VERSION 5.8 ;
BUSBITCHARS "[]" ;
DIVIDERCHAR "/" ;
UNITS
    DATABASE MICRONS 1000 ;
END UNITS

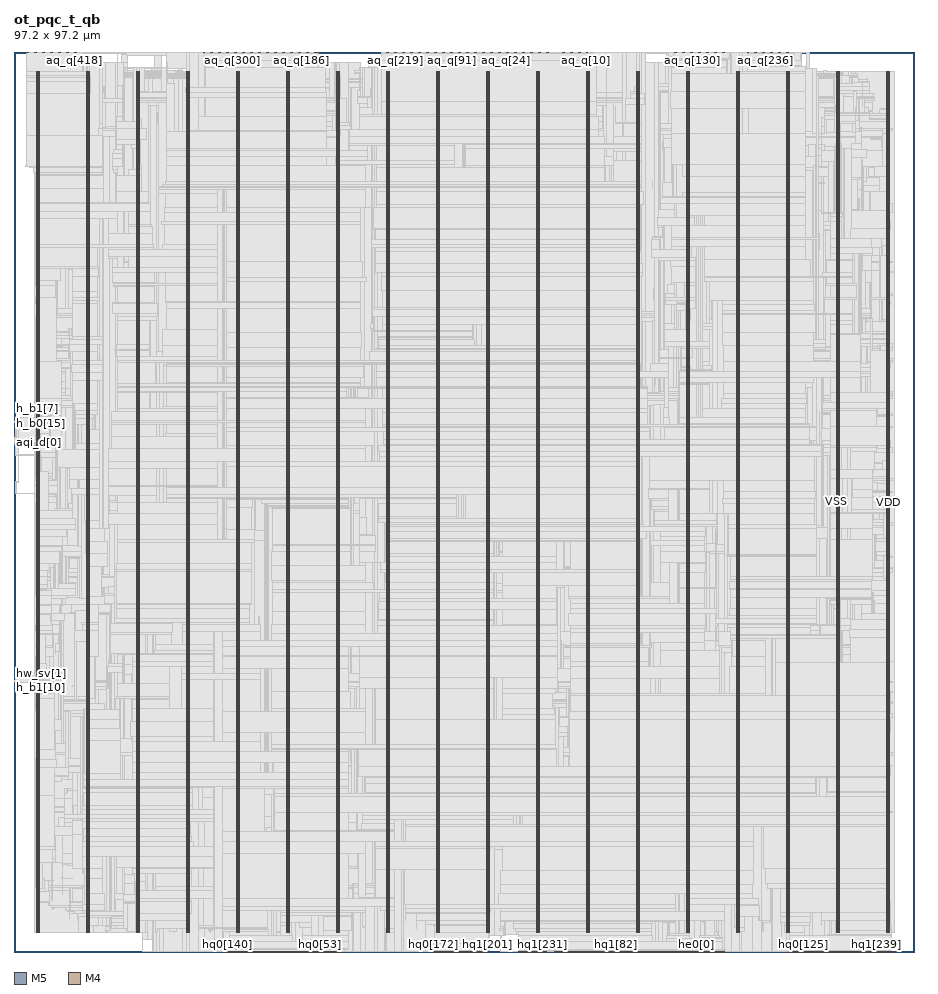
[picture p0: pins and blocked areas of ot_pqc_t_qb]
MACRO ot_pqc_t_qb
  FOREIGN ot_pqc_t_qb 0 0 ;
  CLASS BLOCK ;
  SIZE 97.2 BY 97.2 ;
  PIN aq_e[0]
    DIRECTION INPUT ;
    USE SIGNAL ;
    PORT
      LAYER M5 ;
        RECT  58.896 97.116 58.92 97.2 ;
    END
  END aq_e[0]
  PIN aq_e[10]
    DIRECTION INPUT ;
    USE SIGNAL ;
    PORT
      LAYER M5 ;
        RECT  59.856 97.116 59.88 97.2 ;
    END
  END aq_e[10]
  PIN aq_e[11]
    DIRECTION INPUT ;
    USE SIGNAL ;
    PORT
      LAYER M5 ;
        RECT  59.952 97.116 59.976 97.2 ;
    END
  END aq_e[11]
  PIN aq_e[12]
    DIRECTION INPUT ;
    USE SIGNAL ;
    PORT
      LAYER M5 ;
        RECT  60.048 97.116 60.072 97.2 ;
    END
  END aq_e[12]
  PIN aq_e[13]
    DIRECTION INPUT ;
    USE SIGNAL ;
    PORT
      LAYER M5 ;
        RECT  60.144 97.116 60.168 97.2 ;
    END
  END aq_e[13]
  PIN aq_e[14]
    DIRECTION INPUT ;
    USE SIGNAL ;
    PORT
      LAYER M5 ;
        RECT  60.24 97.116 60.264 97.2 ;
    END
  END aq_e[14]
  PIN aq_e[15]
    DIRECTION INPUT ;
    USE SIGNAL ;
    PORT
      LAYER M5 ;
        RECT  60.336 97.116 60.36 97.2 ;
    END
  END aq_e[15]
  PIN aq_e[16]
    DIRECTION INPUT ;
    USE SIGNAL ;
    PORT
      LAYER M5 ;
        RECT  60.432 97.116 60.456 97.2 ;
    END
  END aq_e[16]
  PIN aq_e[17]
    DIRECTION INPUT ;
    USE SIGNAL ;
    PORT
      LAYER M5 ;
        RECT  60.528 97.116 60.552 97.2 ;
    END
  END aq_e[17]
  PIN aq_e[18]
    DIRECTION INPUT ;
    USE SIGNAL ;
    PORT
      LAYER M5 ;
        RECT  60.624 97.116 60.648 97.2 ;
    END
  END aq_e[18]
  PIN aq_e[19]
    DIRECTION INPUT ;
    USE SIGNAL ;
    PORT
      LAYER M5 ;
        RECT  60.72 97.116 60.744 97.2 ;
    END
  END aq_e[19]
  PIN aq_e[1]
    DIRECTION INPUT ;
    USE SIGNAL ;
    PORT
      LAYER M5 ;
        RECT  58.992 97.116 59.016 97.2 ;
    END
  END aq_e[1]
  PIN aq_e[2]
    DIRECTION INPUT ;
    USE SIGNAL ;
    PORT
      LAYER M5 ;
        RECT  59.088 97.116 59.112 97.2 ;
    END
  END aq_e[2]
  PIN aq_e[3]
    DIRECTION INPUT ;
    USE SIGNAL ;
    PORT
      LAYER M5 ;
        RECT  59.184 97.116 59.208 97.2 ;
    END
  END aq_e[3]
  PIN aq_e[4]
    DIRECTION INPUT ;
    USE SIGNAL ;
    PORT
      LAYER M5 ;
        RECT  59.28 97.116 59.304 97.2 ;
    END
  END aq_e[4]
  PIN aq_e[5]
    DIRECTION INPUT ;
    USE SIGNAL ;
    PORT
      LAYER M5 ;
        RECT  59.376 97.116 59.4 97.2 ;
    END
  END aq_e[5]
  PIN aq_e[6]
    DIRECTION INPUT ;
    USE SIGNAL ;
    PORT
      LAYER M5 ;
        RECT  59.472 97.116 59.496 97.2 ;
    END
  END aq_e[6]
  PIN aq_e[7]
    DIRECTION INPUT ;
    USE SIGNAL ;
    PORT
      LAYER M5 ;
        RECT  59.568 97.116 59.592 97.2 ;
    END
  END aq_e[7]
  PIN aq_e[8]
    DIRECTION INPUT ;
    USE SIGNAL ;
    PORT
      LAYER M5 ;
        RECT  59.664 97.116 59.688 97.2 ;
    END
  END aq_e[8]
  PIN aq_e[9]
    DIRECTION INPUT ;
    USE SIGNAL ;
    PORT
      LAYER M5 ;
        RECT  59.76 97.116 59.784 97.2 ;
    END
  END aq_e[9]
  PIN aq_q[0]
    DIRECTION INPUT ;
    USE SIGNAL ;
    PORT
      LAYER M5 ;
        RECT  60.816 97.116 60.84 97.2 ;
    END
  END aq_q[0]
  PIN aq_q[100]
    DIRECTION INPUT ;
    USE SIGNAL ;
    PORT
      LAYER M5 ;
        RECT  48.144 97.116 48.168 97.2 ;
    END
  END aq_q[100]
  PIN aq_q[101]
    DIRECTION INPUT ;
    USE SIGNAL ;
    PORT
      LAYER M5 ;
        RECT  48.24 97.116 48.264 97.2 ;
    END
  END aq_q[101]
  PIN aq_q[102]
    DIRECTION INPUT ;
    USE SIGNAL ;
    PORT
      LAYER M5 ;
        RECT  48.336 97.116 48.36 97.2 ;
    END
  END aq_q[102]
  PIN aq_q[103]
    DIRECTION INPUT ;
    USE SIGNAL ;
    PORT
      LAYER M5 ;
        RECT  48.432 97.116 48.456 97.2 ;
    END
  END aq_q[103]
  PIN aq_q[104]
    DIRECTION INPUT ;
    USE SIGNAL ;
    PORT
      LAYER M5 ;
        RECT  48.528 97.116 48.552 97.2 ;
    END
  END aq_q[104]
  PIN aq_q[105]
    DIRECTION INPUT ;
    USE SIGNAL ;
    PORT
      LAYER M5 ;
        RECT  48.624 97.116 48.648 97.2 ;
    END
  END aq_q[105]
  PIN aq_q[106]
    DIRECTION INPUT ;
    USE SIGNAL ;
    PORT
      LAYER M5 ;
        RECT  48.72 97.116 48.744 97.2 ;
    END
  END aq_q[106]
  PIN aq_q[107]
    DIRECTION INPUT ;
    USE SIGNAL ;
    PORT
      LAYER M5 ;
        RECT  48.816 97.116 48.84 97.2 ;
    END
  END aq_q[107]
  PIN aq_q[108]
    DIRECTION INPUT ;
    USE SIGNAL ;
    PORT
      LAYER M5 ;
        RECT  71.184 97.116 71.208 97.2 ;
    END
  END aq_q[108]
  PIN aq_q[109]
    DIRECTION INPUT ;
    USE SIGNAL ;
    PORT
      LAYER M5 ;
        RECT  71.28 97.116 71.304 97.2 ;
    END
  END aq_q[109]
  PIN aq_q[10]
    DIRECTION INPUT ;
    USE SIGNAL ;
    PORT
      LAYER M5 ;
        RECT  61.776 97.116 61.8 97.2 ;
    END
  END aq_q[10]
  PIN aq_q[110]
    DIRECTION INPUT ;
    USE SIGNAL ;
    PORT
      LAYER M5 ;
        RECT  71.376 97.116 71.4 97.2 ;
    END
  END aq_q[110]
  PIN aq_q[111]
    DIRECTION INPUT ;
    USE SIGNAL ;
    PORT
      LAYER M5 ;
        RECT  71.472 97.116 71.496 97.2 ;
    END
  END aq_q[111]
  PIN aq_q[112]
    DIRECTION INPUT ;
    USE SIGNAL ;
    PORT
      LAYER M5 ;
        RECT  71.568 97.116 71.592 97.2 ;
    END
  END aq_q[112]
  PIN aq_q[113]
    DIRECTION INPUT ;
    USE SIGNAL ;
    PORT
      LAYER M5 ;
        RECT  71.664 97.116 71.688 97.2 ;
    END
  END aq_q[113]
  PIN aq_q[114]
    DIRECTION INPUT ;
    USE SIGNAL ;
    PORT
      LAYER M5 ;
        RECT  71.76 97.116 71.784 97.2 ;
    END
  END aq_q[114]
  PIN aq_q[115]
    DIRECTION INPUT ;
    USE SIGNAL ;
    PORT
      LAYER M5 ;
        RECT  71.856 97.116 71.88 97.2 ;
    END
  END aq_q[115]
  PIN aq_q[116]
    DIRECTION INPUT ;
    USE SIGNAL ;
    PORT
      LAYER M5 ;
        RECT  71.952 97.116 71.976 97.2 ;
    END
  END aq_q[116]
  PIN aq_q[117]
    DIRECTION INPUT ;
    USE SIGNAL ;
    PORT
      LAYER M5 ;
        RECT  72.048 97.116 72.072 97.2 ;
    END
  END aq_q[117]
  PIN aq_q[118]
    DIRECTION INPUT ;
    USE SIGNAL ;
    PORT
      LAYER M5 ;
        RECT  72.144 97.116 72.168 97.2 ;
    END
  END aq_q[118]
  PIN aq_q[119]
    DIRECTION INPUT ;
    USE SIGNAL ;
    PORT
      LAYER M5 ;
        RECT  72.24 97.116 72.264 97.2 ;
    END
  END aq_q[119]
  PIN aq_q[11]
    DIRECTION INPUT ;
    USE SIGNAL ;
    PORT
      LAYER M5 ;
        RECT  61.872 97.116 61.896 97.2 ;
    END
  END aq_q[11]
  PIN aq_q[120]
    DIRECTION INPUT ;
    USE SIGNAL ;
    PORT
      LAYER M5 ;
        RECT  72.336 97.116 72.36 97.2 ;
    END
  END aq_q[120]
  PIN aq_q[121]
    DIRECTION INPUT ;
    USE SIGNAL ;
    PORT
      LAYER M5 ;
        RECT  72.432 97.116 72.456 97.2 ;
    END
  END aq_q[121]
  PIN aq_q[122]
    DIRECTION INPUT ;
    USE SIGNAL ;
    PORT
      LAYER M5 ;
        RECT  72.528 97.116 72.552 97.2 ;
    END
  END aq_q[122]
  PIN aq_q[123]
    DIRECTION INPUT ;
    USE SIGNAL ;
    PORT
      LAYER M5 ;
        RECT  72.624 97.116 72.648 97.2 ;
    END
  END aq_q[123]
  PIN aq_q[124]
    DIRECTION INPUT ;
    USE SIGNAL ;
    PORT
      LAYER M5 ;
        RECT  72.72 97.116 72.744 97.2 ;
    END
  END aq_q[124]
  PIN aq_q[125]
    DIRECTION INPUT ;
    USE SIGNAL ;
    PORT
      LAYER M5 ;
        RECT  72.816 97.116 72.84 97.2 ;
    END
  END aq_q[125]
  PIN aq_q[126]
    DIRECTION INPUT ;
    USE SIGNAL ;
    PORT
      LAYER M5 ;
        RECT  72.912 97.116 72.936 97.2 ;
    END
  END aq_q[126]
  PIN aq_q[127]
    DIRECTION INPUT ;
    USE SIGNAL ;
    PORT
      LAYER M5 ;
        RECT  73.008 97.116 73.032 97.2 ;
    END
  END aq_q[127]
  PIN aq_q[128]
    DIRECTION INPUT ;
    USE SIGNAL ;
    PORT
      LAYER M5 ;
        RECT  73.104 97.116 73.128 97.2 ;
    END
  END aq_q[128]
  PIN aq_q[129]
    DIRECTION INPUT ;
    USE SIGNAL ;
    PORT
      LAYER M5 ;
        RECT  73.2 97.116 73.224 97.2 ;
    END
  END aq_q[129]
  PIN aq_q[12]
    DIRECTION INPUT ;
    USE SIGNAL ;
    PORT
      LAYER M5 ;
        RECT  51.984 97.116 52.008 97.2 ;
    END
  END aq_q[12]
  PIN aq_q[130]
    DIRECTION INPUT ;
    USE SIGNAL ;
    PORT
      LAYER M5 ;
        RECT  73.296 97.116 73.32 97.2 ;
    END
  END aq_q[130]
  PIN aq_q[131]
    DIRECTION INPUT ;
    USE SIGNAL ;
    PORT
      LAYER M5 ;
        RECT  73.392 97.116 73.416 97.2 ;
    END
  END aq_q[131]
  PIN aq_q[132]
    DIRECTION INPUT ;
    USE SIGNAL ;
    PORT
      LAYER M5 ;
        RECT  73.488 97.116 73.512 97.2 ;
    END
  END aq_q[132]
  PIN aq_q[133]
    DIRECTION INPUT ;
    USE SIGNAL ;
    PORT
      LAYER M5 ;
        RECT  73.584 97.116 73.608 97.2 ;
    END
  END aq_q[133]
  PIN aq_q[134]
    DIRECTION INPUT ;
    USE SIGNAL ;
    PORT
      LAYER M5 ;
        RECT  73.68 97.116 73.704 97.2 ;
    END
  END aq_q[134]
  PIN aq_q[135]
    DIRECTION INPUT ;
    USE SIGNAL ;
    PORT
      LAYER M5 ;
        RECT  73.776 97.116 73.8 97.2 ;
    END
  END aq_q[135]
  PIN aq_q[136]
    DIRECTION INPUT ;
    USE SIGNAL ;
    PORT
      LAYER M5 ;
        RECT  73.872 97.116 73.896 97.2 ;
    END
  END aq_q[136]
  PIN aq_q[137]
    DIRECTION INPUT ;
    USE SIGNAL ;
    PORT
      LAYER M5 ;
        RECT  73.968 97.116 73.992 97.2 ;
    END
  END aq_q[137]
  PIN aq_q[138]
    DIRECTION INPUT ;
    USE SIGNAL ;
    PORT
      LAYER M5 ;
        RECT  74.064 97.116 74.088 97.2 ;
    END
  END aq_q[138]
  PIN aq_q[139]
    DIRECTION INPUT ;
    USE SIGNAL ;
    PORT
      LAYER M5 ;
        RECT  74.16 97.116 74.184 97.2 ;
    END
  END aq_q[139]
  PIN aq_q[13]
    DIRECTION INPUT ;
    USE SIGNAL ;
    PORT
      LAYER M5 ;
        RECT  52.08 97.116 52.104 97.2 ;
    END
  END aq_q[13]
  PIN aq_q[140]
    DIRECTION INPUT ;
    USE SIGNAL ;
    PORT
      LAYER M5 ;
        RECT  1.296 97.116 1.32 97.2 ;
    END
  END aq_q[140]
  PIN aq_q[141]
    DIRECTION INPUT ;
    USE SIGNAL ;
    PORT
      LAYER M5 ;
        RECT  1.392 97.116 1.416 97.2 ;
    END
  END aq_q[141]
  PIN aq_q[142]
    DIRECTION INPUT ;
    USE SIGNAL ;
    PORT
      LAYER M5 ;
        RECT  1.488 97.116 1.512 97.2 ;
    END
  END aq_q[142]
  PIN aq_q[143]
    DIRECTION INPUT ;
    USE SIGNAL ;
    PORT
      LAYER M5 ;
        RECT  1.584 97.116 1.608 97.2 ;
    END
  END aq_q[143]
  PIN aq_q[144]
    DIRECTION INPUT ;
    USE SIGNAL ;
    PORT
      LAYER M5 ;
        RECT  1.68 97.116 1.704 97.2 ;
    END
  END aq_q[144]
  PIN aq_q[145]
    DIRECTION INPUT ;
    USE SIGNAL ;
    PORT
      LAYER M5 ;
        RECT  1.776 97.116 1.8 97.2 ;
    END
  END aq_q[145]
  PIN aq_q[146]
    DIRECTION INPUT ;
    USE SIGNAL ;
    PORT
      LAYER M5 ;
        RECT  1.872 97.116 1.896 97.2 ;
    END
  END aq_q[146]
  PIN aq_q[147]
    DIRECTION INPUT ;
    USE SIGNAL ;
    PORT
      LAYER M5 ;
        RECT  1.968 97.116 1.992 97.2 ;
    END
  END aq_q[147]
  PIN aq_q[148]
    DIRECTION INPUT ;
    USE SIGNAL ;
    PORT
      LAYER M5 ;
        RECT  2.064 97.116 2.088 97.2 ;
    END
  END aq_q[148]
  PIN aq_q[149]
    DIRECTION INPUT ;
    USE SIGNAL ;
    PORT
      LAYER M5 ;
        RECT  2.16 97.116 2.184 97.2 ;
    END
  END aq_q[149]
  PIN aq_q[14]
    DIRECTION INPUT ;
    USE SIGNAL ;
    PORT
      LAYER M5 ;
        RECT  52.176 97.116 52.2 97.2 ;
    END
  END aq_q[14]
  PIN aq_q[150]
    DIRECTION INPUT ;
    USE SIGNAL ;
    PORT
      LAYER M5 ;
        RECT  2.256 97.116 2.28 97.2 ;
    END
  END aq_q[150]
  PIN aq_q[151]
    DIRECTION INPUT ;
    USE SIGNAL ;
    PORT
      LAYER M5 ;
        RECT  2.352 97.116 2.376 97.2 ;
    END
  END aq_q[151]
  PIN aq_q[152]
    DIRECTION INPUT ;
    USE SIGNAL ;
    PORT
      LAYER M5 ;
        RECT  2.448 97.116 2.472 97.2 ;
    END
  END aq_q[152]
  PIN aq_q[153]
    DIRECTION INPUT ;
    USE SIGNAL ;
    PORT
      LAYER M5 ;
        RECT  2.544 97.116 2.568 97.2 ;
    END
  END aq_q[153]
  PIN aq_q[154]
    DIRECTION INPUT ;
    USE SIGNAL ;
    PORT
      LAYER M5 ;
        RECT  2.64 97.116 2.664 97.2 ;
    END
  END aq_q[154]
  PIN aq_q[155]
    DIRECTION INPUT ;
    USE SIGNAL ;
    PORT
      LAYER M5 ;
        RECT  2.736 97.116 2.76 97.2 ;
    END
  END aq_q[155]
  PIN aq_q[156]
    DIRECTION INPUT ;
    USE SIGNAL ;
    PORT
      LAYER M5 ;
        RECT  2.832 97.116 2.856 97.2 ;
    END
  END aq_q[156]
  PIN aq_q[157]
    DIRECTION INPUT ;
    USE SIGNAL ;
    PORT
      LAYER M5 ;
        RECT  2.928 97.116 2.952 97.2 ;
    END
  END aq_q[157]
  PIN aq_q[158]
    DIRECTION INPUT ;
    USE SIGNAL ;
    PORT
      LAYER M5 ;
        RECT  3.024 97.116 3.048 97.2 ;
    END
  END aq_q[158]
  PIN aq_q[159]
    DIRECTION INPUT ;
    USE SIGNAL ;
    PORT
      LAYER M5 ;
        RECT  3.12 97.116 3.144 97.2 ;
    END
  END aq_q[159]
  PIN aq_q[15]
    DIRECTION INPUT ;
    USE SIGNAL ;
    PORT
      LAYER M5 ;
        RECT  52.272 97.116 52.296 97.2 ;
    END
  END aq_q[15]
  PIN aq_q[160]
    DIRECTION INPUT ;
    USE SIGNAL ;
    PORT
      LAYER M5 ;
        RECT  3.216 97.116 3.24 97.2 ;
    END
  END aq_q[160]
  PIN aq_q[161]
    DIRECTION INPUT ;
    USE SIGNAL ;
    PORT
      LAYER M5 ;
        RECT  3.312 97.116 3.336 97.2 ;
    END
  END aq_q[161]
  PIN aq_q[162]
    DIRECTION INPUT ;
    USE SIGNAL ;
    PORT
      LAYER M5 ;
        RECT  3.408 97.116 3.432 97.2 ;
    END
  END aq_q[162]
  PIN aq_q[163]
    DIRECTION INPUT ;
    USE SIGNAL ;
    PORT
      LAYER M5 ;
        RECT  3.504 97.116 3.528 97.2 ;
    END
  END aq_q[163]
  PIN aq_q[164]
    DIRECTION INPUT ;
    USE SIGNAL ;
    PORT
      LAYER M5 ;
        RECT  3.6 97.116 3.624 97.2 ;
    END
  END aq_q[164]
  PIN aq_q[165]
    DIRECTION INPUT ;
    USE SIGNAL ;
    PORT
      LAYER M5 ;
        RECT  3.696 97.116 3.72 97.2 ;
    END
  END aq_q[165]
  PIN aq_q[166]
    DIRECTION INPUT ;
    USE SIGNAL ;
    PORT
      LAYER M5 ;
        RECT  3.792 97.116 3.816 97.2 ;
    END
  END aq_q[166]
  PIN aq_q[167]
    DIRECTION INPUT ;
    USE SIGNAL ;
    PORT
      LAYER M5 ;
        RECT  3.888 97.116 3.912 97.2 ;
    END
  END aq_q[167]
  PIN aq_q[168]
    DIRECTION INPUT ;
    USE SIGNAL ;
    PORT
      LAYER M5 ;
        RECT  3.984 97.116 4.008 97.2 ;
    END
  END aq_q[168]
  PIN aq_q[169]
    DIRECTION INPUT ;
    USE SIGNAL ;
    PORT
      LAYER M5 ;
        RECT  4.08 97.116 4.104 97.2 ;
    END
  END aq_q[169]
  PIN aq_q[16]
    DIRECTION INPUT ;
    USE SIGNAL ;
    PORT
      LAYER M5 ;
        RECT  52.368 97.116 52.392 97.2 ;
    END
  END aq_q[16]
  PIN aq_q[170]
    DIRECTION INPUT ;
    USE SIGNAL ;
    PORT
      LAYER M5 ;
        RECT  4.176 97.116 4.2 97.2 ;
    END
  END aq_q[170]
  PIN aq_q[171]
    DIRECTION INPUT ;
    USE SIGNAL ;
    PORT
      LAYER M5 ;
        RECT  4.272 97.116 4.296 97.2 ;
    END
  END aq_q[171]
  PIN aq_q[172]
    DIRECTION INPUT ;
    USE SIGNAL ;
    PORT
      LAYER M5 ;
        RECT  29.712 97.116 29.736 97.2 ;
    END
  END aq_q[172]
  PIN aq_q[173]
    DIRECTION INPUT ;
    USE SIGNAL ;
    PORT
      LAYER M5 ;
        RECT  29.808 97.116 29.832 97.2 ;
    END
  END aq_q[173]
  PIN aq_q[174]
    DIRECTION INPUT ;
    USE SIGNAL ;
    PORT
      LAYER M5 ;
        RECT  29.904 97.116 29.928 97.2 ;
    END
  END aq_q[174]
  PIN aq_q[175]
    DIRECTION INPUT ;
    USE SIGNAL ;
    PORT
      LAYER M5 ;
        RECT  30 97.116 30.024 97.2 ;
    END
  END aq_q[175]
  PIN aq_q[176]
    DIRECTION INPUT ;
    USE SIGNAL ;
    PORT
      LAYER M5 ;
        RECT  30.096 97.116 30.12 97.2 ;
    END
  END aq_q[176]
  PIN aq_q[177]
    DIRECTION INPUT ;
    USE SIGNAL ;
    PORT
      LAYER M5 ;
        RECT  30.192 97.116 30.216 97.2 ;
    END
  END aq_q[177]
  PIN aq_q[178]
    DIRECTION INPUT ;
    USE SIGNAL ;
    PORT
      LAYER M5 ;
        RECT  30.288 97.116 30.312 97.2 ;
    END
  END aq_q[178]
  PIN aq_q[179]
    DIRECTION INPUT ;
    USE SIGNAL ;
    PORT
      LAYER M5 ;
        RECT  30.384 97.116 30.408 97.2 ;
    END
  END aq_q[179]
  PIN aq_q[17]
    DIRECTION INPUT ;
    USE SIGNAL ;
    PORT
      LAYER M5 ;
        RECT  52.464 97.116 52.488 97.2 ;
    END
  END aq_q[17]
  PIN aq_q[180]
    DIRECTION INPUT ;
    USE SIGNAL ;
    PORT
      LAYER M5 ;
        RECT  30.48 97.116 30.504 97.2 ;
    END
  END aq_q[180]
  PIN aq_q[181]
    DIRECTION INPUT ;
    USE SIGNAL ;
    PORT
      LAYER M5 ;
        RECT  30.576 97.116 30.6 97.2 ;
    END
  END aq_q[181]
  PIN aq_q[182]
    DIRECTION INPUT ;
    USE SIGNAL ;
    PORT
      LAYER M5 ;
        RECT  30.672 97.116 30.696 97.2 ;
    END
  END aq_q[182]
  PIN aq_q[183]
    DIRECTION INPUT ;
    USE SIGNAL ;
    PORT
      LAYER M5 ;
        RECT  30.768 97.116 30.792 97.2 ;
    END
  END aq_q[183]
  PIN aq_q[184]
    DIRECTION INPUT ;
    USE SIGNAL ;
    PORT
      LAYER M5 ;
        RECT  30.864 97.116 30.888 97.2 ;
    END
  END aq_q[184]
  PIN aq_q[185]
    DIRECTION INPUT ;
    USE SIGNAL ;
    PORT
      LAYER M5 ;
        RECT  30.96 97.116 30.984 97.2 ;
    END
  END aq_q[185]
  PIN aq_q[186]
    DIRECTION INPUT ;
    USE SIGNAL ;
    PORT
      LAYER M5 ;
        RECT  31.056 97.116 31.08 97.2 ;
    END
  END aq_q[186]
  PIN aq_q[187]
    DIRECTION INPUT ;
    USE SIGNAL ;
    PORT
      LAYER M5 ;
        RECT  31.152 97.116 31.176 97.2 ;
    END
  END aq_q[187]
  PIN aq_q[188]
    DIRECTION INPUT ;
    USE SIGNAL ;
    PORT
      LAYER M5 ;
        RECT  31.248 97.116 31.272 97.2 ;
    END
  END aq_q[188]
  PIN aq_q[189]
    DIRECTION INPUT ;
    USE SIGNAL ;
    PORT
      LAYER M5 ;
        RECT  31.344 97.116 31.368 97.2 ;
    END
  END aq_q[189]
  PIN aq_q[18]
    DIRECTION INPUT ;
    USE SIGNAL ;
    PORT
      LAYER M5 ;
        RECT  52.56 97.116 52.584 97.2 ;
    END
  END aq_q[18]
  PIN aq_q[190]
    DIRECTION INPUT ;
    USE SIGNAL ;
    PORT
      LAYER M5 ;
        RECT  31.44 97.116 31.464 97.2 ;
    END
  END aq_q[190]
  PIN aq_q[191]
    DIRECTION INPUT ;
    USE SIGNAL ;
    PORT
      LAYER M5 ;
        RECT  31.536 97.116 31.56 97.2 ;
    END
  END aq_q[191]
  PIN aq_q[192]
    DIRECTION INPUT ;
    USE SIGNAL ;
    PORT
      LAYER M5 ;
        RECT  31.632 97.116 31.656 97.2 ;
    END
  END aq_q[192]
  PIN aq_q[193]
    DIRECTION INPUT ;
    USE SIGNAL ;
    PORT
      LAYER M5 ;
        RECT  31.728 97.116 31.752 97.2 ;
    END
  END aq_q[193]
  PIN aq_q[194]
    DIRECTION INPUT ;
    USE SIGNAL ;
    PORT
      LAYER M5 ;
        RECT  31.824 97.116 31.848 97.2 ;
    END
  END aq_q[194]
  PIN aq_q[195]
    DIRECTION INPUT ;
    USE SIGNAL ;
    PORT
      LAYER M5 ;
        RECT  31.92 97.116 31.944 97.2 ;
    END
  END aq_q[195]
  PIN aq_q[196]
    DIRECTION INPUT ;
    USE SIGNAL ;
    PORT
      LAYER M5 ;
        RECT  32.016 97.116 32.04 97.2 ;
    END
  END aq_q[196]
  PIN aq_q[197]
    DIRECTION INPUT ;
    USE SIGNAL ;
    PORT
      LAYER M5 ;
        RECT  32.112 97.116 32.136 97.2 ;
    END
  END aq_q[197]
  PIN aq_q[198]
    DIRECTION INPUT ;
    USE SIGNAL ;
    PORT
      LAYER M5 ;
        RECT  32.208 97.116 32.232 97.2 ;
    END
  END aq_q[198]
  PIN aq_q[199]
    DIRECTION INPUT ;
    USE SIGNAL ;
    PORT
      LAYER M5 ;
        RECT  32.304 97.116 32.328 97.2 ;
    END
  END aq_q[199]
  PIN aq_q[19]
    DIRECTION INPUT ;
    USE SIGNAL ;
    PORT
      LAYER M5 ;
        RECT  52.656 97.116 52.68 97.2 ;
    END
  END aq_q[19]
  PIN aq_q[1]
    DIRECTION INPUT ;
    USE SIGNAL ;
    PORT
      LAYER M5 ;
        RECT  60.912 97.116 60.936 97.2 ;
    END
  END aq_q[1]
  PIN aq_q[200]
    DIRECTION INPUT ;
    USE SIGNAL ;
    PORT
      LAYER M5 ;
        RECT  32.4 97.116 32.424 97.2 ;
    END
  END aq_q[200]
  PIN aq_q[201]
    DIRECTION INPUT ;
    USE SIGNAL ;
    PORT
      LAYER M5 ;
        RECT  32.496 97.116 32.52 97.2 ;
    END
  END aq_q[201]
  PIN aq_q[202]
    DIRECTION INPUT ;
    USE SIGNAL ;
    PORT
      LAYER M5 ;
        RECT  32.592 97.116 32.616 97.2 ;
    END
  END aq_q[202]
  PIN aq_q[203]
    DIRECTION INPUT ;
    USE SIGNAL ;
    PORT
      LAYER M5 ;
        RECT  32.688 97.116 32.712 97.2 ;
    END
  END aq_q[203]
  PIN aq_q[204]
    DIRECTION INPUT ;
    USE SIGNAL ;
    PORT
      LAYER M5 ;
        RECT  39.696 97.116 39.72 97.2 ;
    END
  END aq_q[204]
  PIN aq_q[205]
    DIRECTION INPUT ;
    USE SIGNAL ;
    PORT
      LAYER M5 ;
        RECT  39.792 97.116 39.816 97.2 ;
    END
  END aq_q[205]
  PIN aq_q[206]
    DIRECTION INPUT ;
    USE SIGNAL ;
    PORT
      LAYER M5 ;
        RECT  39.888 97.116 39.912 97.2 ;
    END
  END aq_q[206]
  PIN aq_q[207]
    DIRECTION INPUT ;
    USE SIGNAL ;
    PORT
      LAYER M5 ;
        RECT  39.984 97.116 40.008 97.2 ;
    END
  END aq_q[207]
  PIN aq_q[208]
    DIRECTION INPUT ;
    USE SIGNAL ;
    PORT
      LAYER M5 ;
        RECT  40.08 97.116 40.104 97.2 ;
    END
  END aq_q[208]
  PIN aq_q[209]
    DIRECTION INPUT ;
    USE SIGNAL ;
    PORT
      LAYER M5 ;
        RECT  40.176 97.116 40.2 97.2 ;
    END
  END aq_q[209]
  PIN aq_q[20]
    DIRECTION INPUT ;
    USE SIGNAL ;
    PORT
      LAYER M5 ;
        RECT  52.752 97.116 52.776 97.2 ;
    END
  END aq_q[20]
  PIN aq_q[210]
    DIRECTION INPUT ;
    USE SIGNAL ;
    PORT
      LAYER M5 ;
        RECT  40.272 97.116 40.296 97.2 ;
    END
  END aq_q[210]
  PIN aq_q[211]
    DIRECTION INPUT ;
    USE SIGNAL ;
    PORT
      LAYER M5 ;
        RECT  40.368 97.116 40.392 97.2 ;
    END
  END aq_q[211]
  PIN aq_q[212]
    DIRECTION INPUT ;
    USE SIGNAL ;
    PORT
      LAYER M5 ;
        RECT  40.464 97.116 40.488 97.2 ;
    END
  END aq_q[212]
  PIN aq_q[213]
    DIRECTION INPUT ;
    USE SIGNAL ;
    PORT
      LAYER M5 ;
        RECT  40.56 97.116 40.584 97.2 ;
    END
  END aq_q[213]
  PIN aq_q[214]
    DIRECTION INPUT ;
    USE SIGNAL ;
    PORT
      LAYER M5 ;
        RECT  40.656 97.116 40.68 97.2 ;
    END
  END aq_q[214]
  PIN aq_q[215]
    DIRECTION INPUT ;
    USE SIGNAL ;
    PORT
      LAYER M5 ;
        RECT  40.752 97.116 40.776 97.2 ;
    END
  END aq_q[215]
  PIN aq_q[216]
    DIRECTION INPUT ;
    USE SIGNAL ;
    PORT
      LAYER M5 ;
        RECT  40.848 97.116 40.872 97.2 ;
    END
  END aq_q[216]
  PIN aq_q[217]
    DIRECTION INPUT ;
    USE SIGNAL ;
    PORT
      LAYER M5 ;
        RECT  40.944 97.116 40.968 97.2 ;
    END
  END aq_q[217]
  PIN aq_q[218]
    DIRECTION INPUT ;
    USE SIGNAL ;
    PORT
      LAYER M5 ;
        RECT  41.04 97.116 41.064 97.2 ;
    END
  END aq_q[218]
  PIN aq_q[219]
    DIRECTION INPUT ;
    USE SIGNAL ;
    PORT
      LAYER M5 ;
        RECT  41.136 97.116 41.16 97.2 ;
    END
  END aq_q[219]
  PIN aq_q[21]
    DIRECTION INPUT ;
    USE SIGNAL ;
    PORT
      LAYER M5 ;
        RECT  52.848 97.116 52.872 97.2 ;
    END
  END aq_q[21]
  PIN aq_q[220]
    DIRECTION INPUT ;
    USE SIGNAL ;
    PORT
      LAYER M5 ;
        RECT  41.232 97.116 41.256 97.2 ;
    END
  END aq_q[220]
  PIN aq_q[221]
    DIRECTION INPUT ;
    USE SIGNAL ;
    PORT
      LAYER M5 ;
        RECT  41.328 97.116 41.352 97.2 ;
    END
  END aq_q[221]
  PIN aq_q[222]
    DIRECTION INPUT ;
    USE SIGNAL ;
    PORT
      LAYER M5 ;
        RECT  41.424 97.116 41.448 97.2 ;
    END
  END aq_q[222]
  PIN aq_q[223]
    DIRECTION INPUT ;
    USE SIGNAL ;
    PORT
      LAYER M5 ;
        RECT  41.52 97.116 41.544 97.2 ;
    END
  END aq_q[223]
  PIN aq_q[224]
    DIRECTION INPUT ;
    USE SIGNAL ;
    PORT
      LAYER M5 ;
        RECT  41.616 97.116 41.64 97.2 ;
    END
  END aq_q[224]
  PIN aq_q[225]
    DIRECTION INPUT ;
    USE SIGNAL ;
    PORT
      LAYER M5 ;
        RECT  41.712 97.116 41.736 97.2 ;
    END
  END aq_q[225]
  PIN aq_q[226]
    DIRECTION INPUT ;
    USE SIGNAL ;
    PORT
      LAYER M5 ;
        RECT  41.808 97.116 41.832 97.2 ;
    END
  END aq_q[226]
  PIN aq_q[227]
    DIRECTION INPUT ;
    USE SIGNAL ;
    PORT
      LAYER M5 ;
        RECT  41.904 97.116 41.928 97.2 ;
    END
  END aq_q[227]
  PIN aq_q[228]
    DIRECTION INPUT ;
    USE SIGNAL ;
    PORT
      LAYER M5 ;
        RECT  42 97.116 42.024 97.2 ;
    END
  END aq_q[228]
  PIN aq_q[229]
    DIRECTION INPUT ;
    USE SIGNAL ;
    PORT
      LAYER M5 ;
        RECT  42.096 97.116 42.12 97.2 ;
    END
  END aq_q[229]
  PIN aq_q[22]
    DIRECTION INPUT ;
    USE SIGNAL ;
    PORT
      LAYER M5 ;
        RECT  52.944 97.116 52.968 97.2 ;
    END
  END aq_q[22]
  PIN aq_q[230]
    DIRECTION INPUT ;
    USE SIGNAL ;
    PORT
      LAYER M5 ;
        RECT  42.192 97.116 42.216 97.2 ;
    END
  END aq_q[230]
  PIN aq_q[231]
    DIRECTION INPUT ;
    USE SIGNAL ;
    PORT
      LAYER M5 ;
        RECT  42.288 97.116 42.312 97.2 ;
    END
  END aq_q[231]
  PIN aq_q[232]
    DIRECTION INPUT ;
    USE SIGNAL ;
    PORT
      LAYER M5 ;
        RECT  42.384 97.116 42.408 97.2 ;
    END
  END aq_q[232]
  PIN aq_q[233]
    DIRECTION INPUT ;
    USE SIGNAL ;
    PORT
      LAYER M5 ;
        RECT  42.48 97.116 42.504 97.2 ;
    END
  END aq_q[233]
  PIN aq_q[234]
    DIRECTION INPUT ;
    USE SIGNAL ;
    PORT
      LAYER M5 ;
        RECT  42.576 97.116 42.6 97.2 ;
    END
  END aq_q[234]
  PIN aq_q[235]
    DIRECTION INPUT ;
    USE SIGNAL ;
    PORT
      LAYER M5 ;
        RECT  42.672 97.116 42.696 97.2 ;
    END
  END aq_q[235]
  PIN aq_q[236]
    DIRECTION INPUT ;
    USE SIGNAL ;
    PORT
      LAYER M5 ;
        RECT  81.168 97.116 81.192 97.2 ;
    END
  END aq_q[236]
  PIN aq_q[237]
    DIRECTION INPUT ;
    USE SIGNAL ;
    PORT
      LAYER M5 ;
        RECT  81.264 97.116 81.288 97.2 ;
    END
  END aq_q[237]
  PIN aq_q[238]
    DIRECTION INPUT ;
    USE SIGNAL ;
    PORT
      LAYER M5 ;
        RECT  81.36 97.116 81.384 97.2 ;
    END
  END aq_q[238]
  PIN aq_q[239]
    DIRECTION INPUT ;
    USE SIGNAL ;
    PORT
      LAYER M5 ;
        RECT  81.456 97.116 81.48 97.2 ;
    END
  END aq_q[239]
  PIN aq_q[23]
    DIRECTION INPUT ;
    USE SIGNAL ;
    PORT
      LAYER M5 ;
        RECT  53.04 97.116 53.064 97.2 ;
    END
  END aq_q[23]
  PIN aq_q[240]
    DIRECTION INPUT ;
    USE SIGNAL ;
    PORT
      LAYER M5 ;
        RECT  81.552 97.116 81.576 97.2 ;
    END
  END aq_q[240]
  PIN aq_q[241]
    DIRECTION INPUT ;
    USE SIGNAL ;
    PORT
      LAYER M5 ;
        RECT  81.648 97.116 81.672 97.2 ;
    END
  END aq_q[241]
  PIN aq_q[242]
    DIRECTION INPUT ;
    USE SIGNAL ;
    PORT
      LAYER M5 ;
        RECT  81.744 97.116 81.768 97.2 ;
    END
  END aq_q[242]
  PIN aq_q[243]
    DIRECTION INPUT ;
    USE SIGNAL ;
    PORT
      LAYER M5 ;
        RECT  81.84 97.116 81.864 97.2 ;
    END
  END aq_q[243]
  PIN aq_q[244]
    DIRECTION INPUT ;
    USE SIGNAL ;
    PORT
      LAYER M5 ;
        RECT  81.936 97.116 81.96 97.2 ;
    END
  END aq_q[244]
  PIN aq_q[245]
    DIRECTION INPUT ;
    USE SIGNAL ;
    PORT
      LAYER M5 ;
        RECT  82.032 97.116 82.056 97.2 ;
    END
  END aq_q[245]
  PIN aq_q[246]
    DIRECTION INPUT ;
    USE SIGNAL ;
    PORT
      LAYER M5 ;
        RECT  82.128 97.116 82.152 97.2 ;
    END
  END aq_q[246]
  PIN aq_q[247]
    DIRECTION INPUT ;
    USE SIGNAL ;
    PORT
      LAYER M5 ;
        RECT  82.224 97.116 82.248 97.2 ;
    END
  END aq_q[247]
  PIN aq_q[248]
    DIRECTION INPUT ;
    USE SIGNAL ;
    PORT
      LAYER M5 ;
        RECT  82.32 97.116 82.344 97.2 ;
    END
  END aq_q[248]
  PIN aq_q[249]
    DIRECTION INPUT ;
    USE SIGNAL ;
    PORT
      LAYER M5 ;
        RECT  82.416 97.116 82.44 97.2 ;
    END
  END aq_q[249]
  PIN aq_q[24]
    DIRECTION INPUT ;
    USE SIGNAL ;
    PORT
      LAYER M5 ;
        RECT  53.136 97.116 53.16 97.2 ;
    END
  END aq_q[24]
  PIN aq_q[250]
    DIRECTION INPUT ;
    USE SIGNAL ;
    PORT
      LAYER M5 ;
        RECT  82.512 97.116 82.536 97.2 ;
    END
  END aq_q[250]
  PIN aq_q[251]
    DIRECTION INPUT ;
    USE SIGNAL ;
    PORT
      LAYER M5 ;
        RECT  82.608 97.116 82.632 97.2 ;
    END
  END aq_q[251]
  PIN aq_q[252]
    DIRECTION INPUT ;
    USE SIGNAL ;
    PORT
      LAYER M5 ;
        RECT  82.704 97.116 82.728 97.2 ;
    END
  END aq_q[252]
  PIN aq_q[253]
    DIRECTION INPUT ;
    USE SIGNAL ;
    PORT
      LAYER M5 ;
        RECT  82.8 97.116 82.824 97.2 ;
    END
  END aq_q[253]
  PIN aq_q[254]
    DIRECTION INPUT ;
    USE SIGNAL ;
    PORT
      LAYER M5 ;
        RECT  82.896 97.116 82.92 97.2 ;
    END
  END aq_q[254]
  PIN aq_q[255]
    DIRECTION INPUT ;
    USE SIGNAL ;
    PORT
      LAYER M5 ;
        RECT  82.992 97.116 83.016 97.2 ;
    END
  END aq_q[255]
  PIN aq_q[256]
    DIRECTION INPUT ;
    USE SIGNAL ;
    PORT
      LAYER M5 ;
        RECT  83.088 97.116 83.112 97.2 ;
    END
  END aq_q[256]
  PIN aq_q[257]
    DIRECTION INPUT ;
    USE SIGNAL ;
    PORT
      LAYER M5 ;
        RECT  83.184 97.116 83.208 97.2 ;
    END
  END aq_q[257]
  PIN aq_q[258]
    DIRECTION INPUT ;
    USE SIGNAL ;
    PORT
      LAYER M5 ;
        RECT  83.28 97.116 83.304 97.2 ;
    END
  END aq_q[258]
  PIN aq_q[259]
    DIRECTION INPUT ;
    USE SIGNAL ;
    PORT
      LAYER M5 ;
        RECT  83.376 97.116 83.4 97.2 ;
    END
  END aq_q[259]
  PIN aq_q[25]
    DIRECTION INPUT ;
    USE SIGNAL ;
    PORT
      LAYER M5 ;
        RECT  53.232 97.116 53.256 97.2 ;
    END
  END aq_q[25]
  PIN aq_q[260]
    DIRECTION INPUT ;
    USE SIGNAL ;
    PORT
      LAYER M5 ;
        RECT  83.472 97.116 83.496 97.2 ;
    END
  END aq_q[260]
  PIN aq_q[261]
    DIRECTION INPUT ;
    USE SIGNAL ;
    PORT
      LAYER M5 ;
        RECT  83.568 97.116 83.592 97.2 ;
    END
  END aq_q[261]
  PIN aq_q[262]
    DIRECTION INPUT ;
    USE SIGNAL ;
    PORT
      LAYER M5 ;
        RECT  83.664 97.116 83.688 97.2 ;
    END
  END aq_q[262]
  PIN aq_q[263]
    DIRECTION INPUT ;
    USE SIGNAL ;
    PORT
      LAYER M5 ;
        RECT  83.76 97.116 83.784 97.2 ;
    END
  END aq_q[263]
  PIN aq_q[264]
    DIRECTION INPUT ;
    USE SIGNAL ;
    PORT
      LAYER M5 ;
        RECT  83.856 97.116 83.88 97.2 ;
    END
  END aq_q[264]
  PIN aq_q[265]
    DIRECTION INPUT ;
    USE SIGNAL ;
    PORT
      LAYER M5 ;
        RECT  83.952 97.116 83.976 97.2 ;
    END
  END aq_q[265]
  PIN aq_q[266]
    DIRECTION INPUT ;
    USE SIGNAL ;
    PORT
      LAYER M5 ;
        RECT  84.048 97.116 84.072 97.2 ;
    END
  END aq_q[266]
  PIN aq_q[267]
    DIRECTION INPUT ;
    USE SIGNAL ;
    PORT
      LAYER M5 ;
        RECT  84.144 97.116 84.168 97.2 ;
    END
  END aq_q[267]
  PIN aq_q[268]
    DIRECTION INPUT ;
    USE SIGNAL ;
    PORT
      LAYER M5 ;
        RECT  55.056 97.116 55.08 97.2 ;
    END
  END aq_q[268]
  PIN aq_q[269]
    DIRECTION INPUT ;
    USE SIGNAL ;
    PORT
      LAYER M5 ;
        RECT  55.152 97.116 55.176 97.2 ;
    END
  END aq_q[269]
  PIN aq_q[26]
    DIRECTION INPUT ;
    USE SIGNAL ;
    PORT
      LAYER M5 ;
        RECT  53.328 97.116 53.352 97.2 ;
    END
  END aq_q[26]
  PIN aq_q[270]
    DIRECTION INPUT ;
    USE SIGNAL ;
    PORT
      LAYER M5 ;
        RECT  55.248 97.116 55.272 97.2 ;
    END
  END aq_q[270]
  PIN aq_q[271]
    DIRECTION INPUT ;
    USE SIGNAL ;
    PORT
      LAYER M5 ;
        RECT  55.344 97.116 55.368 97.2 ;
    END
  END aq_q[271]
  PIN aq_q[272]
    DIRECTION INPUT ;
    USE SIGNAL ;
    PORT
      LAYER M5 ;
        RECT  55.44 97.116 55.464 97.2 ;
    END
  END aq_q[272]
  PIN aq_q[273]
    DIRECTION INPUT ;
    USE SIGNAL ;
    PORT
      LAYER M5 ;
        RECT  55.536 97.116 55.56 97.2 ;
    END
  END aq_q[273]
  PIN aq_q[274]
    DIRECTION INPUT ;
    USE SIGNAL ;
    PORT
      LAYER M5 ;
        RECT  55.632 97.116 55.656 97.2 ;
    END
  END aq_q[274]
  PIN aq_q[275]
    DIRECTION INPUT ;
    USE SIGNAL ;
    PORT
      LAYER M5 ;
        RECT  55.728 97.116 55.752 97.2 ;
    END
  END aq_q[275]
  PIN aq_q[276]
    DIRECTION INPUT ;
    USE SIGNAL ;
    PORT
      LAYER M5 ;
        RECT  55.824 97.116 55.848 97.2 ;
    END
  END aq_q[276]
  PIN aq_q[277]
    DIRECTION INPUT ;
    USE SIGNAL ;
    PORT
      LAYER M5 ;
        RECT  55.92 97.116 55.944 97.2 ;
    END
  END aq_q[277]
  PIN aq_q[278]
    DIRECTION INPUT ;
    USE SIGNAL ;
    PORT
      LAYER M5 ;
        RECT  56.016 97.116 56.04 97.2 ;
    END
  END aq_q[278]
  PIN aq_q[279]
    DIRECTION INPUT ;
    USE SIGNAL ;
    PORT
      LAYER M5 ;
        RECT  56.112 97.116 56.136 97.2 ;
    END
  END aq_q[279]
  PIN aq_q[27]
    DIRECTION INPUT ;
    USE SIGNAL ;
    PORT
      LAYER M5 ;
        RECT  53.424 97.116 53.448 97.2 ;
    END
  END aq_q[27]
  PIN aq_q[280]
    DIRECTION INPUT ;
    USE SIGNAL ;
    PORT
      LAYER M5 ;
        RECT  56.208 97.116 56.232 97.2 ;
    END
  END aq_q[280]
  PIN aq_q[281]
    DIRECTION INPUT ;
    USE SIGNAL ;
    PORT
      LAYER M5 ;
        RECT  56.304 97.116 56.328 97.2 ;
    END
  END aq_q[281]
  PIN aq_q[282]
    DIRECTION INPUT ;
    USE SIGNAL ;
    PORT
      LAYER M5 ;
        RECT  56.4 97.116 56.424 97.2 ;
    END
  END aq_q[282]
  PIN aq_q[283]
    DIRECTION INPUT ;
    USE SIGNAL ;
    PORT
      LAYER M5 ;
        RECT  56.496 97.116 56.52 97.2 ;
    END
  END aq_q[283]
  PIN aq_q[284]
    DIRECTION INPUT ;
    USE SIGNAL ;
    PORT
      LAYER M5 ;
        RECT  56.592 97.116 56.616 97.2 ;
    END
  END aq_q[284]
  PIN aq_q[285]
    DIRECTION INPUT ;
    USE SIGNAL ;
    PORT
      LAYER M5 ;
        RECT  56.688 97.116 56.712 97.2 ;
    END
  END aq_q[285]
  PIN aq_q[286]
    DIRECTION INPUT ;
    USE SIGNAL ;
    PORT
      LAYER M5 ;
        RECT  56.784 97.116 56.808 97.2 ;
    END
  END aq_q[286]
  PIN aq_q[287]
    DIRECTION INPUT ;
    USE SIGNAL ;
    PORT
      LAYER M5 ;
        RECT  56.88 97.116 56.904 97.2 ;
    END
  END aq_q[287]
  PIN aq_q[288]
    DIRECTION INPUT ;
    USE SIGNAL ;
    PORT
      LAYER M5 ;
        RECT  56.976 97.116 57 97.2 ;
    END
  END aq_q[288]
  PIN aq_q[289]
    DIRECTION INPUT ;
    USE SIGNAL ;
    PORT
      LAYER M5 ;
        RECT  57.072 97.116 57.096 97.2 ;
    END
  END aq_q[289]
  PIN aq_q[28]
    DIRECTION INPUT ;
    USE SIGNAL ;
    PORT
      LAYER M5 ;
        RECT  53.52 97.116 53.544 97.2 ;
    END
  END aq_q[28]
  PIN aq_q[290]
    DIRECTION INPUT ;
    USE SIGNAL ;
    PORT
      LAYER M5 ;
        RECT  57.168 97.116 57.192 97.2 ;
    END
  END aq_q[290]
  PIN aq_q[291]
    DIRECTION INPUT ;
    USE SIGNAL ;
    PORT
      LAYER M5 ;
        RECT  57.264 97.116 57.288 97.2 ;
    END
  END aq_q[291]
  PIN aq_q[292]
    DIRECTION INPUT ;
    USE SIGNAL ;
    PORT
      LAYER M5 ;
        RECT  57.36 97.116 57.384 97.2 ;
    END
  END aq_q[292]
  PIN aq_q[293]
    DIRECTION INPUT ;
    USE SIGNAL ;
    PORT
      LAYER M5 ;
        RECT  57.456 97.116 57.48 97.2 ;
    END
  END aq_q[293]
  PIN aq_q[294]
    DIRECTION INPUT ;
    USE SIGNAL ;
    PORT
      LAYER M5 ;
        RECT  57.552 97.116 57.576 97.2 ;
    END
  END aq_q[294]
  PIN aq_q[295]
    DIRECTION INPUT ;
    USE SIGNAL ;
    PORT
      LAYER M5 ;
        RECT  57.648 97.116 57.672 97.2 ;
    END
  END aq_q[295]
  PIN aq_q[296]
    DIRECTION INPUT ;
    USE SIGNAL ;
    PORT
      LAYER M5 ;
        RECT  57.744 97.116 57.768 97.2 ;
    END
  END aq_q[296]
  PIN aq_q[297]
    DIRECTION INPUT ;
    USE SIGNAL ;
    PORT
      LAYER M5 ;
        RECT  57.84 97.116 57.864 97.2 ;
    END
  END aq_q[297]
  PIN aq_q[298]
    DIRECTION INPUT ;
    USE SIGNAL ;
    PORT
      LAYER M5 ;
        RECT  57.936 97.116 57.96 97.2 ;
    END
  END aq_q[298]
  PIN aq_q[299]
    DIRECTION INPUT ;
    USE SIGNAL ;
    PORT
      LAYER M5 ;
        RECT  58.032 97.116 58.056 97.2 ;
    END
  END aq_q[299]
  PIN aq_q[29]
    DIRECTION INPUT ;
    USE SIGNAL ;
    PORT
      LAYER M5 ;
        RECT  53.616 97.116 53.64 97.2 ;
    END
  END aq_q[29]
  PIN aq_q[2]
    DIRECTION INPUT ;
    USE SIGNAL ;
    PORT
      LAYER M5 ;
        RECT  61.008 97.116 61.032 97.2 ;
    END
  END aq_q[2]
  PIN aq_q[300]
    DIRECTION INPUT ;
    USE SIGNAL ;
    PORT
      LAYER M5 ;
        RECT  23.568 97.116 23.592 97.2 ;
    END
  END aq_q[300]
  PIN aq_q[301]
    DIRECTION INPUT ;
    USE SIGNAL ;
    PORT
      LAYER M5 ;
        RECT  23.664 97.116 23.688 97.2 ;
    END
  END aq_q[301]
  PIN aq_q[302]
    DIRECTION INPUT ;
    USE SIGNAL ;
    PORT
      LAYER M5 ;
        RECT  23.76 97.116 23.784 97.2 ;
    END
  END aq_q[302]
  PIN aq_q[303]
    DIRECTION INPUT ;
    USE SIGNAL ;
    PORT
      LAYER M5 ;
        RECT  23.856 97.116 23.88 97.2 ;
    END
  END aq_q[303]
  PIN aq_q[304]
    DIRECTION INPUT ;
    USE SIGNAL ;
    PORT
      LAYER M5 ;
        RECT  23.952 97.116 23.976 97.2 ;
    END
  END aq_q[304]
  PIN aq_q[305]
    DIRECTION INPUT ;
    USE SIGNAL ;
    PORT
      LAYER M5 ;
        RECT  24.048 97.116 24.072 97.2 ;
    END
  END aq_q[305]
  PIN aq_q[306]
    DIRECTION INPUT ;
    USE SIGNAL ;
    PORT
      LAYER M5 ;
        RECT  24.144 97.116 24.168 97.2 ;
    END
  END aq_q[306]
  PIN aq_q[307]
    DIRECTION INPUT ;
    USE SIGNAL ;
    PORT
      LAYER M5 ;
        RECT  24.24 97.116 24.264 97.2 ;
    END
  END aq_q[307]
  PIN aq_q[308]
    DIRECTION INPUT ;
    USE SIGNAL ;
    PORT
      LAYER M5 ;
        RECT  24.336 97.116 24.36 97.2 ;
    END
  END aq_q[308]
  PIN aq_q[309]
    DIRECTION INPUT ;
    USE SIGNAL ;
    PORT
      LAYER M5 ;
        RECT  24.432 97.116 24.456 97.2 ;
    END
  END aq_q[309]
  PIN aq_q[30]
    DIRECTION INPUT ;
    USE SIGNAL ;
    PORT
      LAYER M5 ;
        RECT  53.712 97.116 53.736 97.2 ;
    END
  END aq_q[30]
  PIN aq_q[310]
    DIRECTION INPUT ;
    USE SIGNAL ;
    PORT
      LAYER M5 ;
        RECT  24.528 97.116 24.552 97.2 ;
    END
  END aq_q[310]
  PIN aq_q[311]
    DIRECTION INPUT ;
    USE SIGNAL ;
    PORT
      LAYER M5 ;
        RECT  24.624 97.116 24.648 97.2 ;
    END
  END aq_q[311]
  PIN aq_q[312]
    DIRECTION INPUT ;
    USE SIGNAL ;
    PORT
      LAYER M5 ;
        RECT  24.72 97.116 24.744 97.2 ;
    END
  END aq_q[312]
  PIN aq_q[313]
    DIRECTION INPUT ;
    USE SIGNAL ;
    PORT
      LAYER M5 ;
        RECT  24.816 97.116 24.84 97.2 ;
    END
  END aq_q[313]
  PIN aq_q[314]
    DIRECTION INPUT ;
    USE SIGNAL ;
    PORT
      LAYER M5 ;
        RECT  24.912 97.116 24.936 97.2 ;
    END
  END aq_q[314]
  PIN aq_q[315]
    DIRECTION INPUT ;
    USE SIGNAL ;
    PORT
      LAYER M5 ;
        RECT  25.008 97.116 25.032 97.2 ;
    END
  END aq_q[315]
  PIN aq_q[316]
    DIRECTION INPUT ;
    USE SIGNAL ;
    PORT
      LAYER M5 ;
        RECT  25.104 97.116 25.128 97.2 ;
    END
  END aq_q[316]
  PIN aq_q[317]
    DIRECTION INPUT ;
    USE SIGNAL ;
    PORT
      LAYER M5 ;
        RECT  25.2 97.116 25.224 97.2 ;
    END
  END aq_q[317]
  PIN aq_q[318]
    DIRECTION INPUT ;
    USE SIGNAL ;
    PORT
      LAYER M5 ;
        RECT  25.296 97.116 25.32 97.2 ;
    END
  END aq_q[318]
  PIN aq_q[319]
    DIRECTION INPUT ;
    USE SIGNAL ;
    PORT
      LAYER M5 ;
        RECT  25.392 97.116 25.416 97.2 ;
    END
  END aq_q[319]
  PIN aq_q[31]
    DIRECTION INPUT ;
    USE SIGNAL ;
    PORT
      LAYER M5 ;
        RECT  53.808 97.116 53.832 97.2 ;
    END
  END aq_q[31]
  PIN aq_q[320]
    DIRECTION INPUT ;
    USE SIGNAL ;
    PORT
      LAYER M5 ;
        RECT  25.488 97.116 25.512 97.2 ;
    END
  END aq_q[320]
  PIN aq_q[321]
    DIRECTION INPUT ;
    USE SIGNAL ;
    PORT
      LAYER M5 ;
        RECT  25.584 97.116 25.608 97.2 ;
    END
  END aq_q[321]
  PIN aq_q[322]
    DIRECTION INPUT ;
    USE SIGNAL ;
    PORT
      LAYER M5 ;
        RECT  25.68 97.116 25.704 97.2 ;
    END
  END aq_q[322]
  PIN aq_q[323]
    DIRECTION INPUT ;
    USE SIGNAL ;
    PORT
      LAYER M5 ;
        RECT  25.776 97.116 25.8 97.2 ;
    END
  END aq_q[323]
  PIN aq_q[324]
    DIRECTION INPUT ;
    USE SIGNAL ;
    PORT
      LAYER M5 ;
        RECT  25.872 97.116 25.896 97.2 ;
    END
  END aq_q[324]
  PIN aq_q[325]
    DIRECTION INPUT ;
    USE SIGNAL ;
    PORT
      LAYER M5 ;
        RECT  25.968 97.116 25.992 97.2 ;
    END
  END aq_q[325]
  PIN aq_q[326]
    DIRECTION INPUT ;
    USE SIGNAL ;
    PORT
      LAYER M5 ;
        RECT  26.064 97.116 26.088 97.2 ;
    END
  END aq_q[326]
  PIN aq_q[327]
    DIRECTION INPUT ;
    USE SIGNAL ;
    PORT
      LAYER M5 ;
        RECT  26.16 97.116 26.184 97.2 ;
    END
  END aq_q[327]
  PIN aq_q[328]
    DIRECTION INPUT ;
    USE SIGNAL ;
    PORT
      LAYER M5 ;
        RECT  26.256 97.116 26.28 97.2 ;
    END
  END aq_q[328]
  PIN aq_q[329]
    DIRECTION INPUT ;
    USE SIGNAL ;
    PORT
      LAYER M5 ;
        RECT  26.352 97.116 26.376 97.2 ;
    END
  END aq_q[329]
  PIN aq_q[32]
    DIRECTION INPUT ;
    USE SIGNAL ;
    PORT
      LAYER M5 ;
        RECT  53.904 97.116 53.928 97.2 ;
    END
  END aq_q[32]
  PIN aq_q[330]
    DIRECTION INPUT ;
    USE SIGNAL ;
    PORT
      LAYER M5 ;
        RECT  26.448 97.116 26.472 97.2 ;
    END
  END aq_q[330]
  PIN aq_q[331]
    DIRECTION INPUT ;
    USE SIGNAL ;
    PORT
      LAYER M5 ;
        RECT  26.544 97.116 26.568 97.2 ;
    END
  END aq_q[331]
  PIN aq_q[332]
    DIRECTION INPUT ;
    USE SIGNAL ;
    PORT
      LAYER M5 ;
        RECT  48.912 97.116 48.936 97.2 ;
    END
  END aq_q[332]
  PIN aq_q[333]
    DIRECTION INPUT ;
    USE SIGNAL ;
    PORT
      LAYER M5 ;
        RECT  49.008 97.116 49.032 97.2 ;
    END
  END aq_q[333]
  PIN aq_q[334]
    DIRECTION INPUT ;
    USE SIGNAL ;
    PORT
      LAYER M5 ;
        RECT  49.104 97.116 49.128 97.2 ;
    END
  END aq_q[334]
  PIN aq_q[335]
    DIRECTION INPUT ;
    USE SIGNAL ;
    PORT
      LAYER M5 ;
        RECT  49.2 97.116 49.224 97.2 ;
    END
  END aq_q[335]
  PIN aq_q[336]
    DIRECTION INPUT ;
    USE SIGNAL ;
    PORT
      LAYER M5 ;
        RECT  49.296 97.116 49.32 97.2 ;
    END
  END aq_q[336]
  PIN aq_q[337]
    DIRECTION INPUT ;
    USE SIGNAL ;
    PORT
      LAYER M5 ;
        RECT  49.392 97.116 49.416 97.2 ;
    END
  END aq_q[337]
  PIN aq_q[338]
    DIRECTION INPUT ;
    USE SIGNAL ;
    PORT
      LAYER M5 ;
        RECT  49.488 97.116 49.512 97.2 ;
    END
  END aq_q[338]
  PIN aq_q[339]
    DIRECTION INPUT ;
    USE SIGNAL ;
    PORT
      LAYER M5 ;
        RECT  49.584 97.116 49.608 97.2 ;
    END
  END aq_q[339]
  PIN aq_q[33]
    DIRECTION INPUT ;
    USE SIGNAL ;
    PORT
      LAYER M5 ;
        RECT  54 97.116 54.024 97.2 ;
    END
  END aq_q[33]
  PIN aq_q[340]
    DIRECTION INPUT ;
    USE SIGNAL ;
    PORT
      LAYER M5 ;
        RECT  49.68 97.116 49.704 97.2 ;
    END
  END aq_q[340]
  PIN aq_q[341]
    DIRECTION INPUT ;
    USE SIGNAL ;
    PORT
      LAYER M5 ;
        RECT  49.776 97.116 49.8 97.2 ;
    END
  END aq_q[341]
  PIN aq_q[342]
    DIRECTION INPUT ;
    USE SIGNAL ;
    PORT
      LAYER M5 ;
        RECT  49.872 97.116 49.896 97.2 ;
    END
  END aq_q[342]
  PIN aq_q[343]
    DIRECTION INPUT ;
    USE SIGNAL ;
    PORT
      LAYER M5 ;
        RECT  49.968 97.116 49.992 97.2 ;
    END
  END aq_q[343]
  PIN aq_q[344]
    DIRECTION INPUT ;
    USE SIGNAL ;
    PORT
      LAYER M5 ;
        RECT  50.064 97.116 50.088 97.2 ;
    END
  END aq_q[344]
  PIN aq_q[345]
    DIRECTION INPUT ;
    USE SIGNAL ;
    PORT
      LAYER M5 ;
        RECT  50.16 97.116 50.184 97.2 ;
    END
  END aq_q[345]
  PIN aq_q[346]
    DIRECTION INPUT ;
    USE SIGNAL ;
    PORT
      LAYER M5 ;
        RECT  50.256 97.116 50.28 97.2 ;
    END
  END aq_q[346]
  PIN aq_q[347]
    DIRECTION INPUT ;
    USE SIGNAL ;
    PORT
      LAYER M5 ;
        RECT  50.352 97.116 50.376 97.2 ;
    END
  END aq_q[347]
  PIN aq_q[348]
    DIRECTION INPUT ;
    USE SIGNAL ;
    PORT
      LAYER M5 ;
        RECT  50.448 97.116 50.472 97.2 ;
    END
  END aq_q[348]
  PIN aq_q[349]
    DIRECTION INPUT ;
    USE SIGNAL ;
    PORT
      LAYER M5 ;
        RECT  50.544 97.116 50.568 97.2 ;
    END
  END aq_q[349]
  PIN aq_q[34]
    DIRECTION INPUT ;
    USE SIGNAL ;
    PORT
      LAYER M5 ;
        RECT  54.096 97.116 54.12 97.2 ;
    END
  END aq_q[34]
  PIN aq_q[350]
    DIRECTION INPUT ;
    USE SIGNAL ;
    PORT
      LAYER M5 ;
        RECT  50.64 97.116 50.664 97.2 ;
    END
  END aq_q[350]
  PIN aq_q[351]
    DIRECTION INPUT ;
    USE SIGNAL ;
    PORT
      LAYER M5 ;
        RECT  50.736 97.116 50.76 97.2 ;
    END
  END aq_q[351]
  PIN aq_q[352]
    DIRECTION INPUT ;
    USE SIGNAL ;
    PORT
      LAYER M5 ;
        RECT  50.832 97.116 50.856 97.2 ;
    END
  END aq_q[352]
  PIN aq_q[353]
    DIRECTION INPUT ;
    USE SIGNAL ;
    PORT
      LAYER M5 ;
        RECT  50.928 97.116 50.952 97.2 ;
    END
  END aq_q[353]
  PIN aq_q[354]
    DIRECTION INPUT ;
    USE SIGNAL ;
    PORT
      LAYER M5 ;
        RECT  51.024 97.116 51.048 97.2 ;
    END
  END aq_q[354]
  PIN aq_q[355]
    DIRECTION INPUT ;
    USE SIGNAL ;
    PORT
      LAYER M5 ;
        RECT  51.12 97.116 51.144 97.2 ;
    END
  END aq_q[355]
  PIN aq_q[356]
    DIRECTION INPUT ;
    USE SIGNAL ;
    PORT
      LAYER M5 ;
        RECT  51.216 97.116 51.24 97.2 ;
    END
  END aq_q[356]
  PIN aq_q[357]
    DIRECTION INPUT ;
    USE SIGNAL ;
    PORT
      LAYER M5 ;
        RECT  51.312 97.116 51.336 97.2 ;
    END
  END aq_q[357]
  PIN aq_q[358]
    DIRECTION INPUT ;
    USE SIGNAL ;
    PORT
      LAYER M5 ;
        RECT  51.408 97.116 51.432 97.2 ;
    END
  END aq_q[358]
  PIN aq_q[359]
    DIRECTION INPUT ;
    USE SIGNAL ;
    PORT
      LAYER M5 ;
        RECT  51.504 97.116 51.528 97.2 ;
    END
  END aq_q[359]
  PIN aq_q[35]
    DIRECTION INPUT ;
    USE SIGNAL ;
    PORT
      LAYER M5 ;
        RECT  54.192 97.116 54.216 97.2 ;
    END
  END aq_q[35]
  PIN aq_q[360]
    DIRECTION INPUT ;
    USE SIGNAL ;
    PORT
      LAYER M5 ;
        RECT  51.6 97.116 51.624 97.2 ;
    END
  END aq_q[360]
  PIN aq_q[361]
    DIRECTION INPUT ;
    USE SIGNAL ;
    PORT
      LAYER M5 ;
        RECT  51.696 97.116 51.72 97.2 ;
    END
  END aq_q[361]
  PIN aq_q[362]
    DIRECTION INPUT ;
    USE SIGNAL ;
    PORT
      LAYER M5 ;
        RECT  51.792 97.116 51.816 97.2 ;
    END
  END aq_q[362]
  PIN aq_q[363]
    DIRECTION INPUT ;
    USE SIGNAL ;
    PORT
      LAYER M5 ;
        RECT  51.888 97.116 51.912 97.2 ;
    END
  END aq_q[363]
  PIN aq_q[364]
    DIRECTION INPUT ;
    USE SIGNAL ;
    PORT
      LAYER M5 ;
        RECT  74.256 97.116 74.28 97.2 ;
    END
  END aq_q[364]
  PIN aq_q[365]
    DIRECTION INPUT ;
    USE SIGNAL ;
    PORT
      LAYER M5 ;
        RECT  74.352 97.116 74.376 97.2 ;
    END
  END aq_q[365]
  PIN aq_q[366]
    DIRECTION INPUT ;
    USE SIGNAL ;
    PORT
      LAYER M5 ;
        RECT  74.448 97.116 74.472 97.2 ;
    END
  END aq_q[366]
  PIN aq_q[367]
    DIRECTION INPUT ;
    USE SIGNAL ;
    PORT
      LAYER M5 ;
        RECT  74.544 97.116 74.568 97.2 ;
    END
  END aq_q[367]
  PIN aq_q[368]
    DIRECTION INPUT ;
    USE SIGNAL ;
    PORT
      LAYER M5 ;
        RECT  74.64 97.116 74.664 97.2 ;
    END
  END aq_q[368]
  PIN aq_q[369]
    DIRECTION INPUT ;
    USE SIGNAL ;
    PORT
      LAYER M5 ;
        RECT  74.736 97.116 74.76 97.2 ;
    END
  END aq_q[369]
  PIN aq_q[36]
    DIRECTION INPUT ;
    USE SIGNAL ;
    PORT
      LAYER M5 ;
        RECT  54.288 97.116 54.312 97.2 ;
    END
  END aq_q[36]
  PIN aq_q[370]
    DIRECTION INPUT ;
    USE SIGNAL ;
    PORT
      LAYER M5 ;
        RECT  74.832 97.116 74.856 97.2 ;
    END
  END aq_q[370]
  PIN aq_q[371]
    DIRECTION INPUT ;
    USE SIGNAL ;
    PORT
      LAYER M5 ;
        RECT  74.928 97.116 74.952 97.2 ;
    END
  END aq_q[371]
  PIN aq_q[372]
    DIRECTION INPUT ;
    USE SIGNAL ;
    PORT
      LAYER M5 ;
        RECT  75.024 97.116 75.048 97.2 ;
    END
  END aq_q[372]
  PIN aq_q[373]
    DIRECTION INPUT ;
    USE SIGNAL ;
    PORT
      LAYER M5 ;
        RECT  75.12 97.116 75.144 97.2 ;
    END
  END aq_q[373]
  PIN aq_q[374]
    DIRECTION INPUT ;
    USE SIGNAL ;
    PORT
      LAYER M5 ;
        RECT  75.216 97.116 75.24 97.2 ;
    END
  END aq_q[374]
  PIN aq_q[375]
    DIRECTION INPUT ;
    USE SIGNAL ;
    PORT
      LAYER M5 ;
        RECT  75.312 97.116 75.336 97.2 ;
    END
  END aq_q[375]
  PIN aq_q[376]
    DIRECTION INPUT ;
    USE SIGNAL ;
    PORT
      LAYER M5 ;
        RECT  75.408 97.116 75.432 97.2 ;
    END
  END aq_q[376]
  PIN aq_q[377]
    DIRECTION INPUT ;
    USE SIGNAL ;
    PORT
      LAYER M5 ;
        RECT  75.504 97.116 75.528 97.2 ;
    END
  END aq_q[377]
  PIN aq_q[378]
    DIRECTION INPUT ;
    USE SIGNAL ;
    PORT
      LAYER M5 ;
        RECT  75.6 97.116 75.624 97.2 ;
    END
  END aq_q[378]
  PIN aq_q[379]
    DIRECTION INPUT ;
    USE SIGNAL ;
    PORT
      LAYER M5 ;
        RECT  75.696 97.116 75.72 97.2 ;
    END
  END aq_q[379]
  PIN aq_q[37]
    DIRECTION INPUT ;
    USE SIGNAL ;
    PORT
      LAYER M5 ;
        RECT  54.384 97.116 54.408 97.2 ;
    END
  END aq_q[37]
  PIN aq_q[380]
    DIRECTION INPUT ;
    USE SIGNAL ;
    PORT
      LAYER M5 ;
        RECT  75.792 97.116 75.816 97.2 ;
    END
  END aq_q[380]
  PIN aq_q[381]
    DIRECTION INPUT ;
    USE SIGNAL ;
    PORT
      LAYER M5 ;
        RECT  75.888 97.116 75.912 97.2 ;
    END
  END aq_q[381]
  PIN aq_q[382]
    DIRECTION INPUT ;
    USE SIGNAL ;
    PORT
      LAYER M5 ;
        RECT  75.984 97.116 76.008 97.2 ;
    END
  END aq_q[382]
  PIN aq_q[383]
    DIRECTION INPUT ;
    USE SIGNAL ;
    PORT
      LAYER M5 ;
        RECT  76.08 97.116 76.104 97.2 ;
    END
  END aq_q[383]
  PIN aq_q[384]
    DIRECTION INPUT ;
    USE SIGNAL ;
    PORT
      LAYER M5 ;
        RECT  76.176 97.116 76.2 97.2 ;
    END
  END aq_q[384]
  PIN aq_q[385]
    DIRECTION INPUT ;
    USE SIGNAL ;
    PORT
      LAYER M5 ;
        RECT  76.272 97.116 76.296 97.2 ;
    END
  END aq_q[385]
  PIN aq_q[386]
    DIRECTION INPUT ;
    USE SIGNAL ;
    PORT
      LAYER M5 ;
        RECT  76.368 97.116 76.392 97.2 ;
    END
  END aq_q[386]
  PIN aq_q[387]
    DIRECTION INPUT ;
    USE SIGNAL ;
    PORT
      LAYER M5 ;
        RECT  76.464 97.116 76.488 97.2 ;
    END
  END aq_q[387]
  PIN aq_q[388]
    DIRECTION INPUT ;
    USE SIGNAL ;
    PORT
      LAYER M5 ;
        RECT  76.56 97.116 76.584 97.2 ;
    END
  END aq_q[388]
  PIN aq_q[389]
    DIRECTION INPUT ;
    USE SIGNAL ;
    PORT
      LAYER M5 ;
        RECT  76.656 97.116 76.68 97.2 ;
    END
  END aq_q[389]
  PIN aq_q[38]
    DIRECTION INPUT ;
    USE SIGNAL ;
    PORT
      LAYER M5 ;
        RECT  54.48 97.116 54.504 97.2 ;
    END
  END aq_q[38]
  PIN aq_q[390]
    DIRECTION INPUT ;
    USE SIGNAL ;
    PORT
      LAYER M5 ;
        RECT  76.752 97.116 76.776 97.2 ;
    END
  END aq_q[390]
  PIN aq_q[391]
    DIRECTION INPUT ;
    USE SIGNAL ;
    PORT
      LAYER M5 ;
        RECT  76.848 97.116 76.872 97.2 ;
    END
  END aq_q[391]
  PIN aq_q[392]
    DIRECTION INPUT ;
    USE SIGNAL ;
    PORT
      LAYER M5 ;
        RECT  76.944 97.116 76.968 97.2 ;
    END
  END aq_q[392]
  PIN aq_q[393]
    DIRECTION INPUT ;
    USE SIGNAL ;
    PORT
      LAYER M5 ;
        RECT  77.04 97.116 77.064 97.2 ;
    END
  END aq_q[393]
  PIN aq_q[394]
    DIRECTION INPUT ;
    USE SIGNAL ;
    PORT
      LAYER M5 ;
        RECT  77.136 97.116 77.16 97.2 ;
    END
  END aq_q[394]
  PIN aq_q[395]
    DIRECTION INPUT ;
    USE SIGNAL ;
    PORT
      LAYER M5 ;
        RECT  77.232 97.116 77.256 97.2 ;
    END
  END aq_q[395]
  PIN aq_q[396]
    DIRECTION INPUT ;
    USE SIGNAL ;
    PORT
      LAYER M5 ;
        RECT  4.368 97.116 4.392 97.2 ;
    END
  END aq_q[396]
  PIN aq_q[397]
    DIRECTION INPUT ;
    USE SIGNAL ;
    PORT
      LAYER M5 ;
        RECT  4.464 97.116 4.488 97.2 ;
    END
  END aq_q[397]
  PIN aq_q[398]
    DIRECTION INPUT ;
    USE SIGNAL ;
    PORT
      LAYER M5 ;
        RECT  4.56 97.116 4.584 97.2 ;
    END
  END aq_q[398]
  PIN aq_q[399]
    DIRECTION INPUT ;
    USE SIGNAL ;
    PORT
      LAYER M5 ;
        RECT  4.656 97.116 4.68 97.2 ;
    END
  END aq_q[399]
  PIN aq_q[39]
    DIRECTION INPUT ;
    USE SIGNAL ;
    PORT
      LAYER M5 ;
        RECT  54.576 97.116 54.6 97.2 ;
    END
  END aq_q[39]
  PIN aq_q[3]
    DIRECTION INPUT ;
    USE SIGNAL ;
    PORT
      LAYER M5 ;
        RECT  61.104 97.116 61.128 97.2 ;
    END
  END aq_q[3]
  PIN aq_q[400]
    DIRECTION INPUT ;
    USE SIGNAL ;
    PORT
      LAYER M5 ;
        RECT  4.752 97.116 4.776 97.2 ;
    END
  END aq_q[400]
  PIN aq_q[401]
    DIRECTION INPUT ;
    USE SIGNAL ;
    PORT
      LAYER M5 ;
        RECT  4.848 97.116 4.872 97.2 ;
    END
  END aq_q[401]
  PIN aq_q[402]
    DIRECTION INPUT ;
    USE SIGNAL ;
    PORT
      LAYER M5 ;
        RECT  4.944 97.116 4.968 97.2 ;
    END
  END aq_q[402]
  PIN aq_q[403]
    DIRECTION INPUT ;
    USE SIGNAL ;
    PORT
      LAYER M5 ;
        RECT  5.04 97.116 5.064 97.2 ;
    END
  END aq_q[403]
  PIN aq_q[404]
    DIRECTION INPUT ;
    USE SIGNAL ;
    PORT
      LAYER M5 ;
        RECT  5.136 97.116 5.16 97.2 ;
    END
  END aq_q[404]
  PIN aq_q[405]
    DIRECTION INPUT ;
    USE SIGNAL ;
    PORT
      LAYER M5 ;
        RECT  5.232 97.116 5.256 97.2 ;
    END
  END aq_q[405]
  PIN aq_q[406]
    DIRECTION INPUT ;
    USE SIGNAL ;
    PORT
      LAYER M5 ;
        RECT  5.328 97.116 5.352 97.2 ;
    END
  END aq_q[406]
  PIN aq_q[407]
    DIRECTION INPUT ;
    USE SIGNAL ;
    PORT
      LAYER M5 ;
        RECT  5.424 97.116 5.448 97.2 ;
    END
  END aq_q[407]
  PIN aq_q[408]
    DIRECTION INPUT ;
    USE SIGNAL ;
    PORT
      LAYER M5 ;
        RECT  5.52 97.116 5.544 97.2 ;
    END
  END aq_q[408]
  PIN aq_q[409]
    DIRECTION INPUT ;
    USE SIGNAL ;
    PORT
      LAYER M5 ;
        RECT  5.616 97.116 5.64 97.2 ;
    END
  END aq_q[409]
  PIN aq_q[40]
    DIRECTION INPUT ;
    USE SIGNAL ;
    PORT
      LAYER M5 ;
        RECT  54.672 97.116 54.696 97.2 ;
    END
  END aq_q[40]
  PIN aq_q[410]
    DIRECTION INPUT ;
    USE SIGNAL ;
    PORT
      LAYER M5 ;
        RECT  5.712 97.116 5.736 97.2 ;
    END
  END aq_q[410]
  PIN aq_q[411]
    DIRECTION INPUT ;
    USE SIGNAL ;
    PORT
      LAYER M5 ;
        RECT  5.808 97.116 5.832 97.2 ;
    END
  END aq_q[411]
  PIN aq_q[412]
    DIRECTION INPUT ;
    USE SIGNAL ;
    PORT
      LAYER M5 ;
        RECT  5.904 97.116 5.928 97.2 ;
    END
  END aq_q[412]
  PIN aq_q[413]
    DIRECTION INPUT ;
    USE SIGNAL ;
    PORT
      LAYER M5 ;
        RECT  6 97.116 6.024 97.2 ;
    END
  END aq_q[413]
  PIN aq_q[414]
    DIRECTION INPUT ;
    USE SIGNAL ;
    PORT
      LAYER M5 ;
        RECT  6.096 97.116 6.12 97.2 ;
    END
  END aq_q[414]
  PIN aq_q[415]
    DIRECTION INPUT ;
    USE SIGNAL ;
    PORT
      LAYER M5 ;
        RECT  6.192 97.116 6.216 97.2 ;
    END
  END aq_q[415]
  PIN aq_q[416]
    DIRECTION INPUT ;
    USE SIGNAL ;
    PORT
      LAYER M5 ;
        RECT  6.288 97.116 6.312 97.2 ;
    END
  END aq_q[416]
  PIN aq_q[417]
    DIRECTION INPUT ;
    USE SIGNAL ;
    PORT
      LAYER M5 ;
        RECT  6.384 97.116 6.408 97.2 ;
    END
  END aq_q[417]
  PIN aq_q[418]
    DIRECTION INPUT ;
    USE SIGNAL ;
    PORT
      LAYER M5 ;
        RECT  6.48 97.116 6.504 97.2 ;
    END
  END aq_q[418]
  PIN aq_q[419]
    DIRECTION INPUT ;
    USE SIGNAL ;
    PORT
      LAYER M5 ;
        RECT  6.576 97.116 6.6 97.2 ;
    END
  END aq_q[419]
  PIN aq_q[41]
    DIRECTION INPUT ;
    USE SIGNAL ;
    PORT
      LAYER M5 ;
        RECT  54.768 97.116 54.792 97.2 ;
    END
  END aq_q[41]
  PIN aq_q[420]
    DIRECTION INPUT ;
    USE SIGNAL ;
    PORT
      LAYER M5 ;
        RECT  6.672 97.116 6.696 97.2 ;
    END
  END aq_q[420]
  PIN aq_q[421]
    DIRECTION INPUT ;
    USE SIGNAL ;
    PORT
      LAYER M5 ;
        RECT  6.768 97.116 6.792 97.2 ;
    END
  END aq_q[421]
  PIN aq_q[422]
    DIRECTION INPUT ;
    USE SIGNAL ;
    PORT
      LAYER M5 ;
        RECT  6.864 97.116 6.888 97.2 ;
    END
  END aq_q[422]
  PIN aq_q[423]
    DIRECTION INPUT ;
    USE SIGNAL ;
    PORT
      LAYER M5 ;
        RECT  6.96 97.116 6.984 97.2 ;
    END
  END aq_q[423]
  PIN aq_q[424]
    DIRECTION INPUT ;
    USE SIGNAL ;
    PORT
      LAYER M5 ;
        RECT  7.056 97.116 7.08 97.2 ;
    END
  END aq_q[424]
  PIN aq_q[425]
    DIRECTION INPUT ;
    USE SIGNAL ;
    PORT
      LAYER M5 ;
        RECT  7.152 97.116 7.176 97.2 ;
    END
  END aq_q[425]
  PIN aq_q[426]
    DIRECTION INPUT ;
    USE SIGNAL ;
    PORT
      LAYER M5 ;
        RECT  7.248 97.116 7.272 97.2 ;
    END
  END aq_q[426]
  PIN aq_q[427]
    DIRECTION INPUT ;
    USE SIGNAL ;
    PORT
      LAYER M5 ;
        RECT  7.344 97.116 7.368 97.2 ;
    END
  END aq_q[427]
  PIN aq_q[428]
    DIRECTION INPUT ;
    USE SIGNAL ;
    PORT
      LAYER M5 ;
        RECT  26.64 97.116 26.664 97.2 ;
    END
  END aq_q[428]
  PIN aq_q[429]
    DIRECTION INPUT ;
    USE SIGNAL ;
    PORT
      LAYER M5 ;
        RECT  26.736 97.116 26.76 97.2 ;
    END
  END aq_q[429]
  PIN aq_q[42]
    DIRECTION INPUT ;
    USE SIGNAL ;
    PORT
      LAYER M5 ;
        RECT  54.864 97.116 54.888 97.2 ;
    END
  END aq_q[42]
  PIN aq_q[430]
    DIRECTION INPUT ;
    USE SIGNAL ;
    PORT
      LAYER M5 ;
        RECT  26.832 97.116 26.856 97.2 ;
    END
  END aq_q[430]
  PIN aq_q[431]
    DIRECTION INPUT ;
    USE SIGNAL ;
    PORT
      LAYER M5 ;
        RECT  26.928 97.116 26.952 97.2 ;
    END
  END aq_q[431]
  PIN aq_q[432]
    DIRECTION INPUT ;
    USE SIGNAL ;
    PORT
      LAYER M5 ;
        RECT  27.024 97.116 27.048 97.2 ;
    END
  END aq_q[432]
  PIN aq_q[433]
    DIRECTION INPUT ;
    USE SIGNAL ;
    PORT
      LAYER M5 ;
        RECT  27.12 97.116 27.144 97.2 ;
    END
  END aq_q[433]
  PIN aq_q[434]
    DIRECTION INPUT ;
    USE SIGNAL ;
    PORT
      LAYER M5 ;
        RECT  27.216 97.116 27.24 97.2 ;
    END
  END aq_q[434]
  PIN aq_q[435]
    DIRECTION INPUT ;
    USE SIGNAL ;
    PORT
      LAYER M5 ;
        RECT  27.312 97.116 27.336 97.2 ;
    END
  END aq_q[435]
  PIN aq_q[436]
    DIRECTION INPUT ;
    USE SIGNAL ;
    PORT
      LAYER M5 ;
        RECT  27.408 97.116 27.432 97.2 ;
    END
  END aq_q[436]
  PIN aq_q[437]
    DIRECTION INPUT ;
    USE SIGNAL ;
    PORT
      LAYER M5 ;
        RECT  27.504 97.116 27.528 97.2 ;
    END
  END aq_q[437]
  PIN aq_q[438]
    DIRECTION INPUT ;
    USE SIGNAL ;
    PORT
      LAYER M5 ;
        RECT  27.6 97.116 27.624 97.2 ;
    END
  END aq_q[438]
  PIN aq_q[439]
    DIRECTION INPUT ;
    USE SIGNAL ;
    PORT
      LAYER M5 ;
        RECT  27.696 97.116 27.72 97.2 ;
    END
  END aq_q[439]
  PIN aq_q[43]
    DIRECTION INPUT ;
    USE SIGNAL ;
    PORT
      LAYER M5 ;
        RECT  54.96 97.116 54.984 97.2 ;
    END
  END aq_q[43]
  PIN aq_q[440]
    DIRECTION INPUT ;
    USE SIGNAL ;
    PORT
      LAYER M5 ;
        RECT  27.792 97.116 27.816 97.2 ;
    END
  END aq_q[440]
  PIN aq_q[441]
    DIRECTION INPUT ;
    USE SIGNAL ;
    PORT
      LAYER M5 ;
        RECT  27.888 97.116 27.912 97.2 ;
    END
  END aq_q[441]
  PIN aq_q[442]
    DIRECTION INPUT ;
    USE SIGNAL ;
    PORT
      LAYER M5 ;
        RECT  27.984 97.116 28.008 97.2 ;
    END
  END aq_q[442]
  PIN aq_q[443]
    DIRECTION INPUT ;
    USE SIGNAL ;
    PORT
      LAYER M5 ;
        RECT  28.08 97.116 28.104 97.2 ;
    END
  END aq_q[443]
  PIN aq_q[444]
    DIRECTION INPUT ;
    USE SIGNAL ;
    PORT
      LAYER M5 ;
        RECT  28.176 97.116 28.2 97.2 ;
    END
  END aq_q[444]
  PIN aq_q[445]
    DIRECTION INPUT ;
    USE SIGNAL ;
    PORT
      LAYER M5 ;
        RECT  28.272 97.116 28.296 97.2 ;
    END
  END aq_q[445]
  PIN aq_q[446]
    DIRECTION INPUT ;
    USE SIGNAL ;
    PORT
      LAYER M5 ;
        RECT  28.368 97.116 28.392 97.2 ;
    END
  END aq_q[446]
  PIN aq_q[447]
    DIRECTION INPUT ;
    USE SIGNAL ;
    PORT
      LAYER M5 ;
        RECT  28.464 97.116 28.488 97.2 ;
    END
  END aq_q[447]
  PIN aq_q[448]
    DIRECTION INPUT ;
    USE SIGNAL ;
    PORT
      LAYER M5 ;
        RECT  28.56 97.116 28.584 97.2 ;
    END
  END aq_q[448]
  PIN aq_q[449]
    DIRECTION INPUT ;
    USE SIGNAL ;
    PORT
      LAYER M5 ;
        RECT  28.656 97.116 28.68 97.2 ;
    END
  END aq_q[449]
  PIN aq_q[44]
    DIRECTION INPUT ;
    USE SIGNAL ;
    PORT
      LAYER M5 ;
        RECT  20.496 97.116 20.52 97.2 ;
    END
  END aq_q[44]
  PIN aq_q[450]
    DIRECTION INPUT ;
    USE SIGNAL ;
    PORT
      LAYER M5 ;
        RECT  28.752 97.116 28.776 97.2 ;
    END
  END aq_q[450]
  PIN aq_q[451]
    DIRECTION INPUT ;
    USE SIGNAL ;
    PORT
      LAYER M5 ;
        RECT  28.848 97.116 28.872 97.2 ;
    END
  END aq_q[451]
  PIN aq_q[452]
    DIRECTION INPUT ;
    USE SIGNAL ;
    PORT
      LAYER M5 ;
        RECT  28.944 97.116 28.968 97.2 ;
    END
  END aq_q[452]
  PIN aq_q[453]
    DIRECTION INPUT ;
    USE SIGNAL ;
    PORT
      LAYER M5 ;
        RECT  29.04 97.116 29.064 97.2 ;
    END
  END aq_q[453]
  PIN aq_q[454]
    DIRECTION INPUT ;
    USE SIGNAL ;
    PORT
      LAYER M5 ;
        RECT  29.136 97.116 29.16 97.2 ;
    END
  END aq_q[454]
  PIN aq_q[455]
    DIRECTION INPUT ;
    USE SIGNAL ;
    PORT
      LAYER M5 ;
        RECT  29.232 97.116 29.256 97.2 ;
    END
  END aq_q[455]
  PIN aq_q[456]
    DIRECTION INPUT ;
    USE SIGNAL ;
    PORT
      LAYER M5 ;
        RECT  29.328 97.116 29.352 97.2 ;
    END
  END aq_q[456]
  PIN aq_q[457]
    DIRECTION INPUT ;
    USE SIGNAL ;
    PORT
      LAYER M5 ;
        RECT  29.424 97.116 29.448 97.2 ;
    END
  END aq_q[457]
  PIN aq_q[458]
    DIRECTION INPUT ;
    USE SIGNAL ;
    PORT
      LAYER M5 ;
        RECT  29.52 97.116 29.544 97.2 ;
    END
  END aq_q[458]
  PIN aq_q[459]
    DIRECTION INPUT ;
    USE SIGNAL ;
    PORT
      LAYER M5 ;
        RECT  29.616 97.116 29.64 97.2 ;
    END
  END aq_q[459]
  PIN aq_q[45]
    DIRECTION INPUT ;
    USE SIGNAL ;
    PORT
      LAYER M5 ;
        RECT  20.592 97.116 20.616 97.2 ;
    END
  END aq_q[45]
  PIN aq_q[460]
    DIRECTION INPUT ;
    USE SIGNAL ;
    PORT
      LAYER M5 ;
        RECT  42.768 97.116 42.792 97.2 ;
    END
  END aq_q[460]
  PIN aq_q[461]
    DIRECTION INPUT ;
    USE SIGNAL ;
    PORT
      LAYER M5 ;
        RECT  42.864 97.116 42.888 97.2 ;
    END
  END aq_q[461]
  PIN aq_q[462]
    DIRECTION INPUT ;
    USE SIGNAL ;
    PORT
      LAYER M5 ;
        RECT  42.96 97.116 42.984 97.2 ;
    END
  END aq_q[462]
  PIN aq_q[463]
    DIRECTION INPUT ;
    USE SIGNAL ;
    PORT
      LAYER M5 ;
        RECT  43.056 97.116 43.08 97.2 ;
    END
  END aq_q[463]
  PIN aq_q[464]
    DIRECTION INPUT ;
    USE SIGNAL ;
    PORT
      LAYER M5 ;
        RECT  43.152 97.116 43.176 97.2 ;
    END
  END aq_q[464]
  PIN aq_q[465]
    DIRECTION INPUT ;
    USE SIGNAL ;
    PORT
      LAYER M5 ;
        RECT  43.248 97.116 43.272 97.2 ;
    END
  END aq_q[465]
  PIN aq_q[466]
    DIRECTION INPUT ;
    USE SIGNAL ;
    PORT
      LAYER M5 ;
        RECT  43.344 97.116 43.368 97.2 ;
    END
  END aq_q[466]
  PIN aq_q[467]
    DIRECTION INPUT ;
    USE SIGNAL ;
    PORT
      LAYER M5 ;
        RECT  43.44 97.116 43.464 97.2 ;
    END
  END aq_q[467]
  PIN aq_q[468]
    DIRECTION INPUT ;
    USE SIGNAL ;
    PORT
      LAYER M5 ;
        RECT  43.536 97.116 43.56 97.2 ;
    END
  END aq_q[468]
  PIN aq_q[469]
    DIRECTION INPUT ;
    USE SIGNAL ;
    PORT
      LAYER M5 ;
        RECT  43.632 97.116 43.656 97.2 ;
    END
  END aq_q[469]
  PIN aq_q[46]
    DIRECTION INPUT ;
    USE SIGNAL ;
    PORT
      LAYER M5 ;
        RECT  20.688 97.116 20.712 97.2 ;
    END
  END aq_q[46]
  PIN aq_q[470]
    DIRECTION INPUT ;
    USE SIGNAL ;
    PORT
      LAYER M5 ;
        RECT  43.728 97.116 43.752 97.2 ;
    END
  END aq_q[470]
  PIN aq_q[471]
    DIRECTION INPUT ;
    USE SIGNAL ;
    PORT
      LAYER M5 ;
        RECT  43.824 97.116 43.848 97.2 ;
    END
  END aq_q[471]
  PIN aq_q[472]
    DIRECTION INPUT ;
    USE SIGNAL ;
    PORT
      LAYER M5 ;
        RECT  43.92 97.116 43.944 97.2 ;
    END
  END aq_q[472]
  PIN aq_q[473]
    DIRECTION INPUT ;
    USE SIGNAL ;
    PORT
      LAYER M5 ;
        RECT  44.016 97.116 44.04 97.2 ;
    END
  END aq_q[473]
  PIN aq_q[474]
    DIRECTION INPUT ;
    USE SIGNAL ;
    PORT
      LAYER M5 ;
        RECT  44.112 97.116 44.136 97.2 ;
    END
  END aq_q[474]
  PIN aq_q[475]
    DIRECTION INPUT ;
    USE SIGNAL ;
    PORT
      LAYER M5 ;
        RECT  44.208 97.116 44.232 97.2 ;
    END
  END aq_q[475]
  PIN aq_q[476]
    DIRECTION INPUT ;
    USE SIGNAL ;
    PORT
      LAYER M5 ;
        RECT  44.304 97.116 44.328 97.2 ;
    END
  END aq_q[476]
  PIN aq_q[477]
    DIRECTION INPUT ;
    USE SIGNAL ;
    PORT
      LAYER M5 ;
        RECT  44.4 97.116 44.424 97.2 ;
    END
  END aq_q[477]
  PIN aq_q[478]
    DIRECTION INPUT ;
    USE SIGNAL ;
    PORT
      LAYER M5 ;
        RECT  44.496 97.116 44.52 97.2 ;
    END
  END aq_q[478]
  PIN aq_q[479]
    DIRECTION INPUT ;
    USE SIGNAL ;
    PORT
      LAYER M5 ;
        RECT  44.592 97.116 44.616 97.2 ;
    END
  END aq_q[479]
  PIN aq_q[47]
    DIRECTION INPUT ;
    USE SIGNAL ;
    PORT
      LAYER M5 ;
        RECT  20.784 97.116 20.808 97.2 ;
    END
  END aq_q[47]
  PIN aq_q[480]
    DIRECTION INPUT ;
    USE SIGNAL ;
    PORT
      LAYER M5 ;
        RECT  44.688 97.116 44.712 97.2 ;
    END
  END aq_q[480]
  PIN aq_q[481]
    DIRECTION INPUT ;
    USE SIGNAL ;
    PORT
      LAYER M5 ;
        RECT  44.784 97.116 44.808 97.2 ;
    END
  END aq_q[481]
  PIN aq_q[482]
    DIRECTION INPUT ;
    USE SIGNAL ;
    PORT
      LAYER M5 ;
        RECT  44.88 97.116 44.904 97.2 ;
    END
  END aq_q[482]
  PIN aq_q[483]
    DIRECTION INPUT ;
    USE SIGNAL ;
    PORT
      LAYER M5 ;
        RECT  44.976 97.116 45 97.2 ;
    END
  END aq_q[483]
  PIN aq_q[484]
    DIRECTION INPUT ;
    USE SIGNAL ;
    PORT
      LAYER M5 ;
        RECT  45.072 97.116 45.096 97.2 ;
    END
  END aq_q[484]
  PIN aq_q[485]
    DIRECTION INPUT ;
    USE SIGNAL ;
    PORT
      LAYER M5 ;
        RECT  45.168 97.116 45.192 97.2 ;
    END
  END aq_q[485]
  PIN aq_q[486]
    DIRECTION INPUT ;
    USE SIGNAL ;
    PORT
      LAYER M5 ;
        RECT  45.264 97.116 45.288 97.2 ;
    END
  END aq_q[486]
  PIN aq_q[487]
    DIRECTION INPUT ;
    USE SIGNAL ;
    PORT
      LAYER M5 ;
        RECT  45.36 97.116 45.384 97.2 ;
    END
  END aq_q[487]
  PIN aq_q[488]
    DIRECTION INPUT ;
    USE SIGNAL ;
    PORT
      LAYER M5 ;
        RECT  45.456 97.116 45.48 97.2 ;
    END
  END aq_q[488]
  PIN aq_q[489]
    DIRECTION INPUT ;
    USE SIGNAL ;
    PORT
      LAYER M5 ;
        RECT  45.552 97.116 45.576 97.2 ;
    END
  END aq_q[489]
  PIN aq_q[48]
    DIRECTION INPUT ;
    USE SIGNAL ;
    PORT
      LAYER M5 ;
        RECT  20.88 97.116 20.904 97.2 ;
    END
  END aq_q[48]
  PIN aq_q[490]
    DIRECTION INPUT ;
    USE SIGNAL ;
    PORT
      LAYER M5 ;
        RECT  45.648 97.116 45.672 97.2 ;
    END
  END aq_q[490]
  PIN aq_q[491]
    DIRECTION INPUT ;
    USE SIGNAL ;
    PORT
      LAYER M5 ;
        RECT  45.744 97.116 45.768 97.2 ;
    END
  END aq_q[491]
  PIN aq_q[492]
    DIRECTION INPUT ;
    USE SIGNAL ;
    PORT
      LAYER M5 ;
        RECT  79.248 97.116 79.272 97.2 ;
    END
  END aq_q[492]
  PIN aq_q[493]
    DIRECTION INPUT ;
    USE SIGNAL ;
    PORT
      LAYER M5 ;
        RECT  79.344 97.116 79.368 97.2 ;
    END
  END aq_q[493]
  PIN aq_q[494]
    DIRECTION INPUT ;
    USE SIGNAL ;
    PORT
      LAYER M5 ;
        RECT  79.44 97.116 79.464 97.2 ;
    END
  END aq_q[494]
  PIN aq_q[495]
    DIRECTION INPUT ;
    USE SIGNAL ;
    PORT
      LAYER M5 ;
        RECT  79.536 97.116 79.56 97.2 ;
    END
  END aq_q[495]
  PIN aq_q[496]
    DIRECTION INPUT ;
    USE SIGNAL ;
    PORT
      LAYER M5 ;
        RECT  79.632 97.116 79.656 97.2 ;
    END
  END aq_q[496]
  PIN aq_q[497]
    DIRECTION INPUT ;
    USE SIGNAL ;
    PORT
      LAYER M5 ;
        RECT  79.728 97.116 79.752 97.2 ;
    END
  END aq_q[497]
  PIN aq_q[498]
    DIRECTION INPUT ;
    USE SIGNAL ;
    PORT
      LAYER M5 ;
        RECT  79.824 97.116 79.848 97.2 ;
    END
  END aq_q[498]
  PIN aq_q[499]
    DIRECTION INPUT ;
    USE SIGNAL ;
    PORT
      LAYER M5 ;
        RECT  79.92 97.116 79.944 97.2 ;
    END
  END aq_q[499]
  PIN aq_q[49]
    DIRECTION INPUT ;
    USE SIGNAL ;
    PORT
      LAYER M5 ;
        RECT  20.976 97.116 21 97.2 ;
    END
  END aq_q[49]
  PIN aq_q[4]
    DIRECTION INPUT ;
    USE SIGNAL ;
    PORT
      LAYER M5 ;
        RECT  61.2 97.116 61.224 97.2 ;
    END
  END aq_q[4]
  PIN aq_q[500]
    DIRECTION INPUT ;
    USE SIGNAL ;
    PORT
      LAYER M5 ;
        RECT  80.016 97.116 80.04 97.2 ;
    END
  END aq_q[500]
  PIN aq_q[501]
    DIRECTION INPUT ;
    USE SIGNAL ;
    PORT
      LAYER M5 ;
        RECT  80.112 97.116 80.136 97.2 ;
    END
  END aq_q[501]
  PIN aq_q[502]
    DIRECTION INPUT ;
    USE SIGNAL ;
    PORT
      LAYER M5 ;
        RECT  80.208 97.116 80.232 97.2 ;
    END
  END aq_q[502]
  PIN aq_q[503]
    DIRECTION INPUT ;
    USE SIGNAL ;
    PORT
      LAYER M5 ;
        RECT  80.304 97.116 80.328 97.2 ;
    END
  END aq_q[503]
  PIN aq_q[504]
    DIRECTION INPUT ;
    USE SIGNAL ;
    PORT
      LAYER M5 ;
        RECT  80.4 97.116 80.424 97.2 ;
    END
  END aq_q[504]
  PIN aq_q[505]
    DIRECTION INPUT ;
    USE SIGNAL ;
    PORT
      LAYER M5 ;
        RECT  80.496 97.116 80.52 97.2 ;
    END
  END aq_q[505]
  PIN aq_q[506]
    DIRECTION INPUT ;
    USE SIGNAL ;
    PORT
      LAYER M5 ;
        RECT  80.592 97.116 80.616 97.2 ;
    END
  END aq_q[506]
  PIN aq_q[507]
    DIRECTION INPUT ;
    USE SIGNAL ;
    PORT
      LAYER M5 ;
        RECT  80.688 97.116 80.712 97.2 ;
    END
  END aq_q[507]
  PIN aq_q[508]
    DIRECTION INPUT ;
    USE SIGNAL ;
    PORT
      LAYER M5 ;
        RECT  80.784 97.116 80.808 97.2 ;
    END
  END aq_q[508]
  PIN aq_q[509]
    DIRECTION INPUT ;
    USE SIGNAL ;
    PORT
      LAYER M5 ;
        RECT  80.88 97.116 80.904 97.2 ;
    END
  END aq_q[509]
  PIN aq_q[50]
    DIRECTION INPUT ;
    USE SIGNAL ;
    PORT
      LAYER M5 ;
        RECT  21.072 97.116 21.096 97.2 ;
    END
  END aq_q[50]
  PIN aq_q[510]
    DIRECTION INPUT ;
    USE SIGNAL ;
    PORT
      LAYER M5 ;
        RECT  80.976 97.116 81 97.2 ;
    END
  END aq_q[510]
  PIN aq_q[511]
    DIRECTION INPUT ;
    USE SIGNAL ;
    PORT
      LAYER M5 ;
        RECT  81.072 97.116 81.096 97.2 ;
    END
  END aq_q[511]
  PIN aq_q[51]
    DIRECTION INPUT ;
    USE SIGNAL ;
    PORT
      LAYER M5 ;
        RECT  21.168 97.116 21.192 97.2 ;
    END
  END aq_q[51]
  PIN aq_q[52]
    DIRECTION INPUT ;
    USE SIGNAL ;
    PORT
      LAYER M5 ;
        RECT  21.264 97.116 21.288 97.2 ;
    END
  END aq_q[52]
  PIN aq_q[53]
    DIRECTION INPUT ;
    USE SIGNAL ;
    PORT
      LAYER M5 ;
        RECT  21.36 97.116 21.384 97.2 ;
    END
  END aq_q[53]
  PIN aq_q[54]
    DIRECTION INPUT ;
    USE SIGNAL ;
    PORT
      LAYER M5 ;
        RECT  21.456 97.116 21.48 97.2 ;
    END
  END aq_q[54]
  PIN aq_q[55]
    DIRECTION INPUT ;
    USE SIGNAL ;
    PORT
      LAYER M5 ;
        RECT  21.552 97.116 21.576 97.2 ;
    END
  END aq_q[55]
  PIN aq_q[56]
    DIRECTION INPUT ;
    USE SIGNAL ;
    PORT
      LAYER M5 ;
        RECT  21.648 97.116 21.672 97.2 ;
    END
  END aq_q[56]
  PIN aq_q[57]
    DIRECTION INPUT ;
    USE SIGNAL ;
    PORT
      LAYER M5 ;
        RECT  21.744 97.116 21.768 97.2 ;
    END
  END aq_q[57]
  PIN aq_q[58]
    DIRECTION INPUT ;
    USE SIGNAL ;
    PORT
      LAYER M5 ;
        RECT  21.84 97.116 21.864 97.2 ;
    END
  END aq_q[58]
  PIN aq_q[59]
    DIRECTION INPUT ;
    USE SIGNAL ;
    PORT
      LAYER M5 ;
        RECT  21.936 97.116 21.96 97.2 ;
    END
  END aq_q[59]
  PIN aq_q[5]
    DIRECTION INPUT ;
    USE SIGNAL ;
    PORT
      LAYER M5 ;
        RECT  61.296 97.116 61.32 97.2 ;
    END
  END aq_q[5]
  PIN aq_q[60]
    DIRECTION INPUT ;
    USE SIGNAL ;
    PORT
      LAYER M5 ;
        RECT  22.032 97.116 22.056 97.2 ;
    END
  END aq_q[60]
  PIN aq_q[61]
    DIRECTION INPUT ;
    USE SIGNAL ;
    PORT
      LAYER M5 ;
        RECT  22.128 97.116 22.152 97.2 ;
    END
  END aq_q[61]
  PIN aq_q[62]
    DIRECTION INPUT ;
    USE SIGNAL ;
    PORT
      LAYER M5 ;
        RECT  22.224 97.116 22.248 97.2 ;
    END
  END aq_q[62]
  PIN aq_q[63]
    DIRECTION INPUT ;
    USE SIGNAL ;
    PORT
      LAYER M5 ;
        RECT  22.32 97.116 22.344 97.2 ;
    END
  END aq_q[63]
  PIN aq_q[64]
    DIRECTION INPUT ;
    USE SIGNAL ;
    PORT
      LAYER M5 ;
        RECT  22.416 97.116 22.44 97.2 ;
    END
  END aq_q[64]
  PIN aq_q[65]
    DIRECTION INPUT ;
    USE SIGNAL ;
    PORT
      LAYER M5 ;
        RECT  22.512 97.116 22.536 97.2 ;
    END
  END aq_q[65]
  PIN aq_q[66]
    DIRECTION INPUT ;
    USE SIGNAL ;
    PORT
      LAYER M5 ;
        RECT  22.608 97.116 22.632 97.2 ;
    END
  END aq_q[66]
  PIN aq_q[67]
    DIRECTION INPUT ;
    USE SIGNAL ;
    PORT
      LAYER M5 ;
        RECT  22.704 97.116 22.728 97.2 ;
    END
  END aq_q[67]
  PIN aq_q[68]
    DIRECTION INPUT ;
    USE SIGNAL ;
    PORT
      LAYER M5 ;
        RECT  22.8 97.116 22.824 97.2 ;
    END
  END aq_q[68]
  PIN aq_q[69]
    DIRECTION INPUT ;
    USE SIGNAL ;
    PORT
      LAYER M5 ;
        RECT  22.896 97.116 22.92 97.2 ;
    END
  END aq_q[69]
  PIN aq_q[6]
    DIRECTION INPUT ;
    USE SIGNAL ;
    PORT
      LAYER M5 ;
        RECT  61.392 97.116 61.416 97.2 ;
    END
  END aq_q[6]
  PIN aq_q[70]
    DIRECTION INPUT ;
    USE SIGNAL ;
    PORT
      LAYER M5 ;
        RECT  22.992 97.116 23.016 97.2 ;
    END
  END aq_q[70]
  PIN aq_q[71]
    DIRECTION INPUT ;
    USE SIGNAL ;
    PORT
      LAYER M5 ;
        RECT  23.088 97.116 23.112 97.2 ;
    END
  END aq_q[71]
  PIN aq_q[72]
    DIRECTION INPUT ;
    USE SIGNAL ;
    PORT
      LAYER M5 ;
        RECT  23.184 97.116 23.208 97.2 ;
    END
  END aq_q[72]
  PIN aq_q[73]
    DIRECTION INPUT ;
    USE SIGNAL ;
    PORT
      LAYER M5 ;
        RECT  23.28 97.116 23.304 97.2 ;
    END
  END aq_q[73]
  PIN aq_q[74]
    DIRECTION INPUT ;
    USE SIGNAL ;
    PORT
      LAYER M5 ;
        RECT  23.376 97.116 23.4 97.2 ;
    END
  END aq_q[74]
  PIN aq_q[75]
    DIRECTION INPUT ;
    USE SIGNAL ;
    PORT
      LAYER M5 ;
        RECT  23.472 97.116 23.496 97.2 ;
    END
  END aq_q[75]
  PIN aq_q[76]
    DIRECTION INPUT ;
    USE SIGNAL ;
    PORT
      LAYER M5 ;
        RECT  45.84 97.116 45.864 97.2 ;
    END
  END aq_q[76]
  PIN aq_q[77]
    DIRECTION INPUT ;
    USE SIGNAL ;
    PORT
      LAYER M5 ;
        RECT  45.936 97.116 45.96 97.2 ;
    END
  END aq_q[77]
  PIN aq_q[78]
    DIRECTION INPUT ;
    USE SIGNAL ;
    PORT
      LAYER M5 ;
        RECT  46.032 97.116 46.056 97.2 ;
    END
  END aq_q[78]
  PIN aq_q[79]
    DIRECTION INPUT ;
    USE SIGNAL ;
    PORT
      LAYER M5 ;
        RECT  46.128 97.116 46.152 97.2 ;
    END
  END aq_q[79]
  PIN aq_q[7]
    DIRECTION INPUT ;
    USE SIGNAL ;
    PORT
      LAYER M5 ;
        RECT  61.488 97.116 61.512 97.2 ;
    END
  END aq_q[7]
  PIN aq_q[80]
    DIRECTION INPUT ;
    USE SIGNAL ;
    PORT
      LAYER M5 ;
        RECT  46.224 97.116 46.248 97.2 ;
    END
  END aq_q[80]
  PIN aq_q[81]
    DIRECTION INPUT ;
    USE SIGNAL ;
    PORT
      LAYER M5 ;
        RECT  46.32 97.116 46.344 97.2 ;
    END
  END aq_q[81]
  PIN aq_q[82]
    DIRECTION INPUT ;
    USE SIGNAL ;
    PORT
      LAYER M5 ;
        RECT  46.416 97.116 46.44 97.2 ;
    END
  END aq_q[82]
  PIN aq_q[83]
    DIRECTION INPUT ;
    USE SIGNAL ;
    PORT
      LAYER M5 ;
        RECT  46.512 97.116 46.536 97.2 ;
    END
  END aq_q[83]
  PIN aq_q[84]
    DIRECTION INPUT ;
    USE SIGNAL ;
    PORT
      LAYER M5 ;
        RECT  46.608 97.116 46.632 97.2 ;
    END
  END aq_q[84]
  PIN aq_q[85]
    DIRECTION INPUT ;
    USE SIGNAL ;
    PORT
      LAYER M5 ;
        RECT  46.704 97.116 46.728 97.2 ;
    END
  END aq_q[85]
  PIN aq_q[86]
    DIRECTION INPUT ;
    USE SIGNAL ;
    PORT
      LAYER M5 ;
        RECT  46.8 97.116 46.824 97.2 ;
    END
  END aq_q[86]
  PIN aq_q[87]
    DIRECTION INPUT ;
    USE SIGNAL ;
    PORT
      LAYER M5 ;
        RECT  46.896 97.116 46.92 97.2 ;
    END
  END aq_q[87]
  PIN aq_q[88]
    DIRECTION INPUT ;
    USE SIGNAL ;
    PORT
      LAYER M5 ;
        RECT  46.992 97.116 47.016 97.2 ;
    END
  END aq_q[88]
  PIN aq_q[89]
    DIRECTION INPUT ;
    USE SIGNAL ;
    PORT
      LAYER M5 ;
        RECT  47.088 97.116 47.112 97.2 ;
    END
  END aq_q[89]
  PIN aq_q[8]
    DIRECTION INPUT ;
    USE SIGNAL ;
    PORT
      LAYER M5 ;
        RECT  61.584 97.116 61.608 97.2 ;
    END
  END aq_q[8]
  PIN aq_q[90]
    DIRECTION INPUT ;
    USE SIGNAL ;
    PORT
      LAYER M5 ;
        RECT  47.184 97.116 47.208 97.2 ;
    END
  END aq_q[90]
  PIN aq_q[91]
    DIRECTION INPUT ;
    USE SIGNAL ;
    PORT
      LAYER M5 ;
        RECT  47.28 97.116 47.304 97.2 ;
    END
  END aq_q[91]
  PIN aq_q[92]
    DIRECTION INPUT ;
    USE SIGNAL ;
    PORT
      LAYER M5 ;
        RECT  47.376 97.116 47.4 97.2 ;
    END
  END aq_q[92]
  PIN aq_q[93]
    DIRECTION INPUT ;
    USE SIGNAL ;
    PORT
      LAYER M5 ;
        RECT  47.472 97.116 47.496 97.2 ;
    END
  END aq_q[93]
  PIN aq_q[94]
    DIRECTION INPUT ;
    USE SIGNAL ;
    PORT
      LAYER M5 ;
        RECT  47.568 97.116 47.592 97.2 ;
    END
  END aq_q[94]
  PIN aq_q[95]
    DIRECTION INPUT ;
    USE SIGNAL ;
    PORT
      LAYER M5 ;
        RECT  47.664 97.116 47.688 97.2 ;
    END
  END aq_q[95]
  PIN aq_q[96]
    DIRECTION INPUT ;
    USE SIGNAL ;
    PORT
      LAYER M5 ;
        RECT  47.76 97.116 47.784 97.2 ;
    END
  END aq_q[96]
  PIN aq_q[97]
    DIRECTION INPUT ;
    USE SIGNAL ;
    PORT
      LAYER M5 ;
        RECT  47.856 97.116 47.88 97.2 ;
    END
  END aq_q[97]
  PIN aq_q[98]
    DIRECTION INPUT ;
    USE SIGNAL ;
    PORT
      LAYER M5 ;
        RECT  47.952 97.116 47.976 97.2 ;
    END
  END aq_q[98]
  PIN aq_q[99]
    DIRECTION INPUT ;
    USE SIGNAL ;
    PORT
      LAYER M5 ;
        RECT  48.048 97.116 48.072 97.2 ;
    END
  END aq_q[99]
  PIN aq_q[9]
    DIRECTION INPUT ;
    USE SIGNAL ;
    PORT
      LAYER M5 ;
        RECT  61.68 97.116 61.704 97.2 ;
    END
  END aq_q[9]
  PIN aqi_d[0]
    DIRECTION INPUT ;
    USE SIGNAL ;
    PORT
      LAYER M4 ;
        RECT  0 55.056 0.084 55.08 ;
    END
  END aqi_d[0]
  PIN aqi_d[1]
    DIRECTION INPUT ;
    USE SIGNAL ;
    PORT
      LAYER M4 ;
        RECT  0 55.152 0.084 55.176 ;
    END
  END aqi_d[1]
  PIN aqi_d[2]
    DIRECTION INPUT ;
    USE SIGNAL ;
    PORT
      LAYER M4 ;
        RECT  0 55.248 0.084 55.272 ;
    END
  END aqi_d[2]
  PIN aqi_d[3]
    DIRECTION INPUT ;
    USE SIGNAL ;
    PORT
      LAYER M4 ;
        RECT  0 55.344 0.084 55.368 ;
    END
  END aqi_d[3]
  PIN aqi_d[4]
    DIRECTION INPUT ;
    USE SIGNAL ;
    PORT
      LAYER M4 ;
        RECT  0 55.44 0.084 55.464 ;
    END
  END aqi_d[4]
  PIN clk
    DIRECTION INPUT ;
    USE SIGNAL ;
    PORT
      LAYER M4 ;
        RECT  0 55.536 0.084 55.56 ;
    END
  END clk
  PIN h_b0[0]
    DIRECTION INPUT ;
    USE SIGNAL ;
    PORT
      LAYER M4 ;
        RECT  0 55.632 0.084 55.656 ;
    END
  END h_b0[0]
  PIN h_b0[10]
    DIRECTION INPUT ;
    USE SIGNAL ;
    PORT
      LAYER M4 ;
        RECT  0 56.592 0.084 56.616 ;
    END
  END h_b0[10]
  PIN h_b0[11]
    DIRECTION INPUT ;
    USE SIGNAL ;
    PORT
      LAYER M4 ;
        RECT  0 56.688 0.084 56.712 ;
    END
  END h_b0[11]
  PIN h_b0[12]
    DIRECTION INPUT ;
    USE SIGNAL ;
    PORT
      LAYER M4 ;
        RECT  0 56.784 0.084 56.808 ;
    END
  END h_b0[12]
  PIN h_b0[13]
    DIRECTION INPUT ;
    USE SIGNAL ;
    PORT
      LAYER M4 ;
        RECT  0 56.88 0.084 56.904 ;
    END
  END h_b0[13]
  PIN h_b0[14]
    DIRECTION INPUT ;
    USE SIGNAL ;
    PORT
      LAYER M4 ;
        RECT  0 56.976 0.084 57 ;
    END
  END h_b0[14]
  PIN h_b0[15]
    DIRECTION INPUT ;
    USE SIGNAL ;
    PORT
      LAYER M4 ;
        RECT  0 57.072 0.084 57.096 ;
    END
  END h_b0[15]
  PIN h_b0[1]
    DIRECTION INPUT ;
    USE SIGNAL ;
    PORT
      LAYER M4 ;
        RECT  0 55.728 0.084 55.752 ;
    END
  END h_b0[1]
  PIN h_b0[2]
    DIRECTION INPUT ;
    USE SIGNAL ;
    PORT
      LAYER M4 ;
        RECT  0 55.824 0.084 55.848 ;
    END
  END h_b0[2]
  PIN h_b0[3]
    DIRECTION INPUT ;
    USE SIGNAL ;
    PORT
      LAYER M4 ;
        RECT  0 55.92 0.084 55.944 ;
    END
  END h_b0[3]
  PIN h_b0[4]
    DIRECTION INPUT ;
    USE SIGNAL ;
    PORT
      LAYER M4 ;
        RECT  0 56.016 0.084 56.04 ;
    END
  END h_b0[4]
  PIN h_b0[5]
    DIRECTION INPUT ;
    USE SIGNAL ;
    PORT
      LAYER M4 ;
        RECT  0 56.112 0.084 56.136 ;
    END
  END h_b0[5]
  PIN h_b0[6]
    DIRECTION INPUT ;
    USE SIGNAL ;
    PORT
      LAYER M4 ;
        RECT  0 56.208 0.084 56.232 ;
    END
  END h_b0[6]
  PIN h_b0[7]
    DIRECTION INPUT ;
    USE SIGNAL ;
    PORT
      LAYER M4 ;
        RECT  0 56.304 0.084 56.328 ;
    END
  END h_b0[7]
  PIN h_b0[8]
    DIRECTION INPUT ;
    USE SIGNAL ;
    PORT
      LAYER M4 ;
        RECT  0 56.4 0.084 56.424 ;
    END
  END h_b0[8]
  PIN h_b0[9]
    DIRECTION INPUT ;
    USE SIGNAL ;
    PORT
      LAYER M4 ;
        RECT  0 56.496 0.084 56.52 ;
    END
  END h_b0[9]
  PIN h_b1[0]
    DIRECTION INPUT ;
    USE SIGNAL ;
    PORT
      LAYER M4 ;
        RECT  0 57.168 0.084 57.192 ;
    END
  END h_b1[0]
  PIN h_b1[10]
    DIRECTION INPUT ;
    USE SIGNAL ;
    PORT
      LAYER M4 ;
        RECT  0 28.56 0.084 28.584 ;
    END
  END h_b1[10]
  PIN h_b1[11]
    DIRECTION INPUT ;
    USE SIGNAL ;
    PORT
      LAYER M4 ;
        RECT  0 28.656 0.084 28.68 ;
    END
  END h_b1[11]
  PIN h_b1[12]
    DIRECTION INPUT ;
    USE SIGNAL ;
    PORT
      LAYER M4 ;
        RECT  0 28.752 0.084 28.776 ;
    END
  END h_b1[12]
  PIN h_b1[13]
    DIRECTION INPUT ;
    USE SIGNAL ;
    PORT
      LAYER M4 ;
        RECT  0 28.848 0.084 28.872 ;
    END
  END h_b1[13]
  PIN h_b1[14]
    DIRECTION INPUT ;
    USE SIGNAL ;
    PORT
      LAYER M4 ;
        RECT  0 28.944 0.084 28.968 ;
    END
  END h_b1[14]
  PIN h_b1[15]
    DIRECTION INPUT ;
    USE SIGNAL ;
    PORT
      LAYER M4 ;
        RECT  0 29.04 0.084 29.064 ;
    END
  END h_b1[15]
  PIN h_b1[1]
    DIRECTION INPUT ;
    USE SIGNAL ;
    PORT
      LAYER M4 ;
        RECT  0 57.264 0.084 57.288 ;
    END
  END h_b1[1]
  PIN h_b1[2]
    DIRECTION INPUT ;
    USE SIGNAL ;
    PORT
      LAYER M4 ;
        RECT  0 57.36 0.084 57.384 ;
    END
  END h_b1[2]
  PIN h_b1[3]
    DIRECTION INPUT ;
    USE SIGNAL ;
    PORT
      LAYER M4 ;
        RECT  0 57.456 0.084 57.48 ;
    END
  END h_b1[3]
  PIN h_b1[4]
    DIRECTION INPUT ;
    USE SIGNAL ;
    PORT
      LAYER M4 ;
        RECT  0 57.552 0.084 57.576 ;
    END
  END h_b1[4]
  PIN h_b1[5]
    DIRECTION INPUT ;
    USE SIGNAL ;
    PORT
      LAYER M4 ;
        RECT  0 57.648 0.084 57.672 ;
    END
  END h_b1[5]
  PIN h_b1[6]
    DIRECTION INPUT ;
    USE SIGNAL ;
    PORT
      LAYER M4 ;
        RECT  0 57.744 0.084 57.768 ;
    END
  END h_b1[6]
  PIN h_b1[7]
    DIRECTION INPUT ;
    USE SIGNAL ;
    PORT
      LAYER M4 ;
        RECT  0 57.84 0.084 57.864 ;
    END
  END h_b1[7]
  PIN h_b1[8]
    DIRECTION INPUT ;
    USE SIGNAL ;
    PORT
      LAYER M4 ;
        RECT  0 57.936 0.084 57.96 ;
    END
  END h_b1[8]
  PIN h_b1[9]
    DIRECTION INPUT ;
    USE SIGNAL ;
    PORT
      LAYER M4 ;
        RECT  0 58.032 0.084 58.056 ;
    END
  END h_b1[9]
  PIN he0[0]
    DIRECTION OUTPUT ;
    USE SIGNAL ;
    PORT
      LAYER M5 ;
        RECT  73.68 0 73.704 0.084 ;
    END
  END he0[0]
  PIN he0[1]
    DIRECTION OUTPUT ;
    USE SIGNAL ;
    PORT
      LAYER M5 ;
        RECT  73.776 0 73.8 0.084 ;
    END
  END he0[1]
  PIN he0[2]
    DIRECTION OUTPUT ;
    USE SIGNAL ;
    PORT
      LAYER M5 ;
        RECT  73.872 0 73.896 0.084 ;
    END
  END he0[2]
  PIN he0[3]
    DIRECTION OUTPUT ;
    USE SIGNAL ;
    PORT
      LAYER M5 ;
        RECT  73.968 0 73.992 0.084 ;
    END
  END he0[3]
  PIN he0[4]
    DIRECTION OUTPUT ;
    USE SIGNAL ;
    PORT
      LAYER M5 ;
        RECT  74.064 0 74.088 0.084 ;
    END
  END he0[4]
  PIN he0[5]
    DIRECTION OUTPUT ;
    USE SIGNAL ;
    PORT
      LAYER M5 ;
        RECT  74.16 0 74.184 0.084 ;
    END
  END he0[5]
  PIN he0[6]
    DIRECTION OUTPUT ;
    USE SIGNAL ;
    PORT
      LAYER M5 ;
        RECT  74.256 0 74.28 0.084 ;
    END
  END he0[6]
  PIN he0[7]
    DIRECTION OUTPUT ;
    USE SIGNAL ;
    PORT
      LAYER M5 ;
        RECT  74.352 0 74.376 0.084 ;
    END
  END he0[7]
  PIN he0[8]
    DIRECTION OUTPUT ;
    USE SIGNAL ;
    PORT
      LAYER M5 ;
        RECT  74.448 0 74.472 0.084 ;
    END
  END he0[8]
  PIN he0[9]
    DIRECTION OUTPUT ;
    USE SIGNAL ;
    PORT
      LAYER M5 ;
        RECT  74.544 0 74.568 0.084 ;
    END
  END he0[9]
  PIN he1[0]
    DIRECTION OUTPUT ;
    USE SIGNAL ;
    PORT
      LAYER M5 ;
        RECT  74.64 0 74.664 0.084 ;
    END
  END he1[0]
  PIN he1[1]
    DIRECTION OUTPUT ;
    USE SIGNAL ;
    PORT
      LAYER M5 ;
        RECT  74.736 0 74.76 0.084 ;
    END
  END he1[1]
  PIN he1[2]
    DIRECTION OUTPUT ;
    USE SIGNAL ;
    PORT
      LAYER M5 ;
        RECT  74.832 0 74.856 0.084 ;
    END
  END he1[2]
  PIN he1[3]
    DIRECTION OUTPUT ;
    USE SIGNAL ;
    PORT
      LAYER M5 ;
        RECT  74.928 0 74.952 0.084 ;
    END
  END he1[3]
  PIN he1[4]
    DIRECTION OUTPUT ;
    USE SIGNAL ;
    PORT
      LAYER M5 ;
        RECT  75.024 0 75.048 0.084 ;
    END
  END he1[4]
  PIN he1[5]
    DIRECTION OUTPUT ;
    USE SIGNAL ;
    PORT
      LAYER M5 ;
        RECT  75.12 0 75.144 0.084 ;
    END
  END he1[5]
  PIN he1[6]
    DIRECTION OUTPUT ;
    USE SIGNAL ;
    PORT
      LAYER M5 ;
        RECT  75.216 0 75.24 0.084 ;
    END
  END he1[6]
  PIN he1[7]
    DIRECTION OUTPUT ;
    USE SIGNAL ;
    PORT
      LAYER M5 ;
        RECT  75.312 0 75.336 0.084 ;
    END
  END he1[7]
  PIN he1[8]
    DIRECTION OUTPUT ;
    USE SIGNAL ;
    PORT
      LAYER M5 ;
        RECT  75.408 0 75.432 0.084 ;
    END
  END he1[8]
  PIN he1[9]
    DIRECTION OUTPUT ;
    USE SIGNAL ;
    PORT
      LAYER M5 ;
        RECT  75.504 0 75.528 0.084 ;
    END
  END he1[9]
  PIN hq0[0]
    DIRECTION OUTPUT ;
    USE SIGNAL ;
    PORT
      LAYER M5 ;
        RECT  75.6 0 75.624 0.084 ;
    END
  END hq0[0]
  PIN hq0[100]
    DIRECTION OUTPUT ;
    USE SIGNAL ;
    PORT
      LAYER M5 ;
        RECT  63.696 0 63.72 0.084 ;
    END
  END hq0[100]
  PIN hq0[101]
    DIRECTION OUTPUT ;
    USE SIGNAL ;
    PORT
      LAYER M5 ;
        RECT  63.792 0 63.816 0.084 ;
    END
  END hq0[101]
  PIN hq0[102]
    DIRECTION OUTPUT ;
    USE SIGNAL ;
    PORT
      LAYER M5 ;
        RECT  63.888 0 63.912 0.084 ;
    END
  END hq0[102]
  PIN hq0[103]
    DIRECTION OUTPUT ;
    USE SIGNAL ;
    PORT
      LAYER M5 ;
        RECT  63.984 0 64.008 0.084 ;
    END
  END hq0[103]
  PIN hq0[104]
    DIRECTION OUTPUT ;
    USE SIGNAL ;
    PORT
      LAYER M5 ;
        RECT  64.08 0 64.104 0.084 ;
    END
  END hq0[104]
  PIN hq0[105]
    DIRECTION OUTPUT ;
    USE SIGNAL ;
    PORT
      LAYER M5 ;
        RECT  64.176 0 64.2 0.084 ;
    END
  END hq0[105]
  PIN hq0[106]
    DIRECTION OUTPUT ;
    USE SIGNAL ;
    PORT
      LAYER M5 ;
        RECT  64.272 0 64.296 0.084 ;
    END
  END hq0[106]
  PIN hq0[107]
    DIRECTION OUTPUT ;
    USE SIGNAL ;
    PORT
      LAYER M5 ;
        RECT  64.368 0 64.392 0.084 ;
    END
  END hq0[107]
  PIN hq0[108]
    DIRECTION OUTPUT ;
    USE SIGNAL ;
    PORT
      LAYER M5 ;
        RECT  83.664 0 83.688 0.084 ;
    END
  END hq0[108]
  PIN hq0[109]
    DIRECTION OUTPUT ;
    USE SIGNAL ;
    PORT
      LAYER M5 ;
        RECT  83.76 0 83.784 0.084 ;
    END
  END hq0[109]
  PIN hq0[10]
    DIRECTION OUTPUT ;
    USE SIGNAL ;
    PORT
      LAYER M5 ;
        RECT  76.56 0 76.584 0.084 ;
    END
  END hq0[10]
  PIN hq0[110]
    DIRECTION OUTPUT ;
    USE SIGNAL ;
    PORT
      LAYER M5 ;
        RECT  83.856 0 83.88 0.084 ;
    END
  END hq0[110]
  PIN hq0[111]
    DIRECTION OUTPUT ;
    USE SIGNAL ;
    PORT
      LAYER M5 ;
        RECT  83.952 0 83.976 0.084 ;
    END
  END hq0[111]
  PIN hq0[112]
    DIRECTION OUTPUT ;
    USE SIGNAL ;
    PORT
      LAYER M5 ;
        RECT  84.048 0 84.072 0.084 ;
    END
  END hq0[112]
  PIN hq0[113]
    DIRECTION OUTPUT ;
    USE SIGNAL ;
    PORT
      LAYER M5 ;
        RECT  84.144 0 84.168 0.084 ;
    END
  END hq0[113]
  PIN hq0[114]
    DIRECTION OUTPUT ;
    USE SIGNAL ;
    PORT
      LAYER M5 ;
        RECT  84.24 0 84.264 0.084 ;
    END
  END hq0[114]
  PIN hq0[115]
    DIRECTION OUTPUT ;
    USE SIGNAL ;
    PORT
      LAYER M5 ;
        RECT  84.336 0 84.36 0.084 ;
    END
  END hq0[115]
  PIN hq0[116]
    DIRECTION OUTPUT ;
    USE SIGNAL ;
    PORT
      LAYER M5 ;
        RECT  84.432 0 84.456 0.084 ;
    END
  END hq0[116]
  PIN hq0[117]
    DIRECTION OUTPUT ;
    USE SIGNAL ;
    PORT
      LAYER M5 ;
        RECT  84.528 0 84.552 0.084 ;
    END
  END hq0[117]
  PIN hq0[118]
    DIRECTION OUTPUT ;
    USE SIGNAL ;
    PORT
      LAYER M5 ;
        RECT  84.624 0 84.648 0.084 ;
    END
  END hq0[118]
  PIN hq0[119]
    DIRECTION OUTPUT ;
    USE SIGNAL ;
    PORT
      LAYER M5 ;
        RECT  84.72 0 84.744 0.084 ;
    END
  END hq0[119]
  PIN hq0[11]
    DIRECTION OUTPUT ;
    USE SIGNAL ;
    PORT
      LAYER M5 ;
        RECT  76.656 0 76.68 0.084 ;
    END
  END hq0[11]
  PIN hq0[120]
    DIRECTION OUTPUT ;
    USE SIGNAL ;
    PORT
      LAYER M5 ;
        RECT  84.816 0 84.84 0.084 ;
    END
  END hq0[120]
  PIN hq0[121]
    DIRECTION OUTPUT ;
    USE SIGNAL ;
    PORT
      LAYER M5 ;
        RECT  84.912 0 84.936 0.084 ;
    END
  END hq0[121]
  PIN hq0[122]
    DIRECTION OUTPUT ;
    USE SIGNAL ;
    PORT
      LAYER M5 ;
        RECT  85.008 0 85.032 0.084 ;
    END
  END hq0[122]
  PIN hq0[123]
    DIRECTION OUTPUT ;
    USE SIGNAL ;
    PORT
      LAYER M5 ;
        RECT  85.104 0 85.128 0.084 ;
    END
  END hq0[123]
  PIN hq0[124]
    DIRECTION OUTPUT ;
    USE SIGNAL ;
    PORT
      LAYER M5 ;
        RECT  85.2 0 85.224 0.084 ;
    END
  END hq0[124]
  PIN hq0[125]
    DIRECTION OUTPUT ;
    USE SIGNAL ;
    PORT
      LAYER M5 ;
        RECT  85.296 0 85.32 0.084 ;
    END
  END hq0[125]
  PIN hq0[126]
    DIRECTION OUTPUT ;
    USE SIGNAL ;
    PORT
      LAYER M5 ;
        RECT  85.392 0 85.416 0.084 ;
    END
  END hq0[126]
  PIN hq0[127]
    DIRECTION OUTPUT ;
    USE SIGNAL ;
    PORT
      LAYER M5 ;
        RECT  85.488 0 85.512 0.084 ;
    END
  END hq0[127]
  PIN hq0[128]
    DIRECTION OUTPUT ;
    USE SIGNAL ;
    PORT
      LAYER M5 ;
        RECT  85.584 0 85.608 0.084 ;
    END
  END hq0[128]
  PIN hq0[129]
    DIRECTION OUTPUT ;
    USE SIGNAL ;
    PORT
      LAYER M5 ;
        RECT  85.68 0 85.704 0.084 ;
    END
  END hq0[129]
  PIN hq0[12]
    DIRECTION OUTPUT ;
    USE SIGNAL ;
    PORT
      LAYER M5 ;
        RECT  70.608 0 70.632 0.084 ;
    END
  END hq0[12]
  PIN hq0[130]
    DIRECTION OUTPUT ;
    USE SIGNAL ;
    PORT
      LAYER M5 ;
        RECT  85.776 0 85.8 0.084 ;
    END
  END hq0[130]
  PIN hq0[131]
    DIRECTION OUTPUT ;
    USE SIGNAL ;
    PORT
      LAYER M5 ;
        RECT  85.872 0 85.896 0.084 ;
    END
  END hq0[131]
  PIN hq0[132]
    DIRECTION OUTPUT ;
    USE SIGNAL ;
    PORT
      LAYER M5 ;
        RECT  85.968 0 85.992 0.084 ;
    END
  END hq0[132]
  PIN hq0[133]
    DIRECTION OUTPUT ;
    USE SIGNAL ;
    PORT
      LAYER M5 ;
        RECT  86.064 0 86.088 0.084 ;
    END
  END hq0[133]
  PIN hq0[134]
    DIRECTION OUTPUT ;
    USE SIGNAL ;
    PORT
      LAYER M5 ;
        RECT  86.16 0 86.184 0.084 ;
    END
  END hq0[134]
  PIN hq0[135]
    DIRECTION OUTPUT ;
    USE SIGNAL ;
    PORT
      LAYER M5 ;
        RECT  86.256 0 86.28 0.084 ;
    END
  END hq0[135]
  PIN hq0[136]
    DIRECTION OUTPUT ;
    USE SIGNAL ;
    PORT
      LAYER M5 ;
        RECT  86.352 0 86.376 0.084 ;
    END
  END hq0[136]
  PIN hq0[137]
    DIRECTION OUTPUT ;
    USE SIGNAL ;
    PORT
      LAYER M5 ;
        RECT  86.448 0 86.472 0.084 ;
    END
  END hq0[137]
  PIN hq0[138]
    DIRECTION OUTPUT ;
    USE SIGNAL ;
    PORT
      LAYER M5 ;
        RECT  86.544 0 86.568 0.084 ;
    END
  END hq0[138]
  PIN hq0[139]
    DIRECTION OUTPUT ;
    USE SIGNAL ;
    PORT
      LAYER M5 ;
        RECT  86.64 0 86.664 0.084 ;
    END
  END hq0[139]
  PIN hq0[13]
    DIRECTION OUTPUT ;
    USE SIGNAL ;
    PORT
      LAYER M5 ;
        RECT  70.704 0 70.728 0.084 ;
    END
  END hq0[13]
  PIN hq0[140]
    DIRECTION OUTPUT ;
    USE SIGNAL ;
    PORT
      LAYER M5 ;
        RECT  22.992 0 23.016 0.084 ;
    END
  END hq0[140]
  PIN hq0[141]
    DIRECTION OUTPUT ;
    USE SIGNAL ;
    PORT
      LAYER M5 ;
        RECT  23.088 0 23.112 0.084 ;
    END
  END hq0[141]
  PIN hq0[142]
    DIRECTION OUTPUT ;
    USE SIGNAL ;
    PORT
      LAYER M5 ;
        RECT  23.184 0 23.208 0.084 ;
    END
  END hq0[142]
  PIN hq0[143]
    DIRECTION OUTPUT ;
    USE SIGNAL ;
    PORT
      LAYER M5 ;
        RECT  23.28 0 23.304 0.084 ;
    END
  END hq0[143]
  PIN hq0[144]
    DIRECTION OUTPUT ;
    USE SIGNAL ;
    PORT
      LAYER M5 ;
        RECT  23.376 0 23.4 0.084 ;
    END
  END hq0[144]
  PIN hq0[145]
    DIRECTION OUTPUT ;
    USE SIGNAL ;
    PORT
      LAYER M5 ;
        RECT  23.472 0 23.496 0.084 ;
    END
  END hq0[145]
  PIN hq0[146]
    DIRECTION OUTPUT ;
    USE SIGNAL ;
    PORT
      LAYER M5 ;
        RECT  23.568 0 23.592 0.084 ;
    END
  END hq0[146]
  PIN hq0[147]
    DIRECTION OUTPUT ;
    USE SIGNAL ;
    PORT
      LAYER M5 ;
        RECT  23.664 0 23.688 0.084 ;
    END
  END hq0[147]
  PIN hq0[148]
    DIRECTION OUTPUT ;
    USE SIGNAL ;
    PORT
      LAYER M5 ;
        RECT  23.76 0 23.784 0.084 ;
    END
  END hq0[148]
  PIN hq0[149]
    DIRECTION OUTPUT ;
    USE SIGNAL ;
    PORT
      LAYER M5 ;
        RECT  23.856 0 23.88 0.084 ;
    END
  END hq0[149]
  PIN hq0[14]
    DIRECTION OUTPUT ;
    USE SIGNAL ;
    PORT
      LAYER M5 ;
        RECT  70.8 0 70.824 0.084 ;
    END
  END hq0[14]
  PIN hq0[150]
    DIRECTION OUTPUT ;
    USE SIGNAL ;
    PORT
      LAYER M5 ;
        RECT  23.952 0 23.976 0.084 ;
    END
  END hq0[150]
  PIN hq0[151]
    DIRECTION OUTPUT ;
    USE SIGNAL ;
    PORT
      LAYER M5 ;
        RECT  24.048 0 24.072 0.084 ;
    END
  END hq0[151]
  PIN hq0[152]
    DIRECTION OUTPUT ;
    USE SIGNAL ;
    PORT
      LAYER M5 ;
        RECT  24.144 0 24.168 0.084 ;
    END
  END hq0[152]
  PIN hq0[153]
    DIRECTION OUTPUT ;
    USE SIGNAL ;
    PORT
      LAYER M5 ;
        RECT  24.24 0 24.264 0.084 ;
    END
  END hq0[153]
  PIN hq0[154]
    DIRECTION OUTPUT ;
    USE SIGNAL ;
    PORT
      LAYER M5 ;
        RECT  24.336 0 24.36 0.084 ;
    END
  END hq0[154]
  PIN hq0[155]
    DIRECTION OUTPUT ;
    USE SIGNAL ;
    PORT
      LAYER M5 ;
        RECT  24.432 0 24.456 0.084 ;
    END
  END hq0[155]
  PIN hq0[156]
    DIRECTION OUTPUT ;
    USE SIGNAL ;
    PORT
      LAYER M5 ;
        RECT  24.528 0 24.552 0.084 ;
    END
  END hq0[156]
  PIN hq0[157]
    DIRECTION OUTPUT ;
    USE SIGNAL ;
    PORT
      LAYER M5 ;
        RECT  24.624 0 24.648 0.084 ;
    END
  END hq0[157]
  PIN hq0[158]
    DIRECTION OUTPUT ;
    USE SIGNAL ;
    PORT
      LAYER M5 ;
        RECT  24.72 0 24.744 0.084 ;
    END
  END hq0[158]
  PIN hq0[159]
    DIRECTION OUTPUT ;
    USE SIGNAL ;
    PORT
      LAYER M5 ;
        RECT  24.816 0 24.84 0.084 ;
    END
  END hq0[159]
  PIN hq0[15]
    DIRECTION OUTPUT ;
    USE SIGNAL ;
    PORT
      LAYER M5 ;
        RECT  70.896 0 70.92 0.084 ;
    END
  END hq0[15]
  PIN hq0[160]
    DIRECTION OUTPUT ;
    USE SIGNAL ;
    PORT
      LAYER M5 ;
        RECT  24.912 0 24.936 0.084 ;
    END
  END hq0[160]
  PIN hq0[161]
    DIRECTION OUTPUT ;
    USE SIGNAL ;
    PORT
      LAYER M5 ;
        RECT  25.008 0 25.032 0.084 ;
    END
  END hq0[161]
  PIN hq0[162]
    DIRECTION OUTPUT ;
    USE SIGNAL ;
    PORT
      LAYER M5 ;
        RECT  25.104 0 25.128 0.084 ;
    END
  END hq0[162]
  PIN hq0[163]
    DIRECTION OUTPUT ;
    USE SIGNAL ;
    PORT
      LAYER M5 ;
        RECT  25.2 0 25.224 0.084 ;
    END
  END hq0[163]
  PIN hq0[164]
    DIRECTION OUTPUT ;
    USE SIGNAL ;
    PORT
      LAYER M5 ;
        RECT  25.296 0 25.32 0.084 ;
    END
  END hq0[164]
  PIN hq0[165]
    DIRECTION OUTPUT ;
    USE SIGNAL ;
    PORT
      LAYER M5 ;
        RECT  25.392 0 25.416 0.084 ;
    END
  END hq0[165]
  PIN hq0[166]
    DIRECTION OUTPUT ;
    USE SIGNAL ;
    PORT
      LAYER M5 ;
        RECT  25.488 0 25.512 0.084 ;
    END
  END hq0[166]
  PIN hq0[167]
    DIRECTION OUTPUT ;
    USE SIGNAL ;
    PORT
      LAYER M5 ;
        RECT  25.584 0 25.608 0.084 ;
    END
  END hq0[167]
  PIN hq0[168]
    DIRECTION OUTPUT ;
    USE SIGNAL ;
    PORT
      LAYER M5 ;
        RECT  25.68 0 25.704 0.084 ;
    END
  END hq0[168]
  PIN hq0[169]
    DIRECTION OUTPUT ;
    USE SIGNAL ;
    PORT
      LAYER M5 ;
        RECT  25.776 0 25.8 0.084 ;
    END
  END hq0[169]
  PIN hq0[16]
    DIRECTION OUTPUT ;
    USE SIGNAL ;
    PORT
      LAYER M5 ;
        RECT  70.992 0 71.016 0.084 ;
    END
  END hq0[16]
  PIN hq0[170]
    DIRECTION OUTPUT ;
    USE SIGNAL ;
    PORT
      LAYER M5 ;
        RECT  25.872 0 25.896 0.084 ;
    END
  END hq0[170]
  PIN hq0[171]
    DIRECTION OUTPUT ;
    USE SIGNAL ;
    PORT
      LAYER M5 ;
        RECT  25.968 0 25.992 0.084 ;
    END
  END hq0[171]
  PIN hq0[172]
    DIRECTION OUTPUT ;
    USE SIGNAL ;
    PORT
      LAYER M5 ;
        RECT  45.264 0 45.288 0.084 ;
    END
  END hq0[172]
  PIN hq0[173]
    DIRECTION OUTPUT ;
    USE SIGNAL ;
    PORT
      LAYER M5 ;
        RECT  45.36 0 45.384 0.084 ;
    END
  END hq0[173]
  PIN hq0[174]
    DIRECTION OUTPUT ;
    USE SIGNAL ;
    PORT
      LAYER M5 ;
        RECT  45.456 0 45.48 0.084 ;
    END
  END hq0[174]
  PIN hq0[175]
    DIRECTION OUTPUT ;
    USE SIGNAL ;
    PORT
      LAYER M5 ;
        RECT  45.552 0 45.576 0.084 ;
    END
  END hq0[175]
  PIN hq0[176]
    DIRECTION OUTPUT ;
    USE SIGNAL ;
    PORT
      LAYER M5 ;
        RECT  45.648 0 45.672 0.084 ;
    END
  END hq0[176]
  PIN hq0[177]
    DIRECTION OUTPUT ;
    USE SIGNAL ;
    PORT
      LAYER M5 ;
        RECT  45.744 0 45.768 0.084 ;
    END
  END hq0[177]
  PIN hq0[178]
    DIRECTION OUTPUT ;
    USE SIGNAL ;
    PORT
      LAYER M5 ;
        RECT  45.84 0 45.864 0.084 ;
    END
  END hq0[178]
  PIN hq0[179]
    DIRECTION OUTPUT ;
    USE SIGNAL ;
    PORT
      LAYER M5 ;
        RECT  45.936 0 45.96 0.084 ;
    END
  END hq0[179]
  PIN hq0[17]
    DIRECTION OUTPUT ;
    USE SIGNAL ;
    PORT
      LAYER M5 ;
        RECT  71.088 0 71.112 0.084 ;
    END
  END hq0[17]
  PIN hq0[180]
    DIRECTION OUTPUT ;
    USE SIGNAL ;
    PORT
      LAYER M5 ;
        RECT  46.032 0 46.056 0.084 ;
    END
  END hq0[180]
  PIN hq0[181]
    DIRECTION OUTPUT ;
    USE SIGNAL ;
    PORT
      LAYER M5 ;
        RECT  46.128 0 46.152 0.084 ;
    END
  END hq0[181]
  PIN hq0[182]
    DIRECTION OUTPUT ;
    USE SIGNAL ;
    PORT
      LAYER M5 ;
        RECT  46.224 0 46.248 0.084 ;
    END
  END hq0[182]
  PIN hq0[183]
    DIRECTION OUTPUT ;
    USE SIGNAL ;
    PORT
      LAYER M5 ;
        RECT  46.32 0 46.344 0.084 ;
    END
  END hq0[183]
  PIN hq0[184]
    DIRECTION OUTPUT ;
    USE SIGNAL ;
    PORT
      LAYER M5 ;
        RECT  46.416 0 46.44 0.084 ;
    END
  END hq0[184]
  PIN hq0[185]
    DIRECTION OUTPUT ;
    USE SIGNAL ;
    PORT
      LAYER M5 ;
        RECT  46.512 0 46.536 0.084 ;
    END
  END hq0[185]
  PIN hq0[186]
    DIRECTION OUTPUT ;
    USE SIGNAL ;
    PORT
      LAYER M5 ;
        RECT  46.608 0 46.632 0.084 ;
    END
  END hq0[186]
  PIN hq0[187]
    DIRECTION OUTPUT ;
    USE SIGNAL ;
    PORT
      LAYER M5 ;
        RECT  46.704 0 46.728 0.084 ;
    END
  END hq0[187]
  PIN hq0[188]
    DIRECTION OUTPUT ;
    USE SIGNAL ;
    PORT
      LAYER M5 ;
        RECT  46.8 0 46.824 0.084 ;
    END
  END hq0[188]
  PIN hq0[189]
    DIRECTION OUTPUT ;
    USE SIGNAL ;
    PORT
      LAYER M5 ;
        RECT  46.896 0 46.92 0.084 ;
    END
  END hq0[189]
  PIN hq0[18]
    DIRECTION OUTPUT ;
    USE SIGNAL ;
    PORT
      LAYER M5 ;
        RECT  71.184 0 71.208 0.084 ;
    END
  END hq0[18]
  PIN hq0[190]
    DIRECTION OUTPUT ;
    USE SIGNAL ;
    PORT
      LAYER M5 ;
        RECT  46.992 0 47.016 0.084 ;
    END
  END hq0[190]
  PIN hq0[191]
    DIRECTION OUTPUT ;
    USE SIGNAL ;
    PORT
      LAYER M5 ;
        RECT  47.088 0 47.112 0.084 ;
    END
  END hq0[191]
  PIN hq0[192]
    DIRECTION OUTPUT ;
    USE SIGNAL ;
    PORT
      LAYER M5 ;
        RECT  47.184 0 47.208 0.084 ;
    END
  END hq0[192]
  PIN hq0[193]
    DIRECTION OUTPUT ;
    USE SIGNAL ;
    PORT
      LAYER M5 ;
        RECT  47.28 0 47.304 0.084 ;
    END
  END hq0[193]
  PIN hq0[194]
    DIRECTION OUTPUT ;
    USE SIGNAL ;
    PORT
      LAYER M5 ;
        RECT  47.376 0 47.4 0.084 ;
    END
  END hq0[194]
  PIN hq0[195]
    DIRECTION OUTPUT ;
    USE SIGNAL ;
    PORT
      LAYER M5 ;
        RECT  47.472 0 47.496 0.084 ;
    END
  END hq0[195]
  PIN hq0[196]
    DIRECTION OUTPUT ;
    USE SIGNAL ;
    PORT
      LAYER M5 ;
        RECT  47.568 0 47.592 0.084 ;
    END
  END hq0[196]
  PIN hq0[197]
    DIRECTION OUTPUT ;
    USE SIGNAL ;
    PORT
      LAYER M5 ;
        RECT  47.664 0 47.688 0.084 ;
    END
  END hq0[197]
  PIN hq0[198]
    DIRECTION OUTPUT ;
    USE SIGNAL ;
    PORT
      LAYER M5 ;
        RECT  47.76 0 47.784 0.084 ;
    END
  END hq0[198]
  PIN hq0[199]
    DIRECTION OUTPUT ;
    USE SIGNAL ;
    PORT
      LAYER M5 ;
        RECT  47.856 0 47.88 0.084 ;
    END
  END hq0[199]
  PIN hq0[19]
    DIRECTION OUTPUT ;
    USE SIGNAL ;
    PORT
      LAYER M5 ;
        RECT  71.28 0 71.304 0.084 ;
    END
  END hq0[19]
  PIN hq0[1]
    DIRECTION OUTPUT ;
    USE SIGNAL ;
    PORT
      LAYER M5 ;
        RECT  75.696 0 75.72 0.084 ;
    END
  END hq0[1]
  PIN hq0[200]
    DIRECTION OUTPUT ;
    USE SIGNAL ;
    PORT
      LAYER M5 ;
        RECT  47.952 0 47.976 0.084 ;
    END
  END hq0[200]
  PIN hq0[201]
    DIRECTION OUTPUT ;
    USE SIGNAL ;
    PORT
      LAYER M5 ;
        RECT  48.048 0 48.072 0.084 ;
    END
  END hq0[201]
  PIN hq0[202]
    DIRECTION OUTPUT ;
    USE SIGNAL ;
    PORT
      LAYER M5 ;
        RECT  48.144 0 48.168 0.084 ;
    END
  END hq0[202]
  PIN hq0[203]
    DIRECTION OUTPUT ;
    USE SIGNAL ;
    PORT
      LAYER M5 ;
        RECT  48.24 0 48.264 0.084 ;
    END
  END hq0[203]
  PIN hq0[204]
    DIRECTION OUTPUT ;
    USE SIGNAL ;
    PORT
      LAYER M5 ;
        RECT  58.32 0 58.344 0.084 ;
    END
  END hq0[204]
  PIN hq0[205]
    DIRECTION OUTPUT ;
    USE SIGNAL ;
    PORT
      LAYER M5 ;
        RECT  58.416 0 58.44 0.084 ;
    END
  END hq0[205]
  PIN hq0[206]
    DIRECTION OUTPUT ;
    USE SIGNAL ;
    PORT
      LAYER M5 ;
        RECT  58.512 0 58.536 0.084 ;
    END
  END hq0[206]
  PIN hq0[207]
    DIRECTION OUTPUT ;
    USE SIGNAL ;
    PORT
      LAYER M5 ;
        RECT  58.608 0 58.632 0.084 ;
    END
  END hq0[207]
  PIN hq0[208]
    DIRECTION OUTPUT ;
    USE SIGNAL ;
    PORT
      LAYER M5 ;
        RECT  58.704 0 58.728 0.084 ;
    END
  END hq0[208]
  PIN hq0[209]
    DIRECTION OUTPUT ;
    USE SIGNAL ;
    PORT
      LAYER M5 ;
        RECT  58.8 0 58.824 0.084 ;
    END
  END hq0[209]
  PIN hq0[20]
    DIRECTION OUTPUT ;
    USE SIGNAL ;
    PORT
      LAYER M5 ;
        RECT  71.376 0 71.4 0.084 ;
    END
  END hq0[20]
  PIN hq0[210]
    DIRECTION OUTPUT ;
    USE SIGNAL ;
    PORT
      LAYER M5 ;
        RECT  58.896 0 58.92 0.084 ;
    END
  END hq0[210]
  PIN hq0[211]
    DIRECTION OUTPUT ;
    USE SIGNAL ;
    PORT
      LAYER M5 ;
        RECT  58.992 0 59.016 0.084 ;
    END
  END hq0[211]
  PIN hq0[212]
    DIRECTION OUTPUT ;
    USE SIGNAL ;
    PORT
      LAYER M5 ;
        RECT  59.088 0 59.112 0.084 ;
    END
  END hq0[212]
  PIN hq0[213]
    DIRECTION OUTPUT ;
    USE SIGNAL ;
    PORT
      LAYER M5 ;
        RECT  59.184 0 59.208 0.084 ;
    END
  END hq0[213]
  PIN hq0[214]
    DIRECTION OUTPUT ;
    USE SIGNAL ;
    PORT
      LAYER M5 ;
        RECT  59.28 0 59.304 0.084 ;
    END
  END hq0[214]
  PIN hq0[215]
    DIRECTION OUTPUT ;
    USE SIGNAL ;
    PORT
      LAYER M5 ;
        RECT  59.376 0 59.4 0.084 ;
    END
  END hq0[215]
  PIN hq0[216]
    DIRECTION OUTPUT ;
    USE SIGNAL ;
    PORT
      LAYER M5 ;
        RECT  59.472 0 59.496 0.084 ;
    END
  END hq0[216]
  PIN hq0[217]
    DIRECTION OUTPUT ;
    USE SIGNAL ;
    PORT
      LAYER M5 ;
        RECT  59.568 0 59.592 0.084 ;
    END
  END hq0[217]
  PIN hq0[218]
    DIRECTION OUTPUT ;
    USE SIGNAL ;
    PORT
      LAYER M5 ;
        RECT  59.664 0 59.688 0.084 ;
    END
  END hq0[218]
  PIN hq0[219]
    DIRECTION OUTPUT ;
    USE SIGNAL ;
    PORT
      LAYER M5 ;
        RECT  59.76 0 59.784 0.084 ;
    END
  END hq0[219]
  PIN hq0[21]
    DIRECTION OUTPUT ;
    USE SIGNAL ;
    PORT
      LAYER M5 ;
        RECT  71.472 0 71.496 0.084 ;
    END
  END hq0[21]
  PIN hq0[220]
    DIRECTION OUTPUT ;
    USE SIGNAL ;
    PORT
      LAYER M5 ;
        RECT  59.856 0 59.88 0.084 ;
    END
  END hq0[220]
  PIN hq0[221]
    DIRECTION OUTPUT ;
    USE SIGNAL ;
    PORT
      LAYER M5 ;
        RECT  59.952 0 59.976 0.084 ;
    END
  END hq0[221]
  PIN hq0[222]
    DIRECTION OUTPUT ;
    USE SIGNAL ;
    PORT
      LAYER M5 ;
        RECT  60.048 0 60.072 0.084 ;
    END
  END hq0[222]
  PIN hq0[223]
    DIRECTION OUTPUT ;
    USE SIGNAL ;
    PORT
      LAYER M5 ;
        RECT  60.144 0 60.168 0.084 ;
    END
  END hq0[223]
  PIN hq0[224]
    DIRECTION OUTPUT ;
    USE SIGNAL ;
    PORT
      LAYER M5 ;
        RECT  60.24 0 60.264 0.084 ;
    END
  END hq0[224]
  PIN hq0[225]
    DIRECTION OUTPUT ;
    USE SIGNAL ;
    PORT
      LAYER M5 ;
        RECT  60.336 0 60.36 0.084 ;
    END
  END hq0[225]
  PIN hq0[226]
    DIRECTION OUTPUT ;
    USE SIGNAL ;
    PORT
      LAYER M5 ;
        RECT  60.432 0 60.456 0.084 ;
    END
  END hq0[226]
  PIN hq0[227]
    DIRECTION OUTPUT ;
    USE SIGNAL ;
    PORT
      LAYER M5 ;
        RECT  60.528 0 60.552 0.084 ;
    END
  END hq0[227]
  PIN hq0[228]
    DIRECTION OUTPUT ;
    USE SIGNAL ;
    PORT
      LAYER M5 ;
        RECT  60.624 0 60.648 0.084 ;
    END
  END hq0[228]
  PIN hq0[229]
    DIRECTION OUTPUT ;
    USE SIGNAL ;
    PORT
      LAYER M5 ;
        RECT  60.72 0 60.744 0.084 ;
    END
  END hq0[229]
  PIN hq0[22]
    DIRECTION OUTPUT ;
    USE SIGNAL ;
    PORT
      LAYER M5 ;
        RECT  71.568 0 71.592 0.084 ;
    END
  END hq0[22]
  PIN hq0[230]
    DIRECTION OUTPUT ;
    USE SIGNAL ;
    PORT
      LAYER M5 ;
        RECT  60.816 0 60.84 0.084 ;
    END
  END hq0[230]
  PIN hq0[231]
    DIRECTION OUTPUT ;
    USE SIGNAL ;
    PORT
      LAYER M5 ;
        RECT  60.912 0 60.936 0.084 ;
    END
  END hq0[231]
  PIN hq0[232]
    DIRECTION OUTPUT ;
    USE SIGNAL ;
    PORT
      LAYER M5 ;
        RECT  61.008 0 61.032 0.084 ;
    END
  END hq0[232]
  PIN hq0[233]
    DIRECTION OUTPUT ;
    USE SIGNAL ;
    PORT
      LAYER M5 ;
        RECT  61.104 0 61.128 0.084 ;
    END
  END hq0[233]
  PIN hq0[234]
    DIRECTION OUTPUT ;
    USE SIGNAL ;
    PORT
      LAYER M5 ;
        RECT  61.2 0 61.224 0.084 ;
    END
  END hq0[234]
  PIN hq0[235]
    DIRECTION OUTPUT ;
    USE SIGNAL ;
    PORT
      LAYER M5 ;
        RECT  61.296 0 61.32 0.084 ;
    END
  END hq0[235]
  PIN hq0[236]
    DIRECTION OUTPUT ;
    USE SIGNAL ;
    PORT
      LAYER M5 ;
        RECT  89.808 0 89.832 0.084 ;
    END
  END hq0[236]
  PIN hq0[237]
    DIRECTION OUTPUT ;
    USE SIGNAL ;
    PORT
      LAYER M5 ;
        RECT  89.904 0 89.928 0.084 ;
    END
  END hq0[237]
  PIN hq0[238]
    DIRECTION OUTPUT ;
    USE SIGNAL ;
    PORT
      LAYER M5 ;
        RECT  90 0 90.024 0.084 ;
    END
  END hq0[238]
  PIN hq0[239]
    DIRECTION OUTPUT ;
    USE SIGNAL ;
    PORT
      LAYER M5 ;
        RECT  90.096 0 90.12 0.084 ;
    END
  END hq0[239]
  PIN hq0[23]
    DIRECTION OUTPUT ;
    USE SIGNAL ;
    PORT
      LAYER M5 ;
        RECT  71.664 0 71.688 0.084 ;
    END
  END hq0[23]
  PIN hq0[240]
    DIRECTION OUTPUT ;
    USE SIGNAL ;
    PORT
      LAYER M5 ;
        RECT  90.192 0 90.216 0.084 ;
    END
  END hq0[240]
  PIN hq0[241]
    DIRECTION OUTPUT ;
    USE SIGNAL ;
    PORT
      LAYER M5 ;
        RECT  90.288 0 90.312 0.084 ;
    END
  END hq0[241]
  PIN hq0[242]
    DIRECTION OUTPUT ;
    USE SIGNAL ;
    PORT
      LAYER M5 ;
        RECT  90.384 0 90.408 0.084 ;
    END
  END hq0[242]
  PIN hq0[243]
    DIRECTION OUTPUT ;
    USE SIGNAL ;
    PORT
      LAYER M5 ;
        RECT  90.48 0 90.504 0.084 ;
    END
  END hq0[243]
  PIN hq0[244]
    DIRECTION OUTPUT ;
    USE SIGNAL ;
    PORT
      LAYER M5 ;
        RECT  90.576 0 90.6 0.084 ;
    END
  END hq0[244]
  PIN hq0[245]
    DIRECTION OUTPUT ;
    USE SIGNAL ;
    PORT
      LAYER M5 ;
        RECT  90.672 0 90.696 0.084 ;
    END
  END hq0[245]
  PIN hq0[246]
    DIRECTION OUTPUT ;
    USE SIGNAL ;
    PORT
      LAYER M5 ;
        RECT  90.768 0 90.792 0.084 ;
    END
  END hq0[246]
  PIN hq0[247]
    DIRECTION OUTPUT ;
    USE SIGNAL ;
    PORT
      LAYER M5 ;
        RECT  90.864 0 90.888 0.084 ;
    END
  END hq0[247]
  PIN hq0[248]
    DIRECTION OUTPUT ;
    USE SIGNAL ;
    PORT
      LAYER M5 ;
        RECT  90.96 0 90.984 0.084 ;
    END
  END hq0[248]
  PIN hq0[249]
    DIRECTION OUTPUT ;
    USE SIGNAL ;
    PORT
      LAYER M5 ;
        RECT  91.056 0 91.08 0.084 ;
    END
  END hq0[249]
  PIN hq0[24]
    DIRECTION OUTPUT ;
    USE SIGNAL ;
    PORT
      LAYER M5 ;
        RECT  71.76 0 71.784 0.084 ;
    END
  END hq0[24]
  PIN hq0[250]
    DIRECTION OUTPUT ;
    USE SIGNAL ;
    PORT
      LAYER M5 ;
        RECT  91.152 0 91.176 0.084 ;
    END
  END hq0[250]
  PIN hq0[251]
    DIRECTION OUTPUT ;
    USE SIGNAL ;
    PORT
      LAYER M5 ;
        RECT  91.248 0 91.272 0.084 ;
    END
  END hq0[251]
  PIN hq0[252]
    DIRECTION OUTPUT ;
    USE SIGNAL ;
    PORT
      LAYER M5 ;
        RECT  91.344 0 91.368 0.084 ;
    END
  END hq0[252]
  PIN hq0[253]
    DIRECTION OUTPUT ;
    USE SIGNAL ;
    PORT
      LAYER M5 ;
        RECT  91.44 0 91.464 0.084 ;
    END
  END hq0[253]
  PIN hq0[254]
    DIRECTION OUTPUT ;
    USE SIGNAL ;
    PORT
      LAYER M5 ;
        RECT  91.536 0 91.56 0.084 ;
    END
  END hq0[254]
  PIN hq0[255]
    DIRECTION OUTPUT ;
    USE SIGNAL ;
    PORT
      LAYER M5 ;
        RECT  91.632 0 91.656 0.084 ;
    END
  END hq0[255]
  PIN hq0[25]
    DIRECTION OUTPUT ;
    USE SIGNAL ;
    PORT
      LAYER M5 ;
        RECT  71.856 0 71.88 0.084 ;
    END
  END hq0[25]
  PIN hq0[26]
    DIRECTION OUTPUT ;
    USE SIGNAL ;
    PORT
      LAYER M5 ;
        RECT  71.952 0 71.976 0.084 ;
    END
  END hq0[26]
  PIN hq0[27]
    DIRECTION OUTPUT ;
    USE SIGNAL ;
    PORT
      LAYER M5 ;
        RECT  72.048 0 72.072 0.084 ;
    END
  END hq0[27]
  PIN hq0[28]
    DIRECTION OUTPUT ;
    USE SIGNAL ;
    PORT
      LAYER M5 ;
        RECT  72.144 0 72.168 0.084 ;
    END
  END hq0[28]
  PIN hq0[29]
    DIRECTION OUTPUT ;
    USE SIGNAL ;
    PORT
      LAYER M5 ;
        RECT  72.24 0 72.264 0.084 ;
    END
  END hq0[29]
  PIN hq0[2]
    DIRECTION OUTPUT ;
    USE SIGNAL ;
    PORT
      LAYER M5 ;
        RECT  75.792 0 75.816 0.084 ;
    END
  END hq0[2]
  PIN hq0[30]
    DIRECTION OUTPUT ;
    USE SIGNAL ;
    PORT
      LAYER M5 ;
        RECT  72.336 0 72.36 0.084 ;
    END
  END hq0[30]
  PIN hq0[31]
    DIRECTION OUTPUT ;
    USE SIGNAL ;
    PORT
      LAYER M5 ;
        RECT  72.432 0 72.456 0.084 ;
    END
  END hq0[31]
  PIN hq0[32]
    DIRECTION OUTPUT ;
    USE SIGNAL ;
    PORT
      LAYER M5 ;
        RECT  72.528 0 72.552 0.084 ;
    END
  END hq0[32]
  PIN hq0[33]
    DIRECTION OUTPUT ;
    USE SIGNAL ;
    PORT
      LAYER M5 ;
        RECT  72.624 0 72.648 0.084 ;
    END
  END hq0[33]
  PIN hq0[34]
    DIRECTION OUTPUT ;
    USE SIGNAL ;
    PORT
      LAYER M5 ;
        RECT  72.72 0 72.744 0.084 ;
    END
  END hq0[34]
  PIN hq0[35]
    DIRECTION OUTPUT ;
    USE SIGNAL ;
    PORT
      LAYER M5 ;
        RECT  72.816 0 72.84 0.084 ;
    END
  END hq0[35]
  PIN hq0[36]
    DIRECTION OUTPUT ;
    USE SIGNAL ;
    PORT
      LAYER M5 ;
        RECT  72.912 0 72.936 0.084 ;
    END
  END hq0[36]
  PIN hq0[37]
    DIRECTION OUTPUT ;
    USE SIGNAL ;
    PORT
      LAYER M5 ;
        RECT  73.008 0 73.032 0.084 ;
    END
  END hq0[37]
  PIN hq0[38]
    DIRECTION OUTPUT ;
    USE SIGNAL ;
    PORT
      LAYER M5 ;
        RECT  73.104 0 73.128 0.084 ;
    END
  END hq0[38]
  PIN hq0[39]
    DIRECTION OUTPUT ;
    USE SIGNAL ;
    PORT
      LAYER M5 ;
        RECT  73.2 0 73.224 0.084 ;
    END
  END hq0[39]
  PIN hq0[3]
    DIRECTION OUTPUT ;
    USE SIGNAL ;
    PORT
      LAYER M5 ;
        RECT  75.888 0 75.912 0.084 ;
    END
  END hq0[3]
  PIN hq0[40]
    DIRECTION OUTPUT ;
    USE SIGNAL ;
    PORT
      LAYER M5 ;
        RECT  73.296 0 73.32 0.084 ;
    END
  END hq0[40]
  PIN hq0[41]
    DIRECTION OUTPUT ;
    USE SIGNAL ;
    PORT
      LAYER M5 ;
        RECT  73.392 0 73.416 0.084 ;
    END
  END hq0[41]
  PIN hq0[42]
    DIRECTION OUTPUT ;
    USE SIGNAL ;
    PORT
      LAYER M5 ;
        RECT  73.488 0 73.512 0.084 ;
    END
  END hq0[42]
  PIN hq0[43]
    DIRECTION OUTPUT ;
    USE SIGNAL ;
    PORT
      LAYER M5 ;
        RECT  73.584 0 73.608 0.084 ;
    END
  END hq0[43]
  PIN hq0[44]
    DIRECTION OUTPUT ;
    USE SIGNAL ;
    PORT
      LAYER M5 ;
        RECT  32.208 0 32.232 0.084 ;
    END
  END hq0[44]
  PIN hq0[45]
    DIRECTION OUTPUT ;
    USE SIGNAL ;
    PORT
      LAYER M5 ;
        RECT  32.304 0 32.328 0.084 ;
    END
  END hq0[45]
  PIN hq0[46]
    DIRECTION OUTPUT ;
    USE SIGNAL ;
    PORT
      LAYER M5 ;
        RECT  32.4 0 32.424 0.084 ;
    END
  END hq0[46]
  PIN hq0[47]
    DIRECTION OUTPUT ;
    USE SIGNAL ;
    PORT
      LAYER M5 ;
        RECT  32.496 0 32.52 0.084 ;
    END
  END hq0[47]
  PIN hq0[48]
    DIRECTION OUTPUT ;
    USE SIGNAL ;
    PORT
      LAYER M5 ;
        RECT  32.592 0 32.616 0.084 ;
    END
  END hq0[48]
  PIN hq0[49]
    DIRECTION OUTPUT ;
    USE SIGNAL ;
    PORT
      LAYER M5 ;
        RECT  32.688 0 32.712 0.084 ;
    END
  END hq0[49]
  PIN hq0[4]
    DIRECTION OUTPUT ;
    USE SIGNAL ;
    PORT
      LAYER M5 ;
        RECT  75.984 0 76.008 0.084 ;
    END
  END hq0[4]
  PIN hq0[50]
    DIRECTION OUTPUT ;
    USE SIGNAL ;
    PORT
      LAYER M5 ;
        RECT  32.784 0 32.808 0.084 ;
    END
  END hq0[50]
  PIN hq0[51]
    DIRECTION OUTPUT ;
    USE SIGNAL ;
    PORT
      LAYER M5 ;
        RECT  32.88 0 32.904 0.084 ;
    END
  END hq0[51]
  PIN hq0[52]
    DIRECTION OUTPUT ;
    USE SIGNAL ;
    PORT
      LAYER M5 ;
        RECT  32.976 0 33 0.084 ;
    END
  END hq0[52]
  PIN hq0[53]
    DIRECTION OUTPUT ;
    USE SIGNAL ;
    PORT
      LAYER M5 ;
        RECT  33.072 0 33.096 0.084 ;
    END
  END hq0[53]
  PIN hq0[54]
    DIRECTION OUTPUT ;
    USE SIGNAL ;
    PORT
      LAYER M5 ;
        RECT  33.168 0 33.192 0.084 ;
    END
  END hq0[54]
  PIN hq0[55]
    DIRECTION OUTPUT ;
    USE SIGNAL ;
    PORT
      LAYER M5 ;
        RECT  33.264 0 33.288 0.084 ;
    END
  END hq0[55]
  PIN hq0[56]
    DIRECTION OUTPUT ;
    USE SIGNAL ;
    PORT
      LAYER M5 ;
        RECT  33.36 0 33.384 0.084 ;
    END
  END hq0[56]
  PIN hq0[57]
    DIRECTION OUTPUT ;
    USE SIGNAL ;
    PORT
      LAYER M5 ;
        RECT  33.456 0 33.48 0.084 ;
    END
  END hq0[57]
  PIN hq0[58]
    DIRECTION OUTPUT ;
    USE SIGNAL ;
    PORT
      LAYER M5 ;
        RECT  33.552 0 33.576 0.084 ;
    END
  END hq0[58]
  PIN hq0[59]
    DIRECTION OUTPUT ;
    USE SIGNAL ;
    PORT
      LAYER M5 ;
        RECT  33.648 0 33.672 0.084 ;
    END
  END hq0[59]
  PIN hq0[5]
    DIRECTION OUTPUT ;
    USE SIGNAL ;
    PORT
      LAYER M5 ;
        RECT  76.08 0 76.104 0.084 ;
    END
  END hq0[5]
  PIN hq0[60]
    DIRECTION OUTPUT ;
    USE SIGNAL ;
    PORT
      LAYER M5 ;
        RECT  33.744 0 33.768 0.084 ;
    END
  END hq0[60]
  PIN hq0[61]
    DIRECTION OUTPUT ;
    USE SIGNAL ;
    PORT
      LAYER M5 ;
        RECT  33.84 0 33.864 0.084 ;
    END
  END hq0[61]
  PIN hq0[62]
    DIRECTION OUTPUT ;
    USE SIGNAL ;
    PORT
      LAYER M5 ;
        RECT  33.936 0 33.96 0.084 ;
    END
  END hq0[62]
  PIN hq0[63]
    DIRECTION OUTPUT ;
    USE SIGNAL ;
    PORT
      LAYER M5 ;
        RECT  34.032 0 34.056 0.084 ;
    END
  END hq0[63]
  PIN hq0[64]
    DIRECTION OUTPUT ;
    USE SIGNAL ;
    PORT
      LAYER M5 ;
        RECT  34.128 0 34.152 0.084 ;
    END
  END hq0[64]
  PIN hq0[65]
    DIRECTION OUTPUT ;
    USE SIGNAL ;
    PORT
      LAYER M5 ;
        RECT  34.224 0 34.248 0.084 ;
    END
  END hq0[65]
  PIN hq0[66]
    DIRECTION OUTPUT ;
    USE SIGNAL ;
    PORT
      LAYER M5 ;
        RECT  34.32 0 34.344 0.084 ;
    END
  END hq0[66]
  PIN hq0[67]
    DIRECTION OUTPUT ;
    USE SIGNAL ;
    PORT
      LAYER M5 ;
        RECT  34.416 0 34.44 0.084 ;
    END
  END hq0[67]
  PIN hq0[68]
    DIRECTION OUTPUT ;
    USE SIGNAL ;
    PORT
      LAYER M5 ;
        RECT  34.512 0 34.536 0.084 ;
    END
  END hq0[68]
  PIN hq0[69]
    DIRECTION OUTPUT ;
    USE SIGNAL ;
    PORT
      LAYER M5 ;
        RECT  34.608 0 34.632 0.084 ;
    END
  END hq0[69]
  PIN hq0[6]
    DIRECTION OUTPUT ;
    USE SIGNAL ;
    PORT
      LAYER M5 ;
        RECT  76.176 0 76.2 0.084 ;
    END
  END hq0[6]
  PIN hq0[70]
    DIRECTION OUTPUT ;
    USE SIGNAL ;
    PORT
      LAYER M5 ;
        RECT  34.704 0 34.728 0.084 ;
    END
  END hq0[70]
  PIN hq0[71]
    DIRECTION OUTPUT ;
    USE SIGNAL ;
    PORT
      LAYER M5 ;
        RECT  34.8 0 34.824 0.084 ;
    END
  END hq0[71]
  PIN hq0[72]
    DIRECTION OUTPUT ;
    USE SIGNAL ;
    PORT
      LAYER M5 ;
        RECT  34.896 0 34.92 0.084 ;
    END
  END hq0[72]
  PIN hq0[73]
    DIRECTION OUTPUT ;
    USE SIGNAL ;
    PORT
      LAYER M5 ;
        RECT  34.992 0 35.016 0.084 ;
    END
  END hq0[73]
  PIN hq0[74]
    DIRECTION OUTPUT ;
    USE SIGNAL ;
    PORT
      LAYER M5 ;
        RECT  35.088 0 35.112 0.084 ;
    END
  END hq0[74]
  PIN hq0[75]
    DIRECTION OUTPUT ;
    USE SIGNAL ;
    PORT
      LAYER M5 ;
        RECT  35.184 0 35.208 0.084 ;
    END
  END hq0[75]
  PIN hq0[76]
    DIRECTION OUTPUT ;
    USE SIGNAL ;
    PORT
      LAYER M5 ;
        RECT  61.392 0 61.416 0.084 ;
    END
  END hq0[76]
  PIN hq0[77]
    DIRECTION OUTPUT ;
    USE SIGNAL ;
    PORT
      LAYER M5 ;
        RECT  61.488 0 61.512 0.084 ;
    END
  END hq0[77]
  PIN hq0[78]
    DIRECTION OUTPUT ;
    USE SIGNAL ;
    PORT
      LAYER M5 ;
        RECT  61.584 0 61.608 0.084 ;
    END
  END hq0[78]
  PIN hq0[79]
    DIRECTION OUTPUT ;
    USE SIGNAL ;
    PORT
      LAYER M5 ;
        RECT  61.68 0 61.704 0.084 ;
    END
  END hq0[79]
  PIN hq0[7]
    DIRECTION OUTPUT ;
    USE SIGNAL ;
    PORT
      LAYER M5 ;
        RECT  76.272 0 76.296 0.084 ;
    END
  END hq0[7]
  PIN hq0[80]
    DIRECTION OUTPUT ;
    USE SIGNAL ;
    PORT
      LAYER M5 ;
        RECT  61.776 0 61.8 0.084 ;
    END
  END hq0[80]
  PIN hq0[81]
    DIRECTION OUTPUT ;
    USE SIGNAL ;
    PORT
      LAYER M5 ;
        RECT  61.872 0 61.896 0.084 ;
    END
  END hq0[81]
  PIN hq0[82]
    DIRECTION OUTPUT ;
    USE SIGNAL ;
    PORT
      LAYER M5 ;
        RECT  61.968 0 61.992 0.084 ;
    END
  END hq0[82]
  PIN hq0[83]
    DIRECTION OUTPUT ;
    USE SIGNAL ;
    PORT
      LAYER M5 ;
        RECT  62.064 0 62.088 0.084 ;
    END
  END hq0[83]
  PIN hq0[84]
    DIRECTION OUTPUT ;
    USE SIGNAL ;
    PORT
      LAYER M5 ;
        RECT  62.16 0 62.184 0.084 ;
    END
  END hq0[84]
  PIN hq0[85]
    DIRECTION OUTPUT ;
    USE SIGNAL ;
    PORT
      LAYER M5 ;
        RECT  62.256 0 62.28 0.084 ;
    END
  END hq0[85]
  PIN hq0[86]
    DIRECTION OUTPUT ;
    USE SIGNAL ;
    PORT
      LAYER M5 ;
        RECT  62.352 0 62.376 0.084 ;
    END
  END hq0[86]
  PIN hq0[87]
    DIRECTION OUTPUT ;
    USE SIGNAL ;
    PORT
      LAYER M5 ;
        RECT  62.448 0 62.472 0.084 ;
    END
  END hq0[87]
  PIN hq0[88]
    DIRECTION OUTPUT ;
    USE SIGNAL ;
    PORT
      LAYER M5 ;
        RECT  62.544 0 62.568 0.084 ;
    END
  END hq0[88]
  PIN hq0[89]
    DIRECTION OUTPUT ;
    USE SIGNAL ;
    PORT
      LAYER M5 ;
        RECT  62.64 0 62.664 0.084 ;
    END
  END hq0[89]
  PIN hq0[8]
    DIRECTION OUTPUT ;
    USE SIGNAL ;
    PORT
      LAYER M5 ;
        RECT  76.368 0 76.392 0.084 ;
    END
  END hq0[8]
  PIN hq0[90]
    DIRECTION OUTPUT ;
    USE SIGNAL ;
    PORT
      LAYER M5 ;
        RECT  62.736 0 62.76 0.084 ;
    END
  END hq0[90]
  PIN hq0[91]
    DIRECTION OUTPUT ;
    USE SIGNAL ;
    PORT
      LAYER M5 ;
        RECT  62.832 0 62.856 0.084 ;
    END
  END hq0[91]
  PIN hq0[92]
    DIRECTION OUTPUT ;
    USE SIGNAL ;
    PORT
      LAYER M5 ;
        RECT  62.928 0 62.952 0.084 ;
    END
  END hq0[92]
  PIN hq0[93]
    DIRECTION OUTPUT ;
    USE SIGNAL ;
    PORT
      LAYER M5 ;
        RECT  63.024 0 63.048 0.084 ;
    END
  END hq0[93]
  PIN hq0[94]
    DIRECTION OUTPUT ;
    USE SIGNAL ;
    PORT
      LAYER M5 ;
        RECT  63.12 0 63.144 0.084 ;
    END
  END hq0[94]
  PIN hq0[95]
    DIRECTION OUTPUT ;
    USE SIGNAL ;
    PORT
      LAYER M5 ;
        RECT  63.216 0 63.24 0.084 ;
    END
  END hq0[95]
  PIN hq0[96]
    DIRECTION OUTPUT ;
    USE SIGNAL ;
    PORT
      LAYER M5 ;
        RECT  63.312 0 63.336 0.084 ;
    END
  END hq0[96]
  PIN hq0[97]
    DIRECTION OUTPUT ;
    USE SIGNAL ;
    PORT
      LAYER M5 ;
        RECT  63.408 0 63.432 0.084 ;
    END
  END hq0[97]
  PIN hq0[98]
    DIRECTION OUTPUT ;
    USE SIGNAL ;
    PORT
      LAYER M5 ;
        RECT  63.504 0 63.528 0.084 ;
    END
  END hq0[98]
  PIN hq0[99]
    DIRECTION OUTPUT ;
    USE SIGNAL ;
    PORT
      LAYER M5 ;
        RECT  63.6 0 63.624 0.084 ;
    END
  END hq0[99]
  PIN hq0[9]
    DIRECTION OUTPUT ;
    USE SIGNAL ;
    PORT
      LAYER M5 ;
        RECT  76.464 0 76.488 0.084 ;
    END
  END hq0[9]
  PIN hq1[0]
    DIRECTION OUTPUT ;
    USE SIGNAL ;
    PORT
      LAYER M5 ;
        RECT  91.728 0 91.752 0.084 ;
    END
  END hq1[0]
  PIN hq1[100]
    DIRECTION OUTPUT ;
    USE SIGNAL ;
    PORT
      LAYER M5 ;
        RECT  66.768 0 66.792 0.084 ;
    END
  END hq1[100]
  PIN hq1[101]
    DIRECTION OUTPUT ;
    USE SIGNAL ;
    PORT
      LAYER M5 ;
        RECT  66.864 0 66.888 0.084 ;
    END
  END hq1[101]
  PIN hq1[102]
    DIRECTION OUTPUT ;
    USE SIGNAL ;
    PORT
      LAYER M5 ;
        RECT  66.96 0 66.984 0.084 ;
    END
  END hq1[102]
  PIN hq1[103]
    DIRECTION OUTPUT ;
    USE SIGNAL ;
    PORT
      LAYER M5 ;
        RECT  67.056 0 67.08 0.084 ;
    END
  END hq1[103]
  PIN hq1[104]
    DIRECTION OUTPUT ;
    USE SIGNAL ;
    PORT
      LAYER M5 ;
        RECT  67.152 0 67.176 0.084 ;
    END
  END hq1[104]
  PIN hq1[105]
    DIRECTION OUTPUT ;
    USE SIGNAL ;
    PORT
      LAYER M5 ;
        RECT  67.248 0 67.272 0.084 ;
    END
  END hq1[105]
  PIN hq1[106]
    DIRECTION OUTPUT ;
    USE SIGNAL ;
    PORT
      LAYER M5 ;
        RECT  67.344 0 67.368 0.084 ;
    END
  END hq1[106]
  PIN hq1[107]
    DIRECTION OUTPUT ;
    USE SIGNAL ;
    PORT
      LAYER M5 ;
        RECT  67.44 0 67.464 0.084 ;
    END
  END hq1[107]
  PIN hq1[108]
    DIRECTION OUTPUT ;
    USE SIGNAL ;
    PORT
      LAYER M5 ;
        RECT  86.736 0 86.76 0.084 ;
    END
  END hq1[108]
  PIN hq1[109]
    DIRECTION OUTPUT ;
    USE SIGNAL ;
    PORT
      LAYER M5 ;
        RECT  86.832 0 86.856 0.084 ;
    END
  END hq1[109]
  PIN hq1[10]
    DIRECTION OUTPUT ;
    USE SIGNAL ;
    PORT
      LAYER M5 ;
        RECT  92.688 0 92.712 0.084 ;
    END
  END hq1[10]
  PIN hq1[110]
    DIRECTION OUTPUT ;
    USE SIGNAL ;
    PORT
      LAYER M5 ;
        RECT  86.928 0 86.952 0.084 ;
    END
  END hq1[110]
  PIN hq1[111]
    DIRECTION OUTPUT ;
    USE SIGNAL ;
    PORT
      LAYER M5 ;
        RECT  87.024 0 87.048 0.084 ;
    END
  END hq1[111]
  PIN hq1[112]
    DIRECTION OUTPUT ;
    USE SIGNAL ;
    PORT
      LAYER M5 ;
        RECT  87.12 0 87.144 0.084 ;
    END
  END hq1[112]
  PIN hq1[113]
    DIRECTION OUTPUT ;
    USE SIGNAL ;
    PORT
      LAYER M5 ;
        RECT  87.216 0 87.24 0.084 ;
    END
  END hq1[113]
  PIN hq1[114]
    DIRECTION OUTPUT ;
    USE SIGNAL ;
    PORT
      LAYER M5 ;
        RECT  87.312 0 87.336 0.084 ;
    END
  END hq1[114]
  PIN hq1[115]
    DIRECTION OUTPUT ;
    USE SIGNAL ;
    PORT
      LAYER M5 ;
        RECT  87.408 0 87.432 0.084 ;
    END
  END hq1[115]
  PIN hq1[116]
    DIRECTION OUTPUT ;
    USE SIGNAL ;
    PORT
      LAYER M5 ;
        RECT  87.504 0 87.528 0.084 ;
    END
  END hq1[116]
  PIN hq1[117]
    DIRECTION OUTPUT ;
    USE SIGNAL ;
    PORT
      LAYER M5 ;
        RECT  87.6 0 87.624 0.084 ;
    END
  END hq1[117]
  PIN hq1[118]
    DIRECTION OUTPUT ;
    USE SIGNAL ;
    PORT
      LAYER M5 ;
        RECT  87.696 0 87.72 0.084 ;
    END
  END hq1[118]
  PIN hq1[119]
    DIRECTION OUTPUT ;
    USE SIGNAL ;
    PORT
      LAYER M5 ;
        RECT  87.792 0 87.816 0.084 ;
    END
  END hq1[119]
  PIN hq1[11]
    DIRECTION OUTPUT ;
    USE SIGNAL ;
    PORT
      LAYER M5 ;
        RECT  92.784 0 92.808 0.084 ;
    END
  END hq1[11]
  PIN hq1[120]
    DIRECTION OUTPUT ;
    USE SIGNAL ;
    PORT
      LAYER M5 ;
        RECT  87.888 0 87.912 0.084 ;
    END
  END hq1[120]
  PIN hq1[121]
    DIRECTION OUTPUT ;
    USE SIGNAL ;
    PORT
      LAYER M5 ;
        RECT  87.984 0 88.008 0.084 ;
    END
  END hq1[121]
  PIN hq1[122]
    DIRECTION OUTPUT ;
    USE SIGNAL ;
    PORT
      LAYER M5 ;
        RECT  88.08 0 88.104 0.084 ;
    END
  END hq1[122]
  PIN hq1[123]
    DIRECTION OUTPUT ;
    USE SIGNAL ;
    PORT
      LAYER M5 ;
        RECT  88.176 0 88.2 0.084 ;
    END
  END hq1[123]
  PIN hq1[124]
    DIRECTION OUTPUT ;
    USE SIGNAL ;
    PORT
      LAYER M5 ;
        RECT  88.272 0 88.296 0.084 ;
    END
  END hq1[124]
  PIN hq1[125]
    DIRECTION OUTPUT ;
    USE SIGNAL ;
    PORT
      LAYER M5 ;
        RECT  88.368 0 88.392 0.084 ;
    END
  END hq1[125]
  PIN hq1[126]
    DIRECTION OUTPUT ;
    USE SIGNAL ;
    PORT
      LAYER M5 ;
        RECT  88.464 0 88.488 0.084 ;
    END
  END hq1[126]
  PIN hq1[127]
    DIRECTION OUTPUT ;
    USE SIGNAL ;
    PORT
      LAYER M5 ;
        RECT  88.56 0 88.584 0.084 ;
    END
  END hq1[127]
  PIN hq1[128]
    DIRECTION OUTPUT ;
    USE SIGNAL ;
    PORT
      LAYER M5 ;
        RECT  88.656 0 88.68 0.084 ;
    END
  END hq1[128]
  PIN hq1[129]
    DIRECTION OUTPUT ;
    USE SIGNAL ;
    PORT
      LAYER M5 ;
        RECT  88.752 0 88.776 0.084 ;
    END
  END hq1[129]
  PIN hq1[12]
    DIRECTION OUTPUT ;
    USE SIGNAL ;
    PORT
      LAYER M5 ;
        RECT  67.536 0 67.56 0.084 ;
    END
  END hq1[12]
  PIN hq1[130]
    DIRECTION OUTPUT ;
    USE SIGNAL ;
    PORT
      LAYER M5 ;
        RECT  88.848 0 88.872 0.084 ;
    END
  END hq1[130]
  PIN hq1[131]
    DIRECTION OUTPUT ;
    USE SIGNAL ;
    PORT
      LAYER M5 ;
        RECT  88.944 0 88.968 0.084 ;
    END
  END hq1[131]
  PIN hq1[132]
    DIRECTION OUTPUT ;
    USE SIGNAL ;
    PORT
      LAYER M5 ;
        RECT  89.04 0 89.064 0.084 ;
    END
  END hq1[132]
  PIN hq1[133]
    DIRECTION OUTPUT ;
    USE SIGNAL ;
    PORT
      LAYER M5 ;
        RECT  89.136 0 89.16 0.084 ;
    END
  END hq1[133]
  PIN hq1[134]
    DIRECTION OUTPUT ;
    USE SIGNAL ;
    PORT
      LAYER M5 ;
        RECT  89.232 0 89.256 0.084 ;
    END
  END hq1[134]
  PIN hq1[135]
    DIRECTION OUTPUT ;
    USE SIGNAL ;
    PORT
      LAYER M5 ;
        RECT  89.328 0 89.352 0.084 ;
    END
  END hq1[135]
  PIN hq1[136]
    DIRECTION OUTPUT ;
    USE SIGNAL ;
    PORT
      LAYER M5 ;
        RECT  89.424 0 89.448 0.084 ;
    END
  END hq1[136]
  PIN hq1[137]
    DIRECTION OUTPUT ;
    USE SIGNAL ;
    PORT
      LAYER M5 ;
        RECT  89.52 0 89.544 0.084 ;
    END
  END hq1[137]
  PIN hq1[138]
    DIRECTION OUTPUT ;
    USE SIGNAL ;
    PORT
      LAYER M5 ;
        RECT  89.616 0 89.64 0.084 ;
    END
  END hq1[138]
  PIN hq1[139]
    DIRECTION OUTPUT ;
    USE SIGNAL ;
    PORT
      LAYER M5 ;
        RECT  89.712 0 89.736 0.084 ;
    END
  END hq1[139]
  PIN hq1[13]
    DIRECTION OUTPUT ;
    USE SIGNAL ;
    PORT
      LAYER M5 ;
        RECT  67.632 0 67.656 0.084 ;
    END
  END hq1[13]
  PIN hq1[140]
    DIRECTION OUTPUT ;
    USE SIGNAL ;
    PORT
      LAYER M5 ;
        RECT  26.064 0 26.088 0.084 ;
    END
  END hq1[140]
  PIN hq1[141]
    DIRECTION OUTPUT ;
    USE SIGNAL ;
    PORT
      LAYER M5 ;
        RECT  26.16 0 26.184 0.084 ;
    END
  END hq1[141]
  PIN hq1[142]
    DIRECTION OUTPUT ;
    USE SIGNAL ;
    PORT
      LAYER M5 ;
        RECT  26.256 0 26.28 0.084 ;
    END
  END hq1[142]
  PIN hq1[143]
    DIRECTION OUTPUT ;
    USE SIGNAL ;
    PORT
      LAYER M5 ;
        RECT  26.352 0 26.376 0.084 ;
    END
  END hq1[143]
  PIN hq1[144]
    DIRECTION OUTPUT ;
    USE SIGNAL ;
    PORT
      LAYER M5 ;
        RECT  26.448 0 26.472 0.084 ;
    END
  END hq1[144]
  PIN hq1[145]
    DIRECTION OUTPUT ;
    USE SIGNAL ;
    PORT
      LAYER M5 ;
        RECT  26.544 0 26.568 0.084 ;
    END
  END hq1[145]
  PIN hq1[146]
    DIRECTION OUTPUT ;
    USE SIGNAL ;
    PORT
      LAYER M5 ;
        RECT  26.64 0 26.664 0.084 ;
    END
  END hq1[146]
  PIN hq1[147]
    DIRECTION OUTPUT ;
    USE SIGNAL ;
    PORT
      LAYER M5 ;
        RECT  26.736 0 26.76 0.084 ;
    END
  END hq1[147]
  PIN hq1[148]
    DIRECTION OUTPUT ;
    USE SIGNAL ;
    PORT
      LAYER M5 ;
        RECT  26.832 0 26.856 0.084 ;
    END
  END hq1[148]
  PIN hq1[149]
    DIRECTION OUTPUT ;
    USE SIGNAL ;
    PORT
      LAYER M5 ;
        RECT  26.928 0 26.952 0.084 ;
    END
  END hq1[149]
  PIN hq1[14]
    DIRECTION OUTPUT ;
    USE SIGNAL ;
    PORT
      LAYER M5 ;
        RECT  67.728 0 67.752 0.084 ;
    END
  END hq1[14]
  PIN hq1[150]
    DIRECTION OUTPUT ;
    USE SIGNAL ;
    PORT
      LAYER M5 ;
        RECT  27.024 0 27.048 0.084 ;
    END
  END hq1[150]
  PIN hq1[151]
    DIRECTION OUTPUT ;
    USE SIGNAL ;
    PORT
      LAYER M5 ;
        RECT  27.12 0 27.144 0.084 ;
    END
  END hq1[151]
  PIN hq1[152]
    DIRECTION OUTPUT ;
    USE SIGNAL ;
    PORT
      LAYER M5 ;
        RECT  27.216 0 27.24 0.084 ;
    END
  END hq1[152]
  PIN hq1[153]
    DIRECTION OUTPUT ;
    USE SIGNAL ;
    PORT
      LAYER M5 ;
        RECT  27.312 0 27.336 0.084 ;
    END
  END hq1[153]
  PIN hq1[154]
    DIRECTION OUTPUT ;
    USE SIGNAL ;
    PORT
      LAYER M5 ;
        RECT  27.408 0 27.432 0.084 ;
    END
  END hq1[154]
  PIN hq1[155]
    DIRECTION OUTPUT ;
    USE SIGNAL ;
    PORT
      LAYER M5 ;
        RECT  27.504 0 27.528 0.084 ;
    END
  END hq1[155]
  PIN hq1[156]
    DIRECTION OUTPUT ;
    USE SIGNAL ;
    PORT
      LAYER M5 ;
        RECT  27.6 0 27.624 0.084 ;
    END
  END hq1[156]
  PIN hq1[157]
    DIRECTION OUTPUT ;
    USE SIGNAL ;
    PORT
      LAYER M5 ;
        RECT  27.696 0 27.72 0.084 ;
    END
  END hq1[157]
  PIN hq1[158]
    DIRECTION OUTPUT ;
    USE SIGNAL ;
    PORT
      LAYER M5 ;
        RECT  27.792 0 27.816 0.084 ;
    END
  END hq1[158]
  PIN hq1[159]
    DIRECTION OUTPUT ;
    USE SIGNAL ;
    PORT
      LAYER M5 ;
        RECT  27.888 0 27.912 0.084 ;
    END
  END hq1[159]
  PIN hq1[15]
    DIRECTION OUTPUT ;
    USE SIGNAL ;
    PORT
      LAYER M5 ;
        RECT  67.824 0 67.848 0.084 ;
    END
  END hq1[15]
  PIN hq1[160]
    DIRECTION OUTPUT ;
    USE SIGNAL ;
    PORT
      LAYER M5 ;
        RECT  27.984 0 28.008 0.084 ;
    END
  END hq1[160]
  PIN hq1[161]
    DIRECTION OUTPUT ;
    USE SIGNAL ;
    PORT
      LAYER M5 ;
        RECT  28.08 0 28.104 0.084 ;
    END
  END hq1[161]
  PIN hq1[162]
    DIRECTION OUTPUT ;
    USE SIGNAL ;
    PORT
      LAYER M5 ;
        RECT  28.176 0 28.2 0.084 ;
    END
  END hq1[162]
  PIN hq1[163]
    DIRECTION OUTPUT ;
    USE SIGNAL ;
    PORT
      LAYER M5 ;
        RECT  28.272 0 28.296 0.084 ;
    END
  END hq1[163]
  PIN hq1[164]
    DIRECTION OUTPUT ;
    USE SIGNAL ;
    PORT
      LAYER M5 ;
        RECT  28.368 0 28.392 0.084 ;
    END
  END hq1[164]
  PIN hq1[165]
    DIRECTION OUTPUT ;
    USE SIGNAL ;
    PORT
      LAYER M5 ;
        RECT  28.464 0 28.488 0.084 ;
    END
  END hq1[165]
  PIN hq1[166]
    DIRECTION OUTPUT ;
    USE SIGNAL ;
    PORT
      LAYER M5 ;
        RECT  28.56 0 28.584 0.084 ;
    END
  END hq1[166]
  PIN hq1[167]
    DIRECTION OUTPUT ;
    USE SIGNAL ;
    PORT
      LAYER M5 ;
        RECT  28.656 0 28.68 0.084 ;
    END
  END hq1[167]
  PIN hq1[168]
    DIRECTION OUTPUT ;
    USE SIGNAL ;
    PORT
      LAYER M5 ;
        RECT  28.752 0 28.776 0.084 ;
    END
  END hq1[168]
  PIN hq1[169]
    DIRECTION OUTPUT ;
    USE SIGNAL ;
    PORT
      LAYER M5 ;
        RECT  28.848 0 28.872 0.084 ;
    END
  END hq1[169]
  PIN hq1[16]
    DIRECTION OUTPUT ;
    USE SIGNAL ;
    PORT
      LAYER M5 ;
        RECT  67.92 0 67.944 0.084 ;
    END
  END hq1[16]
  PIN hq1[170]
    DIRECTION OUTPUT ;
    USE SIGNAL ;
    PORT
      LAYER M5 ;
        RECT  28.944 0 28.968 0.084 ;
    END
  END hq1[170]
  PIN hq1[171]
    DIRECTION OUTPUT ;
    USE SIGNAL ;
    PORT
      LAYER M5 ;
        RECT  29.04 0 29.064 0.084 ;
    END
  END hq1[171]
  PIN hq1[172]
    DIRECTION OUTPUT ;
    USE SIGNAL ;
    PORT
      LAYER M5 ;
        RECT  48.336 0 48.36 0.084 ;
    END
  END hq1[172]
  PIN hq1[173]
    DIRECTION OUTPUT ;
    USE SIGNAL ;
    PORT
      LAYER M5 ;
        RECT  48.432 0 48.456 0.084 ;
    END
  END hq1[173]
  PIN hq1[174]
    DIRECTION OUTPUT ;
    USE SIGNAL ;
    PORT
      LAYER M5 ;
        RECT  48.528 0 48.552 0.084 ;
    END
  END hq1[174]
  PIN hq1[175]
    DIRECTION OUTPUT ;
    USE SIGNAL ;
    PORT
      LAYER M5 ;
        RECT  48.624 0 48.648 0.084 ;
    END
  END hq1[175]
  PIN hq1[176]
    DIRECTION OUTPUT ;
    USE SIGNAL ;
    PORT
      LAYER M5 ;
        RECT  48.72 0 48.744 0.084 ;
    END
  END hq1[176]
  PIN hq1[177]
    DIRECTION OUTPUT ;
    USE SIGNAL ;
    PORT
      LAYER M5 ;
        RECT  48.816 0 48.84 0.084 ;
    END
  END hq1[177]
  PIN hq1[178]
    DIRECTION OUTPUT ;
    USE SIGNAL ;
    PORT
      LAYER M5 ;
        RECT  48.912 0 48.936 0.084 ;
    END
  END hq1[178]
  PIN hq1[179]
    DIRECTION OUTPUT ;
    USE SIGNAL ;
    PORT
      LAYER M5 ;
        RECT  49.008 0 49.032 0.084 ;
    END
  END hq1[179]
  PIN hq1[17]
    DIRECTION OUTPUT ;
    USE SIGNAL ;
    PORT
      LAYER M5 ;
        RECT  68.016 0 68.04 0.084 ;
    END
  END hq1[17]
  PIN hq1[180]
    DIRECTION OUTPUT ;
    USE SIGNAL ;
    PORT
      LAYER M5 ;
        RECT  49.104 0 49.128 0.084 ;
    END
  END hq1[180]
  PIN hq1[181]
    DIRECTION OUTPUT ;
    USE SIGNAL ;
    PORT
      LAYER M5 ;
        RECT  49.2 0 49.224 0.084 ;
    END
  END hq1[181]
  PIN hq1[182]
    DIRECTION OUTPUT ;
    USE SIGNAL ;
    PORT
      LAYER M5 ;
        RECT  49.296 0 49.32 0.084 ;
    END
  END hq1[182]
  PIN hq1[183]
    DIRECTION OUTPUT ;
    USE SIGNAL ;
    PORT
      LAYER M5 ;
        RECT  49.392 0 49.416 0.084 ;
    END
  END hq1[183]
  PIN hq1[184]
    DIRECTION OUTPUT ;
    USE SIGNAL ;
    PORT
      LAYER M5 ;
        RECT  49.488 0 49.512 0.084 ;
    END
  END hq1[184]
  PIN hq1[185]
    DIRECTION OUTPUT ;
    USE SIGNAL ;
    PORT
      LAYER M5 ;
        RECT  49.584 0 49.608 0.084 ;
    END
  END hq1[185]
  PIN hq1[186]
    DIRECTION OUTPUT ;
    USE SIGNAL ;
    PORT
      LAYER M5 ;
        RECT  49.68 0 49.704 0.084 ;
    END
  END hq1[186]
  PIN hq1[187]
    DIRECTION OUTPUT ;
    USE SIGNAL ;
    PORT
      LAYER M5 ;
        RECT  49.776 0 49.8 0.084 ;
    END
  END hq1[187]
  PIN hq1[188]
    DIRECTION OUTPUT ;
    USE SIGNAL ;
    PORT
      LAYER M5 ;
        RECT  49.872 0 49.896 0.084 ;
    END
  END hq1[188]
  PIN hq1[189]
    DIRECTION OUTPUT ;
    USE SIGNAL ;
    PORT
      LAYER M5 ;
        RECT  49.968 0 49.992 0.084 ;
    END
  END hq1[189]
  PIN hq1[18]
    DIRECTION OUTPUT ;
    USE SIGNAL ;
    PORT
      LAYER M5 ;
        RECT  68.112 0 68.136 0.084 ;
    END
  END hq1[18]
  PIN hq1[190]
    DIRECTION OUTPUT ;
    USE SIGNAL ;
    PORT
      LAYER M5 ;
        RECT  50.064 0 50.088 0.084 ;
    END
  END hq1[190]
  PIN hq1[191]
    DIRECTION OUTPUT ;
    USE SIGNAL ;
    PORT
      LAYER M5 ;
        RECT  50.16 0 50.184 0.084 ;
    END
  END hq1[191]
  PIN hq1[192]
    DIRECTION OUTPUT ;
    USE SIGNAL ;
    PORT
      LAYER M5 ;
        RECT  50.256 0 50.28 0.084 ;
    END
  END hq1[192]
  PIN hq1[193]
    DIRECTION OUTPUT ;
    USE SIGNAL ;
    PORT
      LAYER M5 ;
        RECT  50.352 0 50.376 0.084 ;
    END
  END hq1[193]
  PIN hq1[194]
    DIRECTION OUTPUT ;
    USE SIGNAL ;
    PORT
      LAYER M5 ;
        RECT  50.448 0 50.472 0.084 ;
    END
  END hq1[194]
  PIN hq1[195]
    DIRECTION OUTPUT ;
    USE SIGNAL ;
    PORT
      LAYER M5 ;
        RECT  50.544 0 50.568 0.084 ;
    END
  END hq1[195]
  PIN hq1[196]
    DIRECTION OUTPUT ;
    USE SIGNAL ;
    PORT
      LAYER M5 ;
        RECT  50.64 0 50.664 0.084 ;
    END
  END hq1[196]
  PIN hq1[197]
    DIRECTION OUTPUT ;
    USE SIGNAL ;
    PORT
      LAYER M5 ;
        RECT  50.736 0 50.76 0.084 ;
    END
  END hq1[197]
  PIN hq1[198]
    DIRECTION OUTPUT ;
    USE SIGNAL ;
    PORT
      LAYER M5 ;
        RECT  50.832 0 50.856 0.084 ;
    END
  END hq1[198]
  PIN hq1[199]
    DIRECTION OUTPUT ;
    USE SIGNAL ;
    PORT
      LAYER M5 ;
        RECT  50.928 0 50.952 0.084 ;
    END
  END hq1[199]
  PIN hq1[19]
    DIRECTION OUTPUT ;
    USE SIGNAL ;
    PORT
      LAYER M5 ;
        RECT  68.208 0 68.232 0.084 ;
    END
  END hq1[19]
  PIN hq1[1]
    DIRECTION OUTPUT ;
    USE SIGNAL ;
    PORT
      LAYER M5 ;
        RECT  91.824 0 91.848 0.084 ;
    END
  END hq1[1]
  PIN hq1[200]
    DIRECTION OUTPUT ;
    USE SIGNAL ;
    PORT
      LAYER M5 ;
        RECT  51.024 0 51.048 0.084 ;
    END
  END hq1[200]
  PIN hq1[201]
    DIRECTION OUTPUT ;
    USE SIGNAL ;
    PORT
      LAYER M5 ;
        RECT  51.12 0 51.144 0.084 ;
    END
  END hq1[201]
  PIN hq1[202]
    DIRECTION OUTPUT ;
    USE SIGNAL ;
    PORT
      LAYER M5 ;
        RECT  51.216 0 51.24 0.084 ;
    END
  END hq1[202]
  PIN hq1[203]
    DIRECTION OUTPUT ;
    USE SIGNAL ;
    PORT
      LAYER M5 ;
        RECT  51.312 0 51.336 0.084 ;
    END
  END hq1[203]
  PIN hq1[204]
    DIRECTION OUTPUT ;
    USE SIGNAL ;
    PORT
      LAYER M5 ;
        RECT  54.48 0 54.504 0.084 ;
    END
  END hq1[204]
  PIN hq1[205]
    DIRECTION OUTPUT ;
    USE SIGNAL ;
    PORT
      LAYER M5 ;
        RECT  54.576 0 54.6 0.084 ;
    END
  END hq1[205]
  PIN hq1[206]
    DIRECTION OUTPUT ;
    USE SIGNAL ;
    PORT
      LAYER M5 ;
        RECT  54.672 0 54.696 0.084 ;
    END
  END hq1[206]
  PIN hq1[207]
    DIRECTION OUTPUT ;
    USE SIGNAL ;
    PORT
      LAYER M5 ;
        RECT  54.768 0 54.792 0.084 ;
    END
  END hq1[207]
  PIN hq1[208]
    DIRECTION OUTPUT ;
    USE SIGNAL ;
    PORT
      LAYER M5 ;
        RECT  54.864 0 54.888 0.084 ;
    END
  END hq1[208]
  PIN hq1[209]
    DIRECTION OUTPUT ;
    USE SIGNAL ;
    PORT
      LAYER M5 ;
        RECT  54.96 0 54.984 0.084 ;
    END
  END hq1[209]
  PIN hq1[20]
    DIRECTION OUTPUT ;
    USE SIGNAL ;
    PORT
      LAYER M5 ;
        RECT  68.304 0 68.328 0.084 ;
    END
  END hq1[20]
  PIN hq1[210]
    DIRECTION OUTPUT ;
    USE SIGNAL ;
    PORT
      LAYER M5 ;
        RECT  55.056 0 55.08 0.084 ;
    END
  END hq1[210]
  PIN hq1[211]
    DIRECTION OUTPUT ;
    USE SIGNAL ;
    PORT
      LAYER M5 ;
        RECT  55.152 0 55.176 0.084 ;
    END
  END hq1[211]
  PIN hq1[212]
    DIRECTION OUTPUT ;
    USE SIGNAL ;
    PORT
      LAYER M5 ;
        RECT  55.248 0 55.272 0.084 ;
    END
  END hq1[212]
  PIN hq1[213]
    DIRECTION OUTPUT ;
    USE SIGNAL ;
    PORT
      LAYER M5 ;
        RECT  55.344 0 55.368 0.084 ;
    END
  END hq1[213]
  PIN hq1[214]
    DIRECTION OUTPUT ;
    USE SIGNAL ;
    PORT
      LAYER M5 ;
        RECT  55.44 0 55.464 0.084 ;
    END
  END hq1[214]
  PIN hq1[215]
    DIRECTION OUTPUT ;
    USE SIGNAL ;
    PORT
      LAYER M5 ;
        RECT  55.536 0 55.56 0.084 ;
    END
  END hq1[215]
  PIN hq1[216]
    DIRECTION OUTPUT ;
    USE SIGNAL ;
    PORT
      LAYER M5 ;
        RECT  55.632 0 55.656 0.084 ;
    END
  END hq1[216]
  PIN hq1[217]
    DIRECTION OUTPUT ;
    USE SIGNAL ;
    PORT
      LAYER M5 ;
        RECT  55.728 0 55.752 0.084 ;
    END
  END hq1[217]
  PIN hq1[218]
    DIRECTION OUTPUT ;
    USE SIGNAL ;
    PORT
      LAYER M5 ;
        RECT  55.824 0 55.848 0.084 ;
    END
  END hq1[218]
  PIN hq1[219]
    DIRECTION OUTPUT ;
    USE SIGNAL ;
    PORT
      LAYER M5 ;
        RECT  55.92 0 55.944 0.084 ;
    END
  END hq1[219]
  PIN hq1[21]
    DIRECTION OUTPUT ;
    USE SIGNAL ;
    PORT
      LAYER M5 ;
        RECT  68.4 0 68.424 0.084 ;
    END
  END hq1[21]
  PIN hq1[220]
    DIRECTION OUTPUT ;
    USE SIGNAL ;
    PORT
      LAYER M5 ;
        RECT  56.016 0 56.04 0.084 ;
    END
  END hq1[220]
  PIN hq1[221]
    DIRECTION OUTPUT ;
    USE SIGNAL ;
    PORT
      LAYER M5 ;
        RECT  56.112 0 56.136 0.084 ;
    END
  END hq1[221]
  PIN hq1[222]
    DIRECTION OUTPUT ;
    USE SIGNAL ;
    PORT
      LAYER M5 ;
        RECT  56.208 0 56.232 0.084 ;
    END
  END hq1[222]
  PIN hq1[223]
    DIRECTION OUTPUT ;
    USE SIGNAL ;
    PORT
      LAYER M5 ;
        RECT  56.304 0 56.328 0.084 ;
    END
  END hq1[223]
  PIN hq1[224]
    DIRECTION OUTPUT ;
    USE SIGNAL ;
    PORT
      LAYER M5 ;
        RECT  56.4 0 56.424 0.084 ;
    END
  END hq1[224]
  PIN hq1[225]
    DIRECTION OUTPUT ;
    USE SIGNAL ;
    PORT
      LAYER M5 ;
        RECT  56.496 0 56.52 0.084 ;
    END
  END hq1[225]
  PIN hq1[226]
    DIRECTION OUTPUT ;
    USE SIGNAL ;
    PORT
      LAYER M5 ;
        RECT  56.592 0 56.616 0.084 ;
    END
  END hq1[226]
  PIN hq1[227]
    DIRECTION OUTPUT ;
    USE SIGNAL ;
    PORT
      LAYER M5 ;
        RECT  56.688 0 56.712 0.084 ;
    END
  END hq1[227]
  PIN hq1[228]
    DIRECTION OUTPUT ;
    USE SIGNAL ;
    PORT
      LAYER M5 ;
        RECT  56.784 0 56.808 0.084 ;
    END
  END hq1[228]
  PIN hq1[229]
    DIRECTION OUTPUT ;
    USE SIGNAL ;
    PORT
      LAYER M5 ;
        RECT  56.88 0 56.904 0.084 ;
    END
  END hq1[229]
  PIN hq1[22]
    DIRECTION OUTPUT ;
    USE SIGNAL ;
    PORT
      LAYER M5 ;
        RECT  68.496 0 68.52 0.084 ;
    END
  END hq1[22]
  PIN hq1[230]
    DIRECTION OUTPUT ;
    USE SIGNAL ;
    PORT
      LAYER M5 ;
        RECT  56.976 0 57 0.084 ;
    END
  END hq1[230]
  PIN hq1[231]
    DIRECTION OUTPUT ;
    USE SIGNAL ;
    PORT
      LAYER M5 ;
        RECT  57.072 0 57.096 0.084 ;
    END
  END hq1[231]
  PIN hq1[232]
    DIRECTION OUTPUT ;
    USE SIGNAL ;
    PORT
      LAYER M5 ;
        RECT  57.168 0 57.192 0.084 ;
    END
  END hq1[232]
  PIN hq1[233]
    DIRECTION OUTPUT ;
    USE SIGNAL ;
    PORT
      LAYER M5 ;
        RECT  57.264 0 57.288 0.084 ;
    END
  END hq1[233]
  PIN hq1[234]
    DIRECTION OUTPUT ;
    USE SIGNAL ;
    PORT
      LAYER M5 ;
        RECT  57.36 0 57.384 0.084 ;
    END
  END hq1[234]
  PIN hq1[235]
    DIRECTION OUTPUT ;
    USE SIGNAL ;
    PORT
      LAYER M5 ;
        RECT  57.456 0 57.48 0.084 ;
    END
  END hq1[235]
  PIN hq1[236]
    DIRECTION OUTPUT ;
    USE SIGNAL ;
    PORT
      LAYER M5 ;
        RECT  92.88 0 92.904 0.084 ;
    END
  END hq1[236]
  PIN hq1[237]
    DIRECTION OUTPUT ;
    USE SIGNAL ;
    PORT
      LAYER M5 ;
        RECT  92.976 0 93 0.084 ;
    END
  END hq1[237]
  PIN hq1[238]
    DIRECTION OUTPUT ;
    USE SIGNAL ;
    PORT
      LAYER M5 ;
        RECT  93.072 0 93.096 0.084 ;
    END
  END hq1[238]
  PIN hq1[239]
    DIRECTION OUTPUT ;
    USE SIGNAL ;
    PORT
      LAYER M5 ;
        RECT  93.168 0 93.192 0.084 ;
    END
  END hq1[239]
  PIN hq1[23]
    DIRECTION OUTPUT ;
    USE SIGNAL ;
    PORT
      LAYER M5 ;
        RECT  68.592 0 68.616 0.084 ;
    END
  END hq1[23]
  PIN hq1[240]
    DIRECTION OUTPUT ;
    USE SIGNAL ;
    PORT
      LAYER M5 ;
        RECT  93.264 0 93.288 0.084 ;
    END
  END hq1[240]
  PIN hq1[241]
    DIRECTION OUTPUT ;
    USE SIGNAL ;
    PORT
      LAYER M5 ;
        RECT  93.36 0 93.384 0.084 ;
    END
  END hq1[241]
  PIN hq1[242]
    DIRECTION OUTPUT ;
    USE SIGNAL ;
    PORT
      LAYER M5 ;
        RECT  93.456 0 93.48 0.084 ;
    END
  END hq1[242]
  PIN hq1[243]
    DIRECTION OUTPUT ;
    USE SIGNAL ;
    PORT
      LAYER M5 ;
        RECT  93.552 0 93.576 0.084 ;
    END
  END hq1[243]
  PIN hq1[244]
    DIRECTION OUTPUT ;
    USE SIGNAL ;
    PORT
      LAYER M5 ;
        RECT  93.648 0 93.672 0.084 ;
    END
  END hq1[244]
  PIN hq1[245]
    DIRECTION OUTPUT ;
    USE SIGNAL ;
    PORT
      LAYER M5 ;
        RECT  93.744 0 93.768 0.084 ;
    END
  END hq1[245]
  PIN hq1[246]
    DIRECTION OUTPUT ;
    USE SIGNAL ;
    PORT
      LAYER M5 ;
        RECT  93.84 0 93.864 0.084 ;
    END
  END hq1[246]
  PIN hq1[247]
    DIRECTION OUTPUT ;
    USE SIGNAL ;
    PORT
      LAYER M5 ;
        RECT  93.936 0 93.96 0.084 ;
    END
  END hq1[247]
  PIN hq1[248]
    DIRECTION OUTPUT ;
    USE SIGNAL ;
    PORT
      LAYER M5 ;
        RECT  94.032 0 94.056 0.084 ;
    END
  END hq1[248]
  PIN hq1[249]
    DIRECTION OUTPUT ;
    USE SIGNAL ;
    PORT
      LAYER M5 ;
        RECT  94.128 0 94.152 0.084 ;
    END
  END hq1[249]
  PIN hq1[24]
    DIRECTION OUTPUT ;
    USE SIGNAL ;
    PORT
      LAYER M5 ;
        RECT  68.688 0 68.712 0.084 ;
    END
  END hq1[24]
  PIN hq1[250]
    DIRECTION OUTPUT ;
    USE SIGNAL ;
    PORT
      LAYER M5 ;
        RECT  94.224 0 94.248 0.084 ;
    END
  END hq1[250]
  PIN hq1[251]
    DIRECTION OUTPUT ;
    USE SIGNAL ;
    PORT
      LAYER M5 ;
        RECT  94.32 0 94.344 0.084 ;
    END
  END hq1[251]
  PIN hq1[252]
    DIRECTION OUTPUT ;
    USE SIGNAL ;
    PORT
      LAYER M5 ;
        RECT  94.416 0 94.44 0.084 ;
    END
  END hq1[252]
  PIN hq1[253]
    DIRECTION OUTPUT ;
    USE SIGNAL ;
    PORT
      LAYER M5 ;
        RECT  94.512 0 94.536 0.084 ;
    END
  END hq1[253]
  PIN hq1[254]
    DIRECTION OUTPUT ;
    USE SIGNAL ;
    PORT
      LAYER M5 ;
        RECT  94.608 0 94.632 0.084 ;
    END
  END hq1[254]
  PIN hq1[255]
    DIRECTION OUTPUT ;
    USE SIGNAL ;
    PORT
      LAYER M5 ;
        RECT  94.704 0 94.728 0.084 ;
    END
  END hq1[255]
  PIN hq1[25]
    DIRECTION OUTPUT ;
    USE SIGNAL ;
    PORT
      LAYER M5 ;
        RECT  68.784 0 68.808 0.084 ;
    END
  END hq1[25]
  PIN hq1[26]
    DIRECTION OUTPUT ;
    USE SIGNAL ;
    PORT
      LAYER M5 ;
        RECT  68.88 0 68.904 0.084 ;
    END
  END hq1[26]
  PIN hq1[27]
    DIRECTION OUTPUT ;
    USE SIGNAL ;
    PORT
      LAYER M5 ;
        RECT  68.976 0 69 0.084 ;
    END
  END hq1[27]
  PIN hq1[28]
    DIRECTION OUTPUT ;
    USE SIGNAL ;
    PORT
      LAYER M5 ;
        RECT  69.072 0 69.096 0.084 ;
    END
  END hq1[28]
  PIN hq1[29]
    DIRECTION OUTPUT ;
    USE SIGNAL ;
    PORT
      LAYER M5 ;
        RECT  69.168 0 69.192 0.084 ;
    END
  END hq1[29]
  PIN hq1[2]
    DIRECTION OUTPUT ;
    USE SIGNAL ;
    PORT
      LAYER M5 ;
        RECT  91.92 0 91.944 0.084 ;
    END
  END hq1[2]
  PIN hq1[30]
    DIRECTION OUTPUT ;
    USE SIGNAL ;
    PORT
      LAYER M5 ;
        RECT  69.264 0 69.288 0.084 ;
    END
  END hq1[30]
  PIN hq1[31]
    DIRECTION OUTPUT ;
    USE SIGNAL ;
    PORT
      LAYER M5 ;
        RECT  69.36 0 69.384 0.084 ;
    END
  END hq1[31]
  PIN hq1[32]
    DIRECTION OUTPUT ;
    USE SIGNAL ;
    PORT
      LAYER M5 ;
        RECT  69.456 0 69.48 0.084 ;
    END
  END hq1[32]
  PIN hq1[33]
    DIRECTION OUTPUT ;
    USE SIGNAL ;
    PORT
      LAYER M5 ;
        RECT  69.552 0 69.576 0.084 ;
    END
  END hq1[33]
  PIN hq1[34]
    DIRECTION OUTPUT ;
    USE SIGNAL ;
    PORT
      LAYER M5 ;
        RECT  69.648 0 69.672 0.084 ;
    END
  END hq1[34]
  PIN hq1[35]
    DIRECTION OUTPUT ;
    USE SIGNAL ;
    PORT
      LAYER M5 ;
        RECT  69.744 0 69.768 0.084 ;
    END
  END hq1[35]
  PIN hq1[36]
    DIRECTION OUTPUT ;
    USE SIGNAL ;
    PORT
      LAYER M5 ;
        RECT  69.84 0 69.864 0.084 ;
    END
  END hq1[36]
  PIN hq1[37]
    DIRECTION OUTPUT ;
    USE SIGNAL ;
    PORT
      LAYER M5 ;
        RECT  69.936 0 69.96 0.084 ;
    END
  END hq1[37]
  PIN hq1[38]
    DIRECTION OUTPUT ;
    USE SIGNAL ;
    PORT
      LAYER M5 ;
        RECT  70.032 0 70.056 0.084 ;
    END
  END hq1[38]
  PIN hq1[39]
    DIRECTION OUTPUT ;
    USE SIGNAL ;
    PORT
      LAYER M5 ;
        RECT  70.128 0 70.152 0.084 ;
    END
  END hq1[39]
  PIN hq1[3]
    DIRECTION OUTPUT ;
    USE SIGNAL ;
    PORT
      LAYER M5 ;
        RECT  92.016 0 92.04 0.084 ;
    END
  END hq1[3]
  PIN hq1[40]
    DIRECTION OUTPUT ;
    USE SIGNAL ;
    PORT
      LAYER M5 ;
        RECT  70.224 0 70.248 0.084 ;
    END
  END hq1[40]
  PIN hq1[41]
    DIRECTION OUTPUT ;
    USE SIGNAL ;
    PORT
      LAYER M5 ;
        RECT  70.32 0 70.344 0.084 ;
    END
  END hq1[41]
  PIN hq1[42]
    DIRECTION OUTPUT ;
    USE SIGNAL ;
    PORT
      LAYER M5 ;
        RECT  70.416 0 70.44 0.084 ;
    END
  END hq1[42]
  PIN hq1[43]
    DIRECTION OUTPUT ;
    USE SIGNAL ;
    PORT
      LAYER M5 ;
        RECT  70.512 0 70.536 0.084 ;
    END
  END hq1[43]
  PIN hq1[44]
    DIRECTION OUTPUT ;
    USE SIGNAL ;
    PORT
      LAYER M5 ;
        RECT  29.136 0 29.16 0.084 ;
    END
  END hq1[44]
  PIN hq1[45]
    DIRECTION OUTPUT ;
    USE SIGNAL ;
    PORT
      LAYER M5 ;
        RECT  29.232 0 29.256 0.084 ;
    END
  END hq1[45]
  PIN hq1[46]
    DIRECTION OUTPUT ;
    USE SIGNAL ;
    PORT
      LAYER M5 ;
        RECT  29.328 0 29.352 0.084 ;
    END
  END hq1[46]
  PIN hq1[47]
    DIRECTION OUTPUT ;
    USE SIGNAL ;
    PORT
      LAYER M5 ;
        RECT  29.424 0 29.448 0.084 ;
    END
  END hq1[47]
  PIN hq1[48]
    DIRECTION OUTPUT ;
    USE SIGNAL ;
    PORT
      LAYER M5 ;
        RECT  29.52 0 29.544 0.084 ;
    END
  END hq1[48]
  PIN hq1[49]
    DIRECTION OUTPUT ;
    USE SIGNAL ;
    PORT
      LAYER M5 ;
        RECT  29.616 0 29.64 0.084 ;
    END
  END hq1[49]
  PIN hq1[4]
    DIRECTION OUTPUT ;
    USE SIGNAL ;
    PORT
      LAYER M5 ;
        RECT  92.112 0 92.136 0.084 ;
    END
  END hq1[4]
  PIN hq1[50]
    DIRECTION OUTPUT ;
    USE SIGNAL ;
    PORT
      LAYER M5 ;
        RECT  29.712 0 29.736 0.084 ;
    END
  END hq1[50]
  PIN hq1[51]
    DIRECTION OUTPUT ;
    USE SIGNAL ;
    PORT
      LAYER M5 ;
        RECT  29.808 0 29.832 0.084 ;
    END
  END hq1[51]
  PIN hq1[52]
    DIRECTION OUTPUT ;
    USE SIGNAL ;
    PORT
      LAYER M5 ;
        RECT  29.904 0 29.928 0.084 ;
    END
  END hq1[52]
  PIN hq1[53]
    DIRECTION OUTPUT ;
    USE SIGNAL ;
    PORT
      LAYER M5 ;
        RECT  30 0 30.024 0.084 ;
    END
  END hq1[53]
  PIN hq1[54]
    DIRECTION OUTPUT ;
    USE SIGNAL ;
    PORT
      LAYER M5 ;
        RECT  30.096 0 30.12 0.084 ;
    END
  END hq1[54]
  PIN hq1[55]
    DIRECTION OUTPUT ;
    USE SIGNAL ;
    PORT
      LAYER M5 ;
        RECT  30.192 0 30.216 0.084 ;
    END
  END hq1[55]
  PIN hq1[56]
    DIRECTION OUTPUT ;
    USE SIGNAL ;
    PORT
      LAYER M5 ;
        RECT  30.288 0 30.312 0.084 ;
    END
  END hq1[56]
  PIN hq1[57]
    DIRECTION OUTPUT ;
    USE SIGNAL ;
    PORT
      LAYER M5 ;
        RECT  30.384 0 30.408 0.084 ;
    END
  END hq1[57]
  PIN hq1[58]
    DIRECTION OUTPUT ;
    USE SIGNAL ;
    PORT
      LAYER M5 ;
        RECT  30.48 0 30.504 0.084 ;
    END
  END hq1[58]
  PIN hq1[59]
    DIRECTION OUTPUT ;
    USE SIGNAL ;
    PORT
      LAYER M5 ;
        RECT  30.576 0 30.6 0.084 ;
    END
  END hq1[59]
  PIN hq1[5]
    DIRECTION OUTPUT ;
    USE SIGNAL ;
    PORT
      LAYER M5 ;
        RECT  92.208 0 92.232 0.084 ;
    END
  END hq1[5]
  PIN hq1[60]
    DIRECTION OUTPUT ;
    USE SIGNAL ;
    PORT
      LAYER M5 ;
        RECT  30.672 0 30.696 0.084 ;
    END
  END hq1[60]
  PIN hq1[61]
    DIRECTION OUTPUT ;
    USE SIGNAL ;
    PORT
      LAYER M5 ;
        RECT  30.768 0 30.792 0.084 ;
    END
  END hq1[61]
  PIN hq1[62]
    DIRECTION OUTPUT ;
    USE SIGNAL ;
    PORT
      LAYER M5 ;
        RECT  30.864 0 30.888 0.084 ;
    END
  END hq1[62]
  PIN hq1[63]
    DIRECTION OUTPUT ;
    USE SIGNAL ;
    PORT
      LAYER M5 ;
        RECT  30.96 0 30.984 0.084 ;
    END
  END hq1[63]
  PIN hq1[64]
    DIRECTION OUTPUT ;
    USE SIGNAL ;
    PORT
      LAYER M5 ;
        RECT  31.056 0 31.08 0.084 ;
    END
  END hq1[64]
  PIN hq1[65]
    DIRECTION OUTPUT ;
    USE SIGNAL ;
    PORT
      LAYER M5 ;
        RECT  31.152 0 31.176 0.084 ;
    END
  END hq1[65]
  PIN hq1[66]
    DIRECTION OUTPUT ;
    USE SIGNAL ;
    PORT
      LAYER M5 ;
        RECT  31.248 0 31.272 0.084 ;
    END
  END hq1[66]
  PIN hq1[67]
    DIRECTION OUTPUT ;
    USE SIGNAL ;
    PORT
      LAYER M5 ;
        RECT  31.344 0 31.368 0.084 ;
    END
  END hq1[67]
  PIN hq1[68]
    DIRECTION OUTPUT ;
    USE SIGNAL ;
    PORT
      LAYER M5 ;
        RECT  31.44 0 31.464 0.084 ;
    END
  END hq1[68]
  PIN hq1[69]
    DIRECTION OUTPUT ;
    USE SIGNAL ;
    PORT
      LAYER M5 ;
        RECT  31.536 0 31.56 0.084 ;
    END
  END hq1[69]
  PIN hq1[6]
    DIRECTION OUTPUT ;
    USE SIGNAL ;
    PORT
      LAYER M5 ;
        RECT  92.304 0 92.328 0.084 ;
    END
  END hq1[6]
  PIN hq1[70]
    DIRECTION OUTPUT ;
    USE SIGNAL ;
    PORT
      LAYER M5 ;
        RECT  31.632 0 31.656 0.084 ;
    END
  END hq1[70]
  PIN hq1[71]
    DIRECTION OUTPUT ;
    USE SIGNAL ;
    PORT
      LAYER M5 ;
        RECT  31.728 0 31.752 0.084 ;
    END
  END hq1[71]
  PIN hq1[72]
    DIRECTION OUTPUT ;
    USE SIGNAL ;
    PORT
      LAYER M5 ;
        RECT  31.824 0 31.848 0.084 ;
    END
  END hq1[72]
  PIN hq1[73]
    DIRECTION OUTPUT ;
    USE SIGNAL ;
    PORT
      LAYER M5 ;
        RECT  31.92 0 31.944 0.084 ;
    END
  END hq1[73]
  PIN hq1[74]
    DIRECTION OUTPUT ;
    USE SIGNAL ;
    PORT
      LAYER M5 ;
        RECT  32.016 0 32.04 0.084 ;
    END
  END hq1[74]
  PIN hq1[75]
    DIRECTION OUTPUT ;
    USE SIGNAL ;
    PORT
      LAYER M5 ;
        RECT  32.112 0 32.136 0.084 ;
    END
  END hq1[75]
  PIN hq1[76]
    DIRECTION OUTPUT ;
    USE SIGNAL ;
    PORT
      LAYER M5 ;
        RECT  64.464 0 64.488 0.084 ;
    END
  END hq1[76]
  PIN hq1[77]
    DIRECTION OUTPUT ;
    USE SIGNAL ;
    PORT
      LAYER M5 ;
        RECT  64.56 0 64.584 0.084 ;
    END
  END hq1[77]
  PIN hq1[78]
    DIRECTION OUTPUT ;
    USE SIGNAL ;
    PORT
      LAYER M5 ;
        RECT  64.656 0 64.68 0.084 ;
    END
  END hq1[78]
  PIN hq1[79]
    DIRECTION OUTPUT ;
    USE SIGNAL ;
    PORT
      LAYER M5 ;
        RECT  64.752 0 64.776 0.084 ;
    END
  END hq1[79]
  PIN hq1[7]
    DIRECTION OUTPUT ;
    USE SIGNAL ;
    PORT
      LAYER M5 ;
        RECT  92.4 0 92.424 0.084 ;
    END
  END hq1[7]
  PIN hq1[80]
    DIRECTION OUTPUT ;
    USE SIGNAL ;
    PORT
      LAYER M5 ;
        RECT  64.848 0 64.872 0.084 ;
    END
  END hq1[80]
  PIN hq1[81]
    DIRECTION OUTPUT ;
    USE SIGNAL ;
    PORT
      LAYER M5 ;
        RECT  64.944 0 64.968 0.084 ;
    END
  END hq1[81]
  PIN hq1[82]
    DIRECTION OUTPUT ;
    USE SIGNAL ;
    PORT
      LAYER M5 ;
        RECT  65.04 0 65.064 0.084 ;
    END
  END hq1[82]
  PIN hq1[83]
    DIRECTION OUTPUT ;
    USE SIGNAL ;
    PORT
      LAYER M5 ;
        RECT  65.136 0 65.16 0.084 ;
    END
  END hq1[83]
  PIN hq1[84]
    DIRECTION OUTPUT ;
    USE SIGNAL ;
    PORT
      LAYER M5 ;
        RECT  65.232 0 65.256 0.084 ;
    END
  END hq1[84]
  PIN hq1[85]
    DIRECTION OUTPUT ;
    USE SIGNAL ;
    PORT
      LAYER M5 ;
        RECT  65.328 0 65.352 0.084 ;
    END
  END hq1[85]
  PIN hq1[86]
    DIRECTION OUTPUT ;
    USE SIGNAL ;
    PORT
      LAYER M5 ;
        RECT  65.424 0 65.448 0.084 ;
    END
  END hq1[86]
  PIN hq1[87]
    DIRECTION OUTPUT ;
    USE SIGNAL ;
    PORT
      LAYER M5 ;
        RECT  65.52 0 65.544 0.084 ;
    END
  END hq1[87]
  PIN hq1[88]
    DIRECTION OUTPUT ;
    USE SIGNAL ;
    PORT
      LAYER M5 ;
        RECT  65.616 0 65.64 0.084 ;
    END
  END hq1[88]
  PIN hq1[89]
    DIRECTION OUTPUT ;
    USE SIGNAL ;
    PORT
      LAYER M5 ;
        RECT  65.712 0 65.736 0.084 ;
    END
  END hq1[89]
  PIN hq1[8]
    DIRECTION OUTPUT ;
    USE SIGNAL ;
    PORT
      LAYER M5 ;
        RECT  92.496 0 92.52 0.084 ;
    END
  END hq1[8]
  PIN hq1[90]
    DIRECTION OUTPUT ;
    USE SIGNAL ;
    PORT
      LAYER M5 ;
        RECT  65.808 0 65.832 0.084 ;
    END
  END hq1[90]
  PIN hq1[91]
    DIRECTION OUTPUT ;
    USE SIGNAL ;
    PORT
      LAYER M5 ;
        RECT  65.904 0 65.928 0.084 ;
    END
  END hq1[91]
  PIN hq1[92]
    DIRECTION OUTPUT ;
    USE SIGNAL ;
    PORT
      LAYER M5 ;
        RECT  66 0 66.024 0.084 ;
    END
  END hq1[92]
  PIN hq1[93]
    DIRECTION OUTPUT ;
    USE SIGNAL ;
    PORT
      LAYER M5 ;
        RECT  66.096 0 66.12 0.084 ;
    END
  END hq1[93]
  PIN hq1[94]
    DIRECTION OUTPUT ;
    USE SIGNAL ;
    PORT
      LAYER M5 ;
        RECT  66.192 0 66.216 0.084 ;
    END
  END hq1[94]
  PIN hq1[95]
    DIRECTION OUTPUT ;
    USE SIGNAL ;
    PORT
      LAYER M5 ;
        RECT  66.288 0 66.312 0.084 ;
    END
  END hq1[95]
  PIN hq1[96]
    DIRECTION OUTPUT ;
    USE SIGNAL ;
    PORT
      LAYER M5 ;
        RECT  66.384 0 66.408 0.084 ;
    END
  END hq1[96]
  PIN hq1[97]
    DIRECTION OUTPUT ;
    USE SIGNAL ;
    PORT
      LAYER M5 ;
        RECT  66.48 0 66.504 0.084 ;
    END
  END hq1[97]
  PIN hq1[98]
    DIRECTION OUTPUT ;
    USE SIGNAL ;
    PORT
      LAYER M5 ;
        RECT  66.576 0 66.6 0.084 ;
    END
  END hq1[98]
  PIN hq1[99]
    DIRECTION OUTPUT ;
    USE SIGNAL ;
    PORT
      LAYER M5 ;
        RECT  66.672 0 66.696 0.084 ;
    END
  END hq1[99]
  PIN hq1[9]
    DIRECTION OUTPUT ;
    USE SIGNAL ;
    PORT
      LAYER M5 ;
        RECT  92.592 0 92.616 0.084 ;
    END
  END hq1[9]
  PIN hw_sv[0]
    DIRECTION INPUT ;
    USE SIGNAL ;
    PORT
      LAYER M4 ;
        RECT  0 29.136 0.084 29.16 ;
    END
  END hw_sv[0]
  PIN hw_sv[1]
    DIRECTION INPUT ;
    USE SIGNAL ;
    PORT
      LAYER M4 ;
        RECT  0 29.232 0.084 29.256 ;
    END
  END hw_sv[1]
  PIN rst_n
    DIRECTION INPUT ;
    USE SIGNAL ;
    PORT
      LAYER M4 ;
        RECT  0 29.328 0.084 29.352 ;
    END
  END rst_n
  PIN VSS
    DIRECTION INOUT ;
    USE GROUND ;
    PORT
      LAYER M5 ;
        RECT  94.2 2.137 94.32 95.063 ;
        RECT  88.8 2.137 88.92 95.063 ;
        RECT  83.4 2.137 83.52 95.063 ;
        RECT  78 2.137 78.12 95.063 ;
        RECT  72.6 2.137 72.72 95.063 ;
        RECT  67.2 2.137 67.32 95.063 ;
        RECT  61.8 2.137 61.92 95.063 ;
        RECT  56.4 2.137 56.52 95.063 ;
        RECT  51 2.137 51.12 95.063 ;
        RECT  45.6 2.137 45.72 95.063 ;
        RECT  40.2 2.137 40.32 95.063 ;
        RECT  34.8 2.137 34.92 95.063 ;
        RECT  29.4 2.137 29.52 95.063 ;
        RECT  24 2.137 24.12 95.063 ;
        RECT  18.6 2.137 18.72 95.063 ;
        RECT  13.2 2.137 13.32 95.063 ;
        RECT  7.8 2.137 7.92 95.063 ;
        RECT  2.4 2.137 2.52 95.063 ;
    END
  END VSS
  PIN VDD
    DIRECTION INOUT ;
    USE POWER ;
    PORT
      LAYER M5 ;
        RECT  94.392 2.151 94.512 95.049 ;
        RECT  88.992 2.151 89.112 95.049 ;
        RECT  83.592 2.151 83.712 95.049 ;
        RECT  78.192 2.151 78.312 95.049 ;
        RECT  72.792 2.151 72.912 95.049 ;
        RECT  67.392 2.151 67.512 95.049 ;
        RECT  61.992 2.151 62.112 95.049 ;
        RECT  56.592 2.151 56.712 95.049 ;
        RECT  51.192 2.151 51.312 95.049 ;
        RECT  45.792 2.151 45.912 95.049 ;
        RECT  40.392 2.151 40.512 95.049 ;
        RECT  34.992 2.151 35.112 95.049 ;
        RECT  29.592 2.151 29.712 95.049 ;
        RECT  24.192 2.151 24.312 95.049 ;
        RECT  18.792 2.151 18.912 95.049 ;
        RECT  13.392 2.151 13.512 95.049 ;
        RECT  7.992 2.151 8.112 95.049 ;
        RECT  2.592 2.151 2.712 95.049 ;
    END
  END VDD
  OBS
    LAYER RVTN ;
     RECT  2.16 2.16 95.04 2.295 ;
     RECT  2.16 2.565 95.04 2.835 ;
     RECT  2.16 3.105 95.04 3.375 ;
     RECT  2.16 3.645 95.04 3.915 ;
     RECT  2.16 4.185 95.04 4.455 ;
     RECT  2.16 4.725 95.04 4.995 ;
     RECT  2.16 5.265 95.04 5.535 ;
     RECT  2.16 5.805 95.04 6.075 ;
     RECT  2.16 6.345 95.04 6.615 ;
     RECT  2.16 6.885 95.04 7.155 ;
     RECT  2.16 7.425 95.04 7.695 ;
     RECT  2.16 7.965 95.04 8.235 ;
     RECT  2.16 8.505 95.04 8.775 ;
     RECT  2.16 9.045 95.04 9.315 ;
     RECT  2.16 9.585 95.04 9.855 ;
     RECT  2.16 10.125 95.04 10.395 ;
     RECT  2.16 10.665 95.04 10.935 ;
     RECT  2.16 11.205 95.04 11.475 ;
     RECT  2.16 11.745 95.04 12.015 ;
     RECT  2.16 12.285 95.04 12.555 ;
     RECT  2.16 12.825 95.04 13.095 ;
     RECT  2.16 13.365 95.04 13.635 ;
     RECT  2.16 13.905 95.04 14.175 ;
     RECT  2.16 14.445 95.04 14.715 ;
     RECT  2.16 14.985 95.04 15.255 ;
     RECT  2.16 15.525 95.04 15.795 ;
     RECT  2.16 16.065 95.04 16.335 ;
     RECT  2.16 16.605 95.04 16.875 ;
     RECT  2.16 17.145 95.04 17.415 ;
     RECT  2.16 17.685 95.04 17.955 ;
     RECT  2.16 18.225 95.04 18.495 ;
     RECT  2.16 18.765 95.04 19.035 ;
     RECT  2.16 19.305 95.04 19.575 ;
     RECT  2.16 19.845 95.04 20.115 ;
     RECT  2.16 20.385 95.04 20.655 ;
     RECT  2.16 20.925 95.04 21.195 ;
     RECT  2.16 21.465 95.04 21.735 ;
     RECT  2.16 22.005 95.04 22.275 ;
     RECT  2.16 22.545 95.04 22.815 ;
     RECT  2.16 23.085 95.04 23.355 ;
     RECT  2.16 23.625 95.04 23.895 ;
     RECT  2.16 24.165 95.04 24.435 ;
     RECT  2.16 24.705 95.04 24.975 ;
     RECT  2.16 25.245 95.04 25.515 ;
     RECT  2.16 25.785 95.04 26.055 ;
     RECT  2.16 26.325 95.04 26.595 ;
     RECT  2.16 26.865 95.04 27.135 ;
     RECT  2.16 27.405 95.04 27.675 ;
     RECT  2.16 27.945 95.04 28.215 ;
     RECT  2.16 28.485 95.04 28.755 ;
     RECT  2.16 29.025 95.04 29.295 ;
     RECT  2.16 29.565 95.04 29.835 ;
     RECT  2.16 30.105 95.04 30.375 ;
     RECT  2.16 30.645 95.04 30.915 ;
     RECT  2.16 31.185 95.04 31.455 ;
     RECT  2.16 31.725 95.04 31.995 ;
     RECT  2.16 32.265 95.04 32.535 ;
     RECT  2.16 32.805 95.04 33.075 ;
     RECT  2.16 33.345 95.04 33.615 ;
     RECT  2.16 33.885 95.04 34.155 ;
     RECT  2.16 34.425 95.04 34.695 ;
     RECT  2.16 34.965 95.04 35.235 ;
     RECT  2.16 35.505 95.04 35.775 ;
     RECT  2.16 36.045 95.04 36.315 ;
     RECT  2.16 36.585 95.04 36.855 ;
     RECT  2.16 37.125 95.04 37.395 ;
     RECT  2.16 37.665 95.04 37.935 ;
     RECT  2.16 38.205 95.04 38.475 ;
     RECT  2.16 38.745 95.04 39.015 ;
     RECT  2.16 39.285 95.04 39.555 ;
     RECT  2.16 39.825 95.04 40.095 ;
     RECT  2.16 40.365 95.04 40.635 ;
     RECT  2.16 40.905 95.04 41.175 ;
     RECT  2.16 41.445 95.04 41.715 ;
     RECT  2.16 41.985 95.04 42.255 ;
     RECT  2.16 42.525 95.04 42.795 ;
     RECT  2.16 43.065 95.04 43.335 ;
     RECT  2.16 43.605 95.04 43.875 ;
     RECT  2.16 44.145 95.04 44.415 ;
     RECT  2.16 44.685 95.04 44.955 ;
     RECT  2.16 45.225 95.04 45.495 ;
     RECT  2.16 45.765 95.04 46.035 ;
     RECT  2.16 46.305 95.04 46.575 ;
     RECT  2.16 46.845 95.04 47.115 ;
     RECT  2.16 47.385 95.04 47.655 ;
     RECT  2.16 47.925 95.04 48.195 ;
     RECT  2.16 48.465 95.04 48.735 ;
     RECT  2.16 49.005 95.04 49.275 ;
     RECT  2.16 49.545 95.04 49.815 ;
     RECT  2.16 50.085 95.04 50.355 ;
     RECT  2.16 50.625 95.04 50.895 ;
     RECT  2.16 51.165 95.04 51.435 ;
     RECT  2.16 51.705 95.04 51.975 ;
     RECT  2.16 52.245 95.04 52.515 ;
     RECT  2.16 52.785 95.04 53.055 ;
     RECT  2.16 53.325 95.04 53.595 ;
     RECT  2.16 53.865 95.04 54.135 ;
     RECT  2.16 54.405 95.04 54.675 ;
     RECT  2.16 54.945 95.04 55.215 ;
     RECT  2.16 55.485 95.04 55.755 ;
     RECT  2.16 56.025 95.04 56.295 ;
     RECT  2.16 56.565 95.04 56.835 ;
     RECT  2.16 57.105 95.04 57.375 ;
     RECT  2.16 57.645 95.04 57.915 ;
     RECT  2.16 58.185 95.04 58.455 ;
     RECT  2.16 58.725 95.04 58.995 ;
     RECT  2.16 59.265 95.04 59.535 ;
     RECT  2.16 59.805 95.04 60.075 ;
     RECT  2.16 60.345 95.04 60.615 ;
     RECT  2.16 60.885 95.04 61.155 ;
     RECT  2.16 61.425 95.04 61.695 ;
     RECT  2.16 61.965 95.04 62.235 ;
     RECT  2.16 62.505 95.04 62.775 ;
     RECT  2.16 63.045 95.04 63.315 ;
     RECT  2.16 63.585 95.04 63.855 ;
     RECT  2.16 64.125 95.04 64.395 ;
     RECT  2.16 64.665 95.04 64.935 ;
     RECT  2.16 65.205 95.04 65.475 ;
     RECT  2.16 65.745 95.04 66.015 ;
     RECT  2.16 66.285 95.04 66.555 ;
     RECT  2.16 66.825 95.04 67.095 ;
     RECT  2.16 67.365 95.04 67.635 ;
     RECT  2.16 67.905 95.04 68.175 ;
     RECT  2.16 68.445 95.04 68.715 ;
     RECT  2.16 68.985 95.04 69.255 ;
     RECT  2.16 69.525 95.04 69.795 ;
     RECT  2.16 70.065 95.04 70.335 ;
     RECT  2.16 70.605 95.04 70.875 ;
     RECT  2.16 71.145 95.04 71.415 ;
     RECT  2.16 71.685 95.04 71.955 ;
     RECT  2.16 72.225 95.04 72.495 ;
     RECT  2.16 72.765 95.04 73.035 ;
     RECT  2.16 73.305 95.04 73.575 ;
     RECT  2.16 73.845 95.04 74.115 ;
     RECT  2.16 74.385 95.04 74.655 ;
     RECT  2.16 74.925 95.04 75.195 ;
     RECT  2.16 75.465 95.04 75.735 ;
     RECT  2.16 76.005 95.04 76.275 ;
     RECT  2.16 76.545 95.04 76.815 ;
     RECT  2.16 77.085 95.04 77.355 ;
     RECT  2.16 77.625 95.04 77.895 ;
     RECT  2.16 78.165 95.04 78.435 ;
     RECT  2.16 78.705 95.04 78.975 ;
     RECT  2.16 79.245 95.04 79.515 ;
     RECT  2.16 79.785 95.04 80.055 ;
     RECT  2.16 80.325 95.04 80.595 ;
     RECT  2.16 80.865 95.04 81.135 ;
     RECT  2.16 81.405 95.04 81.675 ;
     RECT  2.16 81.945 95.04 82.215 ;
     RECT  2.16 82.485 95.04 82.755 ;
     RECT  2.16 83.025 95.04 83.295 ;
     RECT  2.16 83.565 95.04 83.835 ;
     RECT  2.16 84.105 95.04 84.375 ;
     RECT  2.16 84.645 95.04 84.915 ;
     RECT  2.16 85.185 95.04 85.455 ;
     RECT  2.16 85.725 95.04 85.995 ;
     RECT  2.16 86.265 95.04 86.535 ;
     RECT  2.16 86.805 95.04 87.075 ;
     RECT  2.16 87.345 95.04 87.615 ;
     RECT  2.16 87.885 95.04 88.155 ;
     RECT  2.16 88.425 95.04 88.695 ;
     RECT  2.16 88.965 95.04 89.235 ;
     RECT  2.16 89.505 95.04 89.775 ;
     RECT  2.16 90.045 95.04 90.315 ;
     RECT  2.16 90.585 95.04 90.855 ;
     RECT  2.16 91.125 95.04 91.395 ;
     RECT  2.16 91.665 95.04 91.935 ;
     RECT  2.16 92.205 95.04 92.475 ;
     RECT  2.16 92.745 95.04 93.015 ;
     RECT  2.16 93.285 95.04 93.555 ;
     RECT  2.16 93.825 95.04 94.095 ;
     RECT  2.16 94.365 95.04 94.635 ;
     RECT  2.16 94.905 95.04 95.04 ;
    LAYER RVTP ;
     RECT  2.16 2.295 95.04 2.565 ;
     RECT  2.16 2.835 95.04 3.105 ;
     RECT  2.16 3.375 95.04 3.645 ;
     RECT  2.16 3.915 95.04 4.185 ;
     RECT  2.16 4.455 95.04 4.725 ;
     RECT  2.16 4.995 95.04 5.265 ;
     RECT  2.16 5.535 95.04 5.805 ;
     RECT  2.16 6.075 95.04 6.345 ;
     RECT  2.16 6.615 95.04 6.885 ;
     RECT  2.16 7.155 95.04 7.425 ;
     RECT  2.16 7.695 95.04 7.965 ;
     RECT  2.16 8.235 95.04 8.505 ;
     RECT  2.16 8.775 95.04 9.045 ;
     RECT  2.16 9.315 95.04 9.585 ;
     RECT  2.16 9.855 95.04 10.125 ;
     RECT  2.16 10.395 95.04 10.665 ;
     RECT  2.16 10.935 95.04 11.205 ;
     RECT  2.16 11.475 95.04 11.745 ;
     RECT  2.16 12.015 95.04 12.285 ;
     RECT  2.16 12.555 95.04 12.825 ;
     RECT  2.16 13.095 95.04 13.365 ;
     RECT  2.16 13.635 95.04 13.905 ;
     RECT  2.16 14.175 95.04 14.445 ;
     RECT  2.16 14.715 95.04 14.985 ;
     RECT  2.16 15.255 95.04 15.525 ;
     RECT  2.16 15.795 95.04 16.065 ;
     RECT  2.16 16.335 95.04 16.605 ;
     RECT  2.16 16.875 95.04 17.145 ;
     RECT  2.16 17.415 95.04 17.685 ;
     RECT  2.16 17.955 95.04 18.225 ;
     RECT  2.16 18.495 95.04 18.765 ;
     RECT  2.16 19.035 95.04 19.305 ;
     RECT  2.16 19.575 95.04 19.845 ;
     RECT  2.16 20.115 95.04 20.385 ;
     RECT  2.16 20.655 95.04 20.925 ;
     RECT  2.16 21.195 95.04 21.465 ;
     RECT  2.16 21.735 95.04 22.005 ;
     RECT  2.16 22.275 95.04 22.545 ;
     RECT  2.16 22.815 95.04 23.085 ;
     RECT  2.16 23.355 95.04 23.625 ;
     RECT  2.16 23.895 95.04 24.165 ;
     RECT  2.16 24.435 95.04 24.705 ;
     RECT  2.16 24.975 95.04 25.245 ;
     RECT  2.16 25.515 95.04 25.785 ;
     RECT  2.16 26.055 95.04 26.325 ;
     RECT  2.16 26.595 95.04 26.865 ;
     RECT  2.16 27.135 95.04 27.405 ;
     RECT  2.16 27.675 95.04 27.945 ;
     RECT  2.16 28.215 95.04 28.485 ;
     RECT  2.16 28.755 95.04 29.025 ;
     RECT  2.16 29.295 95.04 29.565 ;
     RECT  2.16 29.835 95.04 30.105 ;
     RECT  2.16 30.375 95.04 30.645 ;
     RECT  2.16 30.915 95.04 31.185 ;
     RECT  2.16 31.455 95.04 31.725 ;
     RECT  2.16 31.995 95.04 32.265 ;
     RECT  2.16 32.535 95.04 32.805 ;
     RECT  2.16 33.075 95.04 33.345 ;
     RECT  2.16 33.615 95.04 33.885 ;
     RECT  2.16 34.155 95.04 34.425 ;
     RECT  2.16 34.695 95.04 34.965 ;
     RECT  2.16 35.235 95.04 35.505 ;
     RECT  2.16 35.775 95.04 36.045 ;
     RECT  2.16 36.315 95.04 36.585 ;
     RECT  2.16 36.855 95.04 37.125 ;
     RECT  2.16 37.395 95.04 37.665 ;
     RECT  2.16 37.935 95.04 38.205 ;
     RECT  2.16 38.475 95.04 38.745 ;
     RECT  2.16 39.015 95.04 39.285 ;
     RECT  2.16 39.555 95.04 39.825 ;
     RECT  2.16 40.095 95.04 40.365 ;
     RECT  2.16 40.635 95.04 40.905 ;
     RECT  2.16 41.175 95.04 41.445 ;
     RECT  2.16 41.715 95.04 41.985 ;
     RECT  2.16 42.255 95.04 42.525 ;
     RECT  2.16 42.795 95.04 43.065 ;
     RECT  2.16 43.335 95.04 43.605 ;
     RECT  2.16 43.875 95.04 44.145 ;
     RECT  2.16 44.415 95.04 44.685 ;
     RECT  2.16 44.955 95.04 45.225 ;
     RECT  2.16 45.495 95.04 45.765 ;
     RECT  2.16 46.035 95.04 46.305 ;
     RECT  2.16 46.575 95.04 46.845 ;
     RECT  2.16 47.115 95.04 47.385 ;
     RECT  2.16 47.655 95.04 47.925 ;
     RECT  2.16 48.195 95.04 48.465 ;
     RECT  2.16 48.735 95.04 49.005 ;
     RECT  2.16 49.275 95.04 49.545 ;
     RECT  2.16 49.815 95.04 50.085 ;
     RECT  2.16 50.355 95.04 50.625 ;
     RECT  2.16 50.895 95.04 51.165 ;
     RECT  2.16 51.435 95.04 51.705 ;
     RECT  2.16 51.975 95.04 52.245 ;
     RECT  2.16 52.515 95.04 52.785 ;
     RECT  2.16 53.055 95.04 53.325 ;
     RECT  2.16 53.595 95.04 53.865 ;
     RECT  2.16 54.135 95.04 54.405 ;
     RECT  2.16 54.675 95.04 54.945 ;
     RECT  2.16 55.215 95.04 55.485 ;
     RECT  2.16 55.755 95.04 56.025 ;
     RECT  2.16 56.295 95.04 56.565 ;
     RECT  2.16 56.835 95.04 57.105 ;
     RECT  2.16 57.375 95.04 57.645 ;
     RECT  2.16 57.915 95.04 58.185 ;
     RECT  2.16 58.455 95.04 58.725 ;
     RECT  2.16 58.995 95.04 59.265 ;
     RECT  2.16 59.535 95.04 59.805 ;
     RECT  2.16 60.075 95.04 60.345 ;
     RECT  2.16 60.615 95.04 60.885 ;
     RECT  2.16 61.155 95.04 61.425 ;
     RECT  2.16 61.695 95.04 61.965 ;
     RECT  2.16 62.235 95.04 62.505 ;
     RECT  2.16 62.775 95.04 63.045 ;
     RECT  2.16 63.315 95.04 63.585 ;
     RECT  2.16 63.855 95.04 64.125 ;
     RECT  2.16 64.395 95.04 64.665 ;
     RECT  2.16 64.935 95.04 65.205 ;
     RECT  2.16 65.475 95.04 65.745 ;
     RECT  2.16 66.015 95.04 66.285 ;
     RECT  2.16 66.555 95.04 66.825 ;
     RECT  2.16 67.095 95.04 67.365 ;
     RECT  2.16 67.635 95.04 67.905 ;
     RECT  2.16 68.175 95.04 68.445 ;
     RECT  2.16 68.715 95.04 68.985 ;
     RECT  2.16 69.255 95.04 69.525 ;
     RECT  2.16 69.795 95.04 70.065 ;
     RECT  2.16 70.335 95.04 70.605 ;
     RECT  2.16 70.875 95.04 71.145 ;
     RECT  2.16 71.415 95.04 71.685 ;
     RECT  2.16 71.955 95.04 72.225 ;
     RECT  2.16 72.495 95.04 72.765 ;
     RECT  2.16 73.035 95.04 73.305 ;
     RECT  2.16 73.575 95.04 73.845 ;
     RECT  2.16 74.115 95.04 74.385 ;
     RECT  2.16 74.655 95.04 74.925 ;
     RECT  2.16 75.195 95.04 75.465 ;
     RECT  2.16 75.735 95.04 76.005 ;
     RECT  2.16 76.275 95.04 76.545 ;
     RECT  2.16 76.815 95.04 77.085 ;
     RECT  2.16 77.355 95.04 77.625 ;
     RECT  2.16 77.895 95.04 78.165 ;
     RECT  2.16 78.435 95.04 78.705 ;
     RECT  2.16 78.975 95.04 79.245 ;
     RECT  2.16 79.515 95.04 79.785 ;
     RECT  2.16 80.055 95.04 80.325 ;
     RECT  2.16 80.595 95.04 80.865 ;
     RECT  2.16 81.135 95.04 81.405 ;
     RECT  2.16 81.675 95.04 81.945 ;
     RECT  2.16 82.215 95.04 82.485 ;
     RECT  2.16 82.755 95.04 83.025 ;
     RECT  2.16 83.295 95.04 83.565 ;
     RECT  2.16 83.835 95.04 84.105 ;
     RECT  2.16 84.375 95.04 84.645 ;
     RECT  2.16 84.915 95.04 85.185 ;
     RECT  2.16 85.455 95.04 85.725 ;
     RECT  2.16 85.995 95.04 86.265 ;
     RECT  2.16 86.535 95.04 86.805 ;
     RECT  2.16 87.075 95.04 87.345 ;
     RECT  2.16 87.615 95.04 87.885 ;
     RECT  2.16 88.155 95.04 88.425 ;
     RECT  2.16 88.695 95.04 88.965 ;
     RECT  2.16 89.235 95.04 89.505 ;
     RECT  2.16 89.775 95.04 90.045 ;
     RECT  2.16 90.315 95.04 90.585 ;
     RECT  2.16 90.855 95.04 91.125 ;
     RECT  2.16 91.395 95.04 91.665 ;
     RECT  2.16 91.935 95.04 92.205 ;
     RECT  2.16 92.475 95.04 92.745 ;
     RECT  2.16 93.015 95.04 93.285 ;
     RECT  2.16 93.555 95.04 93.825 ;
     RECT  2.16 94.095 95.04 94.365 ;
     RECT  2.16 94.635 95.04 94.905 ;
    LAYER M1 ;
     RECT  2.16 2.151 95.04 95.049 ;
    LAYER M2 ;
     RECT  2.16 2.151 6.979 95.049 ;
     RECT  6.979 2.151 8.635 95.094 ;
     RECT  8.635 2.151 13.675 95.166 ;
     RECT  13.675 2.106 14.063 95.166 ;
     RECT  14.063 2.151 15.187 95.166 ;
     RECT  15.187 2.07 17.483 95.166 ;
     RECT  17.483 2.07 19.003 95.049 ;
     RECT  19.003 1.881 21.919 95.049 ;
     RECT  21.919 1.836 22.855 95.049 ;
     RECT  22.855 1.728 23.719 95.049 ;
     RECT  23.719 1.728 23.791 95.13 ;
     RECT  23.791 1.728 26.303 95.166 ;
     RECT  23.899 0.846 27.923 0.864 ;
     RECT  26.303 1.836 28.435 95.166 ;
     RECT  28.435 1.836 30.803 95.238 ;
     RECT  30.803 1.836 32.711 95.166 ;
     RECT  32.711 2.151 32.863 95.166 ;
     RECT  32.863 2.151 34.123 95.472 ;
     RECT  33.727 0.846 36.211 0.864 ;
     RECT  36.211 0.846 36.311 1.17 ;
     RECT  34.123 2.106 38.335 95.472 ;
     RECT  36.311 0.846 38.795 0.864 ;
     RECT  38.335 2.106 39.271 96.048 ;
     RECT  39.271 2.034 41.035 96.048 ;
     RECT  41.035 1.962 49.027 96.048 ;
     RECT  49.027 1.881 52.079 96.048 ;
     RECT  52.519 1.152 52.619 1.17 ;
     RECT  52.079 1.926 53.023 96.048 ;
     RECT  53.023 1.881 55.867 96.048 ;
     RECT  55.867 1.152 56.579 96.048 ;
     RECT  56.579 1.926 57.047 96.048 ;
     RECT  57.047 1.926 58.135 95.472 ;
     RECT  56.579 1.152 58.487 1.17 ;
     RECT  52.519 0.036 60.475 0.054 ;
     RECT  59.179 0.846 61.231 0.864 ;
     RECT  58.135 1.926 61.231 96.048 ;
     RECT  60.475 0.036 63.023 0.09 ;
     RECT  63.023 0.072 64.327 0.09 ;
     RECT  61.231 0.846 64.327 96.048 ;
     RECT  64.327 0.072 64.571 96.048 ;
     RECT  64.571 0.531 65.039 96.048 ;
     RECT  65.039 0.846 70.115 96.048 ;
     RECT  70.115 1.422 72.275 96.048 ;
     RECT  72.275 1.926 72.563 96.048 ;
     RECT  72.563 1.962 73.571 96.048 ;
     RECT  73.571 1.962 75.587 95.166 ;
     RECT  75.587 2.07 76.279 95.166 ;
     RECT  76.279 2.07 76.595 95.238 ;
     RECT  76.595 2.07 76.963 95.166 ;
     RECT  73.571 96.03 76.991 96.048 ;
     RECT  76.963 1.962 77.063 95.166 ;
     RECT  77.063 1.962 78.655 95.13 ;
     RECT  78.655 1.962 79.879 95.166 ;
     RECT  79.879 1.926 80.591 95.166 ;
     RECT  80.591 1.926 80.959 95.13 ;
     RECT  80.959 1.881 81.599 95.13 ;
     RECT  81.599 1.926 82.363 95.13 ;
     RECT  82.363 1.881 85.387 95.13 ;
     RECT  85.387 1.836 86.279 95.13 ;
     RECT  86.279 1.836 87.151 95.094 ;
     RECT  87.151 1.692 87.439 95.094 ;
     RECT  87.439 1.692 87.719 95.166 ;
     RECT  87.719 1.692 89.275 95.049 ;
     RECT  89.275 1.692 90.095 95.094 ;
     RECT  90.095 1.836 90.131 95.094 ;
     RECT  90.131 2.034 90.455 95.094 ;
     RECT  90.455 2.034 90.923 95.049 ;
     RECT  90.923 2.151 95.04 95.049 ;
    LAYER M3 ;
     RECT  63 0.031 63.018 0.043 ;
     RECT  27.216 0.043 27.234 0.091 ;
     RECT  49.464 0.043 49.482 0.091 ;
     RECT  60.48 0.067 60.498 0.091 ;
     RECT  62.676 0.043 63.018 0.091 ;
     RECT  64.548 0.067 64.566 0.091 ;
     RECT  70.092 0.043 70.11 0.091 ;
     RECT  73.476 0.043 73.494 0.091 ;
     RECT  88.308 0.043 88.326 0.091 ;
     RECT  26.352 0.091 27.99 0.139 ;
     RECT  32.076 0.091 33.858 0.139 ;
     RECT  42.84 0.091 42.858 0.139 ;
     RECT  56.808 0.043 56.826 0.139 ;
     RECT  58.716 0.091 58.734 0.139 ;
     RECT  60.228 0.091 60.606 0.139 ;
     RECT  68.904 0.091 71.226 0.139 ;
     RECT  72.324 0.091 73.89 0.139 ;
     RECT  84.384 0.091 84.582 0.139 ;
     RECT  55.872 0.091 55.89 0.187 ;
     RECT  64.548 0.091 65.142 0.187 ;
     RECT  65.88 0.091 66.978 0.187 ;
     RECT  82.728 0.139 83.394 0.187 ;
     RECT  84.384 0.139 85.086 0.187 ;
     RECT  18.828 0.091 18.846 0.221 ;
     RECT  56.808 0.139 56.934 0.221 ;
     RECT  58.032 0.139 58.734 0.221 ;
     RECT  65.88 0.187 67.05 0.221 ;
     RECT  23.364 0.091 23.562 0.235 ;
     RECT  62.676 0.091 63.342 0.235 ;
     RECT  64.404 0.187 65.142 0.235 ;
     RECT  77.436 0.139 77.454 0.235 ;
     RECT  42.768 0.139 42.858 0.269 ;
     RECT  42.84 0.269 42.858 0.317 ;
     RECT  60.228 0.139 61.614 0.331 ;
     RECT  62.676 0.235 63.594 0.331 ;
     RECT  35.64 0.043 35.658 0.379 ;
     RECT  36.612 0.091 36.63 0.379 ;
     RECT  60.228 0.331 63.594 0.427 ;
     RECT  64.404 0.235 65.466 0.427 ;
     RECT  24.516 0.091 25.146 0.475 ;
     RECT  26.352 0.139 28.062 0.475 ;
     RECT  66.42 0.221 67.05 0.475 ;
     RECT  68.076 0.091 68.094 0.475 ;
     RECT  68.904 0.139 73.89 0.475 ;
     RECT  49.464 0.091 50.31 0.523 ;
     RECT  82.656 0.187 85.086 0.523 ;
     RECT  85.824 0.139 86.058 0.523 ;
     RECT  87.192 0.091 88.506 0.523 ;
     RECT  89.28 0.091 91.746 0.523 ;
     RECT  29.052 0.091 29.214 0.571 ;
     RECT  30.276 0.091 30.798 0.571 ;
     RECT  32.004 0.139 33.858 0.571 ;
     RECT  46.728 0.091 46.746 0.571 ;
     RECT  47.772 0.091 47.79 0.571 ;
     RECT  49.464 0.523 50.49 0.571 ;
     RECT  51.336 0.091 51.354 0.571 ;
     RECT  54.756 0.523 54.774 0.571 ;
     RECT  55.62 0.187 55.89 0.571 ;
     RECT  66.42 0.475 73.89 0.571 ;
     RECT  82.656 0.523 86.058 0.571 ;
     RECT  87.192 0.523 91.746 0.571 ;
     RECT  54.756 0.571 55.89 0.619 ;
     RECT  59.184 0.475 59.418 0.619 ;
     RECT  60.228 0.427 65.466 0.619 ;
     RECT  35.64 0.379 36.63 0.811 ;
     RECT  22.428 0.235 23.562 0.841 ;
     RECT  24.516 0.475 28.062 0.841 ;
     RECT  38.412 0.139 38.43 0.841 ;
     RECT  16.056 0.091 16.074 0.859 ;
     RECT  80.244 0.139 80.262 0.859 ;
     RECT  82.656 0.571 91.746 0.859 ;
     RECT  92.484 0.091 94.662 0.859 ;
     RECT  38.412 0.841 38.79 0.907 ;
     RECT  80.244 0.859 80.802 0.907 ;
     RECT  17.028 0.139 17.046 0.955 ;
     RECT  17.928 0.907 17.946 0.955 ;
     RECT  15.768 0.859 16.074 1.003 ;
     RECT  17.028 0.955 17.946 1.003 ;
     RECT  41.004 0.955 41.022 1.003 ;
     RECT  41.796 0.187 41.814 1.003 ;
     RECT  19.944 0.763 19.962 1.051 ;
     RECT  46.656 0.571 46.746 1.051 ;
     RECT  47.772 0.571 51.354 1.051 ;
     RECT  22.428 0.841 28.062 1.099 ;
     RECT  29.052 0.571 30.942 1.099 ;
     RECT  31.932 0.571 33.858 1.099 ;
     RECT  59.184 0.619 65.466 1.099 ;
     RECT  66.42 0.571 74.358 1.099 ;
     RECT  75.384 0.187 75.402 1.099 ;
     RECT  52.524 0.031 52.542 1.147 ;
     RECT  58.032 0.221 58.158 1.147 ;
     RECT  59.04 1.099 65.466 1.147 ;
     RECT  13.896 0.043 13.914 1.387 ;
     RECT  15.012 0.811 15.03 1.387 ;
     RECT  22.32 1.099 30.942 1.387 ;
     RECT  35.064 0.811 36.63 1.435 ;
     RECT  58.032 1.147 65.466 1.435 ;
     RECT  15.768 1.003 17.946 1.579 ;
     RECT  41.004 1.003 41.814 1.579 ;
     RECT  19.512 1.051 19.962 1.627 ;
     RECT  22.32 1.387 31.086 1.723 ;
     RECT  31.896 1.099 33.858 1.723 ;
     RECT  45.54 0.139 45.558 1.723 ;
     RECT  46.656 1.051 51.354 1.723 ;
     RECT  56.916 0.221 56.934 1.723 ;
     RECT  58.032 1.435 65.538 1.723 ;
     RECT  66.42 1.099 75.402 1.723 ;
     RECT  76.248 0.187 76.266 1.723 ;
     RECT  77.436 0.235 77.67 1.723 ;
     RECT  52.524 1.147 52.614 1.771 ;
     RECT  54.756 0.619 55.926 1.771 ;
     RECT  56.916 1.723 75.402 1.771 ;
     RECT  76.248 1.723 77.67 1.771 ;
     RECT  54.612 1.771 55.926 1.819 ;
     RECT  56.916 1.771 77.67 1.819 ;
     RECT  21.456 0.283 21.474 1.831 ;
     RECT  22.32 1.723 33.894 1.831 ;
     RECT  15.768 1.579 18.45 1.876 ;
     RECT  19.188 1.627 19.962 1.876 ;
     RECT  45.54 1.723 51.354 1.876 ;
     RECT  52.524 1.771 53.082 1.876 ;
     RECT  80.244 0.907 81.234 1.876 ;
     RECT  82.656 0.859 94.662 1.876 ;
     RECT  80.244 1.876 81.594 1.921 ;
     RECT  54.612 1.819 77.67 1.957 ;
     RECT  45.54 1.876 53.082 1.993 ;
     RECT  15.768 1.876 19.962 2.029 ;
     RECT  38.412 0.907 39.222 2.029 ;
     RECT  44.136 0.091 44.154 2.029 ;
     RECT  45.036 1.993 53.082 2.029 ;
     RECT  44.136 2.029 53.082 2.059 ;
     RECT  13.896 1.387 15.03 2.065 ;
     RECT  15.768 2.029 20.106 2.065 ;
     RECT  79.884 1.921 81.594 2.065 ;
     RECT  82.368 1.876 94.662 2.065 ;
     RECT  13.896 2.065 20.106 2.101 ;
     RECT  21.456 1.831 33.894 2.101 ;
     RECT  34.74 1.435 36.63 2.101 ;
     RECT  37.656 0.859 37.674 2.101 ;
     RECT  44.136 2.059 53.154 2.101 ;
     RECT  13.68 2.101 20.322 2.143 ;
     RECT  40.356 1.579 41.814 2.143 ;
     RECT  54.252 1.957 77.67 2.143 ;
     RECT  40.215 2.143 41.814 2.191 ;
     RECT  42.84 2.101 53.154 2.191 ;
     RECT  13.215 2.143 20.322 2.227 ;
     RECT  54.252 2.143 78.105 2.227 ;
     RECT  12.672 2.227 20.538 2.251 ;
     RECT  40.215 2.191 53.154 2.251 ;
     RECT  54.144 2.227 78.105 2.251 ;
     RECT  79.884 2.065 94.662 2.251 ;
     RECT  9.864 2.227 9.882 2.263 ;
     RECT  21.456 2.101 37.674 2.299 ;
     RECT  38.412 2.029 39.294 2.299 ;
     RECT  79.776 2.251 94.662 2.299 ;
     RECT  12.24 2.251 20.538 2.335 ;
     RECT  21.384 2.299 39.294 2.335 ;
     RECT  40.215 2.251 78.786 2.335 ;
     RECT  9.864 2.263 10.134 2.371 ;
     RECT  12.096 2.335 20.538 2.371 ;
     RECT  21.276 2.335 78.786 2.371 ;
     RECT  2.415 2.143 2.505 2.413 ;
     RECT  7.815 2.143 7.905 2.413 ;
     RECT  12.096 2.371 78.786 2.497 ;
     RECT  79.776 2.299 94.734 2.569 ;
     RECT  11.808 2.497 78.786 2.641 ;
     RECT  79.56 2.569 94.734 2.759 ;
     RECT  11.592 2.641 78.786 2.767 ;
     RECT  79.56 2.759 94.626 2.767 ;
     RECT  9.864 2.371 10.386 2.803 ;
     RECT  9.864 2.803 10.602 2.875 ;
     RECT  11.412 2.767 94.626 2.875 ;
     RECT  8.928 2.803 8.946 2.911 ;
     RECT  7.815 2.413 8.097 3.145 ;
     RECT  8.928 2.911 9.126 3.145 ;
     RECT  7.815 3.145 9.126 3.181 ;
     RECT  9.864 2.875 94.626 3.181 ;
     RECT  7.815 3.181 94.626 3.605 ;
     RECT  6.84 3.379 6.858 3.883 ;
     RECT  7.815 3.605 37.026 3.883 ;
     RECT  5.976 3.577 5.994 4.117 ;
     RECT  6.84 3.883 37.026 4.117 ;
     RECT  5.976 4.117 37.026 4.387 ;
     RECT  37.8 3.605 94.626 4.387 ;
     RECT  5.724 4.387 94.626 4.459 ;
     RECT  4.14 4.621 4.158 4.693 ;
     RECT  4.14 4.693 4.41 4.765 ;
     RECT  4.14 4.765 4.734 4.801 ;
     RECT  5.544 4.459 94.626 4.801 ;
     RECT  4.032 4.801 94.626 5.035 ;
     RECT  2.415 2.413 2.697 5.305 ;
     RECT  3.708 5.035 94.626 5.305 ;
     RECT  2.415 5.305 94.626 5.459 ;
     RECT  2.415 5.459 94.59 6.961 ;
     RECT  2.34 6.961 94.59 7.195 ;
     RECT  2.304 7.195 94.59 15.061 ;
     RECT  2.304 15.061 94.914 15.179 ;
     RECT  2.304 15.179 94.59 15.557 ;
     RECT  2.34 15.557 94.59 19.111 ;
     RECT  2.34 19.111 94.626 20.047 ;
     RECT  2.34 20.047 94.806 20.141 ;
     RECT  2.34 20.141 94.554 20.921 ;
     RECT  2.415 20.921 94.554 21.271 ;
     RECT  2.415 21.271 94.914 21.569 ;
     RECT  2.415 21.569 94.554 23.701 ;
     RECT  2.415 23.701 94.626 25.321 ;
     RECT  2.415 25.321 94.914 25.709 ;
     RECT  2.415 25.709 94.626 26.107 ;
     RECT  2.34 26.107 94.626 26.875 ;
     RECT  2.34 26.875 94.914 27.059 ;
     RECT  2.34 27.059 94.626 27.149 ;
     RECT  2.376 27.149 94.626 27.239 ;
     RECT  2.415 27.239 94.626 27.979 ;
     RECT  2.415 27.979 94.914 28.139 ;
     RECT  2.415 28.139 94.497 28.723 ;
     RECT  2.34 28.723 94.497 29.101 ;
     RECT  2.34 29.101 94.842 29.131 ;
     RECT  2.304 29.131 94.842 29.219 ;
     RECT  2.304 29.219 94.497 31.351 ;
     RECT  2.304 31.351 94.842 31.421 ;
     RECT  2.304 31.421 94.497 31.955 ;
     RECT  2.415 31.955 94.497 32.881 ;
     RECT  2.376 32.881 94.497 33.053 ;
     RECT  2.415 33.053 94.497 34.735 ;
     RECT  2.34 34.735 94.497 35.231 ;
     RECT  2.415 35.231 94.497 36.481 ;
     RECT  2.376 36.481 94.497 36.557 ;
     RECT  5.94 36.557 94.497 36.617 ;
     RECT  2.415 36.557 5.166 37.471 ;
     RECT  6.192 36.617 94.497 37.561 ;
     RECT  2.415 37.471 5.346 37.579 ;
     RECT  6.192 37.561 94.554 37.579 ;
     RECT  2.415 37.579 94.554 38.479 ;
     RECT  2.376 38.479 94.554 38.515 ;
     RECT  2.34 38.515 94.554 38.543 ;
     RECT  2.34 38.543 94.497 39.091 ;
     RECT  2.304 39.091 94.497 40.405 ;
     RECT  2.268 40.405 94.497 40.531 ;
     RECT  2.268 40.531 94.518 40.981 ;
     RECT  2.268 40.981 94.914 41.369 ;
     RECT  2.304 41.369 94.914 41.549 ;
     RECT  2.304 41.549 94.497 42.601 ;
     RECT  2.304 42.601 94.914 42.719 ;
     RECT  2.304 42.719 94.59 43.259 ;
     RECT  2.304 43.259 94.497 44.383 ;
     RECT  2.232 44.383 94.497 45.797 ;
     RECT  2.304 45.797 94.497 46.111 ;
     RECT  2.304 46.111 94.914 46.409 ;
     RECT  2.304 46.409 94.497 47.281 ;
     RECT  2.304 47.281 94.554 47.723 ;
     RECT  2.304 47.723 94.497 48.541 ;
     RECT  2.232 48.541 94.497 49.199 ;
     RECT  48.528 49.199 94.497 49.235 ;
     RECT  2.232 49.199 47.79 49.421 ;
     RECT  50.076 49.235 94.497 49.621 ;
     RECT  50.076 49.621 94.914 49.739 ;
     RECT  2.232 49.421 47.718 50.395 ;
     RECT  48.528 49.235 49.338 50.395 ;
     RECT  2.232 50.395 49.338 50.431 ;
     RECT  50.076 49.739 94.497 50.431 ;
     RECT  2.232 50.431 94.497 50.899 ;
     RECT  2.232 50.899 94.554 50.935 ;
     RECT  2.232 50.935 94.914 51.089 ;
     RECT  2.232 51.089 94.554 51.359 ;
     RECT  2.304 51.359 94.554 52.889 ;
     RECT  2.304 52.889 94.497 53.941 ;
     RECT  2.304 53.941 94.842 54.509 ;
     RECT  2.304 54.509 94.662 55.283 ;
     RECT  2.304 55.283 94.497 56.641 ;
     RECT  2.304 56.641 94.914 56.759 ;
     RECT  2.304 56.759 94.497 57.847 ;
     RECT  2.304 57.847 94.554 57.875 ;
     RECT  2.415 57.875 94.554 57.955 ;
     RECT  2.415 57.955 94.914 58.109 ;
     RECT  2.415 58.109 94.554 58.217 ;
     RECT  3.744 58.217 94.554 58.487 ;
     RECT  3.744 58.487 94.497 58.829 ;
     RECT  2.415 58.217 2.826 58.999 ;
     RECT  3.744 58.829 8.946 58.999 ;
     RECT  2.415 58.999 8.946 59.071 ;
     RECT  2.376 59.071 8.946 59.531 ;
     RECT  2.415 59.531 8.946 59.575 ;
     RECT  9.684 58.829 94.497 59.575 ;
     RECT  2.415 59.575 94.497 59.809 ;
     RECT  2.415 59.809 94.914 60.077 ;
     RECT  6.588 60.077 94.914 60.269 ;
     RECT  2.415 60.077 5.562 60.379 ;
     RECT  6.588 60.269 94.842 60.539 ;
     RECT  2.34 60.379 5.562 60.961 ;
     RECT  6.588 60.539 94.497 60.961 ;
     RECT  2.34 60.961 94.497 62.509 ;
     RECT  2.34 62.509 94.59 62.699 ;
     RECT  4.968 62.699 94.59 62.735 ;
     RECT  5.04 62.735 94.59 63.085 ;
     RECT  2.34 62.699 4.194 63.661 ;
     RECT  5.04 63.085 94.662 63.661 ;
     RECT  2.34 63.661 94.914 63.887 ;
     RECT  56.34 63.887 94.914 64.049 ;
     RECT  2.34 63.887 55.566 64.057 ;
     RECT  2.304 64.057 55.566 64.831 ;
     RECT  56.34 64.049 94.497 64.831 ;
     RECT  2.304 64.831 94.497 64.939 ;
     RECT  2.304 64.939 94.842 65.309 ;
     RECT  2.304 65.309 5.238 65.435 ;
     RECT  6.084 65.309 94.842 65.669 ;
     RECT  6.084 65.669 94.497 66.139 ;
     RECT  2.304 65.435 5.13 66.217 ;
     RECT  6.012 66.139 94.497 66.217 ;
     RECT  2.304 66.217 94.497 66.757 ;
     RECT  2.268 66.757 94.497 67.055 ;
     RECT  2.304 67.055 94.497 68.477 ;
     RECT  2.34 68.477 94.497 68.765 ;
     RECT  2.412 68.765 94.497 68.945 ;
     RECT  2.415 68.945 94.497 69.961 ;
     RECT  2.415 69.961 94.626 70.069 ;
     RECT  2.34 70.069 94.626 70.097 ;
     RECT  2.34 70.097 94.497 70.685 ;
     RECT  2.415 70.685 94.497 70.915 ;
     RECT  2.415 70.915 94.914 71.069 ;
     RECT  2.415 71.069 94.497 73.381 ;
     RECT  2.415 73.381 94.914 73.499 ;
     RECT  2.415 73.499 94.497 74.461 ;
     RECT  2.415 74.461 94.914 74.579 ;
     RECT  2.415 74.579 94.497 77.701 ;
     RECT  2.415 77.701 94.554 78.061 ;
     RECT  2.415 78.061 94.626 78.475 ;
     RECT  2.34 78.475 94.626 78.935 ;
     RECT  2.34 78.935 94.497 79.861 ;
     RECT  2.34 79.861 94.914 80.789 ;
     RECT  2.34 80.789 94.497 82.795 ;
     RECT  2.304 82.795 94.497 84.685 ;
     RECT  2.268 84.685 94.497 84.749 ;
     RECT  2.304 84.749 94.497 86.525 ;
     RECT  2.34 86.525 94.497 87.925 ;
     RECT  2.304 87.925 94.497 87.965 ;
     RECT  2.376 87.965 94.497 88.115 ;
     RECT  2.415 88.115 94.497 88.771 ;
     RECT  2.415 88.771 94.842 88.889 ;
     RECT  2.415 88.889 94.497 89.735 ;
     RECT  3.456 89.735 94.497 90.355 ;
     RECT  3.456 90.355 94.59 90.509 ;
     RECT  2.415 89.735 2.697 90.517 ;
     RECT  3.456 90.509 92.682 90.517 ;
     RECT  2.415 90.517 92.682 90.815 ;
     RECT  3.996 90.815 92.682 90.851 ;
     RECT  4.14 90.851 92.682 90.923 ;
     RECT  93.42 90.509 94.497 90.959 ;
     RECT  93.564 90.959 94.497 91.085 ;
     RECT  93.672 91.085 94.497 91.121 ;
     RECT  2.415 90.815 2.754 91.579 ;
     RECT  4.284 90.923 92.682 91.705 ;
     RECT  4.248 91.705 92.682 91.939 ;
     RECT  4.248 91.939 92.934 92.011 ;
     RECT  4.248 92.011 92.97 92.129 ;
     RECT  4.248 92.129 92.934 92.285 ;
     RECT  4.248 92.285 75.366 92.333 ;
     RECT  76.104 92.285 92.934 92.399 ;
     RECT  76.104 92.399 92.862 92.669 ;
     RECT  76.104 92.669 92.682 92.741 ;
     RECT  4.284 92.333 75.366 92.813 ;
     RECT  2.232 91.579 2.754 92.911 ;
     RECT  42.768 92.813 75.366 92.975 ;
     RECT  60.012 92.975 75.366 93.011 ;
     RECT  60.084 93.011 75.366 93.019 ;
     RECT  76.104 92.741 92.43 93.019 ;
     RECT  60.084 93.019 92.43 93.047 ;
     RECT  4.284 92.813 41.994 93.389 ;
     RECT  60.192 93.047 92.43 93.479 ;
     RECT  32.184 93.389 41.994 93.901 ;
     RECT  42.768 92.975 59.13 93.901 ;
     RECT  60.192 93.479 92.358 93.901 ;
     RECT  32.184 93.901 92.358 94.019 ;
     RECT  32.184 94.019 92.214 94.199 ;
     RECT  4.284 93.389 31.446 94.289 ;
     RECT  6.012 94.289 31.446 94.369 ;
     RECT  32.184 94.199 91.242 94.369 ;
     RECT  6.012 94.369 91.242 94.445 ;
     RECT  92.196 94.199 92.214 94.469 ;
     RECT  2.232 92.911 2.826 94.531 ;
     RECT  6.012 94.445 91.062 94.559 ;
     RECT  59.688 94.559 91.062 94.589 ;
     RECT  6.012 94.559 41.814 94.595 ;
     RECT  42.84 94.559 58.914 94.595 ;
     RECT  6.012 94.595 33.174 94.631 ;
     RECT  2.232 94.531 3.258 94.675 ;
     RECT  65.916 94.589 91.062 94.685 ;
     RECT  33.948 94.595 41.814 94.703 ;
     RECT  4.284 94.289 5.274 94.739 ;
     RECT  65.916 94.685 89.622 94.739 ;
     RECT  6.12 94.631 18.897 94.787 ;
     RECT  33.948 94.703 35.097 94.787 ;
     RECT  94.215 91.121 94.497 94.787 ;
     RECT  2.232 94.675 3.33 94.829 ;
     RECT  6.12 94.787 18.774 94.829 ;
     RECT  19.62 94.631 22.446 94.829 ;
     RECT  35.82 94.703 41.814 94.829 ;
     RECT  44.532 94.595 58.914 94.829 ;
     RECT  65.916 94.739 89.586 94.829 ;
     RECT  90.432 94.685 91.062 94.829 ;
     RECT  6.12 94.829 16.506 94.865 ;
     RECT  35.82 94.829 39.33 94.865 ;
     RECT  67.104 94.829 84.33 94.865 ;
     RECT  9.504 94.865 16.506 94.877 ;
     RECT  55.584 94.829 58.914 94.877 ;
     RECT  65.916 94.829 66.366 94.877 ;
     RECT  67.104 94.865 77.202 94.877 ;
     RECT  4.608 94.739 5.274 94.901 ;
     RECT  19.656 94.829 22.446 94.901 ;
     RECT  35.892 94.865 39.33 94.901 ;
     RECT  40.14 94.829 41.814 94.901 ;
     RECT  59.688 94.589 65.142 94.901 ;
     RECT  67.104 94.877 68.922 94.901 ;
     RECT  70.128 94.877 77.202 94.901 ;
     RECT  85.068 94.829 89.514 94.901 ;
     RECT  9.504 94.877 9.954 94.937 ;
     RECT  17.46 94.829 18.774 94.937 ;
     RECT  36.36 94.901 39.33 94.937 ;
     RECT  42.84 94.595 43.65 94.937 ;
     RECT  55.584 94.877 58.878 94.937 ;
     RECT  66.132 94.877 66.366 94.937 ;
     RECT  70.128 94.901 71.406 94.937 ;
     RECT  72.216 94.901 77.202 94.937 ;
     RECT  6.12 94.865 8.658 94.973 ;
     RECT  9.756 94.937 9.954 94.973 ;
     RECT  19.908 94.901 22.446 94.973 ;
     RECT  56.415 94.937 58.878 94.973 ;
     RECT  63.072 94.901 65.142 94.973 ;
     RECT  66.132 94.937 66.294 94.973 ;
     RECT  70.308 94.937 71.406 94.973 ;
     RECT  72.216 94.937 75.51 94.973 ;
     RECT  76.284 94.937 77.202 94.973 ;
     RECT  78.015 94.865 84.33 94.973 ;
     RECT  88.815 94.901 89.514 94.973 ;
     RECT  10.872 94.877 16.506 95.009 ;
     RECT  23.184 94.631 33.174 95.009 ;
     RECT  42.984 94.937 43.65 95.009 ;
     RECT  59.688 94.901 62.082 95.009 ;
     RECT  63.072 94.973 63.666 95.009 ;
     RECT  67.104 94.901 68.454 95.009 ;
     RECT  72.252 94.973 75.51 95.009 ;
     RECT  78.015 94.973 78.75 95.009 ;
     RECT  79.524 94.973 84.33 95.009 ;
     RECT  2.232 94.829 3.114 95.021 ;
     RECT  4.608 94.901 4.914 95.021 ;
     RECT  6.12 94.973 7.002 95.021 ;
     RECT  40.215 94.901 41.814 95.021 ;
     RECT  45.036 94.829 54.738 95.021 ;
     RECT  61.704 95.009 62.01 95.021 ;
     RECT  67.104 95.009 67.41 95.021 ;
     RECT  7.815 94.973 7.905 95.057 ;
     RECT  13.176 95.009 16.506 95.057 ;
     RECT  17.46 94.937 18.705 95.057 ;
     RECT  33.948 94.787 34.905 95.057 ;
     RECT  40.215 95.021 40.95 95.057 ;
     RECT  56.415 94.973 58.158 95.057 ;
     RECT  61.815 95.021 61.905 95.057 ;
     RECT  67.215 95.021 67.305 95.057 ;
     RECT  78.015 95.009 78.678 95.057 ;
     RECT  79.812 95.009 83.505 95.057 ;
     RECT  88.815 94.973 89.298 95.057 ;
     RECT  94.215 94.787 94.305 95.057 ;
     RECT  23.724 95.009 33.174 95.069 ;
     RECT  45.072 95.021 54.738 95.069 ;
     RECT  6.696 95.021 7.002 95.099 ;
     RECT  9.864 94.973 9.954 95.099 ;
     RECT  13.176 95.057 13.194 95.099 ;
     RECT  40.824 95.057 40.95 95.099 ;
     RECT  89.28 95.057 89.298 95.099 ;
     RECT  90.432 94.829 90.45 95.099 ;
     RECT  13.932 95.057 16.506 95.135 ;
     RECT  23.724 95.069 32.886 95.135 ;
     RECT  79.812 95.057 83.214 95.135 ;
     RECT  85.572 94.901 86.67 95.135 ;
     RECT  4.896 95.021 4.914 95.165 ;
     RECT  13.932 95.135 14.094 95.165 ;
     RECT  23.796 95.135 32.886 95.165 ;
     RECT  33.948 95.057 34.686 95.165 ;
     RECT  45.072 95.069 53.082 95.165 ;
     RECT  54.108 95.069 54.738 95.165 ;
     RECT  70.308 94.973 71.226 95.165 ;
     RECT  8.64 94.973 8.658 95.171 ;
     RECT  10.872 95.009 12.222 95.171 ;
     RECT  13.932 95.165 14.022 95.171 ;
     RECT  14.832 95.135 16.506 95.171 ;
     RECT  17.46 95.057 18.198 95.171 ;
     RECT  23.796 95.165 23.814 95.171 ;
     RECT  24.732 95.165 32.886 95.171 ;
     RECT  40.86 95.099 40.95 95.171 ;
     RECT  45.072 95.165 45.27 95.171 ;
     RECT  46.152 95.165 49.662 95.171 ;
     RECT  56.844 95.057 58.158 95.171 ;
     RECT  78.372 95.057 78.678 95.171 ;
     RECT  80.568 95.135 83.214 95.171 ;
     RECT  87.444 94.901 87.714 95.171 ;
     RECT  33.948 95.165 33.966 95.207 ;
     RECT  36.36 94.937 37.422 95.207 ;
     RECT  2.232 95.021 2.826 95.213 ;
     RECT  24.732 95.171 31.302 95.213 ;
     RECT  45.072 95.171 45.09 95.213 ;
     RECT  47.268 95.171 49.662 95.213 ;
     RECT  50.724 95.165 53.082 95.213 ;
     RECT  24.732 95.213 29.178 95.243 ;
     RECT  30.06 95.213 31.302 95.243 ;
     RECT  54.324 95.165 54.738 95.243 ;
     RECT  72.252 95.009 74.934 95.243 ;
     RECT  50.724 95.213 52.758 95.261 ;
     RECT  50.832 95.261 52.758 95.279 ;
     RECT  2.808 95.213 2.826 95.309 ;
     RECT  72.432 95.243 74.934 95.324 ;
     RECT  17.748 95.171 18.198 95.453 ;
     RECT  38.34 94.937 39.33 95.453 ;
     RECT  51.876 95.279 52.758 95.453 ;
     RECT  86.652 95.135 86.67 95.453 ;
     RECT  32.184 95.171 32.886 95.477 ;
     RECT  14.832 95.171 15.966 95.501 ;
     RECT  81.18 95.171 83.214 95.501 ;
     RECT  11.088 95.171 12.222 95.549 ;
     RECT  37.296 95.207 37.422 95.549 ;
     RECT  68.148 95.009 68.454 95.549 ;
     RECT  71.172 95.165 71.19 95.597 ;
     RECT  64.512 94.973 65.142 95.645 ;
     RECT  52.344 95.453 52.758 95.741 ;
     RECT  29.16 95.243 29.178 95.789 ;
     RECT  76.284 94.973 77.094 95.851 ;
     RECT  37.404 95.549 37.422 96.029 ;
     RECT  70.308 95.165 70.434 96.029 ;
     RECT  38.34 95.453 38.358 96.053 ;
     RECT  57.78 95.171 58.158 96.053 ;
     RECT  11.232 95.549 12.222 96.077 ;
     RECT  68.148 95.549 68.166 96.077 ;
     RECT  63.072 95.009 63.09 96.125 ;
     RECT  65.124 95.645 65.142 96.173 ;
     RECT  57.024 96.025 57.042 96.235 ;
     RECT  57.78 96.053 57.87 96.235 ;
     RECT  41.796 95.021 41.814 96.317 ;
     RECT  20.304 94.973 22.446 96.365 ;
     RECT  39.312 95.453 39.33 96.365 ;
     RECT  54.576 95.243 54.738 96.365 ;
     RECT  57.024 96.235 57.87 96.365 ;
     RECT  79.812 95.135 79.83 96.365 ;
     RECT  75.888 95.851 77.094 96.413 ;
     RECT  73.008 95.324 74.934 96.509 ;
     RECT  77.004 96.413 77.094 96.509 ;
     RECT  52.344 95.741 52.362 96.523 ;
     RECT  32.184 95.477 32.67 96.653 ;
     RECT  74.088 96.509 74.934 96.653 ;
     RECT  52.344 96.523 53.046 96.667 ;
     RECT  32.292 96.653 32.67 96.701 ;
     RECT  31.212 95.243 31.302 96.715 ;
     RECT  70.416 96.029 70.434 96.715 ;
     RECT  81.18 95.501 82.53 96.715 ;
     RECT  47.268 95.213 49.518 96.749 ;
     RECT  52.344 96.667 53.442 96.749 ;
     RECT  59.688 95.009 60.39 96.749 ;
     RECT  72.972 96.619 72.99 96.749 ;
     RECT  32.292 96.701 32.634 96.797 ;
     RECT  57.276 96.365 57.87 96.797 ;
     RECT  6.696 95.099 6.894 96.811 ;
     RECT  59.868 96.749 60.39 96.811 ;
     RECT  57.276 96.797 57.798 96.845 ;
     RECT  81.18 96.715 83.034 96.845 ;
     RECT  31.176 96.715 31.302 96.859 ;
     RECT  40.968 95.755 40.986 96.859 ;
     RECT  52.344 96.749 52.506 96.859 ;
     RECT  53.424 96.749 53.442 96.859 ;
     RECT  54.576 96.365 54.702 96.859 ;
     RECT  11.628 96.077 12.222 96.893 ;
     RECT  24.732 95.243 27.846 96.893 ;
     RECT  6.48 96.811 6.894 96.907 ;
     RECT  18.18 95.453 18.198 96.907 ;
     RECT  59.868 96.811 60.642 96.907 ;
     RECT  78.372 95.171 78.39 96.907 ;
     RECT  81 96.859 81.018 96.907 ;
     RECT  31.176 96.859 31.374 96.941 ;
     RECT  42.984 95.009 43.002 96.941 ;
     RECT  47.268 96.749 49.23 96.941 ;
     RECT  57.276 96.845 57.294 96.941 ;
     RECT  59.868 96.907 61.326 96.941 ;
     RECT  81.864 96.845 83.034 96.941 ;
     RECT  3.888 96.619 3.906 96.955 ;
     RECT  21.384 96.365 22.446 96.955 ;
     RECT  23.292 96.811 23.31 96.955 ;
     RECT  27 96.893 27.846 96.955 ;
     RECT  44.244 96.907 44.262 96.955 ;
     RECT  55.584 94.937 55.602 96.955 ;
     RECT  80.568 96.907 81.018 96.955 ;
     RECT  5.616 95.755 5.634 96.989 ;
     RECT  15.12 95.501 15.966 96.989 ;
     RECT  51.984 96.859 52.506 96.989 ;
     RECT  53.424 96.859 54.702 96.989 ;
     RECT  75.888 96.413 76.122 96.989 ;
     RECT  70.416 96.715 70.722 97.003 ;
     RECT  75.888 96.989 75.906 97.003 ;
     RECT  6.372 96.907 6.894 97.037 ;
     RECT  18.18 96.907 18.846 97.037 ;
     RECT  27 96.955 29.106 97.037 ;
     RECT  40.788 96.859 40.986 97.037 ;
     RECT  75.348 97.003 75.906 97.037 ;
     RECT  82.332 96.941 82.998 97.037 ;
     RECT  84.06 95.755 84.078 97.037 ;
     RECT  27.108 97.037 29.106 97.051 ;
     RECT  30.06 95.243 30.078 97.051 ;
     RECT  40.788 97.037 40.806 97.051 ;
     RECT  51.516 97.003 51.534 97.051 ;
     RECT  78.372 96.907 78.498 97.051 ;
     RECT  79.344 96.955 79.362 97.051 ;
     RECT  3.888 96.955 4.59 97.085 ;
     RECT  11.628 96.893 11.646 97.085 ;
     RECT  21.384 96.955 23.31 97.085 ;
     RECT  24.732 96.893 26.118 97.085 ;
     RECT  27.108 97.051 30.078 97.085 ;
     RECT  31.212 96.941 31.374 97.085 ;
     RECT  32.292 96.797 32.31 97.085 ;
     RECT  40.212 97.051 40.806 97.085 ;
     RECT  43.092 96.955 45.306 97.085 ;
     RECT  46.152 95.171 46.17 97.085 ;
     RECT  47.268 96.941 47.286 97.085 ;
     RECT  49.212 96.941 49.23 97.085 ;
     RECT  52.488 96.989 52.506 97.085 ;
     RECT  54.684 96.989 54.702 97.085 ;
     RECT  55.584 96.955 56.142 97.085 ;
     RECT  59.868 96.941 60.318 97.085 ;
     RECT  61.308 96.941 61.326 97.085 ;
     RECT  62.064 96.955 62.082 97.085 ;
     RECT  70.416 97.003 70.83 97.085 ;
     RECT  74.088 96.653 74.61 97.085 ;
     RECT  78.372 97.051 79.362 97.085 ;
     RECT  80.46 96.955 81.018 97.085 ;
     RECT  82.476 97.037 82.998 97.085 ;
     RECT  6.372 97.037 6.39 97.133 ;
     RECT  15.12 96.989 15.138 97.133 ;
     RECT  15.948 96.989 15.966 97.133 ;
     RECT  22.104 97.085 22.122 97.133 ;
     RECT  23.292 97.085 23.31 97.133 ;
     RECT  27.252 97.085 27.27 97.133 ;
     RECT  50.94 97.051 51.534 97.133 ;
     RECT  59.868 97.085 60.282 97.133 ;
     RECT  70.812 97.085 70.83 97.133 ;
     RECT  75.348 97.037 75.366 97.133 ;
     RECT  85.572 95.135 85.914 97.133 ;
     RECT  25.2 97.085 25.218 97.181 ;
     RECT  26.1 97.085 26.118 97.181 ;
     RECT  29.7 97.085 29.718 97.181 ;
     RECT  40.212 97.085 40.23 97.181 ;
     RECT  48.384 96.941 48.402 97.181 ;
     RECT  50.94 97.133 50.958 97.181 ;
     RECT  60.264 97.133 60.282 97.181 ;
     RECT  77.004 96.509 77.022 97.181 ;
     RECT  78.66 97.085 78.678 97.181 ;
     RECT  85.572 97.133 85.59 97.181 ;
    LAYER M4 ;
     RECT  0.06 29.136 0.133 29.352 ;
     RECT  0.06 55.056 0.133 55.944 ;
     RECT  0.06 57.168 0.133 57.48 ;
     RECT  0.133 29.136 0.181 29.688 ;
     RECT  0.133 55.056 0.181 55.992 ;
     RECT  0.133 56.976 0.181 57.624 ;
     RECT  0.181 50.736 0.515 50.76 ;
     RECT  0.181 55.056 0.517 57.624 ;
     RECT  1.381 94.032 1.573 94.056 ;
     RECT  1.285 84.864 1.669 84.888 ;
     RECT  1.573 94.032 1.861 94.632 ;
     RECT  1.669 84.72 2.053 84.888 ;
     RECT  1.477 87.936 2.149 87.96 ;
     RECT  1.861 94.032 2.221 95.16 ;
     RECT  0.181 29.136 2.293 29.88 ;
     RECT  2.053 84.144 2.293 84.888 ;
     RECT  2.149 87.024 2.293 87.96 ;
     RECT  2.221 91.584 2.293 91.608 ;
     RECT  2.221 94.032 2.293 95.208 ;
     RECT  2.293 27.36 2.329 27.384 ;
     RECT  2.293 43.824 2.329 43.848 ;
     RECT  2.293 59.76 2.329 59.784 ;
     RECT  2.293 96.912 2.341 96.936 ;
     RECT  2.293 11.424 2.365 11.448 ;
     RECT  2.329 59.76 2.365 60.408 ;
     RECT  0.181 49.536 2.401 49.56 ;
     RECT  2.365 9.888 2.408 9.912 ;
     RECT  2.365 10.896 2.408 11.448 ;
     RECT  2.293 14.688 2.408 14.712 ;
     RECT  2.293 16.848 2.408 16.872 ;
     RECT  2.329 26.112 2.408 26.136 ;
     RECT  2.329 27.12 2.408 27.384 ;
     RECT  2.293 28.896 2.408 29.88 ;
     RECT  2.401 31.776 2.408 31.8 ;
     RECT  2.365 33.024 2.408 33.048 ;
     RECT  2.365 36.528 2.408 36.552 ;
     RECT  2.293 39.648 2.408 40.584 ;
     RECT  2.329 43.584 2.408 43.848 ;
     RECT  2.293 46.128 2.408 46.152 ;
     RECT  2.401 48.768 2.408 49.56 ;
     RECT  0.133 53.664 2.408 53.688 ;
     RECT  0.517 55.056 2.408 57.72 ;
     RECT  2.365 59.184 2.408 60.408 ;
     RECT  2.329 62.976 2.408 63 ;
     RECT  2.365 64.368 2.408 64.392 ;
     RECT  2.329 68.736 2.408 68.76 ;
     RECT  2.329 70.656 2.408 70.68 ;
     RECT  2.293 72 2.408 72.024 ;
     RECT  2.293 83.808 2.408 84.888 ;
     RECT  2.293 85.92 2.408 87.96 ;
     RECT  1.765 89.184 2.408 89.208 ;
     RECT  2.293 91.584 2.408 91.704 ;
     RECT  2.293 93.504 2.408 95.208 ;
     RECT  2.408 2.148 2.512 95.208 ;
     RECT  2.341 96.816 2.533 96.936 ;
     RECT  2.512 2.418 2.677 95.208 ;
     RECT  2.677 2.418 2.704 95.304 ;
     RECT  2.704 8.976 2.819 10.056 ;
     RECT  2.704 11.184 2.819 12.168 ;
     RECT  2.704 13.632 2.819 21.72 ;
     RECT  2.704 39.168 2.819 43.416 ;
     RECT  2.704 44.448 2.819 49.56 ;
     RECT  2.704 51.696 2.819 56.04 ;
     RECT  2.704 93.408 2.837 95.304 ;
     RECT  2.837 93.408 2.867 95.016 ;
     RECT  2.704 22.752 2.873 34.344 ;
     RECT  2.819 41.184 2.909 43.416 ;
     RECT  2.704 59.184 2.915 64.392 ;
     RECT  2.909 42.576 2.945 43.416 ;
     RECT  2.819 45.12 2.945 49.56 ;
     RECT  2.819 13.632 2.963 18.84 ;
     RECT  2.704 65.376 2.963 66.264 ;
     RECT  2.819 11.376 2.981 12.168 ;
     RECT  2.945 42.576 2.981 43.08 ;
     RECT  2.819 51.696 2.981 53.592 ;
     RECT  2.704 82.848 2.981 87.576 ;
     RECT  2.533 96.72 3.013 96.936 ;
     RECT  2.873 32.976 3.017 34.344 ;
     RECT  2.945 45.12 3.017 48.504 ;
     RECT  2.963 14.736 3.059 18.84 ;
     RECT  2.963 13.632 3.125 13.656 ;
     RECT  3.017 47.616 3.155 48.504 ;
     RECT  2.867 93.792 3.155 95.016 ;
     RECT  3.017 45.12 3.161 46.152 ;
     RECT  3.059 17.088 3.203 18.84 ;
     RECT  2.704 6.576 3.341 7.944 ;
     RECT  2.981 82.848 3.395 85.608 ;
     RECT  3.059 14.736 3.413 15.768 ;
     RECT  2.704 73.488 3.413 74.808 ;
     RECT  2.873 22.752 3.449 31.944 ;
     RECT  2.915 59.184 3.449 64.152 ;
     RECT  2.704 75.888 3.449 80.04 ;
     RECT  2.819 39.168 3.557 40.104 ;
     RECT  3.449 59.184 3.685 62.808 ;
     RECT  3.449 75.888 3.697 75.912 ;
     RECT  3.341 6.576 3.701 7.704 ;
     RECT  3.449 63.888 3.701 64.152 ;
     RECT  3.697 13.536 3.733 13.56 ;
     RECT  2.704 67.872 3.733 68.76 ;
     RECT  3.161 45.12 3.737 45.624 ;
     RECT  3.697 75.792 3.737 75.912 ;
     RECT  3.395 82.848 3.773 85.464 ;
     RECT  3.733 13.296 3.779 13.56 ;
     RECT  2.819 20.304 3.781 21.72 ;
     RECT  3.449 22.752 3.781 23.928 ;
     RECT  3.697 5.04 3.805 5.064 ;
     RECT  3.701 6.576 3.805 6.6 ;
     RECT  2.819 54.72 3.805 56.04 ;
     RECT  2.704 57.12 3.805 57.144 ;
     RECT  3.013 96.72 3.829 97.032 ;
     RECT  3.805 54.72 3.841 57.144 ;
     RECT  3.685 58.512 3.841 62.808 ;
     RECT  2.963 65.568 3.841 66.264 ;
     RECT  3.733 67.872 3.841 68.952 ;
     RECT  3.449 25.056 3.845 31.944 ;
     RECT  3.155 47.616 3.875 47.64 ;
     RECT  2.981 11.424 3.877 12.168 ;
     RECT  3.829 96.624 3.877 97.032 ;
     RECT  3.413 15.408 3.881 15.768 ;
     RECT  2.704 36.528 3.913 36.6 ;
     RECT  3.557 39.216 3.913 40.104 ;
     RECT  2.909 41.184 3.913 41.544 ;
     RECT  2.981 43.056 3.913 43.08 ;
     RECT  3.877 96.624 3.917 97.08 ;
     RECT  2.704 81.648 3.949 81.672 ;
     RECT  3.773 82.848 3.949 85.416 ;
     RECT  3.881 15.696 3.953 15.768 ;
     RECT  3.841 65.568 3.973 68.952 ;
     RECT  2.704 70.08 3.973 71.496 ;
     RECT  3.737 45.12 3.985 45.144 ;
     RECT  2.981 86.736 3.985 87.576 ;
     RECT  3.913 35.712 4.021 36.6 ;
     RECT  3.985 45.024 4.025 45.144 ;
     RECT  3.841 54.72 4.025 62.808 ;
     RECT  3.973 65.568 4.025 71.496 ;
     RECT  3.953 15.744 4.057 15.768 ;
     RECT  3.913 43.056 4.057 43.32 ;
     RECT  3.701 63.888 4.061 63.912 ;
     RECT  3.985 86.64 4.067 87.576 ;
     RECT  2.945 49.536 4.093 49.56 ;
     RECT  4.067 86.736 4.093 87.576 ;
     RECT  4.057 15.744 4.129 15.816 ;
     RECT  3.203 17.088 4.129 18.408 ;
     RECT  3.017 33.12 4.129 34.344 ;
     RECT  4.025 45.024 4.129 45.096 ;
     RECT  2.981 51.696 4.201 53.4 ;
     RECT  3.949 81.648 4.201 85.416 ;
     RECT  4.093 86.736 4.201 87.864 ;
     RECT  2.704 88.896 4.201 89.208 ;
     RECT  3.845 25.152 4.237 31.944 ;
     RECT  4.129 32.976 4.237 34.344 ;
     RECT  3.701 7.68 4.277 7.704 ;
     RECT  4.129 15.744 4.277 18.408 ;
     RECT  3.913 39.216 4.309 41.544 ;
     RECT  4.025 62.304 4.313 62.808 ;
     RECT  4.025 66.624 4.313 71.496 ;
     RECT  3.877 11.424 4.345 12.552 ;
     RECT  4.313 68.736 4.345 71.496 ;
     RECT  4.277 15.744 4.355 16.968 ;
     RECT  4.025 65.568 4.357 65.592 ;
     RECT  4.309 39.216 4.381 41.976 ;
     RECT  4.057 43.056 4.381 43.56 ;
     RECT  3.413 73.92 4.405 74.808 ;
     RECT  4.277 18.384 4.417 18.408 ;
     RECT  4.357 64.896 4.421 65.592 ;
     RECT  3.449 76.896 4.451 80.04 ;
     RECT  4.093 49.44 4.453 49.56 ;
     RECT  4.313 62.736 4.453 62.808 ;
     RECT  4.345 68.736 4.453 72.36 ;
     RECT  4.405 73.632 4.453 74.808 ;
     RECT  2.704 90.576 4.489 90.6 ;
     RECT  3.781 20.304 4.499 23.928 ;
     RECT  4.499 20.304 4.501 21.336 ;
     RECT  4.381 39.216 4.501 43.56 ;
     RECT  4.129 44.928 4.501 45.096 ;
     RECT  2.819 9.696 4.525 10.056 ;
     RECT  4.345 11.04 4.525 12.552 ;
     RECT  4.201 51.072 4.525 53.4 ;
     RECT  4.025 54.72 4.525 61.224 ;
     RECT  4.453 68.736 4.561 74.808 ;
     RECT  3.737 75.792 4.561 75.816 ;
     RECT  4.489 90.24 4.561 90.6 ;
     RECT  4.525 51.072 4.595 61.224 ;
     RECT  3.155 93.792 4.597 94.968 ;
     RECT  4.417 47.856 4.633 47.88 ;
     RECT  4.453 49.056 4.633 49.56 ;
     RECT  4.201 81.504 4.637 85.416 ;
     RECT  4.633 47.856 4.669 49.56 ;
     RECT  4.561 68.736 4.709 75.816 ;
     RECT  4.595 51.072 4.739 59.304 ;
     RECT  4.237 25.152 4.813 34.344 ;
     RECT  4.021 35.328 4.813 36.6 ;
     RECT  4.669 47.856 4.813 49.8 ;
     RECT  4.739 51.072 4.813 58.824 ;
     RECT  4.597 93.792 4.837 95.016 ;
     RECT  3.779 13.536 4.849 13.56 ;
     RECT  4.201 86.736 4.853 89.208 ;
     RECT  4.451 76.992 4.925 80.04 ;
     RECT  4.925 79.44 4.957 80.04 ;
     RECT  4.813 25.152 4.993 36.6 ;
     RECT  4.561 37.584 4.993 37.608 ;
     RECT  4.501 39.216 4.993 45.096 ;
     RECT  4.837 93.792 5.029 95.16 ;
     RECT  4.489 46.224 5.065 46.248 ;
     RECT  4.813 47.856 5.065 58.824 ;
     RECT  4.561 90.24 5.065 91.128 ;
     RECT  4.237 92.304 5.065 92.328 ;
     RECT  4.993 25.152 5.077 37.608 ;
     RECT  4.993 39.216 5.077 45.192 ;
     RECT  4.595 60.912 5.077 61.224 ;
     RECT  4.853 88.848 5.101 89.208 ;
     RECT  5.065 90.24 5.101 92.328 ;
     RECT  5.077 25.152 5.123 45.192 ;
     RECT  4.453 62.736 5.123 63.72 ;
     RECT  4.499 22.56 5.137 23.928 ;
     RECT  5.123 25.152 5.137 36.6 ;
     RECT  4.637 81.648 5.137 85.416 ;
     RECT  4.417 18.384 5.177 18.984 ;
     RECT  5.123 37.584 5.213 45.192 ;
     RECT  4.525 9.696 5.219 12.552 ;
     RECT  5.029 93.792 5.221 95.448 ;
     RECT  3.917 96.816 5.221 97.08 ;
     RECT  5.173 7.968 5.249 8.184 ;
     RECT  5.101 88.848 5.281 92.328 ;
     RECT  5.221 93.792 5.281 97.08 ;
     RECT  5.281 88.848 5.321 97.08 ;
     RECT  5.137 22.56 5.357 36.6 ;
     RECT  4.849 13.536 5.413 14.52 ;
     RECT  4.355 15.744 5.413 16.584 ;
     RECT  5.321 88.848 5.429 91.704 ;
     RECT  5.413 13.536 5.461 16.584 ;
     RECT  5.461 13.536 5.465 17.688 ;
     RECT  4.501 19.968 5.533 21.336 ;
     RECT  5.357 22.56 5.533 25.992 ;
     RECT  5.077 60.912 5.533 61.656 ;
     RECT  5.123 62.736 5.533 63 ;
     RECT  5.065 46.224 5.537 58.824 ;
     RECT  4.709 69.456 5.573 75.816 ;
     RECT  5.213 37.584 5.609 42.696 ;
     RECT  5.609 38.16 5.699 42.696 ;
     RECT  4.957 79.44 5.713 80.424 ;
     RECT  5.137 81.648 5.713 85.512 ;
     RECT  4.853 86.736 5.713 87.816 ;
     RECT  5.465 17.136 5.717 17.688 ;
     RECT  5.281 9.504 5.749 9.528 ;
     RECT  5.213 43.92 5.749 45.192 ;
     RECT  5.537 46.224 5.749 52.248 ;
     RECT  5.573 74.88 5.749 75.816 ;
     RECT  4.925 76.992 5.749 78.36 ;
     RECT  5.717 17.28 5.789 17.688 ;
     RECT  5.713 79.44 5.795 87.816 ;
     RECT  5.573 69.456 5.843 73.896 ;
     RECT  5.177 18.672 5.857 18.984 ;
     RECT  5.533 19.968 5.857 25.992 ;
     RECT  4.313 66.624 5.857 66.936 ;
     RECT  5.677 64.128 5.893 64.152 ;
     RECT  4.421 65.52 5.893 65.592 ;
     RECT  5.857 18.672 5.897 25.992 ;
     RECT  5.699 38.256 5.897 42.696 ;
     RECT  5.749 74.88 5.965 78.36 ;
     RECT  5.795 79.44 5.965 85.512 ;
     RECT  5.893 64.128 5.989 65.592 ;
     RECT  5.857 66.624 5.989 67.32 ;
     RECT  3.805 5.04 6.001 6.6 ;
     RECT  5.897 41.376 6.005 42.696 ;
     RECT  5.989 64.128 6.041 67.32 ;
     RECT  5.965 74.88 6.083 85.512 ;
     RECT  5.533 60.912 6.109 63 ;
     RECT  6.041 64.128 6.109 65.592 ;
     RECT  6.001 4.464 6.113 6.936 ;
     RECT  5.897 20.88 6.113 25.992 ;
     RECT  6.041 66.624 6.181 67.32 ;
     RECT  5.795 86.736 6.185 87.816 ;
     RECT  5.219 10.608 6.277 12.552 ;
     RECT  5.465 13.536 6.277 15.816 ;
     RECT  5.789 17.424 6.277 17.688 ;
     RECT  5.897 18.672 6.277 19.368 ;
     RECT  5.537 53.28 6.277 58.824 ;
     RECT  6.109 60.048 6.277 65.592 ;
     RECT  5.749 9.312 6.289 9.528 ;
     RECT  6.277 10.512 6.289 15.816 ;
     RECT  5.843 69.456 6.289 73.752 ;
     RECT  5.429 90.576 6.289 91.704 ;
     RECT  5.321 92.88 6.289 97.08 ;
     RECT  6.289 9.312 6.325 15.816 ;
     RECT  6.113 5.472 6.329 6.936 ;
     RECT  6.325 9.072 6.329 15.816 ;
     RECT  6.289 90.576 6.361 97.08 ;
     RECT  5.249 7.968 6.365 7.992 ;
     RECT  6.329 14.208 6.433 15.816 ;
     RECT  6.277 53.28 6.437 65.592 ;
     RECT  6.437 53.28 6.505 63.48 ;
     RECT  5.357 27.6 6.541 36.6 ;
     RECT  6.325 68.352 6.541 68.376 ;
     RECT  6.289 69.408 6.541 73.752 ;
     RECT  6.541 27.216 6.545 36.6 ;
     RECT  6.113 4.464 6.577 4.488 ;
     RECT  6.181 66.624 6.577 67.368 ;
     RECT  6.541 68.352 6.577 73.752 ;
     RECT  6.577 66.624 6.617 73.752 ;
     RECT  6.545 34.752 6.649 36.6 ;
     RECT  6.185 86.736 6.757 87.432 ;
     RECT  6.545 27.216 6.797 33.576 ;
     RECT  6.433 14.208 6.901 15.864 ;
     RECT  6.277 17.424 6.901 19.368 ;
     RECT  5.897 38.256 6.901 39.912 ;
     RECT  6.005 41.376 6.901 42.504 ;
     RECT  5.749 43.92 6.901 52.248 ;
     RECT  6.505 53.232 6.901 63.48 ;
     RECT  6.361 90.576 6.905 97.128 ;
     RECT  6.901 43.92 6.937 63.48 ;
     RECT  6.437 64.656 7.009 65.592 ;
     RECT  6.617 66.624 7.009 73.32 ;
     RECT  6.901 38.256 7.045 42.504 ;
     RECT  7.045 38.16 7.117 42.504 ;
     RECT  6.901 14.208 7.153 19.368 ;
     RECT  6.113 20.88 7.153 25.464 ;
     RECT  5.429 88.848 7.153 89.544 ;
     RECT  6.905 90.576 7.153 96.072 ;
     RECT  7.117 38.16 7.297 42.744 ;
     RECT  6.937 43.824 7.297 63.48 ;
     RECT  6.329 5.472 7.405 6.888 ;
     RECT  6.329 9.072 7.405 12.744 ;
     RECT  6.577 4.176 7.429 4.488 ;
     RECT  7.405 5.472 7.429 7.128 ;
     RECT  7.405 8.448 7.429 12.744 ;
     RECT  7.153 14.208 7.429 25.464 ;
     RECT  6.757 86.688 7.477 87.432 ;
     RECT  7.153 88.848 7.477 96.072 ;
     RECT  7.429 8.448 7.513 25.464 ;
     RECT  7.429 4.176 7.573 7.128 ;
     RECT  7.513 8.448 7.573 26.28 ;
     RECT  6.083 74.88 7.657 79.752 ;
     RECT  6.083 80.784 7.657 85.512 ;
     RECT  7.573 4.176 7.808 26.28 ;
     RECT  6.797 27.6 7.808 33.576 ;
     RECT  6.649 34.752 7.808 36.84 ;
     RECT  7.297 38.16 7.808 63.48 ;
     RECT  7.009 64.656 7.808 73.32 ;
     RECT  7.657 74.88 7.808 85.512 ;
     RECT  7.477 86.688 7.808 96.072 ;
     RECT  7.808 2.148 7.912 96.072 ;
     RECT  7.912 2.418 8.104 96.072 ;
     RECT  8.104 38.16 8.525 63.288 ;
     RECT  8.104 8.448 8.705 36.84 ;
     RECT  8.525 38.4 8.705 63.288 ;
     RECT  8.705 40.368 8.819 63.288 ;
     RECT  8.705 8.448 8.849 36.504 ;
     RECT  8.104 2.832 9.097 7.32 ;
     RECT  8.849 8.448 9.097 28.344 ;
     RECT  8.819 40.8 9.241 63.288 ;
     RECT  8.104 64.368 9.241 65.592 ;
     RECT  8.104 66.816 9.241 96.072 ;
     RECT  8.705 38.4 9.529 39.336 ;
     RECT  9.241 40.8 9.533 96.072 ;
     RECT  9.529 37.632 9.685 39.336 ;
     RECT  9.533 40.8 9.713 88.104 ;
     RECT  9.685 37.488 9.731 39.336 ;
     RECT  9.533 89.088 9.929 96.072 ;
     RECT  9.097 2.832 9.997 28.344 ;
     RECT  8.849 29.328 9.997 36.504 ;
     RECT  9.731 38.688 10.177 39.336 ;
     RECT  9.713 40.8 10.321 88.056 ;
     RECT  10.321 40.512 10.325 88.056 ;
     RECT  9.997 2.832 10.357 36.504 ;
     RECT  10.357 2.544 10.465 36.504 ;
     RECT  9.731 37.488 10.465 37.656 ;
     RECT  10.465 2.544 10.499 37.656 ;
     RECT  10.499 3.936 10.861 37.656 ;
     RECT  10.177 38.688 10.861 39.48 ;
     RECT  10.861 3.936 10.897 39.48 ;
     RECT  10.325 40.512 10.897 47.352 ;
     RECT  10.325 48.72 10.933 88.056 ;
     RECT  9.929 89.184 10.933 96.072 ;
     RECT  6.905 97.056 11.173 97.128 ;
     RECT  10.897 3.936 11.507 47.352 ;
     RECT  11.507 22.224 11.549 47.352 ;
     RECT  11.549 22.8 11.555 47.352 ;
     RECT  11.507 3.936 11.699 21.24 ;
     RECT  10.933 48.72 11.795 96.072 ;
     RECT  10.499 2.544 11.797 2.904 ;
     RECT  11.699 3.936 11.797 5.256 ;
     RECT  11.795 74.544 11.837 96.072 ;
     RECT  11.555 23.04 11.845 47.352 ;
     RECT  11.795 48.72 11.845 73.56 ;
     RECT  11.845 23.04 11.873 73.56 ;
     RECT  11.699 6.24 11.945 21.24 ;
     RECT  11.837 74.544 11.945 95.496 ;
     RECT  11.873 23.04 11.981 45.864 ;
     RECT  11.173 97.056 12.193 97.176 ;
     RECT  11.797 2.544 12.229 5.256 ;
     RECT  11.981 23.04 12.697 29.928 ;
     RECT  11.873 46.944 12.805 73.56 ;
     RECT  11.945 74.544 12.805 94.44 ;
     RECT  11.945 8.4 12.877 21.24 ;
     RECT  12.805 46.944 12.913 94.44 ;
     RECT  11.945 95.424 12.913 95.496 ;
     RECT  11.945 6.24 12.985 7.416 ;
     RECT  12.877 8.4 12.985 21.528 ;
     RECT  12.697 22.848 13.057 29.928 ;
     RECT  11.981 31.104 13.057 45.864 ;
     RECT  12.229 2.256 13.093 5.256 ;
     RECT  12.985 6.24 13.093 21.528 ;
     RECT  13.093 2.256 13.208 21.528 ;
     RECT  13.057 22.848 13.208 45.864 ;
     RECT  12.913 46.944 13.208 95.496 ;
     RECT  13.208 2.148 13.504 95.496 ;
     RECT  13.504 2.148 13.673 59.064 ;
     RECT  13.673 2.148 13.889 45.576 ;
     RECT  13.889 2.148 14.003 45 ;
     RECT  13.504 92.928 14.105 95.496 ;
     RECT  14.105 92.928 14.141 94.44 ;
     RECT  14.003 2.148 14.197 39.48 ;
     RECT  14.197 2.112 14.461 39.48 ;
     RECT  13.673 46.656 14.497 59.064 ;
     RECT  13.504 60.048 14.497 91.704 ;
     RECT  14.497 46.656 14.537 91.704 ;
     RECT  14.141 92.928 14.569 94.392 ;
     RECT  14.537 46.656 14.713 91.464 ;
     RECT  14.003 40.608 14.869 45 ;
     RECT  14.569 92.784 14.969 94.392 ;
     RECT  13.885 0.048 15.001 0.072 ;
     RECT  14.461 1.392 15.001 39.48 ;
     RECT  15.001 0.048 15.037 39.48 ;
     RECT  14.869 40.608 15.145 45.144 ;
     RECT  15.037 0.048 15.349 39.528 ;
     RECT  15.145 40.512 15.349 45.144 ;
     RECT  14.713 46.368 15.401 91.464 ;
     RECT  14.105 95.424 15.433 95.496 ;
     RECT  15.401 64.896 15.649 91.464 ;
     RECT  15.401 46.368 15.733 63.864 ;
     RECT  15.349 0.048 15.757 45.144 ;
     RECT  15.733 46.176 15.757 63.864 ;
     RECT  14.969 92.928 15.901 94.392 ;
     RECT  15.433 95.424 15.901 95.544 ;
     RECT  15.757 0.048 16.157 63.864 ;
     RECT  15.901 92.928 16.481 95.544 ;
     RECT  16.481 95.424 16.501 95.544 ;
     RECT  12.193 96.864 16.501 97.176 ;
     RECT  15.649 64.896 16.549 91.8 ;
     RECT  16.481 92.928 16.549 94.344 ;
     RECT  16.549 64.896 17.269 94.344 ;
     RECT  17.269 64.656 17.809 94.344 ;
     RECT  16.157 0.048 18.205 63.384 ;
     RECT  17.809 64.368 18.205 94.344 ;
     RECT  18.205 0.048 18.608 94.344 ;
     RECT  16.501 95.424 18.608 97.176 ;
     RECT  18.608 0.048 18.904 97.176 ;
     RECT  18.904 0.048 19.897 40.92 ;
     RECT  18.904 42 19.897 47.4 ;
     RECT  18.904 48.72 19.897 97.176 ;
     RECT  19.897 0.048 20.621 97.176 ;
     RECT  20.621 0.048 21.661 75.528 ;
     RECT  20.621 76.512 21.661 97.176 ;
     RECT  21.661 0.048 22.547 97.176 ;
     RECT  22.547 0.048 22.643 91.704 ;
     RECT  22.643 30.576 22.745 91.704 ;
     RECT  22.745 45.696 22.997 91.704 ;
     RECT  22.745 30.576 23.821 44.712 ;
     RECT  22.997 45.696 23.821 70.104 ;
     RECT  22.643 0.048 24.008 29.592 ;
     RECT  23.821 30.576 24.008 70.104 ;
     RECT  22.997 71.136 24.008 91.704 ;
     RECT  22.547 92.736 24.008 97.176 ;
     RECT  24.008 0.048 24.467 97.176 ;
     RECT  24.467 0.048 24.509 95.112 ;
     RECT  24.509 80.544 24.545 95.112 ;
     RECT  24.509 0.048 24.653 79.56 ;
     RECT  24.467 96.336 24.947 97.176 ;
     RECT  24.653 0.048 25.049 70.104 ;
     RECT  24.545 81.84 25.157 95.112 ;
     RECT  24.545 80.544 25.409 80.856 ;
     RECT  25.157 81.84 25.481 90.84 ;
     RECT  25.409 80.544 25.733 80.808 ;
     RECT  24.653 71.088 25.841 79.56 ;
     RECT  25.841 76.8 25.945 79.56 ;
     RECT  25.733 80.544 25.945 80.712 ;
     RECT  25.049 0.048 25.955 70.008 ;
     RECT  25.157 92.064 25.957 95.112 ;
     RECT  25.955 18.672 25.985 70.008 ;
     RECT  25.957 92.064 26.053 95.16 ;
     RECT  24.947 96.864 26.053 97.176 ;
     RECT  25.945 76.8 26.057 80.712 ;
     RECT  25.985 45.504 26.089 70.008 ;
     RECT  25.841 71.088 26.089 75.816 ;
     RECT  25.481 82.08 26.125 90.84 ;
     RECT  26.053 92.064 26.125 97.176 ;
     RECT  26.125 82.08 26.195 97.176 ;
     RECT  25.955 0.048 26.201 17.688 ;
     RECT  26.195 82.512 26.633 97.176 ;
     RECT  26.633 82.512 26.777 93 ;
     RECT  26.201 9.84 26.813 17.688 ;
     RECT  26.813 14.64 26.885 17.688 ;
     RECT  25.985 18.672 27.061 44.472 ;
     RECT  26.089 45.504 27.061 75.816 ;
     RECT  26.777 86.736 27.107 93 ;
     RECT  26.057 76.944 27.169 80.712 ;
     RECT  27.061 18.672 27.173 75.816 ;
     RECT  26.201 0.048 27.245 8.808 ;
     RECT  27.173 19.104 27.253 75.816 ;
     RECT  27.169 76.944 27.253 81.096 ;
     RECT  27.245 0.096 27.313 8.808 ;
     RECT  26.813 9.84 27.313 13.464 ;
     RECT  27.253 19.104 27.421 81.096 ;
     RECT  27.421 19.104 27.445 81.192 ;
     RECT  27.445 19.104 27.493 81.24 ;
     RECT  27.493 19.104 27.497 81.432 ;
     RECT  27.497 70.032 27.589 81.432 ;
     RECT  27.589 70.032 27.713 81.528 ;
     RECT  27.313 0.096 27.817 13.464 ;
     RECT  26.885 14.64 27.817 16.968 ;
     RECT  27.107 86.736 27.857 92.952 ;
     RECT  27.713 70.032 27.893 81.432 ;
     RECT  27.497 19.104 27.929 69 ;
     RECT  27.893 70.032 27.929 81.096 ;
     RECT  27.817 0.096 27.997 16.968 ;
     RECT  27.997 0.096 28.019 17.688 ;
     RECT  28.019 0.144 28.021 17.688 ;
     RECT  27.929 19.104 28.289 67.608 ;
     RECT  28.021 0.144 28.307 18.024 ;
     RECT  26.777 82.512 28.321 85.752 ;
     RECT  27.857 86.736 28.321 90.024 ;
     RECT  26.633 94.08 28.465 97.176 ;
     RECT  28.289 45.504 28.897 67.608 ;
     RECT  27.929 68.688 28.897 69 ;
     RECT  27.929 70.032 28.969 75.768 ;
     RECT  27.929 76.8 28.969 81.096 ;
     RECT  28.307 2.208 28.981 18.024 ;
     RECT  28.289 19.104 28.981 44.472 ;
     RECT  28.307 0.144 29.029 1.176 ;
     RECT  28.969 70.032 29.077 81.096 ;
     RECT  28.321 82.512 29.077 90.024 ;
     RECT  27.857 91.392 29.077 92.952 ;
     RECT  29.077 91.152 29.221 92.952 ;
     RECT  28.465 94.032 29.221 97.176 ;
     RECT  29.029 0.096 29.293 1.176 ;
     RECT  28.981 2.208 29.293 44.472 ;
     RECT  29.293 0.096 29.365 44.472 ;
     RECT  28.897 45.504 29.365 69 ;
     RECT  29.365 0.096 29.408 69 ;
     RECT  29.077 70.032 29.408 90.024 ;
     RECT  29.221 91.152 29.408 97.176 ;
     RECT  29.408 0.096 29.704 97.176 ;
     RECT  29.704 91.152 29.729 97.176 ;
     RECT  29.704 26.256 29.891 79.752 ;
     RECT  29.891 26.256 29.939 77.064 ;
     RECT  29.891 78.384 29.945 79.752 ;
     RECT  29.704 0.096 29.981 15.24 ;
     RECT  29.981 0.096 29.987 10.872 ;
     RECT  29.945 78.864 29.987 79.752 ;
     RECT  29.704 80.832 29.987 88.968 ;
     RECT  29.729 91.152 30.179 97.08 ;
     RECT  29.987 80.832 30.227 83.256 ;
     RECT  29.987 84.288 30.269 88.968 ;
     RECT  30.179 92.4 30.305 97.08 ;
     RECT  29.987 0.096 30.413 10.824 ;
     RECT  30.269 84.288 30.419 87.624 ;
     RECT  30.419 84.288 30.467 87.24 ;
     RECT  30.305 94.08 30.521 97.08 ;
     RECT  29.981 12.24 30.697 15.24 ;
     RECT  29.704 16.464 30.697 19.56 ;
     RECT  29.704 20.88 30.697 25.272 ;
     RECT  29.939 26.256 30.697 76.968 ;
     RECT  29.987 78.912 30.769 79.752 ;
     RECT  30.227 80.832 30.769 82.536 ;
     RECT  30.697 12.24 30.949 19.56 ;
     RECT  30.697 20.88 30.949 76.968 ;
     RECT  30.179 91.152 30.953 91.176 ;
     RECT  30.769 78.912 30.985 82.536 ;
     RECT  30.949 12.24 30.989 76.968 ;
     RECT  30.305 92.4 31.025 93.096 ;
     RECT  30.985 78.672 31.061 82.536 ;
     RECT  30.269 88.944 31.093 88.968 ;
     RECT  30.989 12.24 31.097 33.432 ;
     RECT  31.097 12.24 31.129 31.464 ;
     RECT  31.093 88.944 31.165 89.448 ;
     RECT  30.467 84.288 31.313 86.76 ;
     RECT  31.061 82.032 31.345 82.536 ;
     RECT  30.989 34.464 31.385 76.968 ;
     RECT  31.129 12.192 31.417 31.464 ;
     RECT  31.025 92.4 31.417 92.424 ;
     RECT  31.061 78.672 31.421 81 ;
     RECT  31.165 88.944 31.475 90.072 ;
     RECT  31.417 91.488 31.475 92.424 ;
     RECT  31.345 82.032 31.489 82.68 ;
     RECT  31.475 88.944 31.489 89.496 ;
     RECT  30.413 0.096 31.525 10.44 ;
     RECT  31.417 11.52 31.525 31.464 ;
     RECT  31.489 88.416 31.619 89.496 ;
     RECT  31.421 78.672 31.637 80.472 ;
     RECT  31.525 0.096 31.709 31.464 ;
     RECT  31.709 0.096 31.745 26.856 ;
     RECT  31.385 70.944 31.745 76.968 ;
     RECT  31.313 84.288 31.781 86.376 ;
     RECT  31.745 71.184 31.813 76.968 ;
     RECT  31.745 0.096 31.817 20.184 ;
     RECT  31.489 82.032 31.853 83.208 ;
     RECT  31.781 84.288 31.961 84.36 ;
     RECT  31.817 10.128 31.997 20.184 ;
     RECT  31.853 82.032 32.029 82.536 ;
     RECT  31.781 85.488 32.069 86.376 ;
     RECT  31.813 71.184 32.101 77.112 ;
     RECT  31.637 78.672 32.101 78.696 ;
     RECT  32.101 71.184 32.105 78.696 ;
     RECT  31.619 89.136 32.141 89.496 ;
     RECT  32.105 71.28 32.147 78.696 ;
     RECT  31.097 32.832 32.245 33.432 ;
     RECT  32.245 32.64 32.281 33.432 ;
     RECT  31.385 34.464 32.281 69.96 ;
     RECT  31.709 27.84 32.317 31.464 ;
     RECT  32.281 32.64 32.317 69.96 ;
     RECT  31.997 10.176 32.429 20.184 ;
     RECT  32.429 10.176 32.483 18.072 ;
     RECT  32.317 27.84 32.483 69.96 ;
     RECT  32.147 71.28 32.483 77.736 ;
     RECT  32.483 27.888 32.533 69.96 ;
     RECT  32.483 10.272 32.537 10.44 ;
     RECT  31.637 79.728 32.569 80.472 ;
     RECT  32.537 10.416 32.573 10.44 ;
     RECT  31.745 21.216 32.573 26.856 ;
     RECT  32.533 27.888 32.579 70.152 ;
     RECT  32.579 27.888 32.717 69.384 ;
     RECT  31.817 0.096 32.861 8.856 ;
     RECT  30.521 94.368 32.867 97.08 ;
     RECT  32.429 19.44 32.897 20.184 ;
     RECT  32.867 94.368 32.915 96.984 ;
     RECT  32.029 81.648 32.917 82.536 ;
     RECT  32.173 83.856 32.917 83.928 ;
     RECT  32.569 79.728 32.929 80.664 ;
     RECT  32.069 86.352 32.963 86.376 ;
     RECT  32.483 11.808 32.969 18.072 ;
     RECT  32.929 79.68 33.037 80.664 ;
     RECT  32.717 27.888 33.059 41.928 ;
     RECT  32.717 43.248 33.059 69.384 ;
     RECT  32.861 7.392 33.061 8.856 ;
     RECT  33.037 79.488 33.061 80.664 ;
     RECT  32.917 81.648 33.061 83.928 ;
     RECT  31.475 92.112 33.145 92.424 ;
     RECT  33.061 79.488 33.149 83.928 ;
     RECT  32.573 21.216 33.181 26.808 ;
     RECT  33.059 27.888 33.257 33.912 ;
     RECT  33.349 90.048 33.401 90.072 ;
     RECT  32.897 19.44 33.433 19.464 ;
     RECT  32.483 71.472 33.469 77.736 ;
     RECT  33.469 71.472 33.541 77.928 ;
     RECT  33.145 92.112 33.545 93.288 ;
     RECT  33.361 88.704 33.577 88.728 ;
     RECT  33.061 7.392 33.613 9 ;
     RECT  32.969 16.656 33.649 18.072 ;
     RECT  33.433 19.392 33.649 19.464 ;
     RECT  33.059 35.04 33.757 41.928 ;
     RECT  33.059 43.248 33.757 61.416 ;
     RECT  32.969 11.808 33.829 15.624 ;
     RECT  33.613 7.392 33.901 9.192 ;
     RECT  33.829 10.848 33.973 15.624 ;
     RECT  33.649 16.656 33.973 19.464 ;
     RECT  33.901 7.392 34.021 9.72 ;
     RECT  33.545 92.304 34.045 93.288 ;
     RECT  32.915 94.368 34.045 96.024 ;
     RECT  32.861 0.096 34.081 6.312 ;
     RECT  34.021 7.392 34.081 9.768 ;
     RECT  33.973 10.848 34.081 19.464 ;
     RECT  33.181 20.496 34.081 26.808 ;
     RECT  33.541 71.472 34.117 78.312 ;
     RECT  33.757 35.04 34.153 61.416 ;
     RECT  33.059 62.448 34.153 69.384 ;
     RECT  33.149 79.488 34.165 82.968 ;
     RECT  33.685 84.96 34.165 84.984 ;
     RECT  34.117 71.184 34.225 78.312 ;
     RECT  34.153 35.04 34.261 69.384 ;
     RECT  34.225 70.512 34.261 78.312 ;
     RECT  34.261 35.04 34.333 78.312 ;
     RECT  34.333 34.848 34.357 78.312 ;
     RECT  34.165 79.488 34.357 84.984 ;
     RECT  33.973 86.592 34.369 86.616 ;
     RECT  34.081 10.848 34.405 26.808 ;
     RECT  33.257 27.888 34.405 33.624 ;
     RECT  34.369 86.592 34.405 86.76 ;
     RECT  33.577 88.704 34.405 89.208 ;
     RECT  34.369 90.288 34.405 90.312 ;
     RECT  34.045 92.304 34.657 96.024 ;
     RECT  34.657 91.872 34.693 96.024 ;
     RECT  34.405 88.704 34.729 90.312 ;
     RECT  34.693 91.44 34.729 96.024 ;
     RECT  34.357 34.848 34.765 84.984 ;
     RECT  34.405 85.968 34.765 86.76 ;
     RECT  34.081 0.096 34.808 9.768 ;
     RECT  34.405 10.848 34.808 33.624 ;
     RECT  34.765 34.848 34.808 86.76 ;
     RECT  34.729 88.704 34.808 96.024 ;
     RECT  34.808 0.096 35.104 96.024 ;
     RECT  35.104 26.112 35.201 33.624 ;
     RECT  35.104 8.448 35.219 25.032 ;
     RECT  35.219 8.448 35.237 24.936 ;
     RECT  35.237 8.448 35.267 13.944 ;
     RECT  35.237 14.928 35.273 24.936 ;
     RECT  35.273 20.832 35.315 24.936 ;
     RECT  35.273 14.928 35.345 19.848 ;
     RECT  35.345 15.072 35.411 19.848 ;
     RECT  35.315 20.88 35.489 24.936 ;
     RECT  35.201 26.208 35.489 33.624 ;
     RECT  35.267 8.976 35.555 13.944 ;
     RECT  35.104 0.096 35.629 6.888 ;
     RECT  35.555 9.072 35.699 13.944 ;
     RECT  35.489 29.568 35.939 33.624 ;
     RECT  35.699 9.072 35.993 9.624 ;
     RECT  35.104 35.04 36.137 96.024 ;
     RECT  35.489 24.192 36.209 24.936 ;
     RECT  35.489 20.88 36.313 23.064 ;
     RECT  35.939 30.096 36.349 33.624 ;
     RECT  36.137 35.04 36.349 93.336 ;
     RECT  35.411 15.072 36.421 19.32 ;
     RECT  36.313 20.448 36.421 23.064 ;
     RECT  36.349 30.096 36.461 93.336 ;
     RECT  36.461 35.04 36.497 93.336 ;
     RECT  35.629 0.048 36.529 6.888 ;
     RECT  36.209 24.912 36.533 24.936 ;
     RECT  36.529 0.048 36.641 7.416 ;
     RECT  36.497 35.04 36.677 83.592 ;
     RECT  36.601 25.056 36.745 25.08 ;
     RECT  35.489 26.208 36.745 28.44 ;
     RECT  36.677 48.432 36.803 83.592 ;
     RECT  36.421 15.072 36.817 23.064 ;
     RECT  35.993 9.072 36.853 9.192 ;
     RECT  36.803 52.848 36.857 83.592 ;
     RECT  36.745 25.056 36.961 28.44 ;
     RECT  35.699 10.896 36.997 13.944 ;
     RECT  36.817 15.072 36.997 23.928 ;
     RECT  36.997 10.896 37.045 23.928 ;
     RECT  36.853 9.024 37.105 9.192 ;
     RECT  37.045 10.608 37.105 23.928 ;
     RECT  36.641 0.048 37.433 6.36 ;
     RECT  36.137 94.32 37.433 96.024 ;
     RECT  36.461 30.096 37.501 34.056 ;
     RECT  36.677 35.04 37.501 47.4 ;
     RECT  36.641 7.392 37.573 7.416 ;
     RECT  36.961 25.056 37.573 28.728 ;
     RECT  37.501 30.096 37.573 47.4 ;
     RECT  37.573 7.392 37.609 7.848 ;
     RECT  37.105 9.024 37.609 23.928 ;
     RECT  36.497 84.576 37.609 93.336 ;
     RECT  37.433 94.32 37.609 95.496 ;
     RECT  37.573 25.056 37.789 47.4 ;
     RECT  36.803 48.432 37.789 51.72 ;
     RECT  37.609 7.392 37.897 23.928 ;
     RECT  37.789 25.056 37.897 51.72 ;
     RECT  36.857 52.896 37.897 83.592 ;
     RECT  37.609 84.576 37.897 95.496 ;
     RECT  37.897 52.896 38.581 95.496 ;
     RECT  37.897 7.392 38.677 51.72 ;
     RECT  38.581 52.752 38.677 95.496 ;
     RECT  37.433 0.048 38.977 6.312 ;
     RECT  38.677 7.392 38.977 95.496 ;
     RECT  38.977 0.048 39.301 95.496 ;
     RECT  39.301 0.048 40.021 96.36 ;
     RECT  40.021 0.048 40.165 97.032 ;
     RECT  40.165 0.048 40.201 97.08 ;
     RECT  40.201 0.048 41.825 97.176 ;
     RECT  41.825 0.048 42.077 95.496 ;
     RECT  42.077 38.208 42.617 95.496 ;
     RECT  42.617 81.12 42.755 95.496 ;
     RECT  42.755 81.12 42.761 84.552 ;
     RECT  42.617 38.208 42.833 80.088 ;
     RECT  41.825 96.912 43.045 97.176 ;
     RECT  42.755 85.68 43.429 95.496 ;
     RECT  42.833 38.208 43.549 74.76 ;
     RECT  42.833 75.792 43.621 80.088 ;
     RECT  42.761 81.12 43.621 84.408 ;
     RECT  43.549 38.16 43.801 74.76 ;
     RECT  43.621 75.792 43.801 84.408 ;
     RECT  43.801 38.16 43.837 84.408 ;
     RECT  43.045 96.864 44.149 97.176 ;
     RECT  43.837 38.16 44.377 84.6 ;
     RECT  43.429 85.68 44.377 95.544 ;
     RECT  42.077 0.048 44.389 37.176 ;
     RECT  44.377 38.16 44.389 95.544 ;
     RECT  44.149 96.816 45.061 97.176 ;
     RECT  44.389 0.048 46.451 95.544 ;
     RECT  46.451 54.48 46.721 95.544 ;
     RECT  46.451 0.048 46.835 53.4 ;
     RECT  45.061 96.768 47.269 97.176 ;
     RECT  46.835 0.048 47.363 39.912 ;
     RECT  47.363 0.048 47.369 23.304 ;
     RECT  46.835 41.088 47.437 53.4 ;
     RECT  46.721 54.48 47.437 70.248 ;
     RECT  47.437 41.088 47.513 70.248 ;
     RECT  47.513 54.624 47.729 70.248 ;
     RECT  47.513 41.088 47.843 53.592 ;
     RECT  47.729 55.008 47.843 70.248 ;
     RECT  47.843 41.088 48.017 51.72 ;
     RECT  48.017 50.64 48.161 51.72 ;
     RECT  47.363 24.528 48.301 39.912 ;
     RECT  48.017 41.088 48.301 49.56 ;
     RECT  48.161 51.696 48.341 51.72 ;
     RECT  47.843 52.704 48.341 53.304 ;
     RECT  47.843 56.88 48.409 70.248 ;
     RECT  46.721 71.328 48.409 95.544 ;
     RECT  47.269 96.72 48.413 97.176 ;
     RECT  48.409 56.88 48.445 95.544 ;
     RECT  48.413 96.72 48.445 97.08 ;
     RECT  47.369 0.048 48.467 23.256 ;
     RECT  48.445 56.88 48.521 97.08 ;
     RECT  48.467 2.304 48.553 23.256 ;
     RECT  48.301 24.528 48.553 49.56 ;
     RECT  48.521 79.536 48.701 97.08 ;
     RECT  48.701 79.536 48.737 79.704 ;
     RECT  47.843 55.008 48.853 55.896 ;
     RECT  48.161 50.64 48.899 50.712 ;
     RECT  48.553 2.304 48.917 49.56 ;
     RECT  48.467 0.048 48.947 1.128 ;
     RECT  48.701 80.736 48.947 97.08 ;
     RECT  48.917 2.304 48.953 49.557 ;
     RECT  48.953 2.304 48.989 11.832 ;
     RECT  48.947 80.736 48.989 95.544 ;
     RECT  48.953 12.96 49.043 49.557 ;
     RECT  48.899 50.688 49.133 50.712 ;
     RECT  48.341 52.704 49.417 52.728 ;
     RECT  48.853 54.912 49.417 55.896 ;
     RECT  48.521 56.88 49.417 78.552 ;
     RECT  49.417 52.704 49.453 53.496 ;
     RECT  49.417 54.72 49.453 78.552 ;
     RECT  48.947 0.048 49.493 0.648 ;
     RECT  48.989 2.304 49.525 11.736 ;
     RECT  49.453 52.704 49.525 78.552 ;
     RECT  48.947 96.72 49.529 97.08 ;
     RECT  49.525 52.368 49.669 78.552 ;
     RECT  48.737 79.68 49.849 79.704 ;
     RECT  48.989 80.736 49.849 95.496 ;
     RECT  49.525 1.92 49.957 11.736 ;
     RECT  49.669 52.368 49.997 78.696 ;
     RECT  49.043 13.008 50.101 49.557 ;
     RECT  49.997 52.368 50.101 57.72 ;
     RECT  49.957 1.92 50.341 11.832 ;
     RECT  50.341 1.92 50.389 11.976 ;
     RECT  50.101 51.984 50.389 57.72 ;
     RECT  49.997 59.04 50.461 78.696 ;
     RECT  49.849 79.68 50.461 95.496 ;
     RECT  50.389 1.776 50.533 11.976 ;
     RECT  50.533 1.728 50.677 11.976 ;
     RECT  50.101 12.96 50.677 49.557 ;
     RECT  50.389 51.408 50.677 57.72 ;
     RECT  49.493 0.096 50.785 0.648 ;
     RECT  50.677 1.728 50.785 49.557 ;
     RECT  49.529 96.768 50.821 97.08 ;
     RECT  50.785 0.096 50.867 49.557 ;
     RECT  50.821 96.72 50.929 97.08 ;
     RECT  50.867 1.104 51.008 49.557 ;
     RECT  50.677 51.264 51.008 57.72 ;
     RECT  50.461 59.04 51.008 95.496 ;
     RECT  51.008 1.104 51.059 95.496 ;
     RECT  51.059 1.728 51.257 95.496 ;
     RECT  51.257 1.776 51.301 95.496 ;
     RECT  51.301 1.776 51.304 95.736 ;
     RECT  50.867 0.096 51.365 0.12 ;
     RECT  51.304 51.648 51.509 53.976 ;
     RECT  51.304 58.704 51.589 95.736 ;
     RECT  50.929 96.72 51.589 97.176 ;
     RECT  51.304 55.008 51.689 57.72 ;
     RECT  51.304 1.776 51.875 49.752 ;
     RECT  51.875 12.192 52.157 49.752 ;
     RECT  52.157 39.84 52.163 49.752 ;
     RECT  52.163 42.48 52.333 49.752 ;
     RECT  51.509 52.8 52.405 53.976 ;
     RECT  51.689 55.008 52.405 56.04 ;
     RECT  52.333 42.48 52.481 50.616 ;
     RECT  52.481 44.352 52.513 50.616 ;
     RECT  51.509 51.648 52.513 51.672 ;
     RECT  51.689 57.12 52.549 57.72 ;
     RECT  51.589 58.704 52.549 97.176 ;
     RECT  52.549 57.12 52.769 97.176 ;
     RECT  51.875 1.776 52.909 11.064 ;
     RECT  52.909 1.776 53.017 11.112 ;
     RECT  52.157 12.192 53.017 38.808 ;
     RECT  52.769 96.528 53.057 97.176 ;
     RECT  52.513 44.352 53.077 51.672 ;
     RECT  53.077 44.352 53.089 51.816 ;
     RECT  52.405 52.8 53.089 56.04 ;
     RECT  53.017 1.776 53.093 38.808 ;
     RECT  53.089 44.352 53.317 56.04 ;
     RECT  52.769 57.12 53.317 95.544 ;
     RECT  53.317 44.352 53.345 95.544 ;
     RECT  53.057 96.672 53.453 97.176 ;
     RECT  52.163 39.84 53.521 41.496 ;
     RECT  52.481 42.48 53.521 43.176 ;
     RECT  53.345 44.352 53.521 54.456 ;
     RECT  53.345 55.536 53.777 95.544 ;
     RECT  53.777 79.776 53.843 95.544 ;
     RECT  53.521 39.84 53.987 54.456 ;
     RECT  53.987 43.872 54.035 54.456 ;
     RECT  54.035 45.408 54.173 54.456 ;
     RECT  53.987 39.84 54.209 42.6 ;
     RECT  53.093 1.92 54.241 38.808 ;
     RECT  54.209 39.84 54.241 40.296 ;
     RECT  54.241 1.92 54.281 40.296 ;
     RECT  54.281 28.32 54.371 40.296 ;
     RECT  54.371 39.84 54.533 40.296 ;
     RECT  54.281 1.92 54.565 27.336 ;
     RECT  54.209 42.576 54.569 42.6 ;
     RECT  53.843 79.92 54.709 95.544 ;
     RECT  53.453 96.72 54.709 97.176 ;
     RECT  54.209 41.328 54.749 41.496 ;
     RECT  54.565 1.728 54.755 27.336 ;
     RECT  54.533 39.84 54.785 40.056 ;
     RECT  54.709 79.92 54.803 97.176 ;
     RECT  54.803 79.92 54.929 95.544 ;
     RECT  54.745 0.528 55.033 0.552 ;
     RECT  54.173 45.408 55.249 49.896 ;
     RECT  54.173 51.072 55.249 54.456 ;
     RECT  55.249 45.408 55.321 54.456 ;
     RECT  53.777 55.536 55.321 78.744 ;
     RECT  55.033 0.528 55.333 0.6 ;
     RECT  55.321 45.408 55.357 78.744 ;
     RECT  54.785 39.936 55.433 40.056 ;
     RECT  55.333 0.096 55.525 0.6 ;
     RECT  54.755 1.728 55.525 27.288 ;
     RECT  54.035 43.872 55.621 44.376 ;
     RECT  54.749 41.376 55.789 41.496 ;
     RECT  55.753 42.528 55.789 42.552 ;
     RECT  55.789 41.376 55.897 42.744 ;
     RECT  55.621 43.824 55.897 44.376 ;
     RECT  55.897 41.376 55.957 44.376 ;
     RECT  55.357 45.408 55.957 78.936 ;
     RECT  55.957 41.376 56.005 78.936 ;
     RECT  54.929 80.016 56.005 95.544 ;
     RECT  55.525 0.096 56.041 27.288 ;
     RECT  54.371 28.32 56.041 38.808 ;
     RECT  56.041 0.096 56.185 38.808 ;
     RECT  56.005 41.376 56.365 95.544 ;
     RECT  56.185 0.096 56.408 39.336 ;
     RECT  56.365 40.608 56.408 95.544 ;
     RECT  56.408 0.096 56.677 95.544 ;
     RECT  54.803 96.72 56.677 97.176 ;
     RECT  56.677 0.096 56.704 97.176 ;
     RECT  56.704 0.096 56.797 39.336 ;
     RECT  56.704 52.272 57.053 77.64 ;
     RECT  56.704 78.912 57.125 97.176 ;
     RECT  57.053 52.272 57.377 74.616 ;
     RECT  56.704 40.608 57.665 51.144 ;
     RECT  57.125 79.728 57.773 97.176 ;
     RECT  56.797 0.048 57.841 39.336 ;
     RECT  57.665 40.608 57.841 50.328 ;
     RECT  57.841 0.048 57.881 50.328 ;
     RECT  57.377 54.864 57.923 74.616 ;
     RECT  57.881 10.32 57.953 50.328 ;
     RECT  57.923 66.096 57.953 74.616 ;
     RECT  57.377 52.272 57.985 53.88 ;
     RECT  57.881 0.048 57.989 9.24 ;
     RECT  57.053 75.936 58.213 77.64 ;
     RECT  58.213 75.936 58.261 78.168 ;
     RECT  57.953 70.8 58.309 74.616 ;
     RECT  58.261 75.84 58.309 78.168 ;
     RECT  57.773 79.728 58.345 89.256 ;
     RECT  58.345 79.2 58.349 89.256 ;
     RECT  58.309 70.8 58.381 78.168 ;
     RECT  58.349 79.2 58.381 89.208 ;
     RECT  57.953 10.32 58.385 26.664 ;
     RECT  58.381 70.8 58.403 89.208 ;
     RECT  57.985 51.696 58.417 53.88 ;
     RECT  57.923 54.864 58.417 64.968 ;
     RECT  57.773 90.288 58.421 97.176 ;
     RECT  57.953 27.888 58.451 50.328 ;
     RECT  58.403 70.8 58.451 83.016 ;
     RECT  58.385 10.32 58.457 26.424 ;
     RECT  58.451 27.888 58.499 39.384 ;
     RECT  58.499 27.984 58.529 39.384 ;
     RECT  58.457 10.32 58.643 11.256 ;
     RECT  58.643 10.32 58.673 11.16 ;
     RECT  58.529 28.08 58.709 39.384 ;
     RECT  58.421 90.816 58.745 97.176 ;
     RECT  58.709 28.08 58.781 29.064 ;
     RECT  58.745 90.816 58.781 91.464 ;
     RECT  58.457 12.336 58.817 26.424 ;
     RECT  58.817 24.384 58.925 26.424 ;
     RECT  58.673 10.32 58.997 10.872 ;
     RECT  58.709 30.576 59.033 39.384 ;
     RECT  57.953 66.096 59.065 69.576 ;
     RECT  58.997 10.704 59.105 10.872 ;
     RECT  59.033 30.576 59.177 33.672 ;
     RECT  58.451 70.896 59.285 83.016 ;
     RECT  58.817 12.336 59.321 23.304 ;
     RECT  59.285 79.2 59.321 83.016 ;
     RECT  58.451 40.608 59.353 50.328 ;
     RECT  58.417 51.696 59.353 64.968 ;
     RECT  59.177 30.576 59.393 33.24 ;
     RECT  59.033 34.656 59.425 39.384 ;
     RECT  59.353 40.608 59.425 64.968 ;
     RECT  59.425 34.656 59.429 64.968 ;
     RECT  59.065 66.096 59.501 69.912 ;
     RECT  59.429 34.656 59.507 49.557 ;
     RECT  59.393 32.976 59.573 33.24 ;
     RECT  58.781 91.152 59.573 91.464 ;
     RECT  58.403 84.144 59.605 89.208 ;
     RECT  58.925 25.488 59.641 26.424 ;
     RECT  58.781 28.08 59.641 28.488 ;
     RECT  59.285 70.896 59.677 78.072 ;
     RECT  59.429 50.736 59.749 64.968 ;
     RECT  59.501 66.096 59.749 68.952 ;
     RECT  59.605 84.144 59.753 90.072 ;
     RECT  59.321 22.128 59.785 23.304 ;
     RECT  58.925 24.384 59.785 24.408 ;
     RECT  59.321 12.336 59.893 21.144 ;
     RECT  59.785 22.128 59.893 24.408 ;
     RECT  59.641 25.488 59.893 28.488 ;
     RECT  59.753 88.944 59.897 90.072 ;
     RECT  59.677 70.656 59.933 78.072 ;
     RECT  57.989 0.048 59.989 9.144 ;
     RECT  59.105 10.704 59.989 10.728 ;
     RECT  59.893 22.128 60.005 28.488 ;
     RECT  60.005 25.728 60.073 28.488 ;
     RECT  59.393 30.576 60.073 31.704 ;
     RECT  59.933 75.984 60.113 78.072 ;
     RECT  59.989 0.048 60.181 10.728 ;
     RECT  59.507 34.656 60.257 40.44 ;
     RECT  59.753 84.144 60.257 87.624 ;
     RECT  60.181 0.048 60.289 10.872 ;
     RECT  59.893 12.192 60.289 21.144 ;
     RECT  58.745 92.688 60.293 97.176 ;
     RECT  60.073 25.728 60.361 31.704 ;
     RECT  59.573 32.976 60.361 33.048 ;
     RECT  59.507 41.616 60.433 49.557 ;
     RECT  59.749 50.736 60.433 68.952 ;
     RECT  60.433 41.616 60.517 68.952 ;
     RECT  59.933 70.656 60.517 71.4 ;
     RECT  60.257 38.064 60.577 40.44 ;
     RECT  60.517 41.616 60.577 71.4 ;
     RECT  59.897 88.944 60.611 88.968 ;
     RECT  60.577 38.064 60.659 71.4 ;
     RECT  59.321 79.728 60.685 83.016 ;
     RECT  60.257 84.144 60.685 86.04 ;
     RECT  60.659 38.064 60.707 68.424 ;
     RECT  60.361 25.728 60.721 33.048 ;
     RECT  60.257 87.6 60.721 87.624 ;
     RECT  60.113 75.984 60.761 77.64 ;
     RECT  60.685 79.728 60.829 86.04 ;
     RECT  60.289 0.048 60.901 21.144 ;
     RECT  60.005 22.128 60.901 24.648 ;
     RECT  60.721 87.6 60.901 87.672 ;
     RECT  60.659 69.792 60.973 71.4 ;
     RECT  59.933 72.48 60.973 74.712 ;
     RECT  60.761 75.984 60.973 77.112 ;
     RECT  60.901 0.048 61.009 24.648 ;
     RECT  60.721 25.728 61.009 33.672 ;
     RECT  59.897 90.048 61.009 90.072 ;
     RECT  59.573 91.44 61.009 91.464 ;
     RECT  61.009 90.048 61.153 91.464 ;
     RECT  60.293 92.688 61.153 97.128 ;
     RECT  60.707 38.064 61.225 68.232 ;
     RECT  60.829 78.912 61.225 86.04 ;
     RECT  61.225 78.672 61.261 86.04 ;
     RECT  61.225 37.968 61.297 68.232 ;
     RECT  60.901 87.6 61.405 88.488 ;
     RECT  60.257 34.656 61.477 36.84 ;
     RECT  61.297 37.92 61.477 68.232 ;
     RECT  61.261 78.096 61.477 86.04 ;
     RECT  61.009 0.048 61.525 33.672 ;
     RECT  61.477 34.656 61.525 68.232 ;
     RECT  61.153 90.048 61.585 97.128 ;
     RECT  61.405 87.36 61.621 88.488 ;
     RECT  60.973 69.792 61.765 77.112 ;
     RECT  61.477 78.096 61.765 86.28 ;
     RECT  61.525 0.048 61.808 68.232 ;
     RECT  61.765 69.792 61.808 86.28 ;
     RECT  61.621 87.312 61.808 88.488 ;
     RECT  61.585 89.568 61.808 97.128 ;
     RECT  61.808 0.048 61.957 97.128 ;
     RECT  61.957 0.048 62.104 97.176 ;
     RECT  62.104 80.64 62.165 84.84 ;
     RECT  62.104 86.016 62.165 87.672 ;
     RECT  62.165 86.304 62.273 87.672 ;
     RECT  62.104 90.24 62.309 97.176 ;
     RECT  62.104 0.048 62.705 11.016 ;
     RECT  62.104 34.896 62.741 79.56 ;
     RECT  62.741 34.896 62.777 79.464 ;
     RECT  62.777 71.808 62.885 79.464 ;
     RECT  62.777 34.896 62.993 70.632 ;
     RECT  62.104 12 63.011 33.096 ;
     RECT  63.011 21.744 63.107 33.096 ;
     RECT  62.273 86.544 63.109 87.672 ;
     RECT  62.885 71.808 63.137 79.08 ;
     RECT  63.107 30.432 63.157 33.096 ;
     RECT  62.993 34.896 63.157 61.704 ;
     RECT  62.165 81.36 63.169 84.84 ;
     RECT  62.705 0.096 63.205 11.016 ;
     RECT  63.011 12 63.205 20.184 ;
     RECT  63.157 30.432 63.205 33.384 ;
     RECT  63.157 34.8 63.205 61.704 ;
     RECT  63.109 86.544 63.277 87.72 ;
     RECT  63.205 0.096 63.353 20.184 ;
     RECT  63.277 86.448 63.493 87.72 ;
     RECT  63.421 88.896 63.565 88.92 ;
     RECT  62.309 90.24 63.565 91.464 ;
     RECT  63.169 80.88 63.601 84.84 ;
     RECT  63.493 85.968 63.685 87.72 ;
     RECT  63.565 88.896 63.685 91.464 ;
     RECT  63.601 80.88 63.745 84.984 ;
     RECT  63.745 80.832 63.779 84.984 ;
     RECT  62.993 62.736 63.817 70.632 ;
     RECT  63.779 80.832 63.829 84.888 ;
     RECT  63.685 85.968 63.961 91.464 ;
     RECT  62.309 92.784 63.961 97.176 ;
     RECT  63.961 85.968 64.019 97.176 ;
     RECT  63.107 21.744 64.105 29.208 ;
     RECT  63.353 0.192 64.117 20.184 ;
     RECT  64.105 21.264 64.117 29.208 ;
     RECT  63.817 62.736 64.213 70.824 ;
     RECT  63.137 72.048 64.213 79.08 ;
     RECT  63.205 30.432 64.249 61.704 ;
     RECT  64.213 62.736 64.249 79.08 ;
     RECT  64.117 0.192 64.357 29.208 ;
     RECT  64.249 30.432 64.357 79.08 ;
     RECT  63.829 80.256 64.357 84.888 ;
     RECT  64.357 0.144 64.537 29.208 ;
     RECT  64.357 30.432 64.577 84.888 ;
     RECT  64.577 72.432 64.741 84.888 ;
     RECT  64.019 85.968 64.741 91.752 ;
     RECT  64.577 30.432 64.865 71.448 ;
     RECT  64.865 30.432 65.117 39.816 ;
     RECT  64.537 0.096 65.185 29.208 ;
     RECT  65.117 30.432 65.185 39.768 ;
     RECT  65.185 0.096 65.657 39.768 ;
     RECT  64.865 40.8 65.689 71.448 ;
     RECT  64.741 72.432 65.689 91.752 ;
     RECT  64.019 92.784 65.689 97.176 ;
     RECT  65.689 40.8 66.197 97.176 ;
     RECT  65.657 30.96 66.229 39.768 ;
     RECT  66.197 40.8 66.229 70.584 ;
     RECT  65.657 0.096 66.949 29.784 ;
     RECT  66.229 30.96 66.949 70.584 ;
     RECT  66.949 0.096 67.208 70.584 ;
     RECT  66.197 72 67.208 97.176 ;
     RECT  67.208 0.096 67.504 97.176 ;
     RECT  67.504 30.576 67.529 97.176 ;
     RECT  67.529 30.624 67.601 97.176 ;
     RECT  67.601 30.72 67.781 97.176 ;
     RECT  67.781 30.72 67.889 68.136 ;
     RECT  67.781 69.216 68.177 97.176 ;
     RECT  67.889 60.048 68.249 68.136 ;
     RECT  67.504 0.096 68.285 29.592 ;
     RECT  68.285 7.632 68.641 29.592 ;
     RECT  67.889 30.72 68.641 59.064 ;
     RECT  68.641 7.632 68.723 59.064 ;
     RECT  68.249 60.384 68.965 68.136 ;
     RECT  68.723 30.672 69.073 59.064 ;
     RECT  68.965 60.384 69.217 68.232 ;
     RECT  68.177 69.216 69.217 96.024 ;
     RECT  68.285 0.096 69.253 6.6 ;
     RECT  68.723 7.632 69.253 29.688 ;
     RECT  69.253 0.096 69.581 29.688 ;
     RECT  69.217 60.384 69.587 96.024 ;
     RECT  69.587 60.384 69.761 92.808 ;
     RECT  69.581 18.336 69.793 29.688 ;
     RECT  69.073 30.672 69.793 59.16 ;
     RECT  69.761 60.576 69.869 92.808 ;
     RECT  69.793 18.336 69.875 59.16 ;
     RECT  69.875 18.336 69.941 29.688 ;
     RECT  69.581 0.096 70.081 17.16 ;
     RECT  69.869 60.576 70.121 88.248 ;
     RECT  70.121 60.576 70.193 86.856 ;
     RECT  70.193 60.816 70.265 86.856 ;
     RECT  69.875 30.864 70.297 59.16 ;
     RECT  69.587 93.84 70.337 96.024 ;
     RECT  70.081 0.048 70.585 17.16 ;
     RECT  69.941 18.336 70.585 29.544 ;
     RECT  70.585 0.048 70.661 29.544 ;
     RECT  69.869 89.52 70.693 92.808 ;
     RECT  70.337 93.84 70.693 95.592 ;
     RECT  68.177 97.008 70.693 97.176 ;
     RECT  70.297 30.864 70.733 59.592 ;
     RECT  70.661 14.256 70.739 22.104 ;
     RECT  70.739 14.304 70.913 22.104 ;
     RECT  70.913 20.784 70.949 22.104 ;
     RECT  70.733 30.864 71.017 32.472 ;
     RECT  70.661 23.088 71.089 29.544 ;
     RECT  71.017 30.672 71.089 32.472 ;
     RECT  70.121 87.888 71.089 88.248 ;
     RECT  70.693 89.52 71.089 95.592 ;
     RECT  71.089 87.888 71.201 95.592 ;
     RECT  71.089 23.088 71.237 32.472 ;
     RECT  70.265 61.008 71.269 86.856 ;
     RECT  71.201 87.888 71.269 95.448 ;
     RECT  71.237 23.328 71.507 32.472 ;
     RECT  71.269 61.008 71.507 95.448 ;
     RECT  71.507 24.528 71.525 32.472 ;
     RECT  70.733 33.456 71.629 59.592 ;
     RECT  71.629 33.456 71.737 59.784 ;
     RECT  71.507 61.008 71.737 69.336 ;
     RECT  70.661 0.048 71.797 13.176 ;
     RECT  70.913 14.304 71.797 19.608 ;
     RECT  71.797 0.048 71.881 19.608 ;
     RECT  70.949 20.784 71.881 22.056 ;
     RECT  71.525 24.672 71.989 32.472 ;
     RECT  71.737 33.456 71.989 69.336 ;
     RECT  71.881 0.048 72.373 22.056 ;
     RECT  71.507 23.328 72.373 23.4 ;
     RECT  72.373 0.048 72.608 23.4 ;
     RECT  71.989 24.672 72.608 69.336 ;
     RECT  71.507 70.32 72.608 95.448 ;
     RECT  72.608 0.048 72.904 95.448 ;
     RECT  72.904 0.048 72.929 23.88 ;
     RECT  70.693 96.72 72.961 97.176 ;
     RECT  72.904 32.208 72.997 95.448 ;
     RECT  72.961 96.624 72.997 97.176 ;
     RECT  72.904 24.912 73.001 31.176 ;
     RECT  72.929 0.048 73.505 23.592 ;
     RECT  72.997 32.208 73.715 97.176 ;
     RECT  73.715 32.208 73.897 95.448 ;
     RECT  73.001 24.912 73.969 29.832 ;
     RECT  73.001 30.96 73.969 31.176 ;
     RECT  73.969 24.912 74.041 31.176 ;
     RECT  73.897 32.16 74.099 95.448 ;
     RECT  73.715 96.48 74.099 97.176 ;
     RECT  73.505 0.096 74.185 23.592 ;
     RECT  74.041 24.624 74.185 31.176 ;
     RECT  74.099 32.16 74.185 33.624 ;
     RECT  74.099 34.608 74.387 95.448 ;
     RECT  74.185 0.096 74.585 33.624 ;
     RECT  74.585 0.096 74.657 9.576 ;
     RECT  74.387 34.608 74.765 85.512 ;
     RECT  74.387 86.496 75.109 95.448 ;
     RECT  74.099 96.624 75.109 97.176 ;
     RECT  74.765 34.608 75.125 43.128 ;
     RECT  74.765 44.112 75.409 85.512 ;
     RECT  75.109 86.496 75.409 97.176 ;
     RECT  74.657 0.096 75.781 9.528 ;
     RECT  74.585 10.608 75.781 33.624 ;
     RECT  75.409 44.112 75.985 97.176 ;
     RECT  75.781 0.096 76.069 33.624 ;
     RECT  75.125 34.608 76.069 43.08 ;
     RECT  76.069 0.096 76.133 43.08 ;
     RECT  76.133 0.096 76.385 33.096 ;
     RECT  76.385 0.096 76.741 32.328 ;
     RECT  76.133 34.608 76.777 43.08 ;
     RECT  75.985 44.064 76.777 97.176 ;
     RECT  76.777 34.608 77.033 97.176 ;
     RECT  77.033 34.608 77.365 97.128 ;
     RECT  77.365 34.176 77.413 97.128 ;
     RECT  76.741 0.048 77.533 32.328 ;
     RECT  77.413 33.6 77.533 97.128 ;
     RECT  77.533 0.048 78.304 97.128 ;
     RECT  78.304 0.048 78.563 33.144 ;
     RECT  78.304 34.176 78.649 97.128 ;
     RECT  78.563 24.96 79.441 33.144 ;
     RECT  78.649 34.176 79.441 97.176 ;
     RECT  78.563 0.048 79.717 23.976 ;
     RECT  79.441 24.96 79.717 97.176 ;
     RECT  79.717 0.048 80.777 97.176 ;
     RECT  80.777 59.04 80.921 97.176 ;
     RECT  80.921 64.944 80.963 97.176 ;
     RECT  80.963 64.992 81.065 84.696 ;
     RECT  80.921 59.04 81.173 63.816 ;
     RECT  81.173 59.04 81.281 63.192 ;
     RECT  80.777 0.048 81.817 57.864 ;
     RECT  81.281 59.04 81.817 61.512 ;
     RECT  81.817 0.048 81.929 61.512 ;
     RECT  81.065 64.992 82.033 82.152 ;
     RECT  80.963 85.776 82.037 97.176 ;
     RECT  81.929 48.192 82.285 61.512 ;
     RECT  81.065 83.232 82.285 84.696 ;
     RECT  82.037 85.776 82.285 91.128 ;
     RECT  82.285 48.192 82.357 61.608 ;
     RECT  81.281 62.736 82.357 63.192 ;
     RECT  82.033 64.992 82.357 82.2 ;
     RECT  82.285 83.232 82.357 91.128 ;
     RECT  81.929 0.048 82.897 47.208 ;
     RECT  82.357 48.192 82.897 91.128 ;
     RECT  82.037 92.256 83.185 97.176 ;
     RECT  82.897 0.048 83.408 91.128 ;
     RECT  83.185 92.16 83.408 97.176 ;
     RECT  83.408 0.048 83.704 97.176 ;
     RECT  83.704 40.08 83.945 90.936 ;
     RECT  83.704 0.048 84.697 39.096 ;
     RECT  83.945 40.08 84.697 60.984 ;
     RECT  83.945 62.208 84.737 90.936 ;
     RECT  84.737 88.608 84.877 90.936 ;
     RECT  84.697 0.048 84.881 60.984 ;
     RECT  84.737 62.208 84.881 87.096 ;
     RECT  84.877 88.608 84.913 91.08 ;
     RECT  83.704 92.16 84.913 97.176 ;
     RECT  84.881 62.208 84.917 84.648 ;
     RECT  84.881 0.048 84.995 60.936 ;
     RECT  84.995 0.048 85.025 34.44 ;
     RECT  84.913 88.608 85.043 97.176 ;
     RECT  85.043 88.608 85.091 95.688 ;
     RECT  85.091 88.608 85.523 95.64 ;
     RECT  84.995 35.424 85.529 60.936 ;
     RECT  84.881 85.68 85.529 87.096 ;
     RECT  85.529 35.424 85.565 55.656 ;
     RECT  85.043 97.104 85.601 97.176 ;
     RECT  85.529 56.64 85.745 60.936 ;
     RECT  85.529 85.92 85.777 87.096 ;
     RECT  85.025 0.048 85.889 34.392 ;
     RECT  85.601 97.104 85.925 97.128 ;
     RECT  85.565 35.424 85.961 55.224 ;
     RECT  85.961 45.6 86.003 55.224 ;
     RECT  86.003 45.648 86.099 55.224 ;
     RECT  85.745 56.784 86.209 60.936 ;
     RECT  84.917 62.208 86.209 84.408 ;
     RECT  85.523 88.608 86.209 95.448 ;
     RECT  85.889 0.048 86.249 34.344 ;
     RECT  86.209 88.416 86.281 95.448 ;
     RECT  86.209 56.784 86.285 84.408 ;
     RECT  86.285 64.944 86.317 84.408 ;
     RECT  86.099 45.744 86.393 55.224 ;
     RECT  86.317 64.944 86.393 84.888 ;
     RECT  85.961 35.424 86.581 44.616 ;
     RECT  86.393 66.192 86.605 84.888 ;
     RECT  85.777 85.92 86.605 87.24 ;
     RECT  86.249 6.816 86.681 34.344 ;
     RECT  86.281 88.368 86.681 95.448 ;
     RECT  86.393 46.08 86.713 55.224 ;
     RECT  86.285 56.784 86.713 63.912 ;
     RECT  86.605 66.192 86.713 87.24 ;
     RECT  86.681 88.368 86.713 94.68 ;
     RECT  86.713 66.192 86.867 94.68 ;
     RECT  86.867 84.816 86.897 94.68 ;
     RECT  86.681 6.816 87.005 32.328 ;
     RECT  86.681 33.312 87.037 34.344 ;
     RECT  86.581 35.376 87.037 44.616 ;
     RECT  86.713 46.08 87.203 63.912 ;
     RECT  86.897 84.816 87.251 87.24 ;
     RECT  87.203 46.08 87.293 55.224 ;
     RECT  87.203 56.592 87.329 63.912 ;
     RECT  86.867 66.192 87.437 83.784 ;
     RECT  87.293 46.08 87.469 54.792 ;
     RECT  87.469 45.84 87.473 54.792 ;
     RECT  87.329 59.28 87.473 63.912 ;
     RECT  86.249 0.048 87.505 5.736 ;
     RECT  87.251 86.592 87.581 87.24 ;
     RECT  86.897 88.368 87.587 91.224 ;
     RECT  86.393 64.944 87.685 65.016 ;
     RECT  87.437 66.192 87.685 77.928 ;
     RECT  87.685 64.944 87.689 77.928 ;
     RECT  87.005 7.344 87.721 32.328 ;
     RECT  87.037 33.312 87.721 44.616 ;
     RECT  87.587 88.368 87.725 89.928 ;
     RECT  87.721 7.344 87.865 44.616 ;
     RECT  87.473 45.84 87.865 53.592 ;
     RECT  87.437 78.912 87.973 83.784 ;
     RECT  87.251 84.816 87.973 85.416 ;
     RECT  87.505 0.048 88.021 6.312 ;
     RECT  87.865 7.344 88.021 53.592 ;
     RECT  88.021 0.048 88.337 53.592 ;
     RECT  87.689 65.376 88.477 77.928 ;
     RECT  87.973 78.912 88.477 85.416 ;
     RECT  87.473 54.768 88.549 54.792 ;
     RECT  86.897 92.4 88.549 94.392 ;
     RECT  87.473 60.096 88.585 63.912 ;
     RECT  87.725 88.464 88.585 89.928 ;
     RECT  87.587 91.056 88.585 91.224 ;
     RECT  88.549 92.4 88.585 94.584 ;
     RECT  88.477 65.376 88.621 85.416 ;
     RECT  87.581 86.592 88.621 87.048 ;
     RECT  88.585 59.808 88.645 63.912 ;
     RECT  88.621 65.376 88.693 87.048 ;
     RECT  87.329 56.592 88.729 58.104 ;
     RECT  88.645 59.28 88.729 63.912 ;
     RECT  88.337 0.096 88.808 53.592 ;
     RECT  88.549 54.768 88.808 54.984 ;
     RECT  88.729 56.592 88.808 63.912 ;
     RECT  88.693 65.376 88.808 87.288 ;
     RECT  88.585 88.464 88.808 94.584 ;
     RECT  88.808 0.096 88.912 95.052 ;
     RECT  88.912 0.096 89.104 94.782 ;
     RECT  89.104 0.096 89.165 62.184 ;
     RECT  89.165 0.096 89.201 62.136 ;
     RECT  89.201 7.344 89.219 62.136 ;
     RECT  89.104 66.288 89.219 89.496 ;
     RECT  89.219 66.288 89.345 87.288 ;
     RECT  89.219 7.344 89.381 34.776 ;
     RECT  89.104 93.792 89.417 94.68 ;
     RECT  89.381 24.288 89.489 34.776 ;
     RECT  89.381 7.344 89.525 23.304 ;
     RECT  89.104 90.624 89.561 92.76 ;
     RECT  89.345 66.288 89.597 86.76 ;
     RECT  89.104 63.504 89.705 63.816 ;
     RECT  89.597 74.4 89.741 86.76 ;
     RECT  89.219 36.048 90.065 62.136 ;
     RECT  89.597 66.288 90.209 73.368 ;
     RECT  89.417 93.84 90.245 94.68 ;
     RECT  89.201 0.096 90.349 6.36 ;
     RECT  89.525 7.344 90.349 23.112 ;
     RECT  90.245 93.84 90.421 94.44 ;
     RECT  89.489 33.264 90.469 34.776 ;
     RECT  90.065 36.048 90.469 57.576 ;
     RECT  89.741 75.696 90.469 86.76 ;
     RECT  89.489 24.288 90.493 32.088 ;
     RECT  90.469 33.264 90.493 57.576 ;
     RECT  89.219 88.608 90.529 89.496 ;
     RECT  90.493 24.288 90.533 57.576 ;
     RECT  90.469 75.696 90.533 87.288 ;
     RECT  90.209 66.528 90.565 73.368 ;
     RECT  89.741 74.4 90.565 74.712 ;
     RECT  90.533 55.92 90.569 57.576 ;
     RECT  90.421 93.792 90.569 94.44 ;
     RECT  90.533 24.288 90.605 45.624 ;
     RECT  90.533 75.696 90.605 86.952 ;
     RECT  90.605 24.288 90.613 34.824 ;
     RECT  90.613 24.24 90.637 34.824 ;
     RECT  89.705 63.504 90.637 63.576 ;
     RECT  89.561 90.624 90.637 92.424 ;
     RECT  89.104 64.896 90.673 65.16 ;
     RECT  90.605 82.32 90.677 86.952 ;
     RECT  90.065 58.704 90.745 62.136 ;
     RECT  90.637 63.312 90.745 63.576 ;
     RECT  90.565 66.528 90.745 74.712 ;
     RECT  90.605 75.696 90.745 81.336 ;
     RECT  90.349 0.096 90.803 23.112 ;
     RECT  90.745 58.704 90.805 63.576 ;
     RECT  90.605 35.904 90.821 45.624 ;
     RECT  90.803 16.992 90.853 23.112 ;
     RECT  90.637 24.144 90.853 34.824 ;
     RECT  90.529 88.512 90.889 89.496 ;
     RECT  90.677 86.592 90.899 86.952 ;
     RECT  90.637 90.624 90.965 92.904 ;
     RECT  90.805 58.704 91.001 63.816 ;
     RECT  90.889 88.512 91.033 89.544 ;
     RECT  90.803 0.096 91.073 16.008 ;
     RECT  90.853 16.992 91.139 34.824 ;
     RECT  90.673 64.896 91.189 65.448 ;
     RECT  90.745 66.528 91.189 81.336 ;
     RECT  90.569 93.936 91.217 94.44 ;
     RECT  91.033 88.464 91.237 89.544 ;
     RECT  90.965 90.624 91.237 92.232 ;
     RECT  91.217 94.032 91.253 94.44 ;
     RECT  91.189 64.896 91.283 81.336 ;
     RECT  91.283 64.896 91.289 75.72 ;
     RECT  91.289 64.896 91.331 65.688 ;
     RECT  91.237 88.464 91.361 92.232 ;
     RECT  91.361 88.464 91.429 89.064 ;
     RECT  91.001 63.312 91.469 63.816 ;
     RECT  91.289 66.672 91.475 75.72 ;
     RECT  91.475 66.768 91.505 75.72 ;
     RECT  91.429 88.368 91.523 89.064 ;
     RECT  91.469 63.552 91.537 63.816 ;
     RECT  91.331 64.896 91.537 65.448 ;
     RECT  91.523 88.56 91.541 89.064 ;
     RECT  91.139 17.04 91.571 34.824 ;
     RECT  91.541 88.56 91.571 88.968 ;
     RECT  90.569 55.968 91.573 57.576 ;
     RECT  91.001 58.704 91.573 62.136 ;
     RECT  91.283 76.896 91.573 81.336 ;
     RECT  90.677 82.32 91.573 85.512 ;
     RECT  90.821 35.904 91.613 45.528 ;
     RECT  91.505 66.768 91.613 68.472 ;
     RECT  91.571 88.896 91.613 88.968 ;
     RECT  91.573 76.896 91.619 85.512 ;
     RECT  91.253 94.032 91.619 94.056 ;
     RECT  91.619 76.944 91.649 85.512 ;
     RECT  91.571 18.672 91.681 34.824 ;
     RECT  91.681 18.672 91.721 35.352 ;
     RECT  91.613 36.432 91.721 45.528 ;
     RECT  91.649 76.944 91.721 84.84 ;
     RECT  91.721 76.944 91.793 82.152 ;
     RECT  91.361 90.624 91.865 92.232 ;
     RECT  91.865 92.208 91.901 92.232 ;
     RECT  91.613 66.768 91.973 68.424 ;
     RECT  91.073 0.096 92.003 13.704 ;
     RECT  91.505 69.456 92.003 75.72 ;
     RECT  90.533 46.8 92.005 54.936 ;
     RECT  91.573 55.968 92.005 62.136 ;
     RECT  90.899 86.592 92.005 86.616 ;
     RECT  91.973 66.768 92.045 66.84 ;
     RECT  91.973 67.968 92.045 68.424 ;
     RECT  91.721 83.232 92.045 84.84 ;
     RECT  92.005 85.824 92.051 86.616 ;
     RECT  91.537 63.552 92.081 65.448 ;
     RECT  91.721 18.672 92.099 21.672 ;
     RECT  92.003 10.704 92.147 13.704 ;
     RECT  92.147 10.8 92.153 13.704 ;
     RECT  92.081 63.552 92.153 65.4 ;
     RECT  92.005 46.464 92.225 62.136 ;
     RECT  91.793 76.944 92.261 78.024 ;
     RECT  92.045 83.616 92.261 84.84 ;
     RECT  92.153 10.848 92.293 13.704 ;
     RECT  91.073 14.784 92.293 16.008 ;
     RECT  91.571 17.04 92.293 17.688 ;
     RECT  91.865 90.624 92.297 91.224 ;
     RECT  92.297 90.624 92.365 90.648 ;
     RECT  92.003 0.096 92.369 9.72 ;
     RECT  92.003 69.456 92.369 73.8 ;
     RECT  91.793 79.2 92.369 82.152 ;
     RECT  91.721 36.432 92.387 45.048 ;
     RECT  92.003 74.784 92.405 75.72 ;
     RECT  92.225 46.464 92.441 57 ;
     RECT  92.051 86.592 92.441 86.616 ;
     RECT  92.365 89.952 92.441 90.648 ;
     RECT  92.045 66.768 92.473 66.792 ;
     RECT  92.153 63.792 92.477 65.4 ;
     RECT  92.261 77.904 92.477 78.024 ;
     RECT  92.369 1.728 92.549 9.72 ;
     RECT  92.441 46.464 92.549 47.496 ;
     RECT  92.441 48.864 92.549 57 ;
     RECT  92.369 79.2 92.549 82.104 ;
     RECT  92.549 81.648 92.579 82.104 ;
     RECT  92.045 68.064 92.617 68.424 ;
     RECT  92.369 69.456 92.617 73.56 ;
     RECT  92.405 75.264 92.617 75.72 ;
     RECT  92.549 48.864 92.621 52.776 ;
     RECT  92.387 36.432 92.627 40.584 ;
     RECT  91.721 22.656 92.657 35.352 ;
     RECT  92.549 54.048 92.675 57 ;
     RECT  92.225 57.984 92.675 62.136 ;
     RECT  92.387 41.76 92.689 45.048 ;
     RECT  92.675 54.048 92.693 55.416 ;
     RECT  92.627 36.432 92.725 38.808 ;
     RECT  92.617 75.264 92.725 75.912 ;
     RECT  92.549 2.256 92.729 9.72 ;
     RECT  92.621 48.864 92.729 50.664 ;
     RECT  92.729 2.256 92.765 8.52 ;
     RECT  92.765 2.256 92.771 8.232 ;
     RECT  92.293 10.848 92.801 17.688 ;
     RECT  92.657 22.656 92.801 34.872 ;
     RECT  92.725 35.904 92.801 38.808 ;
     RECT  92.549 46.608 92.801 47.496 ;
     RECT  92.477 78 92.821 78.024 ;
     RECT  92.549 79.2 92.821 80.04 ;
     RECT  92.621 51.792 92.837 52.776 ;
     RECT  92.801 22.656 92.867 33.864 ;
     RECT  92.801 35.904 92.873 37.992 ;
     RECT  92.675 56.544 92.873 57 ;
     RECT  92.675 60.768 92.905 62.136 ;
     RECT  92.099 19.776 92.941 21.672 ;
     RECT  92.867 22.656 92.941 24.552 ;
     RECT  92.873 36.48 92.945 37.992 ;
     RECT  92.261 84.816 92.945 84.84 ;
     RECT  92.771 2.256 92.981 7.992 ;
     RECT  92.689 41.76 92.981 45.144 ;
     RECT  92.981 42.336 93.017 45.144 ;
     RECT  92.981 7.44 93.089 7.992 ;
     RECT  92.693 54.048 93.107 55.272 ;
     RECT  92.873 56.544 93.107 56.712 ;
     RECT  92.099 18.672 93.157 18.696 ;
     RECT  92.941 19.776 93.157 24.552 ;
     RECT  93.017 42.336 93.197 43.176 ;
     RECT  93.017 44.352 93.197 45.144 ;
     RECT  92.675 57.984 93.203 59.784 ;
     RECT  92.905 60.768 93.229 62.424 ;
     RECT  92.801 10.848 93.233 10.872 ;
     RECT  92.729 49.872 93.233 50.664 ;
     RECT  93.107 54.336 93.233 55.272 ;
     RECT  93.203 58.08 93.233 59.784 ;
     RECT  92.729 9.648 93.253 9.72 ;
     RECT  92.801 12 93.253 17.688 ;
     RECT  93.157 18.672 93.253 24.552 ;
     RECT  92.477 65.136 93.265 65.4 ;
     RECT  92.261 83.616 93.265 83.736 ;
     RECT  92.617 68.064 93.445 73.56 ;
     RECT  92.725 75.264 93.445 76.056 ;
     RECT  92.441 89.952 93.445 89.976 ;
     RECT  92.801 46.752 93.481 47.496 ;
     RECT  92.821 78 93.481 80.04 ;
     RECT  92.477 63.792 93.493 64.152 ;
     RECT  93.265 65.136 93.493 65.544 ;
     RECT  92.369 0.096 93.517 0.6 ;
     RECT  93.229 60.768 93.541 62.616 ;
     RECT  93.493 63.792 93.541 65.544 ;
     RECT  92.579 81.648 93.589 81.864 ;
     RECT  93.589 81.312 93.625 81.864 ;
     RECT  93.445 68.064 93.661 76.056 ;
     RECT  93.481 77.04 93.661 80.04 ;
     RECT  92.545 87.792 93.661 87.816 ;
     RECT  93.661 86.88 93.781 87.816 ;
     RECT  91.613 88.896 93.781 88.92 ;
     RECT  93.517 0.096 93.805 1.176 ;
     RECT  92.981 2.256 93.805 4.584 ;
     RECT  92.837 52.128 93.805 52.776 ;
     RECT  92.867 26.016 93.829 33.864 ;
     RECT  93.829 26.016 93.877 34.632 ;
     RECT  93.661 68.064 93.877 80.04 ;
     RECT  93.625 81.312 93.877 82.632 ;
     RECT  93.877 25.968 93.949 34.632 ;
     RECT  93.805 0.096 94.133 4.584 ;
     RECT  94.133 1.152 94.208 4.584 ;
     RECT  92.981 5.712 94.208 5.736 ;
     RECT  93.089 7.44 94.208 7.464 ;
     RECT  93.253 9.648 94.208 10.776 ;
     RECT  93.253 12 94.208 24.552 ;
     RECT  93.949 25.872 94.208 34.632 ;
     RECT  92.945 36.48 94.208 37.656 ;
     RECT  92.627 40.128 94.208 40.584 ;
     RECT  93.197 42.336 94.208 42.792 ;
     RECT  93.197 44.64 94.208 45.144 ;
     RECT  93.481 46.752 94.208 48.216 ;
     RECT  93.233 49.872 94.208 50.616 ;
     RECT  93.805 52.128 94.208 53.064 ;
     RECT  93.233 54.336 94.208 55.176 ;
     RECT  93.107 56.688 94.208 56.712 ;
     RECT  93.233 58.08 94.208 59.256 ;
     RECT  93.541 60.768 94.208 65.544 ;
     RECT  92.473 66.672 94.208 66.792 ;
     RECT  93.877 68.064 94.208 82.632 ;
     RECT  93.265 83.616 94.208 84.648 ;
     RECT  93.781 86.88 94.208 88.92 ;
     RECT  93.445 89.952 94.208 90.072 ;
     RECT  94.208 1.152 94.312 95.052 ;
     RECT  94.133 0.096 94.385 0.168 ;
     RECT  94.312 1.152 94.504 94.782 ;
     RECT  94.504 1.152 94.565 2.328 ;
     RECT  94.565 2.016 94.601 2.328 ;
     RECT  94.385 0.096 94.673 0.12 ;
     RECT  94.601 2.304 94.745 2.328 ;
     RECT  94.504 20.112 94.817 20.136 ;
     RECT  94.504 31.392 94.853 31.416 ;
     RECT  94.504 26.88 94.925 26.904 ;
     RECT  94.504 27.984 94.925 28.008 ;
    LAYER M5 ;
     RECT  54.48 0.016 76.68 0.037 ;
     RECT  22.992 0.016 35.208 0.085 ;
     RECT  45.264 0.016 51.336 0.131 ;
     RECT  83.664 0.016 94.728 0.179 ;
     RECT  54.48 0.037 76.776 0.181 ;
     RECT  22.992 0.085 35.64 0.229 ;
     RECT  54.48 0.181 76.872 0.323 ;
     RECT  22.992 0.229 35.976 0.325 ;
     RECT  45.264 0.131 51.24 0.899 ;
     RECT  54.48 0.323 76.488 1.139 ;
     RECT  22.992 0.325 36.168 1.187 ;
     RECT  54.48 1.139 69.096 1.187 ;
     RECT  70.416 1.139 76.488 1.427 ;
     RECT  74.064 1.427 76.488 1.523 ;
     RECT  23.28 1.187 30.024 1.763 ;
     RECT  31.152 1.187 36.168 1.763 ;
     RECT  70.416 1.427 72.912 1.763 ;
     RECT  74.064 1.523 76.2 1.763 ;
     RECT  83.76 0.179 94.728 1.763 ;
     RECT  54.48 1.187 69 1.811 ;
     RECT  74.16 1.763 76.2 1.811 ;
     RECT  83.76 1.763 85.512 1.811 ;
     RECT  87.504 1.763 94.728 1.811 ;
     RECT  87.888 1.811 94.728 1.859 ;
     RECT  87.984 1.859 94.728 1.907 ;
     RECT  70.8 1.763 72.912 2.003 ;
     RECT  74.544 1.811 74.568 2.051 ;
     RECT  83.76 1.811 85.368 2.053 ;
     RECT  14.208 2.101 14.232 2.137 ;
     RECT  41.088 0.181 41.112 2.137 ;
     RECT  2.4 2.137 2.52 2.151 ;
     RECT  7.8 2.137 7.92 2.151 ;
     RECT  18.6 2.137 18.72 2.151 ;
     RECT  45.36 0.899 51.24 2.151 ;
     RECT  78 2.137 78.12 2.151 ;
     RECT  75.696 1.811 76.008 2.195 ;
     RECT  21.168 2.149 21.192 2.197 ;
     RECT  15.264 2.053 15.288 2.245 ;
     RECT  17.472 2.197 17.496 2.245 ;
     RECT  23.28 1.763 27.432 2.245 ;
     RECT  54.48 1.811 68.808 2.245 ;
     RECT  78 2.151 78.312 2.245 ;
     RECT  21.072 2.197 21.192 2.293 ;
     RECT  33.456 1.763 36.168 2.293 ;
     RECT  52.848 2.245 52.872 2.293 ;
     RECT  88.704 1.907 94.728 2.339 ;
     RECT  20.976 2.293 21.192 2.341 ;
     RECT  22.56 2.245 27.432 2.387 ;
     RECT  20.976 2.341 21.432 2.437 ;
     RECT  16.752 2.245 17.496 2.485 ;
     RECT  18.6 2.151 18.912 2.485 ;
     RECT  20.976 2.437 21.528 2.485 ;
     RECT  22.56 2.387 27.336 2.485 ;
     RECT  54.144 2.245 68.808 2.485 ;
     RECT  52.416 2.293 52.872 2.531 ;
     RECT  15.264 2.245 15.528 2.533 ;
     RECT  16.752 2.485 18.912 2.533 ;
     RECT  40.2 2.137 41.112 2.533 ;
     RECT  19.92 2.245 19.944 2.581 ;
     RECT  20.976 2.485 27.336 2.581 ;
     RECT  40.08 2.533 41.112 2.581 ;
     RECT  31.152 1.763 32.136 2.629 ;
     RECT  78 2.245 78.888 2.629 ;
     RECT  19.92 2.581 27.336 2.675 ;
     RECT  37.968 0.133 37.992 2.677 ;
     RECT  37.728 2.677 37.992 2.725 ;
     RECT  52.512 2.531 52.872 2.725 ;
     RECT  45.36 2.151 51.312 2.821 ;
     RECT  83.232 2.053 85.368 2.821 ;
     RECT  28.752 1.763 29.712 2.867 ;
     RECT  10.944 2.533 10.968 2.915 ;
     RECT  19.92 2.675 21.528 2.915 ;
     RECT  45.312 2.821 51.312 3.013 ;
     RECT  53.952 2.485 68.808 3.061 ;
     RECT  28.8 2.867 29.712 3.157 ;
     RECT  30.816 2.629 32.136 3.157 ;
     RECT  70.8 2.003 71.4 3.157 ;
     RECT  83.232 2.821 85.944 3.157 ;
     RECT  74.592 2.821 74.616 3.205 ;
     RECT  80.88 2.245 80.904 3.205 ;
     RECT  83.232 3.157 85.992 3.205 ;
     RECT  52.512 2.725 52.968 3.301 ;
     RECT  53.952 3.061 68.952 3.301 ;
     RECT  69.984 3.157 71.4 3.301 ;
     RECT  74.4 3.205 74.616 3.301 ;
     RECT  43.44 2.485 43.464 3.349 ;
     RECT  44.448 3.013 51.312 3.349 ;
     RECT  72.6 2.003 72.912 3.349 ;
     RECT  74.112 3.301 74.616 3.349 ;
     RECT  75.696 2.195 75.912 3.349 ;
     RECT  80.88 3.205 81.672 3.349 ;
     RECT  87.216 2.821 87.24 3.349 ;
     RECT  88.704 2.339 94.512 3.349 ;
     RECT  13.2 2.137 14.232 3.397 ;
     RECT  15.264 2.533 18.912 3.397 ;
     RECT  52.512 3.301 71.4 3.397 ;
     RECT  72.6 3.349 74.616 3.397 ;
     RECT  75.696 3.349 76.728 3.397 ;
     RECT  80.4 3.349 81.672 3.397 ;
     RECT  80.4 3.397 81.72 3.443 ;
     RECT  7.8 2.151 8.112 3.733 ;
     RECT  9.504 2.821 9.528 3.733 ;
     RECT  80.4 3.443 80.472 3.829 ;
     RECT  33.456 2.293 36.456 3.877 ;
     RECT  77.856 2.629 78.888 3.877 ;
     RECT  79.968 3.829 80.472 3.877 ;
     RECT  82.8 3.205 85.992 3.877 ;
     RECT  7.8 3.733 10.488 3.925 ;
     RECT  11.808 3.829 11.832 3.925 ;
     RECT  28.8 3.157 32.136 3.925 ;
     RECT  33.408 3.877 36.456 3.925 ;
     RECT  13.2 3.397 18.912 4.117 ;
     RECT  42.288 3.397 42.312 4.117 ;
     RECT  43.44 3.349 51.312 4.117 ;
     RECT  42.288 4.117 51.312 4.213 ;
     RECT  82.8 3.877 86.04 4.261 ;
     RECT  87.216 3.349 94.512 4.261 ;
     RECT  28.8 3.925 36.456 4.309 ;
     RECT  37.584 2.725 37.992 4.309 ;
     RECT  7.8 3.925 11.832 4.403 ;
     RECT  52.512 3.397 76.728 4.403 ;
     RECT  7.8 4.403 9.72 4.453 ;
     RECT  22.56 2.675 27.336 4.453 ;
     RECT  28.8 4.309 37.992 4.453 ;
     RECT  39.984 2.581 41.112 4.453 ;
     RECT  42.288 4.213 51.432 4.741 ;
     RECT  52.512 4.403 71.4 4.741 ;
     RECT  22.56 4.453 37.992 4.933 ;
     RECT  39.6 4.453 41.112 4.933 ;
     RECT  77.856 3.877 80.472 5.027 ;
     RECT  72.6 4.403 76.728 5.077 ;
     RECT  77.856 5.027 80.424 5.077 ;
     RECT  42.288 4.741 71.4 5.125 ;
     RECT  7.44 4.453 9.72 5.171 ;
     RECT  42.192 5.125 71.4 5.171 ;
     RECT  13.2 4.117 19.176 5.461 ;
     RECT  10.944 4.403 11.832 5.701 ;
     RECT  22.56 4.933 41.112 5.747 ;
     RECT  72.6 5.077 80.424 5.747 ;
     RECT  13.104 5.461 19.176 5.749 ;
     RECT  20.496 2.915 21.528 5.749 ;
     RECT  37.152 5.747 41.112 5.891 ;
     RECT  72.6 5.747 79.704 6.277 ;
     RECT  7.632 5.171 9.72 6.323 ;
     RECT  10.848 5.701 11.832 6.323 ;
     RECT  52.32 5.171 71.4 6.325 ;
     RECT  72.432 6.277 79.704 6.325 ;
     RECT  52.32 6.325 79.704 6.371 ;
     RECT  13.104 5.749 21.528 6.611 ;
     RECT  2.4 2.151 2.712 6.805 ;
     RECT  81.648 3.443 81.72 6.805 ;
     RECT  82.8 4.261 94.512 6.805 ;
     RECT  81.648 6.805 94.512 6.853 ;
     RECT  15.264 6.611 21.528 7.043 ;
     RECT  52.56 6.371 79.704 7.333 ;
     RECT  81.408 6.853 94.512 7.381 ;
     RECT  13.2 6.611 14.232 7.621 ;
     RECT  7.632 6.323 9.576 7.957 ;
     RECT  13.056 7.621 14.232 8.437 ;
     RECT  15.264 7.043 19.176 8.437 ;
     RECT  52.56 7.333 79.896 8.771 ;
     RECT  39.024 5.891 41.112 8.869 ;
     RECT  42.192 5.171 51.312 8.869 ;
     RECT  81.168 7.381 94.512 9.013 ;
     RECT  7.584 7.957 9.576 9.061 ;
     RECT  12.768 8.437 19.176 9.061 ;
     RECT  20.496 7.043 21.528 9.061 ;
     RECT  11.04 6.323 11.688 9.109 ;
     RECT  12.768 9.061 21.528 9.109 ;
     RECT  2.4 6.805 3.096 9.685 ;
     RECT  4.08 5.605 4.104 9.685 ;
     RECT  5.184 6.229 5.208 10.019 ;
     RECT  6.336 9.061 6.36 10.355 ;
     RECT  7.44 9.061 9.576 10.357 ;
     RECT  11.04 9.109 21.528 10.357 ;
     RECT  22.56 5.747 36.168 10.597 ;
     RECT  37.152 5.891 37.992 10.597 ;
     RECT  2.4 9.685 4.104 11.029 ;
     RECT  39.024 8.869 51.312 11.173 ;
     RECT  39.024 11.173 51.432 11.365 ;
     RECT  52.704 8.771 79.896 11.365 ;
     RECT  7.44 10.357 21.528 11.411 ;
     RECT  2.4 11.029 4.392 11.413 ;
     RECT  7.44 11.411 19.368 11.939 ;
     RECT  39.024 11.365 79.896 11.939 ;
     RECT  22.56 10.597 37.992 11.941 ;
     RECT  39.024 11.939 41.112 11.941 ;
     RECT  7.488 11.939 19.176 12.515 ;
     RECT  22.56 11.941 41.112 13.043 ;
     RECT  28.08 13.043 41.112 13.139 ;
     RECT  37.152 13.139 41.112 13.283 ;
     RECT  7.488 12.515 19.032 13.381 ;
     RECT  42.288 11.939 79.896 13.573 ;
     RECT  80.976 9.013 94.512 13.573 ;
     RECT  42.288 13.573 94.512 13.763 ;
     RECT  37.536 13.283 41.112 13.907 ;
     RECT  6.288 10.501 6.312 14.005 ;
     RECT  7.44 13.381 19.032 14.101 ;
     RECT  20.592 11.411 21.528 14.101 ;
     RECT  37.584 13.907 41.112 14.341 ;
     RECT  42.288 13.763 53.928 14.341 ;
     RECT  5.424 14.005 6.312 14.389 ;
     RECT  7.44 14.101 21.528 14.389 ;
     RECT  37.584 14.341 53.928 14.725 ;
     RECT  54.912 13.763 94.512 14.725 ;
     RECT  5.424 14.389 21.528 14.819 ;
     RECT  28.08 13.139 36.168 15.061 ;
     RECT  37.584 14.725 94.512 15.061 ;
     RECT  7.44 14.819 21.528 15.443 ;
     RECT  7.44 15.443 19.32 15.779 ;
     RECT  5.424 14.819 6.312 16.595 ;
     RECT  20.4 15.443 21.528 16.645 ;
     RECT  28.08 15.061 94.512 16.835 ;
     RECT  2.304 11.413 4.392 16.883 ;
     RECT  28.08 16.835 86.664 17.075 ;
     RECT  37.968 17.075 86.664 17.219 ;
     RECT  87.744 16.835 94.512 17.219 ;
     RECT  7.488 15.779 19.32 17.269 ;
     RECT  87.792 17.219 94.512 17.363 ;
     RECT  22.56 13.043 27.096 17.653 ;
     RECT  28.08 17.075 36.168 17.653 ;
     RECT  7.44 17.269 19.32 17.699 ;
     RECT  7.488 17.699 19.32 17.797 ;
     RECT  20.304 16.645 21.528 17.797 ;
     RECT  7.488 17.797 21.528 17.845 ;
     RECT  22.56 17.653 36.168 17.845 ;
     RECT  37.968 17.219 86.52 18.181 ;
     RECT  6.288 16.595 6.312 18.275 ;
     RECT  7.488 17.845 36.168 18.611 ;
     RECT  37.92 18.181 86.52 18.853 ;
     RECT  87.888 17.363 94.512 18.853 ;
     RECT  37.92 18.853 94.512 18.997 ;
     RECT  7.488 18.611 11.544 19.283 ;
     RECT  12.768 18.611 36.168 19.427 ;
     RECT  2.4 16.883 4.392 19.957 ;
     RECT  37.248 18.997 94.512 20.003 ;
     RECT  12.768 19.427 26.664 20.485 ;
     RECT  28.032 19.427 36.168 20.485 ;
     RECT  2.4 19.957 4.536 20.819 ;
     RECT  12.768 20.485 36.168 21.683 ;
     RECT  27.792 21.683 36.168 21.877 ;
     RECT  37.248 20.003 58.536 21.877 ;
     RECT  2.4 20.819 4.488 21.923 ;
     RECT  27.792 21.877 58.536 21.971 ;
     RECT  27.792 21.971 58.44 22.451 ;
     RECT  12.768 21.683 26.664 22.787 ;
     RECT  7.8 19.283 11.544 22.835 ;
     RECT  12.768 22.787 21.528 23.317 ;
     RECT  22.56 22.787 26.664 23.701 ;
     RECT  27.792 22.451 37.992 23.701 ;
     RECT  7.8 22.835 11.448 24.131 ;
     RECT  12.528 23.317 21.528 24.947 ;
     RECT  60 20.003 94.512 25.093 ;
     RECT  7.8 24.131 11.4 25.139 ;
     RECT  39.024 22.451 58.44 25.139 ;
     RECT  52.8 25.139 58.44 25.667 ;
     RECT  59.952 25.093 94.512 25.955 ;
     RECT  22.56 23.701 37.992 26.003 ;
     RECT  7.8 25.139 11.352 26.243 ;
     RECT  52.8 25.667 58.344 26.291 ;
     RECT  12.768 24.947 21.528 26.339 ;
     RECT  27.792 26.003 37.992 26.339 ;
     RECT  7.8 26.243 9.72 26.867 ;
     RECT  12.768 26.339 16.776 27.301 ;
     RECT  2.4 21.923 4.344 27.349 ;
     RECT  7.8 26.867 8.76 27.395 ;
     RECT  10.992 26.243 11.352 27.395 ;
     RECT  11.088 27.395 11.352 27.397 ;
     RECT  12.528 27.301 16.776 27.397 ;
     RECT  11.088 27.397 16.776 27.635 ;
     RECT  60.096 25.955 94.512 27.731 ;
     RECT  2.304 27.349 4.344 27.875 ;
     RECT  52.8 26.291 58.2 27.877 ;
     RECT  60.096 27.731 81.192 27.971 ;
     RECT  27.792 26.339 36.312 28.115 ;
     RECT  37.344 26.339 37.992 28.453 ;
     RECT  39.024 25.139 51.816 28.453 ;
     RECT  52.8 27.877 58.488 28.453 ;
     RECT  6.288 28.645 6.312 28.787 ;
     RECT  2.304 27.875 4.2 28.931 ;
     RECT  11.136 27.635 16.776 29.027 ;
     RECT  0.144 29.221 0.168 29.317 ;
     RECT  2.4 28.931 4.2 29.365 ;
     RECT  2.4 29.365 4.536 29.411 ;
     RECT  18.096 26.339 21.528 29.461 ;
     RECT  22.56 26.003 26.664 29.461 ;
     RECT  60.096 27.971 68.712 29.557 ;
     RECT  69.792 27.971 76.152 29.557 ;
     RECT  37.344 28.453 51.816 29.605 ;
     RECT  52.8 28.453 58.68 29.605 ;
     RECT  0.144 29.317 0.216 29.699 ;
     RECT  0.192 29.699 0.216 29.891 ;
     RECT  18.096 29.461 26.664 30.083 ;
     RECT  10.128 28.405 10.152 30.181 ;
     RECT  11.136 29.027 11.688 30.181 ;
     RECT  4.512 29.411 4.536 30.275 ;
     RECT  22.56 30.083 26.664 30.565 ;
     RECT  27.792 28.115 36.168 30.565 ;
     RECT  60.096 29.557 76.152 30.803 ;
     RECT  77.232 27.971 81.192 30.803 ;
     RECT  12.768 29.027 16.776 30.805 ;
     RECT  18.096 30.083 21.576 30.805 ;
     RECT  10.128 30.181 11.688 30.851 ;
     RECT  2.4 29.411 3.528 31.139 ;
     RECT  10.176 30.851 11.688 31.187 ;
     RECT  82.272 27.731 94.512 31.283 ;
     RECT  12.768 30.805 21.576 31.379 ;
     RECT  60.096 30.803 68.568 31.379 ;
     RECT  10.176 31.187 10.2 31.571 ;
     RECT  7.8 27.395 8.112 31.861 ;
     RECT  22.56 30.565 36.168 31.861 ;
     RECT  37.344 29.605 58.68 31.861 ;
     RECT  78 30.803 81.192 31.861 ;
     RECT  22.56 31.861 58.68 32.003 ;
     RECT  11.184 31.187 11.688 32.149 ;
     RECT  12.768 31.379 21.528 32.149 ;
     RECT  11.184 32.149 21.528 32.197 ;
     RECT  10.416 32.197 21.528 32.243 ;
     RECT  4.464 32.197 4.488 32.485 ;
     RECT  69.792 30.803 76.152 32.531 ;
     RECT  15.216 32.243 21.528 32.579 ;
     RECT  60.096 31.379 68.472 32.917 ;
     RECT  22.56 32.003 36.168 33.013 ;
     RECT  37.344 32.003 58.68 33.013 ;
     RECT  75.792 32.531 76.152 33.107 ;
     RECT  60.096 32.917 68.808 33.155 ;
     RECT  15.264 32.579 21.528 33.251 ;
     RECT  4.464 32.485 4.872 33.299 ;
     RECT  60.096 33.155 67.752 33.299 ;
     RECT  68.784 33.155 68.808 33.445 ;
     RECT  69.792 32.531 74.568 33.445 ;
     RECT  75.792 33.107 76.104 33.541 ;
     RECT  77.568 31.861 81.192 33.589 ;
     RECT  22.56 33.013 58.68 33.683 ;
     RECT  75.744 33.541 76.104 33.683 ;
     RECT  77.424 33.589 81.192 33.829 ;
     RECT  82.272 31.283 89.112 33.829 ;
     RECT  90.288 31.283 94.512 33.973 ;
     RECT  77.424 33.829 89.112 34.165 ;
     RECT  77.376 34.165 89.112 34.259 ;
     RECT  2.4 31.139 3.432 34.309 ;
     RECT  4.848 33.299 4.872 34.309 ;
     RECT  10.416 32.243 14.232 34.309 ;
     RECT  15.264 33.251 17.016 34.309 ;
     RECT  2.4 34.309 4.872 34.355 ;
     RECT  27.792 33.683 58.68 34.451 ;
     RECT  60.096 33.299 67.704 34.501 ;
     RECT  68.784 33.445 74.568 34.501 ;
     RECT  10.416 34.309 17.016 34.549 ;
     RECT  18.144 33.251 21.528 34.597 ;
     RECT  22.56 33.683 26.664 34.597 ;
     RECT  7.8 31.861 9.096 34.741 ;
     RECT  90.192 33.973 94.512 34.787 ;
     RECT  75.744 33.683 75.816 34.883 ;
     RECT  60.096 34.501 74.568 34.885 ;
     RECT  77.376 34.259 85.992 35.029 ;
     RECT  75.792 34.883 75.816 35.173 ;
     RECT  60.096 34.885 74.664 35.269 ;
     RECT  87.072 34.259 89.112 35.269 ;
     RECT  39.264 34.451 58.68 35.315 ;
     RECT  4.128 34.355 4.872 35.317 ;
     RECT  18.144 34.597 26.664 35.363 ;
     RECT  27.792 34.451 37.992 35.363 ;
     RECT  52.8 35.315 58.68 35.363 ;
     RECT  87.072 35.269 89.208 35.363 ;
     RECT  77.04 35.029 85.992 35.365 ;
     RECT  7.344 34.741 9.096 35.413 ;
     RECT  10.416 34.549 17.16 35.459 ;
     RECT  75.792 35.173 76.008 35.509 ;
     RECT  77.04 35.365 86.616 35.509 ;
     RECT  7.248 35.413 9.096 35.555 ;
     RECT  10.8 35.459 17.16 35.605 ;
     RECT  18.144 35.363 25.464 35.605 ;
     RECT  39.264 35.315 51.816 35.843 ;
     RECT  4.032 35.317 4.872 35.845 ;
     RECT  39.312 35.843 51.816 35.939 ;
     RECT  90.384 34.787 94.512 35.939 ;
     RECT  75.792 35.509 86.616 35.987 ;
     RECT  10.8 35.605 25.464 36.035 ;
     RECT  26.448 35.363 26.472 36.275 ;
     RECT  77.04 35.987 86.616 36.371 ;
     RECT  59.904 35.269 74.664 36.515 ;
     RECT  91.536 35.939 94.512 36.515 ;
     RECT  60.096 36.515 74.664 36.517 ;
     RECT  75.792 35.987 75.816 36.517 ;
     RECT  4.032 35.845 5.448 36.563 ;
     RECT  27.936 35.363 37.992 36.805 ;
     RECT  39.312 35.939 51.768 36.997 ;
     RECT  52.8 35.363 58.584 36.997 ;
     RECT  88.512 35.363 89.208 37.045 ;
     RECT  11.04 36.035 25.464 37.091 ;
     RECT  60.096 36.517 75.816 37.091 ;
     RECT  77.28 36.371 86.616 37.091 ;
     RECT  7.8 35.555 9.096 37.477 ;
     RECT  4.032 36.563 4.872 37.525 ;
     RECT  11.088 37.091 25.464 37.573 ;
     RECT  88.512 37.045 89.304 37.573 ;
     RECT  90.384 35.939 90.552 37.573 ;
     RECT  91.536 36.515 92.568 37.573 ;
     RECT  11.088 37.573 25.608 37.619 ;
     RECT  60.096 37.091 74.616 37.667 ;
     RECT  39.312 36.997 58.584 37.907 ;
     RECT  88.176 37.573 89.304 37.957 ;
     RECT  88.08 37.957 89.304 38.101 ;
     RECT  90.384 37.573 92.568 38.101 ;
     RECT  4.032 37.525 5.112 38.149 ;
     RECT  60.096 37.667 70.776 38.149 ;
     RECT  88.08 38.101 92.568 38.149 ;
     RECT  39.504 37.907 58.584 38.195 ;
     RECT  77.424 37.091 86.616 38.245 ;
     RECT  87.648 38.149 92.568 38.245 ;
     RECT  7.8 37.477 9.72 38.435 ;
     RECT  59.856 38.149 70.776 38.435 ;
     RECT  4.032 38.149 5.688 38.533 ;
     RECT  27.888 36.805 37.992 38.869 ;
     RECT  39.504 38.195 51.768 38.869 ;
     RECT  27.888 38.869 51.768 39.107 ;
     RECT  77.424 38.245 92.568 39.109 ;
     RECT  2.4 34.355 2.712 39.205 ;
     RECT  4.032 38.533 6.648 39.205 ;
     RECT  71.856 37.667 74.616 39.205 ;
     RECT  75.6 37.091 75.816 39.205 ;
     RECT  2.4 39.205 6.648 39.251 ;
     RECT  77.28 39.109 92.568 39.253 ;
     RECT  71.856 39.205 75.816 39.347 ;
     RECT  75.6 39.347 75.816 39.395 ;
     RECT  52.752 38.195 58.584 39.589 ;
     RECT  59.856 38.435 67.704 39.589 ;
     RECT  2.4 39.251 3.576 39.637 ;
     RECT  4.848 39.251 6.648 39.827 ;
     RECT  27.888 39.107 38.808 39.875 ;
     RECT  5.904 39.827 6.648 39.923 ;
     RECT  39.984 39.107 51.768 39.923 ;
     RECT  68.784 38.435 70.776 39.923 ;
     RECT  77.28 39.253 92.616 40.067 ;
     RECT  27.888 39.875 37.992 40.117 ;
     RECT  77.424 40.067 92.616 40.261 ;
     RECT  94.2 36.515 94.512 40.309 ;
     RECT  2.304 39.637 3.576 40.595 ;
     RECT  77.424 40.261 92.712 40.595 ;
     RECT  40.2 39.923 51.768 40.981 ;
     RECT  52.752 39.589 67.704 40.981 ;
     RECT  71.856 39.347 74.616 41.029 ;
     RECT  11.088 37.619 25.605 41.125 ;
     RECT  2.4 40.595 3.576 41.173 ;
     RECT  10.992 41.125 25.605 41.267 ;
     RECT  39.552 40.981 67.704 41.363 ;
     RECT  7.8 38.435 9.432 41.605 ;
     RECT  5.904 39.923 5.928 41.651 ;
     RECT  27.84 40.117 37.992 41.699 ;
     RECT  11.088 41.267 25.605 41.939 ;
     RECT  2.4 41.173 3.864 41.941 ;
     RECT  4.848 39.827 4.872 41.941 ;
     RECT  71.856 41.029 74.712 41.941 ;
     RECT  37.344 41.699 37.992 42.037 ;
     RECT  39.552 41.363 58.584 42.037 ;
     RECT  37.344 42.037 58.584 42.083 ;
     RECT  69.792 39.923 70.776 42.085 ;
     RECT  71.808 41.941 74.712 42.085 ;
     RECT  5.952 41.941 5.976 42.515 ;
     RECT  77.424 40.595 86.616 42.709 ;
     RECT  40.08 42.083 58.584 42.755 ;
     RECT  93.936 40.309 94.512 42.803 ;
     RECT  77.184 42.709 86.616 42.805 ;
     RECT  76.896 42.805 86.616 42.947 ;
     RECT  40.08 42.755 51.768 42.995 ;
     RECT  7.8 41.605 10.104 42.997 ;
     RECT  27.84 41.699 36.312 43.235 ;
     RECT  69.792 42.085 74.712 43.283 ;
     RECT  2.4 41.941 4.872 43.285 ;
     RECT  37.344 42.083 38.952 43.285 ;
     RECT  2.4 43.285 5.112 43.813 ;
     RECT  68.784 39.923 68.808 43.861 ;
     RECT  69.792 43.283 74.568 43.861 ;
     RECT  2.304 43.813 5.112 43.909 ;
     RECT  27.888 43.235 36.312 43.909 ;
     RECT  37.344 43.285 39.048 43.909 ;
     RECT  27.888 43.909 39.048 44.051 ;
     RECT  11.184 41.939 25.605 44.197 ;
     RECT  7.68 42.997 10.104 44.291 ;
     RECT  40.2 42.995 51.768 44.341 ;
     RECT  52.752 42.755 58.584 44.341 ;
     RECT  60.096 41.363 67.704 44.341 ;
     RECT  40.2 44.341 67.704 44.437 ;
     RECT  68.784 43.861 74.568 44.483 ;
     RECT  11.184 44.197 25.992 44.579 ;
     RECT  88.176 40.595 92.712 44.579 ;
     RECT  40.08 44.437 67.704 44.629 ;
     RECT  75.792 39.395 75.816 44.629 ;
     RECT  94.2 42.803 94.512 44.629 ;
     RECT  2.304 43.909 5.208 44.917 ;
     RECT  69.792 44.483 74.568 44.917 ;
     RECT  37.344 44.051 39.048 44.963 ;
     RECT  37.344 44.963 38.664 45.059 ;
     RECT  40.08 44.629 68.328 45.445 ;
     RECT  69.792 44.917 74.664 45.445 ;
     RECT  22.992 44.579 25.992 45.587 ;
     RECT  2.304 44.917 5.688 45.589 ;
     RECT  75.792 44.629 75.912 45.637 ;
     RECT  7.68 44.291 9.72 45.733 ;
     RECT  77.184 42.947 86.616 45.733 ;
     RECT  7.68 45.733 10.2 45.779 ;
     RECT  88.176 44.579 89.352 45.781 ;
     RECT  90.384 44.579 92.712 45.781 ;
     RECT  40.08 45.445 74.664 45.971 ;
     RECT  69.168 45.971 74.664 45.973 ;
     RECT  75.792 45.637 76.008 45.973 ;
     RECT  2.304 45.589 6.6 46.163 ;
     RECT  40.08 45.971 67.944 46.163 ;
     RECT  69.168 45.973 76.008 46.163 ;
     RECT  77.136 45.733 86.616 46.163 ;
     RECT  10.176 45.779 10.2 46.213 ;
     RECT  11.184 44.579 21.96 46.213 ;
     RECT  40.08 46.163 67.512 46.357 ;
     RECT  69.168 46.163 75.912 46.643 ;
     RECT  7.68 45.779 9.192 46.645 ;
     RECT  2.4 46.163 6.6 46.787 ;
     RECT  39.408 46.357 67.512 46.835 ;
     RECT  37.344 45.059 38.088 46.883 ;
     RECT  39.408 46.835 47.784 47.077 ;
     RECT  71.856 46.643 75.912 47.317 ;
     RECT  77.136 46.163 86.472 47.317 ;
     RECT  88.176 45.781 92.712 47.317 ;
     RECT  93.888 44.629 94.512 47.317 ;
     RECT  10.176 46.213 21.96 47.363 ;
     RECT  71.856 47.317 86.472 47.411 ;
     RECT  88.176 47.317 94.512 47.459 ;
     RECT  69.168 46.643 70.728 47.603 ;
     RECT  2.4 46.787 6.264 47.651 ;
     RECT  90.48 47.459 94.512 47.747 ;
     RECT  69.168 47.603 70.68 47.797 ;
     RECT  27.888 44.051 36.312 47.845 ;
     RECT  4.656 47.651 6.264 47.891 ;
     RECT  22.992 45.587 25.605 47.989 ;
     RECT  27.84 47.845 36.312 48.035 ;
     RECT  27.84 48.035 36.168 48.133 ;
     RECT  68.88 47.797 70.68 48.133 ;
     RECT  93.888 47.747 94.512 48.227 ;
     RECT  27.6 48.133 36.168 48.229 ;
     RECT  27.408 48.229 36.168 48.421 ;
     RECT  39.312 47.077 47.784 48.421 ;
     RECT  5.904 47.891 6.264 48.467 ;
     RECT  76.608 47.411 86.472 48.469 ;
     RECT  11.184 47.363 21.96 48.515 ;
     RECT  88.176 47.459 89.448 48.709 ;
     RECT  68.832 48.133 70.68 48.805 ;
     RECT  22.992 47.989 25.704 48.901 ;
     RECT  26.688 48.421 36.168 48.901 ;
     RECT  68.832 48.805 70.728 48.949 ;
     RECT  76.56 48.469 86.472 48.949 ;
     RECT  76.56 48.949 86.568 48.995 ;
     RECT  16.512 48.515 21.96 48.997 ;
     RECT  22.992 48.901 36.168 48.997 ;
     RECT  37.344 46.883 37.992 48.997 ;
     RECT  39.264 48.421 47.784 48.997 ;
     RECT  87.84 48.709 89.448 49.043 ;
     RECT  90.48 47.747 92.712 49.043 ;
     RECT  16.512 48.997 36.168 49.045 ;
     RECT  37.344 48.997 47.784 49.045 ;
     RECT  10.176 47.363 10.2 49.333 ;
     RECT  11.184 48.515 15.336 49.333 ;
     RECT  16.512 49.045 47.784 49.381 ;
     RECT  48.768 46.835 67.512 49.381 ;
     RECT  6.24 48.467 6.264 49.429 ;
     RECT  7.632 46.645 9.192 49.429 ;
     RECT  76.608 48.995 86.568 49.763 ;
     RECT  90.528 49.043 92.712 49.907 ;
     RECT  68.496 48.949 70.728 49.909 ;
     RECT  71.856 47.411 75.096 49.909 ;
     RECT  68.496 49.909 75.096 50.051 ;
     RECT  6.24 49.429 9.192 50.053 ;
     RECT  6 50.053 9.192 50.099 ;
     RECT  16.512 49.381 67.512 50.147 ;
     RECT  10.176 49.333 15.336 50.293 ;
     RECT  16.512 50.147 21.96 50.293 ;
     RECT  10.176 50.293 21.96 50.435 ;
     RECT  0.192 49.525 0.216 50.725 ;
     RECT  0.192 50.725 0.504 50.771 ;
     RECT  68.592 50.051 75.096 50.965 ;
     RECT  76.608 49.763 86.472 50.965 ;
     RECT  6 50.099 6.024 51.061 ;
     RECT  7.104 50.099 9.192 51.061 ;
     RECT  88.176 49.043 89.448 51.157 ;
     RECT  90.528 49.907 92.664 51.157 ;
     RECT  2.4 47.651 3.672 51.923 ;
     RECT  4.656 47.891 4.872 51.971 ;
     RECT  88.176 51.157 92.664 52.117 ;
     RECT  88.176 52.117 92.952 52.163 ;
     RECT  10.176 50.435 15.336 52.165 ;
     RECT  16.464 50.435 21.96 52.165 ;
     RECT  4.704 51.971 4.872 52.357 ;
     RECT  6 51.061 9.192 52.357 ;
     RECT  2.4 51.923 2.808 52.451 ;
     RECT  22.992 50.147 67.512 52.453 ;
     RECT  10.176 52.165 21.96 52.981 ;
     RECT  22.944 52.453 67.512 52.981 ;
     RECT  10.176 52.981 67.512 53.027 ;
     RECT  68.592 50.965 86.472 53.509 ;
     RECT  39.456 53.027 67.512 53.557 ;
     RECT  68.592 53.509 87 53.557 ;
     RECT  0.48 50.771 0.504 53.653 ;
     RECT  90.384 52.163 92.952 54.037 ;
     RECT  2.4 52.451 2.712 54.085 ;
     RECT  39.456 53.557 87.192 54.085 ;
     RECT  4.704 52.357 9.192 54.275 ;
     RECT  10.176 53.027 37.992 54.371 ;
     RECT  10.176 54.371 21.96 54.419 ;
     RECT  88.176 52.163 89.4 54.469 ;
     RECT  90.384 54.037 93.096 54.469 ;
     RECT  88.176 54.469 93.096 54.661 ;
     RECT  94.2 48.227 94.512 54.661 ;
     RECT  39.312 54.085 87.192 54.707 ;
     RECT  22.992 54.371 37.992 54.709 ;
     RECT  39.936 54.707 87.192 54.803 ;
     RECT  6.624 54.275 9.192 54.899 ;
     RECT  4.704 54.275 5.112 55.045 ;
     RECT  39.936 54.803 85.944 55.379 ;
     RECT  2.4 54.085 2.808 55.381 ;
     RECT  0.144 53.653 0.504 55.571 ;
     RECT  10.512 54.419 21.96 55.715 ;
     RECT  2.304 55.381 2.808 55.907 ;
     RECT  86.976 54.803 87.192 55.955 ;
     RECT  0.144 55.571 0.264 56.003 ;
     RECT  0.192 56.003 0.264 56.051 ;
     RECT  16.368 55.715 21.96 56.051 ;
     RECT  22.992 54.709 38.952 56.245 ;
     RECT  39.936 55.379 68.616 56.245 ;
     RECT  7.8 54.899 9.192 56.483 ;
     RECT  70.224 55.379 85.944 56.629 ;
     RECT  22.992 56.245 68.616 56.675 ;
     RECT  88.176 54.661 94.512 56.723 ;
     RECT  39.792 56.675 68.616 56.725 ;
     RECT  70.128 56.629 85.944 56.725 ;
     RECT  39.792 56.725 85.944 56.963 ;
     RECT  0.192 56.051 0.216 56.965 ;
     RECT  70.128 56.963 85.944 57.011 ;
     RECT  6.624 54.899 6.648 57.013 ;
     RECT  7.8 56.483 8.112 57.013 ;
     RECT  10.512 55.715 15.336 57.013 ;
     RECT  16.512 56.051 21.96 57.013 ;
     RECT  71.856 57.011 85.944 57.059 ;
     RECT  10.512 57.013 21.96 57.157 ;
     RECT  22.992 56.675 37.992 57.157 ;
     RECT  10.512 57.157 37.992 57.443 ;
     RECT  0.144 56.965 0.216 57.445 ;
     RECT  6.624 57.013 8.112 57.589 ;
     RECT  0.144 57.445 0.552 57.635 ;
     RECT  0.528 57.635 0.552 57.731 ;
     RECT  71.856 57.059 85.512 57.731 ;
     RECT  70.128 57.011 70.776 57.779 ;
     RECT  3.936 55.045 5.112 57.973 ;
     RECT  6.624 57.589 8.568 58.021 ;
     RECT  39.792 56.963 68.424 58.309 ;
     RECT  86.976 55.955 87 58.355 ;
     RECT  10.512 57.443 21.96 58.403 ;
     RECT  3.888 57.973 5.112 58.501 ;
     RECT  6.624 58.021 9 58.501 ;
     RECT  88.176 56.723 93.192 58.501 ;
     RECT  22.992 57.443 37.992 58.645 ;
     RECT  39.744 58.309 68.424 58.645 ;
     RECT  87.264 58.501 93.192 58.693 ;
     RECT  94.2 56.723 94.512 58.693 ;
     RECT  11.184 58.403 21.96 58.739 ;
     RECT  74.304 57.731 85.512 58.739 ;
     RECT  70.128 57.779 70.68 58.835 ;
     RECT  15.984 58.739 21.96 58.883 ;
     RECT  2.304 55.907 2.712 59.173 ;
     RECT  3.696 58.501 5.112 59.173 ;
     RECT  6.576 58.501 9 59.221 ;
     RECT  76.368 58.739 85.512 59.269 ;
     RECT  87.264 58.693 94.512 59.315 ;
     RECT  76.368 59.269 85.56 59.747 ;
     RECT  2.304 59.173 5.112 59.795 ;
     RECT  22.992 58.645 68.424 59.795 ;
     RECT  22.992 59.795 38.28 59.891 ;
     RECT  76.608 59.747 85.56 60.275 ;
     RECT  11.184 58.739 14.664 60.421 ;
     RECT  16.512 58.883 21.96 60.421 ;
     RECT  88.176 59.315 94.512 60.467 ;
     RECT  11.184 60.421 21.96 60.517 ;
     RECT  22.992 59.891 35.928 60.517 ;
     RECT  37.056 59.891 38.28 60.805 ;
     RECT  39.792 59.795 68.424 60.805 ;
     RECT  11.184 60.517 35.928 60.949 ;
     RECT  37.056 60.805 68.424 60.949 ;
     RECT  11.184 60.949 68.424 61.043 ;
     RECT  71.856 57.731 72.912 61.333 ;
     RECT  74.304 58.739 75.096 61.333 ;
     RECT  11.184 61.043 37.368 61.379 ;
     RECT  71.856 61.333 75.096 61.427 ;
     RECT  16.512 61.379 37.368 61.523 ;
     RECT  71.904 61.427 75.096 61.525 ;
     RECT  76.608 60.275 85.512 61.525 ;
     RECT  6.288 59.221 9 61.765 ;
     RECT  22.992 61.523 37.368 62.005 ;
     RECT  69.216 61.333 69.24 62.005 ;
     RECT  70.224 58.835 70.68 62.005 ;
     RECT  39.168 61.043 67.608 62.053 ;
     RECT  69.216 62.005 70.68 62.053 ;
     RECT  71.904 61.525 86.328 62.053 ;
     RECT  88.176 60.467 91.464 62.053 ;
     RECT  6.288 61.765 9.528 62.581 ;
     RECT  39.168 62.053 70.68 62.675 ;
     RECT  71.904 62.053 91.464 62.723 ;
     RECT  71.904 62.723 75.288 62.771 ;
     RECT  72.048 62.771 75.288 62.915 ;
     RECT  72.048 62.915 73.032 63.107 ;
     RECT  72.096 63.107 73.032 63.203 ;
     RECT  16.512 61.523 21.96 63.253 ;
     RECT  22.992 62.005 37.704 63.253 ;
     RECT  74.304 62.915 75.288 63.347 ;
     RECT  16.512 63.253 37.704 63.397 ;
     RECT  39.168 62.675 67.608 63.397 ;
     RECT  6.192 62.581 9.528 63.443 ;
     RECT  16.512 63.397 67.608 63.539 ;
     RECT  68.736 62.675 70.68 63.539 ;
     RECT  11.184 61.379 15.24 63.637 ;
     RECT  16.512 63.539 67.512 63.637 ;
     RECT  2.4 59.795 5.112 63.731 ;
     RECT  74.304 63.347 75.096 63.827 ;
     RECT  76.608 62.723 91.464 63.827 ;
     RECT  11.184 63.637 67.512 63.875 ;
     RECT  6.288 63.443 9.528 63.923 ;
     RECT  22.992 63.875 67.512 63.923 ;
     RECT  69.696 63.539 70.68 64.069 ;
     RECT  72.096 63.203 72.912 64.069 ;
     RECT  69.696 64.069 72.912 64.165 ;
     RECT  69.696 64.165 73.224 64.211 ;
     RECT  11.184 63.875 21.96 64.355 ;
     RECT  11.184 64.355 14.664 64.357 ;
     RECT  38.352 63.923 67.512 64.835 ;
     RECT  6.288 63.923 9 64.885 ;
     RECT  92.544 60.467 94.512 64.931 ;
     RECT  11.088 64.357 14.664 64.933 ;
     RECT  10.848 64.933 14.664 65.075 ;
     RECT  69.696 64.211 70.68 65.075 ;
     RECT  38.592 64.835 67.512 65.123 ;
     RECT  72.096 64.211 73.224 65.125 ;
     RECT  74.352 63.827 75.096 65.125 ;
     RECT  39.168 65.123 67.512 65.219 ;
     RECT  22.992 63.923 37.368 65.269 ;
     RECT  70.224 65.075 70.68 65.413 ;
     RECT  72.096 65.125 75.096 65.413 ;
     RECT  76.608 63.827 86.328 65.461 ;
     RECT  39.36 65.219 67.512 65.507 ;
     RECT  16.032 64.355 21.96 65.509 ;
     RECT  6 64.885 9 65.557 ;
     RECT  11.088 65.075 14.664 65.603 ;
     RECT  70.224 65.413 75.096 65.939 ;
     RECT  6 65.557 9.576 66.179 ;
     RECT  39.36 65.507 49.704 66.179 ;
     RECT  39.36 66.179 49.464 66.325 ;
     RECT  6.288 66.179 9.576 66.515 ;
     RECT  39.264 66.325 49.464 66.517 ;
     RECT  88.176 63.827 91.464 66.707 ;
     RECT  88.176 66.707 91.224 66.803 ;
     RECT  76.512 65.461 86.328 66.853 ;
     RECT  22.992 65.269 37.512 66.947 ;
     RECT  39.216 66.517 49.464 67.045 ;
     RECT  38.784 67.045 49.464 67.139 ;
     RECT  38.784 67.139 38.808 67.237 ;
     RECT  74.352 65.939 75.096 67.237 ;
     RECT  15.984 65.509 21.96 67.283 ;
     RECT  70.224 65.939 72.912 67.283 ;
     RECT  38.736 67.237 38.808 67.381 ;
     RECT  74.352 67.237 75.48 67.571 ;
     RECT  39.792 67.139 49.464 67.765 ;
     RECT  51 65.507 67.512 67.765 ;
     RECT  88.176 66.803 90.552 67.813 ;
     RECT  38.544 67.381 38.808 67.859 ;
     RECT  70.224 67.283 71.304 67.859 ;
     RECT  74.352 67.571 75.384 67.859 ;
     RECT  11.184 65.603 14.664 68.149 ;
     RECT  88.176 67.813 90.6 68.195 ;
     RECT  72.48 67.283 72.912 68.197 ;
     RECT  68.976 68.101 69 68.243 ;
     RECT  94.2 64.931 94.512 68.293 ;
     RECT  75.072 67.859 75.384 68.339 ;
     RECT  92.544 64.931 92.76 68.435 ;
     RECT  11.184 68.149 15.384 68.677 ;
     RECT  38.688 67.859 38.808 68.677 ;
     RECT  39.792 67.765 67.512 68.677 ;
     RECT  76.512 66.853 86.568 68.821 ;
     RECT  88.176 68.195 90.552 68.821 ;
     RECT  11.184 68.677 15.48 68.917 ;
     RECT  76.512 68.821 90.552 68.963 ;
     RECT  76.512 68.963 86.568 69.251 ;
     RECT  38.688 68.677 67.512 69.443 ;
     RECT  16.464 67.283 21.96 69.445 ;
     RECT  22.992 66.947 37.368 69.445 ;
     RECT  72.48 68.197 73.032 69.493 ;
     RECT  38.736 69.443 67.512 69.635 ;
     RECT  76.512 69.251 86.424 69.971 ;
     RECT  71.04 67.859 71.304 69.973 ;
     RECT  10.608 68.917 15.48 70.067 ;
     RECT  6.288 66.515 9 70.069 ;
     RECT  10.608 70.067 15.144 70.115 ;
     RECT  16.464 69.445 37.368 70.117 ;
     RECT  16.32 70.117 37.368 70.211 ;
     RECT  6.288 70.069 9.048 70.309 ;
     RECT  70.368 69.973 71.496 70.309 ;
     RECT  72.48 69.493 73.56 70.309 ;
     RECT  75.072 68.339 75.336 70.357 ;
     RECT  76.512 69.971 86.376 70.357 ;
     RECT  38.736 69.635 38.76 70.403 ;
     RECT  87.552 68.963 90.552 70.501 ;
     RECT  92.544 68.435 92.568 70.501 ;
     RECT  93.744 68.293 94.512 70.501 ;
     RECT  92.544 70.501 94.512 70.643 ;
     RECT  6.288 70.309 9.24 70.691 ;
     RECT  70.368 70.309 73.56 70.691 ;
     RECT  2.4 63.731 4.536 70.739 ;
     RECT  87.552 70.501 90.984 70.739 ;
     RECT  70.368 70.691 71.304 71.075 ;
     RECT  6.288 70.691 9.048 71.315 ;
     RECT  39.792 69.635 67.512 71.413 ;
     RECT  69.024 70.405 69.048 71.651 ;
     RECT  11.184 70.115 15.144 71.845 ;
     RECT  10.752 71.845 15.144 71.941 ;
     RECT  16.32 70.211 21.96 71.941 ;
     RECT  72.432 70.691 73.56 71.941 ;
     RECT  2.4 70.739 4.44 71.989 ;
     RECT  88.176 70.739 90.984 71.989 ;
     RECT  70.608 71.075 71.304 72.083 ;
     RECT  10.752 71.941 21.96 72.179 ;
     RECT  87.792 71.989 90.984 72.227 ;
     RECT  10.752 72.179 15.144 72.277 ;
     RECT  71.04 72.083 71.304 72.325 ;
     RECT  72.384 71.941 73.56 72.325 ;
     RECT  92.544 70.643 92.568 72.325 ;
     RECT  22.992 70.211 37.368 72.421 ;
     RECT  75.072 70.357 86.376 72.421 ;
     RECT  69.12 71.653 69.144 72.563 ;
     RECT  2.304 71.989 4.44 72.565 ;
     RECT  22.992 72.421 38.088 72.803 ;
     RECT  74.544 72.421 86.376 72.805 ;
     RECT  87.792 72.227 90.552 72.805 ;
     RECT  6.288 71.315 9 72.949 ;
     RECT  39.696 71.413 67.512 72.949 ;
     RECT  74.544 72.805 90.552 72.995 ;
     RECT  39.696 72.949 67.848 73.333 ;
     RECT  10.608 72.277 15.144 73.381 ;
     RECT  16.32 72.179 21.96 73.381 ;
     RECT  87.264 72.995 90.552 73.427 ;
     RECT  91.968 72.325 92.568 73.621 ;
     RECT  2.304 72.565 4.968 73.861 ;
     RECT  6.288 72.949 9.096 73.861 ;
     RECT  10.608 73.381 21.96 73.907 ;
     RECT  2.304 73.861 9.096 74.003 ;
     RECT  71.04 72.325 73.56 74.005 ;
     RECT  39.024 73.333 67.848 74.339 ;
     RECT  22.992 72.803 37.608 74.627 ;
     RECT  69.648 74.053 69.672 74.629 ;
     RECT  70.896 74.005 73.56 74.629 ;
     RECT  87.792 73.427 90.552 74.629 ;
     RECT  74.544 72.995 85.992 74.771 ;
     RECT  87.648 74.629 90.552 74.771 ;
     RECT  10.608 73.907 11.208 74.869 ;
     RECT  69.648 74.629 73.56 75.013 ;
     RECT  68.88 75.013 73.56 75.059 ;
     RECT  10.224 74.869 11.208 75.109 ;
     RECT  12.336 73.907 21.96 75.109 ;
     RECT  93.6 70.643 94.512 75.251 ;
     RECT  91.584 73.621 92.568 75.253 ;
     RECT  88.176 74.771 90.552 75.397 ;
     RECT  91.584 75.253 92.76 75.397 ;
     RECT  39.024 74.339 67.512 75.685 ;
     RECT  68.88 75.059 73.176 75.875 ;
     RECT  10.224 75.109 21.96 75.923 ;
     RECT  88.176 75.397 92.76 76.067 ;
     RECT  39.024 75.685 67.608 76.069 ;
     RECT  2.304 74.003 9 76.117 ;
     RECT  10.224 75.923 15.096 76.117 ;
     RECT  71.04 75.875 73.176 76.213 ;
     RECT  74.544 74.771 85.512 76.213 ;
     RECT  93.84 75.251 94.512 76.309 ;
     RECT  2.304 76.117 15.096 76.403 ;
     RECT  16.08 75.923 21.96 76.403 ;
     RECT  38.592 76.069 67.608 76.405 ;
     RECT  10.224 76.403 15.096 76.451 ;
     RECT  38.592 76.405 67.704 76.931 ;
     RECT  38.592 76.931 67.656 76.979 ;
     RECT  68.88 75.875 69.672 76.979 ;
     RECT  71.04 76.213 85.512 76.981 ;
     RECT  86.928 75.877 86.952 76.981 ;
     RECT  88.176 76.067 92.568 77.027 ;
     RECT  90.384 77.027 92.568 77.029 ;
     RECT  93.696 76.309 94.512 77.029 ;
     RECT  68.976 76.979 69.672 77.125 ;
     RECT  71.04 76.981 86.952 77.219 ;
     RECT  68.976 77.125 70.008 77.267 ;
     RECT  86.928 77.219 86.952 77.555 ;
     RECT  10.224 76.451 14.952 77.603 ;
     RECT  39.024 76.979 67.656 78.037 ;
     RECT  90.384 77.029 94.512 78.131 ;
     RECT  38.784 78.037 67.656 78.133 ;
     RECT  69.648 77.267 70.008 78.277 ;
     RECT  12.336 77.603 14.952 78.371 ;
     RECT  69.456 78.277 70.008 78.421 ;
     RECT  71.04 77.219 85.512 78.421 ;
     RECT  69.456 78.421 85.512 78.467 ;
     RECT  16.224 76.403 21.96 78.565 ;
     RECT  12.336 78.371 14.808 78.611 ;
     RECT  15.936 78.565 21.96 78.613 ;
     RECT  22.992 74.627 37.368 78.613 ;
     RECT  15.936 78.613 37.368 78.899 ;
     RECT  88.176 77.027 89.352 78.901 ;
     RECT  2.304 76.403 9.192 79.189 ;
     RECT  10.224 77.603 11.208 79.189 ;
     RECT  69.456 78.467 73.512 79.283 ;
     RECT  69.552 79.283 73.512 79.379 ;
     RECT  88.176 78.901 89.4 79.477 ;
     RECT  72.6 79.379 73.512 79.525 ;
     RECT  74.544 78.467 85.512 79.525 ;
     RECT  88.176 79.477 89.448 79.765 ;
     RECT  16.224 78.899 37.368 79.859 ;
     RECT  87.216 79.765 89.448 79.859 ;
     RECT  88.704 79.859 89.448 79.907 ;
     RECT  2.304 79.189 11.208 79.957 ;
     RECT  12.336 78.611 14.76 79.957 ;
     RECT  87.216 79.859 87.24 80.053 ;
     RECT  90.48 78.131 94.512 80.099 ;
     RECT  69.552 79.379 71.304 80.243 ;
     RECT  90.48 80.099 91.176 80.243 ;
     RECT  22.992 79.859 37.368 80.389 ;
     RECT  38.784 78.133 67.704 80.389 ;
     RECT  16.224 79.859 21.96 80.435 ;
     RECT  22.992 80.389 67.704 80.435 ;
     RECT  39.168 80.435 67.704 80.773 ;
     RECT  2.304 79.957 14.76 80.867 ;
     RECT  69.792 80.243 71.304 80.869 ;
     RECT  72.6 79.525 85.512 80.869 ;
     RECT  2.304 80.867 14.52 80.915 ;
     RECT  88.704 79.907 89.256 81.155 ;
     RECT  69.792 80.869 85.512 81.539 ;
     RECT  70.08 81.539 85.512 81.587 ;
     RECT  16.32 80.435 21.96 81.925 ;
     RECT  72.192 81.587 85.512 82.019 ;
     RECT  11.088 80.915 14.52 82.115 ;
     RECT  92.544 80.099 94.512 82.115 ;
     RECT  39.168 80.773 67.992 82.163 ;
     RECT  15.552 81.925 21.96 82.309 ;
     RECT  22.992 80.435 37.992 82.309 ;
     RECT  2.304 80.915 9.624 82.453 ;
     RECT  15.552 82.309 37.992 82.549 ;
     RECT  39.168 82.163 67.8 82.549 ;
     RECT  15.552 82.549 67.8 82.691 ;
     RECT  88.8 81.155 89.256 82.691 ;
     RECT  16.08 82.691 67.8 82.931 ;
     RECT  86.832 80.053 87.24 82.981 ;
     RECT  70.08 81.587 71.064 83.123 ;
     RECT  86.832 82.981 87.576 83.123 ;
     RECT  16.32 82.931 67.8 83.219 ;
     RECT  16.512 83.219 67.8 83.267 ;
     RECT  68.928 82.405 68.952 83.267 ;
     RECT  90.48 80.243 91.128 83.461 ;
     RECT  90.48 83.461 91.272 83.653 ;
     RECT  93.504 82.115 94.512 83.701 ;
     RECT  72.6 82.019 85.512 83.749 ;
     RECT  86.832 83.123 87.24 83.795 ;
     RECT  2.304 82.453 9.672 83.843 ;
     RECT  11.088 82.115 13.752 83.843 ;
     RECT  2.304 83.843 9.624 83.987 ;
     RECT  2.304 83.987 9.528 84.133 ;
     RECT  11.088 83.843 11.208 84.133 ;
     RECT  10.752 84.133 11.208 84.517 ;
     RECT  12.336 83.843 13.752 84.563 ;
     RECT  2.064 84.133 9.528 84.709 ;
     RECT  39.168 83.267 63.768 84.755 ;
     RECT  10.656 84.517 11.208 84.805 ;
     RECT  92.88 83.701 94.512 84.851 ;
     RECT  1.68 84.709 9.528 84.853 ;
     RECT  10.656 84.805 11.688 84.853 ;
     RECT  86.832 83.795 86.856 84.853 ;
     RECT  13.2 84.563 13.752 84.947 ;
     RECT  16.512 83.267 37.992 84.995 ;
     RECT  48.768 84.755 63.768 84.995 ;
     RECT  34.8 84.995 37.992 85.045 ;
     RECT  39.168 84.755 47.592 85.045 ;
     RECT  71.04 83.123 71.064 85.093 ;
     RECT  72.24 83.749 85.512 85.093 ;
     RECT  34.8 85.045 47.592 85.475 ;
     RECT  64.752 83.267 67.8 85.523 ;
     RECT  10.608 84.853 11.688 85.667 ;
     RECT  90.48 83.653 91.56 85.813 ;
     RECT  16.512 84.995 33.768 85.957 ;
     RECT  34.8 85.475 38.136 85.957 ;
     RECT  86.64 84.853 86.856 86.005 ;
     RECT  86.64 86.005 87.24 86.051 ;
     RECT  10.656 85.667 11.688 86.195 ;
     RECT  64.752 85.523 65.064 86.485 ;
     RECT  66.048 85.523 67.8 86.485 ;
     RECT  16.512 85.957 38.136 86.579 ;
     RECT  90.48 85.813 92.04 86.627 ;
     RECT  10.752 86.195 11.688 86.675 ;
     RECT  13.2 84.947 13.608 86.725 ;
     RECT  48.768 84.995 63.72 86.725 ;
     RECT  64.752 86.485 67.8 86.725 ;
     RECT  16.512 86.579 35.112 86.771 ;
     RECT  86.832 86.051 87.24 86.771 ;
     RECT  36.24 86.579 38.136 87.109 ;
     RECT  39.168 85.475 47.592 87.109 ;
     RECT  11.088 86.675 11.688 87.205 ;
     RECT  12.672 86.725 13.608 87.205 ;
     RECT  87.168 86.771 87.24 87.251 ;
     RECT  48.768 86.725 67.8 87.253 ;
     RECT  48.624 87.253 67.8 87.299 ;
     RECT  90.48 86.627 91.56 87.299 ;
     RECT  36.24 87.109 47.592 87.301 ;
     RECT  48.624 87.299 63.72 87.301 ;
     RECT  69.984 86.581 70.008 87.539 ;
     RECT  88.8 82.691 89.112 87.589 ;
     RECT  11.088 87.205 13.608 87.781 ;
     RECT  88.8 87.589 89.208 87.875 ;
     RECT  36.24 87.301 63.72 88.115 ;
     RECT  64.752 87.299 67.8 88.115 ;
     RECT  1.296 84.853 9.528 88.163 ;
     RECT  34.8 86.771 35.112 88.213 ;
     RECT  71.04 85.093 85.512 88.403 ;
     RECT  93.792 84.851 94.512 88.403 ;
     RECT  90.864 87.299 91.56 88.595 ;
     RECT  16.512 86.771 33.768 88.643 ;
     RECT  18.6 88.643 33.768 88.739 ;
     RECT  34.8 88.213 35.208 88.837 ;
     RECT  36.24 88.115 63.144 88.837 ;
     RECT  34.8 88.837 63.144 88.883 ;
     RECT  9.12 88.163 9.528 88.931 ;
     RECT  11.088 87.781 14.328 88.931 ;
     RECT  90.864 88.595 91.32 88.931 ;
     RECT  64.752 88.115 64.776 88.979 ;
     RECT  87.168 87.251 87.192 89.173 ;
     RECT  34.8 88.883 36.36 89.219 ;
     RECT  9.264 88.931 9.528 89.459 ;
     RECT  65.808 88.115 67.8 89.507 ;
     RECT  65.808 89.507 67.512 89.509 ;
     RECT  64.944 89.509 67.512 89.555 ;
     RECT  34.8 89.219 36.264 89.603 ;
     RECT  11.088 88.931 13.752 89.699 ;
     RECT  90.864 88.931 91.272 89.795 ;
     RECT  13.2 89.699 13.752 89.987 ;
     RECT  87.168 89.173 87.576 90.083 ;
     RECT  19.968 88.739 33.768 90.227 ;
     RECT  87.552 90.083 87.576 90.227 ;
     RECT  11.088 89.699 11.688 90.275 ;
     RECT  37.344 88.883 63.144 90.275 ;
     RECT  37.344 90.275 62.952 90.419 ;
     RECT  88.8 87.875 89.112 90.565 ;
     RECT  15.456 89.461 15.48 90.659 ;
     RECT  71.04 88.403 78.312 91.141 ;
     RECT  79.296 88.403 85.512 91.141 ;
     RECT  37.344 90.419 38.664 91.235 ;
     RECT  90.864 89.795 90.888 91.235 ;
     RECT  64.944 89.555 64.968 91.283 ;
     RECT  88.704 90.565 89.112 91.379 ;
     RECT  66.048 89.555 67.512 91.477 ;
     RECT  37.344 91.235 38.184 91.669 ;
     RECT  9.504 89.459 9.528 91.717 ;
     RECT  11.184 90.275 11.688 91.717 ;
     RECT  39.648 90.419 62.952 91.811 ;
     RECT  63.984 91.477 64.008 91.859 ;
     RECT  66.048 91.477 68.136 92.147 ;
     RECT  9.504 91.717 11.688 92.195 ;
     RECT  34.8 89.603 35.88 92.195 ;
     RECT  37.056 91.669 38.184 92.245 ;
     RECT  86.832 91.717 86.856 92.291 ;
     RECT  18.6 88.739 18.912 92.293 ;
     RECT  20.688 90.227 33.768 92.293 ;
     RECT  37.056 92.245 38.52 92.435 ;
     RECT  1.296 88.163 8.112 92.677 ;
     RECT  88.8 91.379 89.112 92.677 ;
     RECT  66.624 92.147 68.136 92.771 ;
     RECT  9.504 92.195 9.72 92.819 ;
     RECT  18.6 92.293 33.768 92.819 ;
     RECT  18.6 92.819 33.672 92.869 ;
     RECT  66.624 92.771 67.512 92.963 ;
     RECT  70.896 91.141 85.512 92.963 ;
     RECT  37.056 92.435 37.368 93.011 ;
     RECT  38.496 92.435 38.52 93.299 ;
     RECT  18.48 92.869 33.672 93.347 ;
     RECT  18.6 93.347 33.672 93.395 ;
     RECT  9.696 92.819 9.72 93.491 ;
     RECT  67.056 92.963 67.512 93.491 ;
     RECT  11.184 92.195 11.688 93.539 ;
     RECT  16.512 88.643 17.304 93.827 ;
     RECT  1.296 92.677 8.232 94.021 ;
     RECT  91.584 91.333 91.608 94.067 ;
     RECT  34.8 92.195 35.256 94.115 ;
     RECT  1.296 94.021 8.28 94.451 ;
     RECT  88.56 92.677 89.112 94.595 ;
     RECT  1.296 94.451 8.232 94.643 ;
     RECT  34.8 94.115 35.208 94.643 ;
     RECT  69.552 93.397 69.576 94.691 ;
     RECT  37.344 93.011 37.368 94.837 ;
     RECT  71.04 92.963 85.512 94.883 ;
     RECT  36.72 94.837 37.368 94.979 ;
     RECT  1.296 94.643 8.112 95.049 ;
     RECT  13.2 89.987 13.512 95.049 ;
     RECT  18.6 93.395 18.912 95.049 ;
     RECT  34.8 94.643 35.112 95.049 ;
     RECT  67.2 93.491 67.512 95.049 ;
     RECT  78 94.883 85.512 95.049 ;
     RECT  88.8 94.595 89.112 95.049 ;
     RECT  94.2 88.403 94.512 95.049 ;
     RECT  1.296 95.049 7.92 95.063 ;
     RECT  13.2 95.049 13.32 95.063 ;
     RECT  18.6 95.049 18.72 95.063 ;
     RECT  34.8 95.049 34.92 95.063 ;
     RECT  67.2 95.049 67.32 95.063 ;
     RECT  78 95.049 78.12 95.063 ;
     RECT  88.8 95.049 88.92 95.063 ;
     RECT  94.2 95.049 94.32 95.063 ;
     RECT  36.816 94.979 37.368 95.171 ;
     RECT  20.688 93.395 33.672 95.507 ;
     RECT  37.344 95.171 37.368 95.507 ;
     RECT  71.04 94.883 76.968 95.507 ;
     RECT  79.248 95.049 85.512 95.651 ;
     RECT  79.248 95.651 85.08 95.699 ;
     RECT  16.512 93.827 16.536 96.035 ;
     RECT  39.696 91.811 62.952 96.323 ;
     RECT  79.248 95.699 85.032 96.323 ;
     RECT  20.688 95.507 32.904 96.325 ;
     RECT  71.184 95.507 76.968 96.325 ;
     RECT  71.184 96.325 77.064 96.373 ;
     RECT  71.184 96.373 77.16 96.469 ;
     RECT  20.496 96.325 32.904 96.995 ;
     RECT  39.696 96.323 62.568 97.043 ;
     RECT  20.496 96.995 32.856 97.091 ;
     RECT  79.248 96.323 84.264 97.091 ;
     RECT  1.296 95.063 7.368 97.168 ;
     RECT  20.496 97.091 32.712 97.168 ;
     RECT  39.696 97.043 61.992 97.168 ;
     RECT  71.184 96.469 77.256 97.168 ;
     RECT  79.248 97.091 84.168 97.168 ;
     RECT  11.184 93.539 11.208 97.187 ;
     RECT  61.968 97.168 61.992 97.187 ;
  END
END ot_pqc_t_qb
END LIBRARY
